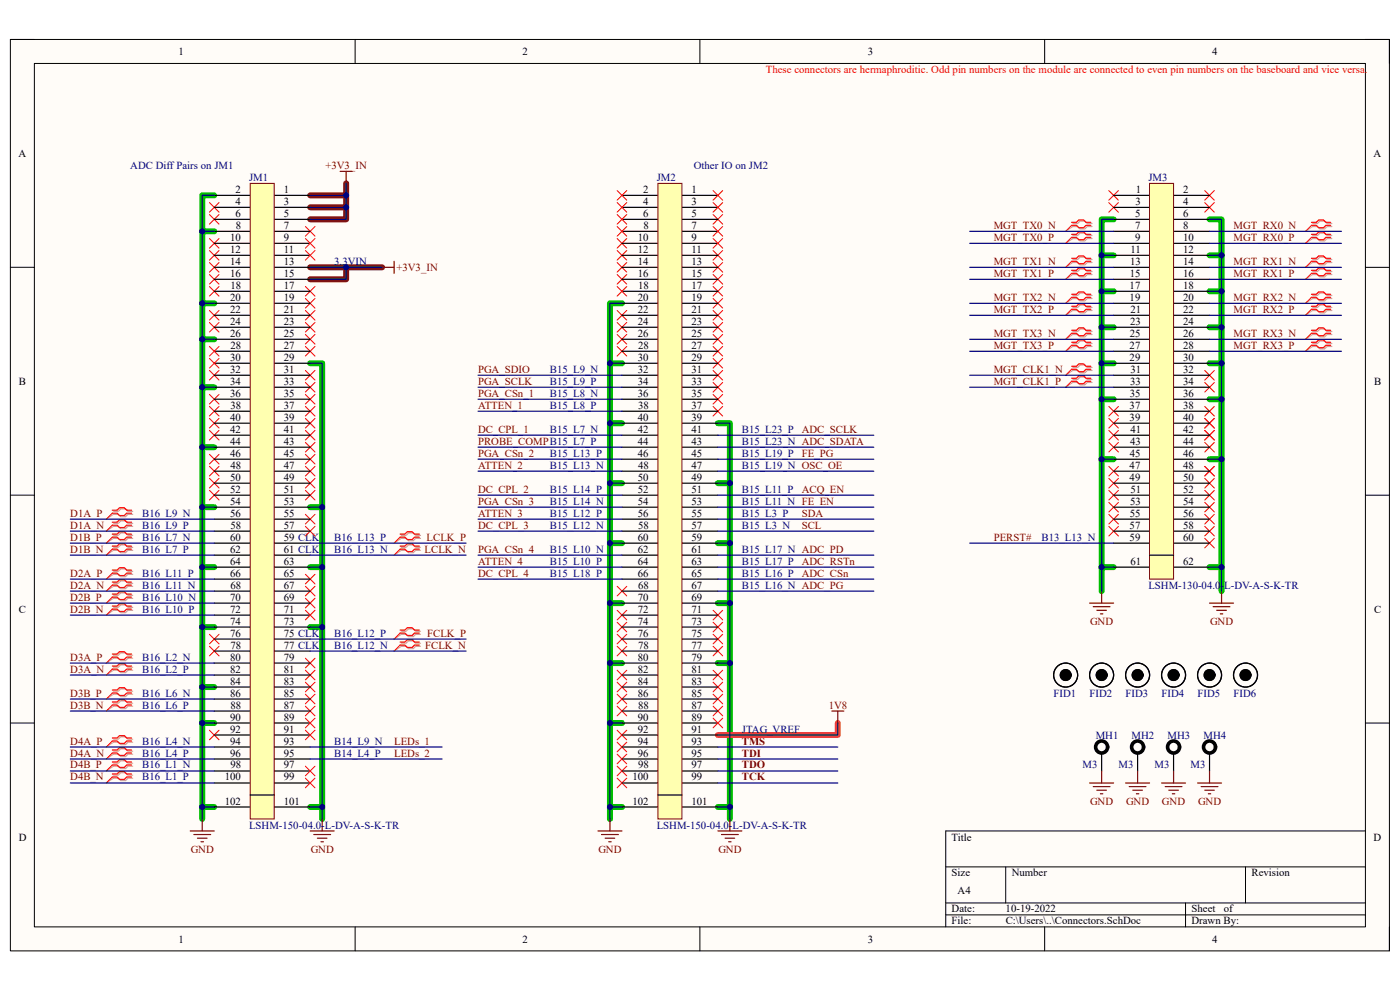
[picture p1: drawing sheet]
<svg xmlns="http://www.w3.org/2000/svg" width="297mm" height="210mm" viewBox="0 0 297 210" stroke-linecap="round" stroke-linejoin="round" font-family="sans-serif">
<defs><g id="words">
<g font-size="2.3">
<text x="37.9" y="11.7">1</text>
<text x="110.9" y="11.7">2</text>
<text x="184.1" y="11.7">3</text>
<text x="257.1" y="11.7">4</text>
<text x="3.9" y="33.3">A</text>
<text x="291.4" y="33.3">A</text>
<text x="50" y="40.9">2</text>
<text x="60.2" y="40.9">1</text>
<text x="136.5" y="40.9">2</text>
<text x="146.7" y="40.9">1</text>
<text x="241" y="40.9">1</text>
<text x="251" y="40.9">2</text>
<text x="50" y="43.5">4</text>
<text x="50" y="46">6</text>
<text x="60.2" y="43.5">3</text>
<text x="60.2" y="46">5</text>
<text x="136.5" y="43.5">4</text>
<text x="136.5" y="46">6</text>
<text x="146.7" y="43.5">3</text>
<text x="146.7" y="46">5</text>
<text x="240.8" y="46">5</text>
<text x="240.9" y="43.5">3</text>
<text x="251" y="43.5">4</text>
<text x="251" y="46">6</text>
<text x="48.8" y="51.1">10</text>
<text x="48.9" y="53.6">12</text>
<text x="50" y="48.6">8</text>
<text x="60.2" y="48.6">7</text>
<text x="60.2" y="51.1">9</text>
<text x="60.2" y="53.6">11</text>
<text x="135.3" y="51.1">10</text>
<text x="135.3" y="53.6">12</text>
<text x="136.5" y="48.6">8</text>
<text x="146.7" y="48.6">7</text>
<text x="146.7" y="51.1">9</text>
<text x="146.7" y="53.6">11</text>
<text x="239.8" y="53.6">11</text>
<text x="240.8" y="48.6">7</text>
<text x="240.8" y="51.1">9</text>
<text x="251" y="48.6">8</text>
<text x="251" y="51.1">10</text>
<text x="251" y="53.6">12</text>
<text x="48.8" y="56.2">14</text>
<text x="48.9" y="58.7">16</text>
<text x="60.2" y="56.2">13</text>
<text x="60.2" y="58.7">15</text>
<text x="135.3" y="56.2">14</text>
<text x="135.3" y="58.7">16</text>
<text x="146.7" y="56.2">13</text>
<text x="146.7" y="58.7">15</text>
<text x="239.7" y="58.7">15</text>
<text x="239.7" y="56.2">13</text>
<text x="251" y="56.2">14</text>
<text x="251" y="58.7">16</text>
<text x="48.8" y="63.8">20</text>
<text x="48.9" y="61.3">18</text>
<text x="60.2" y="61.3">17</text>
<text x="60.2" y="63.8">19</text>
<text x="135.3" y="63.8">20</text>
<text x="135.4" y="61.3">18</text>
<text x="146.7" y="61.3">17</text>
<text x="146.7" y="63.8">19</text>
<text x="239.6" y="61.3">17</text>
<text x="239.6" y="63.8">19</text>
<text x="251" y="61.3">18</text>
<text x="251" y="63.8">20</text>
<text x="48.8" y="68.9">24</text>
<text x="48.9" y="66.4">22</text>
<text x="48.9" y="71.5">26</text>
<text x="60.2" y="66.4">21</text>
<text x="60.2" y="68.9">23</text>
<text x="60.2" y="71.5">25</text>
<text x="135.3" y="66.4">22</text>
<text x="135.3" y="68.9">24</text>
<text x="135.3" y="71.5">26</text>
<text x="146.7" y="66.4">21</text>
<text x="146.7" y="68.9">23</text>
<text x="146.7" y="71.5">25</text>
<text x="239.7" y="71.5">25</text>
<text x="239.7" y="68.9">23</text>
<text x="239.8" y="66.4">21</text>
<text x="251" y="66.4">22</text>
<text x="251" y="68.9">24</text>
<text x="251" y="71.5">26</text>
<text x="48.8" y="76.5">30</text>
<text x="48.9" y="74">28</text>
<text x="60.2" y="74">27</text>
<text x="60.2" y="76.5">29</text>
<text x="135.3" y="76.5">30</text>
<text x="135.4" y="74">28</text>
<text x="146.7" y="74">27</text>
<text x="146.7" y="76.5">29</text>
<text x="239.6" y="74">27</text>
<text x="239.6" y="76.5">29</text>
<text x="251" y="74">28</text>
<text x="251" y="76.5">30</text>
<text x="4" y="81.6">B</text>
<text x="48.8" y="81.6">34</text>
<text x="48.9" y="79.1">32</text>
<text x="60.2" y="79.1">31</text>
<text x="60.2" y="81.6">33</text>
<text x="135.3" y="79.1">32</text>
<text x="135.3" y="81.6">34</text>
<text x="146.7" y="79.1">31</text>
<text x="146.7" y="81.6">33</text>
<text x="239.7" y="81.6">33</text>
<text x="239.8" y="79.1">31</text>
<text x="251" y="79.1">32</text>
<text x="251" y="81.6">34</text>
<text x="291.5" y="81.6">B</text>
<text x="48.8" y="89.3">40</text>
<text x="48.9" y="84.2">36</text>
<text x="48.9" y="86.7">38</text>
<text x="60.2" y="84.2">35</text>
<text x="60.2" y="86.7">37</text>
<text x="60.2" y="89.3">39</text>
<text x="135.3" y="84.2">36</text>
<text x="135.3" y="89.3">40</text>
<text x="135.4" y="86.7">38</text>
<text x="146.7" y="84.2">35</text>
<text x="146.7" y="86.7">37</text>
<text x="146.7" y="89.3">39</text>
<text x="239.6" y="86.7">37</text>
<text x="239.6" y="89.3">39</text>
<text x="239.7" y="84.2">35</text>
<text x="251" y="84.2">36</text>
<text x="251" y="86.7">38</text>
<text x="251" y="89.3">40</text>
<text x="48.8" y="94.4">44</text>
<text x="48.9" y="91.8">42</text>
<text x="60.2" y="91.8">41</text>
<text x="60.2" y="94.4">43</text>
<text x="135.3" y="91.8">42</text>
<text x="135.3" y="94.4">44</text>
<text x="146.7" y="91.8">41</text>
<text x="146.7" y="94.4">43</text>
<text x="239.7" y="94.4">43</text>
<text x="239.8" y="91.8">41</text>
<text x="251" y="91.8">42</text>
<text x="251" y="94.4">44</text>
<text x="48.8" y="102">50</text>
<text x="48.9" y="96.9">46</text>
<text x="48.9" y="99.4">48</text>
<text x="60.2" y="96.9">45</text>
<text x="60.2" y="99.4">47</text>
<text x="60.2" y="102">49</text>
<text x="135.3" y="96.9">46</text>
<text x="135.3" y="102">50</text>
<text x="135.4" y="99.4">48</text>
<text x="146.7" y="96.9">45</text>
<text x="146.7" y="99.4">47</text>
<text x="146.7" y="102">49</text>
<text x="239.6" y="99.4">47</text>
<text x="239.6" y="102">49</text>
<text x="239.7" y="96.9">45</text>
<text x="251" y="96.9">46</text>
<text x="251" y="99.4">48</text>
<text x="251" y="102">50</text>
<text x="48.8" y="107.1">54</text>
<text x="48.9" y="104.5">52</text>
<text x="60.2" y="104.5">51</text>
<text x="60.2" y="107.1">53</text>
<text x="135.3" y="104.5">52</text>
<text x="135.3" y="107.1">54</text>
<text x="146.7" y="104.5">51</text>
<text x="146.7" y="107.1">53</text>
<text x="239.7" y="107.1">53</text>
<text x="239.8" y="104.5">51</text>
<text x="251" y="104.5">52</text>
<text x="251" y="107.1">54</text>
<text x="48.9" y="109.6">56</text>
<text x="48.9" y="112.1">58</text>
<text x="60.2" y="109.6">55</text>
<text x="60.2" y="112.1">57</text>
<text x="135.3" y="109.6">56</text>
<text x="135.4" y="112.1">58</text>
<text x="146.7" y="109.6">55</text>
<text x="146.7" y="112.1">57</text>
<text x="239.6" y="112.1">57</text>
<text x="239.7" y="109.6">55</text>
<text x="251" y="109.6">56</text>
<text x="251" y="112.1">58</text>
<text x="48.8" y="114.7">60</text>
<text x="48.8" y="119.8">64</text>
<text x="48.9" y="117.3">62</text>
<text x="60.2" y="114.7">59 CLK</text>
<text x="60.2" y="117.3">61 CLK</text>
<text x="60.2" y="119.8">63</text>
<text x="135.3" y="114.7">60</text>
<text x="135.3" y="117.3">62</text>
<text x="135.3" y="119.8">64</text>
<text x="146.7" y="114.7">59</text>
<text x="146.7" y="117.3">61</text>
<text x="146.7" y="119.8">63</text>
<text x="239.6" y="114.7">59</text>
<text x="239.8" y="119.8">61</text>
<text x="251" y="114.7">60</text>
<text x="251" y="119.8">62</text>
<text x="48.9" y="122.3">66</text>
<text x="48.9" y="124.9">68</text>
<text x="60.2" y="122.3">65</text>
<text x="60.2" y="124.9">67</text>
<text x="135.3" y="122.3">66</text>
<text x="135.4" y="124.9">68</text>
<text x="146.7" y="122.3">65</text>
<text x="146.7" y="124.9">67</text>
<text x="4" y="130">C</text>
<text x="48.8" y="127.4">70</text>
<text x="48.9" y="130">72</text>
<text x="60.2" y="127.4">69</text>
<text x="60.2" y="130">71</text>
<text x="135.3" y="127.4">70</text>
<text x="135.3" y="130">72</text>
<text x="146.7" y="127.4">69</text>
<text x="146.7" y="130">71</text>
<text x="291.5" y="130">C</text>
<text x="48.8" y="132.5">74</text>
<text x="48.9" y="135">76</text>
<text x="48.9" y="137.6">78</text>
<text x="60.2" y="132.5">73</text>
<text x="60.2" y="135">75 CLK</text>
<text x="60.2" y="137.6">77 CLK</text>
<text x="135.3" y="132.5">74</text>
<text x="135.3" y="135">76</text>
<text x="135.4" y="137.6">78</text>
<text x="146.7" y="132.5">73</text>
<text x="146.7" y="135">75</text>
<text x="146.7" y="137.6">77</text>
<text x="48.8" y="140.1">80</text>
<text x="48.9" y="142.7">82</text>
<text x="60.2" y="140.1">79</text>
<text x="60.2" y="142.7">81</text>
<text x="135.3" y="140.1">80</text>
<text x="135.3" y="142.7">82</text>
<text x="146.7" y="140.1">79</text>
<text x="146.7" y="142.7">81</text>
<text x="48.8" y="145.2">84</text>
<text x="48.9" y="147.8">86</text>
<text x="60.2" y="145.2">83</text>
<text x="60.2" y="147.8">85</text>
<text x="135.3" y="145.2">84</text>
<text x="135.3" y="147.8">86</text>
<text x="146.7" y="145.2">83</text>
<text x="146.7" y="147.8">85</text>
<text x="48.8" y="152.9">90</text>
<text x="48.9" y="155.4">92</text>
<text x="48.9" y="150.3">88</text>
<text x="60.2" y="150.3">87</text>
<text x="60.2" y="152.9">89</text>
<text x="60.2" y="155.4">91</text>
<text x="135.3" y="152.9">90</text>
<text x="135.3" y="155.4">92</text>
<text x="135.4" y="150.3">88</text>
<text x="146.7" y="150.3">87</text>
<text x="146.7" y="152.9">89</text>
<text x="146.7" y="155.4">91</text>
<text x="48.8" y="157.9">94</text>
<text x="48.9" y="160.5">96</text>
<text x="60.2" y="157.9">93</text>
<text x="60.2" y="160.5">95</text>
<text x="135.3" y="157.9">94</text>
<text x="135.3" y="160.5">96</text>
<text x="146.7" y="157.9">93</text>
<text x="146.7" y="160.5">95</text>
<text x="47.7" y="165.6">100</text>
<text x="48.9" y="163">98</text>
<text x="60.2" y="163">97</text>
<text x="60.2" y="165.6">99</text>
<text x="134.2" y="165.6">100</text>
<text x="135.4" y="163">98</text>
<text x="146.7" y="163">97</text>
<text x="146.7" y="165.6">99</text>
<text x="47.7" y="170.7">102</text>
<text x="60.2" y="170.7">101</text>
<text x="134.2" y="170.7">102</text>
<text x="146.7" y="170.7">101</text>
<text x="4" y="178.3">D</text>
<text x="201.9" y="178.3">Title</text>
<text x="291.4" y="178.3">D</text>
<text x="201.9" y="185.9">Size</text>
<text x="214.6" y="185.9">Number</text>
<text x="265.5" y="185.9">Revision</text>
<text x="203.2" y="189.7">A4</text>
<text x="201.9" y="193.5">Date:</text>
<text x="201.9" y="196.1">File:</text>
<text x="213.3" y="193.5">10-19-2022</text>
<text x="213.4" y="196.1">C:\Users\..\Connectors.SchDoc</text>
<text x="252.8" y="193.5">Sheet</text>
<text x="252.8" y="196.1">Drawn By:</text>
<text x="259.6" y="193.5">of</text>
<text x="37.9" y="199.9">1</text>
<text x="110.9" y="199.9">2</text>
<text x="184.1" y="199.9">3</text>
<text x="257.1" y="199.9">4</text>
</g>
<text font-size="2.3" fill="#f00" x="162.5" y="15.5">These connectors are hermaphroditic. Odd pin numbers on the module are connected to even pin numbers on the baseboard and vice versa.</text>
<g font-size="2.3" fill="#000080">
<text x="27.6" y="35.9">ADC Diff Pairs on JM1</text>
<text x="147.2" y="35.9">Other IO on JM2</text>
<text x="52.8" y="38.4">JM1</text>
<text x="139.3" y="38.4">JM2</text>
<text x="243.6" y="38.4">JM3</text>
<text x="70.9" y="56.2">3.3VIN</text>
<text x="116.7" y="79.1">B15_L9_N</text>
<text x="116.7" y="81.6">B15_L9_P</text>
<text x="116.7" y="84.2">B15_L8_N</text>
<text x="116.7" y="86.7">B15_L8_P</text>
<text x="116.7" y="91.8">B15_L7_N</text>
<text x="157.4" y="91.8">B15_L23_P</text>
<text x="157.4" y="94.4">B15_L23_N ADC_SDATA</text>
<text x="116.7" y="96.9">B15_L13_P</text>
<text x="116.7" y="99.4">B15_L13_N</text>
<text x="157.4" y="96.9">B15_L19_P</text>
<text x="157.4" y="99.4">B15_L19_N OSC_OE</text>
<text x="116.7" y="104.5">B15_L14_P</text>
<text x="116.7" y="107.1">B15_L14_N</text>
<text x="157.4" y="104.5">B15_L11_P</text>
<text x="157.4" y="107.1">B15_L11_N FE_EN</text>
<text x="30.2" y="109.6">B16_L9_N</text>
<text x="30.2" y="112.1">B16_L9_P</text>
<text x="116.7" y="109.6">B15_L12_P</text>
<text x="116.7" y="112.1">B15_L12_N</text>
<text x="157.4" y="109.6">B15_L3_P</text>
<text x="157.4" y="112.1">B15_L3_N</text>
<text x="30.2" y="114.7">B16_L7_N</text>
<text x="30.2" y="117.3">B16_L7_P</text>
<text x="70.9" y="114.7">B16_L13_P</text>
<text x="70.9" y="117.3">B16_L13_N</text>
<text x="116.7" y="117.3">B15_L10_N</text>
<text x="116.7" y="119.8">B15_L10_P</text>
<text x="157.4" y="117.3">B15_L17_N ADC_PD</text>
<text x="157.4" y="119.8">B15_L17_P</text>
<text x="221" y="114.7">B13_L13_N</text>
<text x="30.2" y="122.3">B16_L11_P</text>
<text x="30.2" y="124.9">B16_L11_N</text>
<text x="116.7" y="122.3">B15_L18_P</text>
<text x="157.4" y="122.3">B15_L16_P</text>
<text x="157.4" y="124.9">B15_L16_N ADC_PG</text>
<text x="243.6" y="124.9">LSHM-130-04.0-L-DV-A-S-K-TR</text>
<text x="30.2" y="127.4">B16_L10_N</text>
<text x="30.2" y="130">B16_L10_P</text>
<text x="70.9" y="135">B16_L12_P</text>
<text x="70.9" y="137.6">B16_L12_N</text>
<text x="30.2" y="140.1">B16_L2_N</text>
<text x="30.2" y="142.7">B16_L2_P</text>
<text x="30.2" y="147.8">B16_L6_N</text>
<text x="223.5" y="147.8">FID1</text>
<text x="231.1" y="147.8">FID2</text>
<text x="238.8" y="147.8">FID3</text>
<text x="246.4" y="147.8">FID4</text>
<text x="254" y="147.8">FID5</text>
<text x="261.7" y="147.8">FID6</text>
<text x="30.2" y="150.3">B16_L6_P</text>
<text x="157.4" y="155.4">JTAG_VREF</text>
<text x="30.2" y="157.9">B16_L4_N</text>
<text x="30.2" y="160.5">B16_L4_P</text>
<text x="70.9" y="157.9">B14_L9_N</text>
<text x="70.9" y="160.5">B14_L4_P</text>
<text x="232.5" y="156.7">MH1</text>
<text x="240.1" y="156.7">MH2</text>
<text x="247.7" y="156.7">MH3</text>
<text x="255.3" y="156.7">MH4</text>
<text x="30.2" y="163">B16_L1_N</text>
<text x="30.2" y="165.6">B16_L1_P</text>
<text x="229.7" y="163">M3</text>
<text x="237.3" y="163">M3</text>
<text x="244.9" y="163">M3</text>
<text x="252.6" y="163">M3</text>
<text x="52.8" y="175.8">LSHM-150-04.0-L-DV-A-S-K-TR</text>
<text x="139.3" y="175.8">LSHM-150-04.0-L-DV-A-S-K-TR</text>
</g>
<g font-size="2.3" fill="#800000">
<text x="69" y="35.9">+3V3_IN</text>
<text x="210.8" y="48.6">MGT_TX0_N</text>
<text x="210.8" y="51.1">MGT_TX0_P</text>
<text x="261.7" y="48.6">MGT_RX0_N</text>
<text x="261.7" y="51.1">MGT_RX0_P</text>
<text x="84.1" y="57.4">+3V3_IN</text>
<text x="210.8" y="56.2">MGT_TX1_N</text>
<text x="210.8" y="58.7">MGT_TX1_P</text>
<text x="261.7" y="56.2">MGT_RX1_N</text>
<text x="261.7" y="58.7">MGT_RX1_P</text>
<text x="210.8" y="63.8">MGT_TX2_N</text>
<text x="261.7" y="63.8">MGT_RX2_N</text>
<text x="210.8" y="71.5">MGT_TX3_N</text>
<text x="210.8" y="66.4">MGT_TX2_P</text>
<text x="261.7" y="66.4">MGT_RX2_P</text>
<text x="261.7" y="71.5">MGT_RX3_N</text>
<text x="210.8" y="74">MGT_TX3_P</text>
<text x="261.7" y="74">MGT_RX3_P</text>
<text x="101.4" y="79.1">PGA_SDIO</text>
<text x="101.4" y="81.6">PGA_SCLK</text>
<text x="210.8" y="79.1">MGT_CLK1_N</text>
<text x="210.8" y="81.6">MGT_CLK1_P</text>
<text x="101.4" y="84.2">PGA_CSn_1</text>
<text x="101.4" y="86.7">ATTEN_1</text>
<text x="101.4" y="91.8">DC_CPL_1</text>
<text x="101.4" y="94.4">PROBE_COMPB15_L7_P</text>
<text x="170.1" y="91.8">ADC_SCLK</text>
<text x="101.4" y="96.9">PGA_CSn_2</text>
<text x="101.4" y="99.4">ATTEN_2</text>
<text x="170.1" y="96.9">FE_PG</text>
<text x="101.4" y="104.5">DC_CPL_2</text>
<text x="101.4" y="107.1">PGA_CSn_3</text>
<text x="170.1" y="104.5">ACQ_EN</text>
<text x="14.9" y="109.6">D1A_P</text>
<text x="14.9" y="112.1">D1A_N</text>
<text x="101.4" y="109.6">ATTEN_3</text>
<text x="101.4" y="112.1">DC_CPL_3</text>
<text x="170.1" y="109.6">SDA</text>
<text x="170.1" y="112.1">SCL</text>
<text x="14.9" y="114.7">D1B_P</text>
<text x="14.9" y="117.3">D1B_N</text>
<text x="90.1" y="117.3">LCLK_N</text>
<text x="90.5" y="114.7">LCLK_P</text>
<text x="101.4" y="117.3">PGA_CSn_4</text>
<text x="101.4" y="119.8">ATTEN_4</text>
<text x="170.1" y="119.8">ADC_RSTn</text>
<text x="210.8" y="114.7">PERST#</text>
<text x="14.9" y="122.3">D2A_P</text>
<text x="14.9" y="124.9">D2A_N</text>
<text x="101.4" y="122.3">DC_CPL_4</text>
<text x="170.1" y="122.3">ADC_CSn</text>
<text x="14.9" y="127.4">D2B_P</text>
<text x="14.9" y="130">D2B_N</text>
<text x="90.2" y="137.6">FCLK_N</text>
<text x="90.6" y="135">FCLK_P</text>
<text x="231.3" y="132.5">GND</text>
<text x="256.7" y="132.5">GND</text>
<text x="14.9" y="140.1">D3A_P</text>
<text x="14.9" y="142.7">D3A_N</text>
<text x="14.9" y="147.8">D3B_P</text>
<text x="14.9" y="150.3">D3B_N</text>
<text x="175.8" y="150.3">1V8</text>
<text x="14.9" y="157.9">D4A_P</text>
<text x="14.9" y="160.5">D4A_N</text>
<text x="83.6" y="157.9">LEDs_1</text>
<text x="83.6" y="160.5">LEDs_2</text>
<text x="157.4" y="160.5">TDI</text>
<text x="157.4" y="157.9">TMS</text>
<text x="14.9" y="163">D4B_P</text>
<text x="14.9" y="165.6">D4B_N</text>
<text x="157.4" y="165.6">TCK</text>
<text x="157.4" y="163">TDO</text>
<text x="231.3" y="170.7">GND</text>
<text x="238.9" y="170.7">GND</text>
<text x="246.5" y="170.7">GND</text>
<text x="254.2" y="170.7">GND</text>
<text x="40.5" y="180.8">GND</text>
<text x="65.9" y="180.8">GND</text>
<text x="127" y="180.8">GND</text>
<text x="152.4" y="180.8">GND</text>
</g>
</g></defs>
<path d="M2.2 8.4h292.6v193.3h-292.6z" fill-rule="evenodd" fill="#fffcf8"/>
<path d="M2.2 8.4h292.6v193.3h-292.6z" fill="none" stroke="#000" stroke-width=".21"/>
<path d="M7.3 13.5h282.4v183.1h-282.4z" fill-rule="evenodd" fill="#fffcf8"/>
<g fill="none" stroke="#000" stroke-width=".21">
<path d="M2.2 8.4h5.1M7.3 13.5h282.4v183.1h-282.4zM75.3 8.4v5.1M148.5 8.4v5.1M221.6 8.4v5.1M289.7 8.4h5.1v5.1M2.2 56.7h5.1M289.7 56.7h5.1M2.2 105h5.1M289.7 105.1h5.1M2.2 153.4h5.1M289.7 153.4h5.1"/>
<path d="M289.7 176.3h-89.1v20.3M75.3 196.6v5.1M148.5 196.6v5.1M200.6 183.9h89.1M200.6 191.5h89.1M200.6 194.1h89.1M213.4 183.9v7.6M221.6 196.6v5.1M251.5 191.5v5.1M264.2 183.9v7.6M294.8 196.6v5.1"/>
</g>
<g fill="none" stroke="#00be00" stroke-width="1.3">
<path d="M42.9 49.1h2.6M45.5 41.4h-2.6v129.8M233.7 54.2h2.6M236.3 46.5h-2.6v73.8M256.6 46.5h2.6v73.8M256.6 54.2h2.6M42.9 64.3h2.6M42.9 72h2.6M65.8 77.1h2.5v30.5h-2.5M129.4 77.1h2.5M131.9 64.3h-2.5v106.9M233.7 77.1h2.6"/>
<path d="M233.7 61.8h2.6M233.7 69.4h2.6M256.6 77.1h2.6M256.6 61.8h2.6M256.6 69.4h2.6M42.9 82.1h2.6M42.9 94.9h2.6M129.4 89.8h2.5M152.3 89.8h2.5v81.4M233.7 84.7h2.6M233.7 97.4h2.6M256.6 84.7h2.6"/>
<path d="M256.6 97.4h2.6M42.9 107.6h2.6M68.3 107.6v12.7h-2.5M129.4 102.5h2.5M129.4 115.2h2.5M152.3 102.5h2.5M152.3 115.2h2.5M42.9 120.3h2.6M42.9 133h2.6M68.3 120.3v12.7h-2.5M68.3 133v38.2M129.4 127.9h2.5"/>
<path d="M152.3 127.9h2.5M236.3 120.3h-2.6v5.1M256.6 120.3h2.6v5.1M42.9 145.7h2.6M42.9 153.4h2.6M129.4 153.4h2.5M129.4 140.7h2.5M152.3 140.7h2.5M45.5 171.2h-2.6v2.5M65.8 171.2h2.5v2.5M132 171.2h-2.6v2.5M152.3 171.2h2.5v2.5"/>
</g>
<path d="M73.4 38.9v7.6h-7.6M65.8 56.7h15.3M65.8 44h7.6M65.8 41.4h7.6M73.4 56.7v2.6h-7.6" fill="none" stroke="#781915" stroke-width="1.3"/>
<path d="M177.7 153.4v2.5h-25.4" fill="none" stroke="#fd8300" stroke-width="1.3"/>
<g fill="none" stroke="#800000" stroke-width=".25">
<path d="M72.2 36.4h2.5M73.4 36.4v2.5M231.2 127.9h5.1M231.9 128.7h3.6M232.7 129.5h2M233.5 130.2h.5M233.7 125.4v2.5M256.6 127.9h5.1M257.4 128.7h3.5M258.1 129.5h2.1M258.9 130.2h.5M259.2 125.4v2.5"/>
<path d="M40.4 176.3h5.1M41.1 177h3.6M41.9 177.8h2M42.7 178.6h.5M42.9 173.7v2.6M65.8 176.3h5.1M66.6 177h3.5M67.3 177.8h2.1M68.1 178.6h.5M68.3 173.7v2.6M126.9 176.3h5.1M127.6 177h3.6"/>
<path d="M128.4 177.8h2M129.1 178.6h.6M129.4 173.7v2.6M152.3 176.3h5.1M153.1 177h3.5M153.8 177.8h2.1M154.6 178.6h.5M154.8 173.7v2.6"/>
</g>
<g fill="none" stroke="#f00" stroke-width=".21">
<path d="M44.4 43l2.1 2M44.4 45.5l2.1 2M44.4 50.6l2.1 2M44.4 53.1l2.1 2.1M44.4 58.2l2.1 2.1M44.4 55.7l2.1 2M46.5 43l-2.1 2M46.5 45.5l-2.1 2M46.5 50.6l-2.1 2M46.5 53.1l-2.1 2.1M46.5 58.2l-2.1 2.1M46.5 55.7l-2.1 2"/>
<path d="M64.8 48.1l2 2M66.8 48.1l-2 2M130.9 50.6l2.1 2M130.9 55.7l2.1 2M130.9 58.2l2.1 2.1M130.9 53.1l2.1 2.1M133 50.6l-2.1 2M133 55.7l-2.1 2M133 58.2l-2.1 2.1M133 53.1l-2.1 2.1M151.3 45.5l2 2.1M151.3 53.1l2 2.1"/>
<path d="M151.3 55.7l2 2M151.3 58.2l2 2.1M153.3 45.5l-2 2.1M153.3 53.1l-2 2.1M153.3 55.7l-2 2M153.3 58.2l-2 2.1M227.4 47.8l-1.3 1.3M235.2 40.4l2.1 2.1M235.2 43l2.1 2M237.3 40.4l-2.1 2.1M237.3 43l-2.1 2M255.6 40.4l2 2.1"/>
<path d="M255.6 43l2 2M257.6 40.4l-2 2.1M257.6 43l-2 2M44.4 60.8l2.1 2M44.4 65.9l2.1 2M44.4 68.4l2.1 2M44.4 78.6l2.1 2M46.5 60.8l-2.1 2M46.5 65.9l-2.1 2M46.5 68.4l-2.1 2M46.5 78.6l-2.1 2M64.8 60.8l2 2"/>
<path d="M64.8 63.3l2 2.1M64.8 65.9l2 2M64.8 68.4l2 2M64.8 71l2 2M64.8 73.5l2 2M64.8 78.6l2 2M66.8 60.8l-2 2M66.8 63.3l-2 2.1M66.8 65.9l-2 2M66.8 68.4l-2 2M66.8 71l-2 2M66.8 73.5l-2 2"/>
<path d="M66.8 78.6l-2 2M130.9 65.9l2.1 2M130.9 68.4l2.1 2M130.9 71l2.1 2M130.9 73.5l2.1 2M133 65.9l-2.1 2M133 68.4l-2.1 2M133 71l-2.1 2M133 73.5l-2.1 2M151.3 63.3l2 2.1M151.3 76l2 2.1M151.3 60.8l2 2"/>
<path d="M151.3 65.9l2 2M151.3 68.4l2 2M151.3 71l2 2M151.3 73.5l2 2M151.3 78.6l2 2M153.3 63.3l-2 2.1M153.3 76l-2 2.1M153.3 60.8l-2 2M153.3 65.9l-2 2M153.3 68.4l-2 2M153.3 71l-2 2M153.3 73.5l-2 2"/>
<path d="M153.3 78.6l-2 2M255.6 78.6l2 2M257.6 78.6l-2 2M44.4 83.7l2.1 2M44.4 86.2l2.1 2.1M44.4 88.8l2.1 2M44.4 91.3l2.1 2M44.4 96.4l2.1 2M44.4 98.9l2.1 2.1M46.5 83.7l-2.1 2M46.5 86.2l-2.1 2.1M46.5 88.8l-2.1 2"/>
<path d="M46.5 91.3l-2.1 2M46.5 96.4l-2.1 2M46.5 98.9l-2.1 2.1M64.8 88.8l2 2M64.8 98.9l2 2.1M64.8 81.1l2 2.1M64.8 83.7l2 2M64.8 86.2l2 2.1M64.8 91.3l2 2M64.8 93.9l2 2M64.8 96.4l2 2M66.8 81.1l-2 2.1"/>
<path d="M66.8 83.7l-2 2M66.8 88.8l-2 2M66.8 86.2l-2 2.1M66.8 91.3l-2 2M66.8 93.9l-2 2M66.8 96.4l-2 2M66.8 98.9l-2 2.1M151.3 81.1l2 2.1M151.3 83.7l2 2M151.3 86.2l2 2.1M153.3 81.1l-2 2.1M153.3 83.7l-2 2"/>
<path d="M153.3 86.2l-2 2.1M235.2 86.2l2.1 2.1M235.2 88.8l2.1 2M235.2 91.3l2.1 2M235.2 93.9l2.1 2M235.2 98.9l2.1 2.1M237.3 86.2l-2.1 2.1M237.3 88.8l-2.1 2M237.3 91.3l-2.1 2M237.3 93.9l-2.1 2M237.3 98.9l-2.1 2.1M255.6 86.2l2 2.1"/>
<path d="M255.6 88.8l2 2M255.6 91.3l2 2M255.6 93.9l2 2M255.6 98.9l2 2.1M255.6 81.1l2 2.1M257.6 86.2l-2 2.1M257.6 88.8l-2 2M257.6 91.3l-2 2M257.6 93.9l-2 2M257.6 98.9l-2 2.1M257.6 81.1l-2 2.1M44.4 101.5l2.1 2"/>
<path d="M44.4 104l2.1 2.1M46.5 101.5l-2.1 2M46.5 104l-2.1 2.1M64.8 104l2 2.1M64.8 109.1l2 2.1M64.8 101.5l2 2M64.8 111.7l2 2M66.8 101.5l-2 2M66.8 104l-2 2.1M66.8 109.1l-2 2.1M66.8 111.7l-2 2M235.2 109.1l2.1 2.1"/>
<path d="M235.2 101.5l2.1 2M235.2 104l2.1 2.1M235.2 106.6l2.1 2M237.3 109.1l-2.1 2.1M237.3 101.5l-2.1 2M237.3 104l-2.1 2.1M237.3 106.6l-2.1 2M255.6 109.1l2 2.1M255.6 111.7l2 2M255.6 114.2l2 2M255.6 101.5l2 2M255.6 106.6l2 2"/>
<path d="M255.6 104l2 2.1M257.6 109.1l-2 2.1M257.6 111.7l-2 2M257.6 114.2l-2 2M257.6 101.5l-2 2M257.6 106.6l-2 2M257.6 104l-2 2.1M44.4 134.6l2.1 2M44.4 137.1l2.1 2M46.5 134.6l-2.1 2M46.5 137.1l-2.1 2M64.8 139.6l2 2.1"/>
<path d="M64.8 121.8l2 2.1M64.8 124.4l2 2M64.8 126.9l2 2.1M66.8 139.6l-2 2.1M66.8 121.8l-2 2.1M66.8 124.4l-2 2M66.8 126.9l-2 2.1M130.9 124.4l2.1 2M130.9 129.5l2.1 2M130.9 132l2.1 2M130.9 134.6l2.1 2M130.9 137.1l2.1 2"/>
<path d="M133 124.4l-2.1 2M133 129.5l-2.1 2M133 132l-2.1 2M133 134.6l-2.1 2M133 137.1l-2.1 2M151.3 129.5l2 2M151.3 132l2 2M151.3 134.6l2 2M151.3 137.1l2 2M153.3 129.5l-2 2M153.3 134.6l-2 2M153.3 137.1l-2 2"/>
<path d="M153.3 132l-2 2M44.4 154.9l2.1 2M46.5 154.9l-2.1 2M64.8 142.2l2 2M64.8 144.7l2 2.1M64.8 147.3l2 2M64.8 149.8l2 2.1M66.8 142.2l-2 2M66.8 144.7l-2 2.1M66.8 147.3l-2 2M66.8 149.8l-2 2.1M130.9 142.2l2.1 2"/>
<path d="M130.9 144.7l2.1 2.1M130.9 147.3l2.1 2M130.9 149.8l2.1 2.1M130.9 154.9l2.1 2M130.9 157.5l2.1 2M130.9 160l2.1 2M133 142.2l-2.1 2M133 144.7l-2.1 2.1M133 147.3l-2.1 2M133 149.8l-2.1 2.1M133 154.9l-2.1 2M133 157.5l-2.1 2"/>
<path d="M133 160l-2.1 2M151.3 142.2l2 2M151.3 144.7l2 2.1M151.3 147.3l2 2M151.3 149.8l2 2.1M153.3 144.7l-2 2.1M153.3 147.3l-2 2M153.3 142.2l-2 2M153.3 149.8l-2 2.1M130.9 162.5l2.1 2.1M130.9 165.1l2.1 2M133 165.1l-2.1 2"/>
<path d="M133 162.5l-2.1 2.1"/>
</g>
<path d="M227.6 47.4h1l.5-.5h1l.6 .5h1M227.6 48.1h1l.5 .5h1l.6-.5h1" fill="none" stroke="#d0a19e" stroke-width=".25"/>
<path d="M227.6 48.1l-1.5 1" fill="none" stroke="#d0a19e" stroke-width=".21"/>
<path d="M227.4 47.2h1l.5-.5h1l.5 .5h1M227.4 47.8h1l.5 .5h1l.5-.5h1" fill="none" stroke="#f00" stroke-width=".25"/>
<g fill="none" stroke="#000" stroke-width=".25">
<path d="M45.5 41.4h7.6M45.5 44h7.6M45.5 46.5h7.6M45.5 49.1h7.6M45.5 51.6h7.6M45.5 54.2h7.6M45.5 56.7h7.6M45.5 59.3h7.6M58.2 41.4h7.6M58.2 44h7.6M58.2 46.5h7.6M58.2 49.1h7.6"/>
<path d="M58.2 51.6h7.6M58.2 54.2h7.6M58.2 56.7h7.6M58.2 59.3h7.6M45.5 61.8h7.6M45.5 64.3h7.6M45.5 66.9h7.6M45.5 69.4h7.6M45.5 72h7.6M45.5 74.5h7.6M45.5 77.1h7.6M45.5 79.6h7.6"/>
<path d="M58.2 61.8h7.6M58.2 64.3h7.6M58.2 66.9h7.6M58.2 69.4h7.6M58.2 72h7.6M58.2 74.5h7.6M58.2 77.1h7.6M58.2 79.6h7.6M45.5 82.1h7.6M45.5 84.7h7.6M45.5 87.2h7.6M45.5 89.8h7.6"/>
<path d="M45.5 92.3h7.6M45.5 94.9h7.6M45.5 97.4h7.6M45.5 100h7.6M58.2 82.1h7.6M58.2 84.7h7.6M58.2 87.2h7.6M58.2 89.8h7.6M58.2 92.3h7.6M58.2 94.9h7.6M58.2 97.4h7.6M58.2 100h7.6"/>
<path d="M45.5 102.5h7.6M45.5 105h7.6M45.5 107.6h7.6M45.5 110.1h7.6M45.5 112.7h7.6M45.5 115.2h7.6M45.5 117.8h7.6M58.2 102.5h7.6M58.2 105h7.6M58.2 107.6h7.6M58.2 110.1h7.6M58.2 112.7h7.6"/>
<path d="M58.2 115.2h7.6M58.2 117.8h7.6M45.5 120.3h7.6M45.5 122.9h7.6M45.5 125.4h7.6M45.5 127.9h7.6M45.5 130.5h7.6M45.5 133h7.6M45.5 135.6h7.6M45.5 138.1h7.6M58.2 120.3h7.6M58.2 122.9h7.6"/>
<path d="M58.2 125.4h7.6M58.2 127.9h7.6M58.2 130.5h7.6M58.2 133h7.6M58.2 135.6h7.6M58.2 138.1h7.6M45.5 140.7h7.6M45.5 143.2h7.6M45.5 145.7h7.6M45.5 148.3h7.6M45.5 150.8h7.6M45.5 153.4h7.6"/>
<path d="M45.5 155.9h7.6M45.5 158.5h7.6M58.2 140.7h7.6M58.2 143.2h7.6M58.2 145.7h7.6M58.2 148.3h7.6M58.2 150.8h7.6M58.2 153.4h7.6M58.2 155.9h7.6M58.2 158.5h7.6M45.5 161h7.6M45.5 163.6h7.6"/>
<path d="M45.5 166.1h7.6M45.5 171.2h7.6M58.2 161h7.6M58.2 163.6h7.6M58.2 166.1h7.6M58.2 171.2h7.6"/>
</g>
<path d="M53.1 38.9h5.1v134.8h-5.1z" fill-rule="evenodd" fill="#ffffb0"/>
<path d="M53.1 38.9h5.1v134.8h-5.1z" fill="none" stroke="#800000" stroke-width=".21"/>
<g fill="none" stroke="#000" stroke-width=".25">
<path d="M131.9 41.4h7.7M131.9 44h7.7M131.9 46.5h7.7M131.9 49.1h7.7M131.9 51.6h7.7M131.9 54.2h7.7M131.9 56.7h7.7M131.9 59.3h7.7M144.7 41.4h7.6M144.7 44h7.6M144.7 46.5h7.6M144.7 49.1h7.6"/>
<path d="M144.7 51.6h7.6M144.7 54.2h7.6M144.7 56.7h7.6M144.7 59.3h7.6M131.9 61.8h7.7M131.9 64.3h7.7M131.9 66.9h7.7M131.9 69.4h7.7M131.9 72h7.7M131.9 74.5h7.7M131.9 77.1h7.7M131.9 79.6h7.7"/>
<path d="M144.7 61.8h7.6M144.7 64.3h7.6M144.7 66.9h7.6M144.7 69.4h7.6M144.7 72h7.6M144.7 74.5h7.6M144.7 77.1h7.6M144.7 79.6h7.6M131.9 82.1h7.7M131.9 84.7h7.7M131.9 87.2h7.7M131.9 89.8h7.7"/>
<path d="M131.9 92.3h7.7M131.9 94.9h7.7M131.9 97.4h7.7M131.9 100h7.7M144.7 82.1h7.6M144.7 84.7h7.6M144.7 87.2h7.6M144.7 89.8h7.6M144.7 92.3h7.6M144.7 94.9h7.6M144.7 97.4h7.6M144.7 100h7.6"/>
<path d="M131.9 102.5h7.7M131.9 105h7.7M131.9 107.6h7.7M131.9 110.1h7.7M131.9 112.7h7.7M131.9 115.2h7.7M131.9 117.8h7.7M144.7 102.5h7.6M144.7 105h7.6M144.7 107.6h7.6M144.7 110.1h7.6M144.7 112.7h7.6"/>
<path d="M144.7 115.2h7.6M144.7 117.8h7.6M131.9 120.3h7.7M131.9 122.9h7.7M131.9 125.4h7.7M131.9 127.9h7.7M131.9 130.5h7.7M131.9 133h7.7M131.9 135.6h7.7M131.9 138.1h7.7M144.7 120.3h7.6M144.7 122.9h7.6"/>
<path d="M144.7 125.4h7.6M144.7 127.9h7.6M144.7 130.5h7.6M144.7 133h7.6M144.7 135.6h7.6M144.7 138.1h7.6M131.9 140.7h7.7M131.9 143.2h7.7M131.9 145.7h7.7M131.9 148.3h7.7M131.9 150.8h7.7M131.9 153.4h7.7"/>
<path d="M131.9 155.9h7.7M131.9 158.5h7.7M144.7 140.7h7.6M144.7 143.2h7.6M144.7 145.7h7.6M144.7 148.3h7.6M144.7 150.8h7.6M144.7 153.4h7.6M144.7 155.9h7.6M144.7 158.5h7.6M53.1 168.6h5.1M131.9 161h7.7"/>
<path d="M131.9 163.6h7.7M131.9 166.1h7.7M131.9 171.2h7.7M144.7 161h7.6M144.7 163.6h7.6M144.7 166.1h7.6M144.7 171.2h7.6"/>
</g>
<path d="M139.6 38.9h5.1v134.8h-5.1z" fill-rule="evenodd" fill="#ffffb0"/>
<path d="M139.6 38.9h5.1v134.8h-5.1z" fill="none" stroke="#800000" stroke-width=".21"/>
<g fill="none" stroke="#000" stroke-width=".25">
<path d="M236.3 41.4h7.6M236.3 44h7.6M236.3 46.5h7.6M236.3 49.1h7.6M236.3 51.6h7.6M236.3 54.2h7.6M236.3 56.7h7.6M236.3 59.3h7.6M249 41.4h7.6M249 44h7.6M249 46.5h7.6M249 49.1h7.6"/>
<path d="M249 51.6h7.6M249 54.2h7.6M249 56.7h7.6M249 59.3h7.6M236.3 61.8h7.6M236.3 64.3h7.6M236.3 66.9h7.6M236.3 69.4h7.6M236.3 72h7.6M236.3 74.5h7.6M236.3 77.1h7.6M236.3 79.6h7.6"/>
<path d="M249 61.8h7.6M249 64.3h7.6M249 66.9h7.6M249 69.4h7.6M249 72h7.6M249 74.5h7.6M249 77.1h7.6M249 79.6h7.6M236.3 82.1h7.6M236.3 84.7h7.6M236.3 87.2h7.6M236.3 89.8h7.6"/>
<path d="M236.3 92.3h7.6M236.3 94.9h7.6M236.3 97.4h7.6M236.3 100h7.6M249 82.1h7.6M249 84.7h7.6M249 87.2h7.6M249 89.8h7.6M249 92.3h7.6M249 94.9h7.6M249 97.4h7.6M249 100h7.6"/>
<path d="M236.3 102.5h7.6M236.3 105.1h7.6M236.3 107.6h7.6M236.3 110.1h7.6M236.3 112.7h7.6M236.3 115.2h7.6M249 102.5h7.6M249 105.1h7.6M249 107.6h7.6M249 110.1h7.6M249 112.7h7.6M249 115.2h7.6"/>
<path d="M236.3 120.3h7.6M249 120.3h7.6M233.7 159.7v3.9M241.3 159.7v3.9M249 159.7v3.9M256.6 159.7v3.9M139.6 168.6h5.1"/>
</g>
<g fill="none" stroke="#f00" stroke-width=".21">
<path d="M64.8 50.6l2 2M64.8 53.1l2 2.1M66.8 50.6l-2 2M66.8 53.1l-2 2.1M255.6 88.8l2 2M255.6 91.3l2 2M255.6 98.9l2 2.1M257.6 91.3l-2 2M257.6 88.8l-2 2M257.6 98.9l-2 2.1M235.2 111.7l2.1 2M237.3 111.7l-2.1 2"/>
<path d="M64.8 129.5l2 2M66.8 129.5l-2 2M64.8 154.9l2 2M66.8 154.9l-2 2M151.3 152.4l2 2M153.3 152.4l-2 2"/>
</g>
<g fill="none" stroke="#000" stroke-width=".76">
<circle cx="233.7" cy="158.5" r="1.27"/>
<circle cx="241.3" cy="158.5" r="1.27"/>
<circle cx="249" cy="158.5" r="1.27"/>
<circle cx="256.6" cy="158.5" r="1.27"/>
</g>
<g fill="none" stroke="#800000" stroke-width=".25">
<path d="M231.2 166.1h5.1M231.9 166.9h3.6M232.7 167.6h2M233.5 168.4h.5M233.7 163.6v2.5M238.8 166.1h5.1M239.6 166.9h3.5M240.3 167.6h2.1M241.1 168.4h.5M241.3 163.6v2.5M246.4 166.1h5.1M247.2 166.9h3.6"/>
<path d="M248 167.6h2M248.7 168.4h.5M249 163.6v2.5M254.1 166.1h5.1M254.8 166.9h3.6M255.6 167.6h2M256.3 168.4h.6M256.6 163.6v2.5"/>
</g>
<path d="M243.9 38.9h5.1v84h-5.1z" fill-rule="evenodd" fill="#ffffb0"/>
<path d="M243.9 38.9h5.1v84h-5.1z" fill="none" stroke="#800000" stroke-width=".21"/>
<g fill="none" stroke="#000" stroke-width=".25">
<path d="M243.9 117.8h5.1"/>
<circle cx="226.1" cy="143.2" r="2.54"/>
<circle cx="233.7" cy="143.2" r="2.54"/>
<circle cx="241.3" cy="143.2" r="2.54"/>
<circle cx="249" cy="143.2" r="2.54"/>
<circle cx="256.6" cy="143.2" r="2.54"/>
<circle cx="264.2" cy="143.2" r="2.54"/>
</g>
<g fill="none" stroke="#f00" stroke-width=".21">
<path d="M130.9 48.1l2.1 2M130.9 45.5l2.1 2.1M130.9 43l2.1 2M130.9 40.4l2.1 2.1M133 48.1l-2.1 2M133 45.5l-2.1 2.1M133 43l-2.1 2M133 40.4l-2.1 2.1M151.3 48.1l2 2M151.3 50.6l2 2M151.3 40.4l2 2.1M151.3 43l2 2"/>
<path d="M153.3 40.4l-2 2.1M153.3 48.1l-2 2M153.3 50.6l-2 2M153.3 43l-2 2M227.4 50.4l-1.3 1.2M227.4 55.4l-1.3 1.3M227.4 58l-1.3 1.3M278.2 47.8l-1.2 1.3M278.2 50.4l-1.2 1.2M278.2 55.4l-1.2 1.3M278.2 58l-1.2 1.3M44.4 73.5l2.1 2"/>
<path d="M44.4 76l2.1 2.1M46.5 73.5l-2.1 2M46.5 76l-2.1 2.1M130.9 60.8l2.1 2M133 60.8l-2.1 2M227.4 63.1l-1.3 1.2M227.4 65.6l-1.3 1.3M227.4 70.7l-1.3 1.3M227.4 73.2l-1.3 1.3M227.4 78.3l-1.3 1.3M278.2 63.1l-1.2 1.2M278.2 65.6l-1.2 1.3"/>
<path d="M278.2 70.7l-1.2 1.3M278.2 73.2l-1.2 1.3M227.4 80.9l-1.3 1.2M23.8 108.9l-1.2 1.2M23.8 111.4l-1.2 1.3M23.8 114l-1.2 1.2M23.8 116.5l-1.2 1.3M84.9 114l-1.3 1.2M84.9 116.5l-1.3 1.3M23.8 121.6l-1.2 1.3M23.8 124.1l-1.2 1.3M23.8 126.7l-1.2 1.2"/>
<path d="M23.8 129.2l-1.2 1.3M23.8 139.4l-1.2 1.3M84.9 134.3l-1.3 1.3M84.9 136.8l-1.3 1.3M23.8 141.9l-1.2 1.3M23.8 147l-1.2 1.3M23.8 149.6l-1.2 1.2M23.8 157.2l-1.2 1.3M23.8 159.7l-1.2 1.3M64.8 152.4l2 2M66.8 152.4l-2 2M23.8 162.3l-1.2 1.3"/>
<path d="M23.8 164.8l-1.2 1.3M64.8 162.5l2 2.1M64.8 165.1l2 2M66.8 162.5l-2 2.1M66.8 165.1l-2 2"/>
</g>
<path d="M81.1 56.7h2.5M83.6 55.4v2.6M176.5 150.8h2.5M177.7 150.8v2.6" fill="none" stroke="#800000" stroke-width=".25"/>
<g fill="none" stroke="#d0a19e" stroke-width=".25">
<path d="M227.6 50h1l.5-.5h1l.6 .5h1M227.6 50.6h1l.5 .5h1l.6-.5h1M227.6 55.1h1l.5-.6h1l.6 .6h1M227.6 55.7h1l.5 .5h1l.6-.5h1M227.6 57.6h1l.5-.5h1l.6 .5h1M227.6 58.2h1l.5 .5h1l.6-.5h1M278.5 47.4h1l.5-.5h1l.5 .5h1.1M278.5 48.1h1l.5 .5h1l.5-.5h1.1M278.5 50h1l.5-.5h1l.5 .5h1.1M278.5 50.6h1l.5 .5h1l.5-.5h1.1M278.5 55.1h1l.5-.6h1l.5 .6h1.1M278.5 55.7h1l.5 .5h1l.5-.5h1.1"/>
<path d="M278.5 57.6h1l.5-.5h1l.5 .5h1.1M278.5 58.2h1l.5 .5h1l.5-.5h1.1M227.6 62.7h1l.5-.5h1l.6 .5h1M227.6 63.3h1l.5 .5h1l.6-.5h1M227.6 65.2h1l.5-.5h1l.6 .5h1M227.6 65.9h1l.5 .5h1l.6-.5h1M227.6 70.3h1l.5-.5h1l.6 .5h1M227.6 71h1l.5 .5h1l.6-.5h1M227.6 72.9h1l.5-.5h1l.6 .5h1M227.6 73.5h1l.5 .5h1l.6-.5h1M227.6 78h1l.5-.6h1l.6 .6h1M227.6 78.6h1l.5 .5h1l.6-.5h1"/>
<path d="M278.5 62.7h1l.5-.5h1l.5 .5h1.1M278.5 63.3h1l.5 .5h1l.5-.5h1.1M278.5 65.2h1l.5-.5h1l.5 .5h1.1M278.5 65.9h1l.5 .5h1l.5-.5h1.1M278.5 70.3h1l.5-.5h1l.5 .5h1.1M278.5 71h1l.5 .5h1l.5-.5h1.1M278.5 72.9h1l.5-.5h1l.5 .5h1.1M278.5 73.5h1l.5 .5h1l.5-.5h1.1M227.6 80.5h1l.5-.5h1l.6 .5h1M227.6 81.1h1l.5 .5h1l.6-.5h1M24.1 108.5h1l.5-.5h1l.5 .5h1.1M24.1 109.1h1l.5 .5h1l.5-.5h1.1"/>
<path d="M24.1 111h1l.5-.5h1l.5 .5h1.1M24.1 111.7h1l.5 .5h1l.5-.5h1.1M24.1 113.6h1l.5-.5h1l.5 .5h1.1M24.1 114.2h1l.5 .5h1l.5-.5h1.1M24.1 116.1h1l.5-.5h1l.5 .5h1.1M24.1 116.7h1l.5 .6h1l.5-.6h1.1M85.1 113.6h1.1l.5-.5h1l.5 .5h1M85.1 114.2h1.1l.5 .5h1l.5-.5h1M85.1 116.1h1.1l.5-.5h1l.5 .5h1M85.1 116.7h1.1l.5 .6h1l.5-.6h1M24.1 121.2h1l.5-.5h1l.5 .5h1.1M24.1 121.8h1l.5 .5h1l.5-.5h1.1"/>
<path d="M24.1 123.7h1l.5-.5h1l.5 .5h1.1M24.1 124.4h1l.5 .5h1l.5-.5h1.1M24.1 126.3h1l.5-.5h1l.5 .5h1.1M24.1 126.9h1l.5 .5h1l.5-.5h1.1M24.1 128.8h1l.5-.5h1l.5 .5h1.1M24.1 129.5h1l.5 .5h1l.5-.5h1.1M24.1 139h1l.5-.5h1l.5 .5h1.1M24.1 139.6h1l.5 .5h1l.5-.5h1.1M85.1 133.9h1.1l.5-.5h1l.5 .5h1M85.1 134.6h1.1l.5 .5h1l.5-.5h1M85.1 136.5h1.1l.5-.5h1l.5 .5h1M85.1 137.1h1.1l.5 .5h1l.5-.5h1"/>
<path d="M24.1 141.6h1l.5-.6h1l.5 .6h1.1M24.1 142.2h1l.5 .5h1l.5-.5h1.1M24.1 146.6h1l.5-.5h1l.5 .5h1.1M24.1 147.3h1l.5 .5h1l.5-.5h1.1M24.1 149.2h1l.5-.5h1l.5 .5h1.1M24.1 149.8h1l.5 .5h1l.5-.5h1.1M24.1 156.8h1l.5-.5h1l.5 .5h1.1M24.1 157.5h1l.5 .5h1l.5-.5h1.1M24.1 159.4h1l.5-.5h1l.5 .5h1.1M24.1 160h1l.5 .5h1l.5-.5h1.1M24.1 161.9h1l.5-.5h1l.5 .5h1.1M24.1 162.5h1l.5 .5h1l.5-.5h1.1"/>
<path d="M24.1 164.4h1l.5-.5h1l.5 .5h1.1M24.1 165.1h1l.5 .5h1l.5-.5h1.1"/>
</g>
<g fill="none" stroke="#d0a19e" stroke-width=".21">
<path d="M227.6 50.6l-1.5 1M227.6 55.7l-1.5 1M227.6 58.2l-1.5 1.1M278.5 48.1l-1.5 1M278.5 50.6l-1.5 1M278.5 55.7l-1.5 1M278.5 58.2l-1.5 1.1M227.6 63.3l-1.5 1M227.6 65.9l-1.5 1M227.6 71l-1.5 1M227.6 73.5l-1.5 1M227.6 78.6l-1.5 1"/>
<path d="M278.5 63.3l-1.5 1M278.5 65.9l-1.5 1M278.5 71l-1.5 1M278.5 73.5l-1.5 1M227.6 81.1l-1.5 1M24.1 109.1l-1.5 1M24.1 111.7l-1.5 1M24.1 114.2l-1.5 1M24.1 116.7l-1.5 1.1M85.1 114.2l-1.5 1M85.1 116.7l-1.5 1.1M24.1 121.8l-1.5 1.1"/>
<path d="M24.1 124.4l-1.5 1M24.1 126.9l-1.5 1M24.1 129.5l-1.5 1M24.1 139.6l-1.5 1.1M85.1 134.6l-1.5 1M85.1 137.1l-1.5 1M24.1 142.2l-1.5 1M24.1 147.3l-1.5 1M24.1 149.8l-1.5 1M24.1 157.5l-1.5 1M24.1 160l-1.5 1M24.1 162.5l-1.5 1.1"/>
<path d="M24.1 165.1l-1.5 1"/>
</g>
<g fill="none" stroke="#f00" stroke-width=".25">
<path d="M227.4 49.7h1l.5-.5h1l.5 .5h1M227.4 50.4h1l.5 .5h1l.5-.5h1M227.4 54.8h1l.5-.5h1l.5 .5h1M227.4 55.4h1l.5 .5h1l.5-.5h1M227.4 57.4h1l.5-.6h1l.5 .6h1M227.4 58h1l.5 .5h1l.5-.5h1M278.2 47.2h1.1l.5-.5h1l.5 .5h1M278.2 47.8h1.1l.5 .5h1l.5-.5h1M278.2 49.7h1.1l.5-.5h1l.5 .5h1M278.2 50.4h1.1l.5 .5h1l.5-.5h1M278.2 54.8h1.1l.5-.5h1l.5 .5h1M278.2 55.4h1.1l.5 .5h1l.5-.5h1"/>
<path d="M278.2 57.4h1.1l.5-.6h1l.5 .6h1M278.2 58h1.1l.5 .5h1l.5-.5h1M227.4 62.4h1l.5-.5h1l.5 .5h1M227.4 63.1h1l.5 .5h1l.5-.5h1M227.4 65h1l.5-.5h1l.5 .5h1M227.4 65.6h1l.5 .5h1l.5-.5h1M227.4 70.1h1l.5-.5h1l.5 .5h1M227.4 70.7h1l.5 .5h1l.5-.5h1M227.4 72.6h1l.5-.5h1l.5 .5h1M227.4 73.2h1l.5 .6h1l.5-.6h1M227.4 77.7h1l.5-.5h1l.5 .5h1M227.4 78.3h1l.5 .5h1l.5-.5h1"/>
<path d="M278.2 62.4h1.1l.5-.5h1l.5 .5h1M278.2 63.1h1.1l.5 .5h1l.5-.5h1M278.2 65h1.1l.5-.5h1l.5 .5h1M278.2 65.6h1.1l.5 .5h1l.5-.5h1M278.2 70.1h1.1l.5-.5h1l.5 .5h1M278.2 70.7h1.1l.5 .5h1l.5-.5h1M278.2 72.6h1.1l.5-.5h1l.5 .5h1M278.2 73.2h1.1l.5 .6h1l.5-.6h1M227.4 80.2h1l.5-.5h1l.5 .5h1M227.4 80.9h1l.5 .5h1l.5-.5h1M23.8 108.2h1l.6-.5h1l.5 .5h1M23.8 108.9h1l.6 .5h1l.5-.5h1"/>
<path d="M23.8 110.8h1l.6-.5h1l.5 .5h1M23.8 111.4h1l.6 .5h1l.5-.5h1M23.8 113.3h1l.6-.5h1l.5 .5h1M23.8 114h1l.6 .5h1l.5-.5h1M23.8 115.9h1l.6-.6h1l.5 .6h1M23.8 116.5h1l.6 .5h1l.5-.5h1M84.9 113.3h1l.5-.5h1l.5 .5h1.1M84.9 114h1l.5 .5h1l.5-.5h1.1M84.9 115.9h1l.5-.6h1l.5 .6h1.1M84.9 116.5h1l.5 .5h1l.5-.5h1.1M23.8 120.9h1l.6-.5h1l.5 .5h1M23.8 121.6h1l.6 .5h1l.5-.5h1"/>
<path d="M23.8 123.5h1l.6-.5h1l.5 .5h1M23.8 124.1h1l.6 .5h1l.5-.5h1M23.8 126h1l.6-.5h1l.5 .5h1M23.8 126.7h1l.6 .5h1l.5-.5h1M23.8 128.6h1l.6-.5h1l.5 .5h1M23.8 129.2h1l.6 .5h1l.5-.5h1M23.8 138.8h1l.6-.6h1l.5 .6h1M23.8 139.4h1l.6 .5h1l.5-.5h1M84.9 133.7h1l.5-.5h1l.5 .5h1.1M84.9 134.3h1l.5 .5h1l.5-.5h1.1M84.9 136.2h1l.5-.5h1l.5 .5h1.1M84.9 136.8h1l.5 .6h1l.5-.6h1.1"/>
<path d="M23.8 141.3h1l.6-.5h1l.5 .5h1M23.8 141.9h1l.6 .5h1l.5-.5h1M23.8 146.4h1l.6-.5h1l.5 .5h1M23.8 147h1l.6 .5h1l.5-.5h1M23.8 148.9h1l.6-.5h1l.5 .5h1M23.8 149.6h1l.6 .5h1l.5-.5h1M23.8 156.6h1l.6-.5h1l.5 .5h1M23.8 157.2h1l.6 .5h1l.5-.5h1M23.8 159.1h1l.6-.5h1l.5 .5h1M23.8 159.7h1l.6 .5h1l.5-.5h1M23.8 161.6h1l.6-.5h1l.5 .5h1M23.8 162.3h1l.6 .5h1l.5-.5h1"/>
<path d="M23.8 164.2h1l.6-.5h1l.5 .5h1M23.8 164.8h1l.6 .5h1l.5-.5h1"/>
</g>
<g fill="none" stroke="#000" stroke-width="1.3">
<circle cx="226.1" cy="143.2" r=".64"/>
<circle cx="233.7" cy="143.2" r=".64"/>
<circle cx="241.3" cy="143.2" r=".64"/>
<circle cx="249" cy="143.2" r=".64"/>
<circle cx="256.6" cy="143.2" r=".64"/>
<circle cx="264.2" cy="143.2" r=".64"/>
</g>
<path d="M45.5 171.2h-2.6v2.5" fill="none" stroke="#000080" stroke-width=".25"/>
<circle cx="42.9" cy="171.2" r=".51" fill="#000080"/>
<circle cx="42.9" cy="171.2" r=".51" fill="none" stroke="#000080" stroke-width=".21"/>
<path d="M65.8 171.2h2.5v2.5" fill="none" stroke="#000080" stroke-width=".25"/>
<circle cx="68.4" cy="171.2" r=".51" fill="#000080"/>
<circle cx="68.4" cy="171.2" r=".51" fill="none" stroke="#000080" stroke-width=".21"/>
<path d="M132 171.2h-2.6v2.5" fill="none" stroke="#000080" stroke-width=".25"/>
<circle cx="129.4" cy="171.2" r=".51" fill="#000080"/>
<circle cx="129.4" cy="171.2" r=".51" fill="none" stroke="#000080" stroke-width=".21"/>
<path d="M152.3 171.2h2.5v2.5" fill="none" stroke="#000080" stroke-width=".25"/>
<circle cx="154.8" cy="171.2" r=".51" fill="#000080"/>
<circle cx="154.8" cy="171.2" r=".51" fill="none" stroke="#000080" stroke-width=".21"/>
<path d="M256.6 120.3h2.6v5.1" fill="none" stroke="#000080" stroke-width=".25"/>
<circle cx="259.1" cy="120.3" r=".51" fill="#000080"/>
<circle cx="259.1" cy="120.3" r=".51" fill="none" stroke="#000080" stroke-width=".21"/>
<path d="M236.3 120.3h-2.6v5.1" fill="none" stroke="#000080" stroke-width=".25"/>
<circle cx="233.7" cy="120.3" r=".51" fill="#000080"/>
<circle cx="233.7" cy="120.3" r=".51" fill="none" stroke="#000080" stroke-width=".21"/>
<path d="M42.9 49.1h2.6" fill="none" stroke="#000080" stroke-width=".25"/>
<circle cx="42.9" cy="49.1" r=".51" fill="#000080"/>
<circle cx="42.9" cy="49.1" r=".51" fill="none" stroke="#000080" stroke-width=".21"/>
<path d="M42.9 64.3h2.6" fill="none" stroke="#000080" stroke-width=".25"/>
<circle cx="42.9" cy="64.3" r=".51" fill="#000080"/>
<circle cx="42.9" cy="64.3" r=".51" fill="none" stroke="#000080" stroke-width=".21"/>
<path d="M42.9 72h2.6" fill="none" stroke="#000080" stroke-width=".25"/>
<circle cx="42.9" cy="72" r=".51" fill="#000080"/>
<circle cx="42.9" cy="72" r=".51" fill="none" stroke="#000080" stroke-width=".21"/>
<path d="M42.9 82.1h2.6" fill="none" stroke="#000080" stroke-width=".25"/>
<circle cx="42.9" cy="82.1" r=".51" fill="#000080"/>
<circle cx="42.9" cy="82.1" r=".51" fill="none" stroke="#000080" stroke-width=".21"/>
<path d="M42.9 94.9h2.6" fill="none" stroke="#000080" stroke-width=".25"/>
<circle cx="42.9" cy="94.9" r=".51" fill="#000080"/>
<circle cx="42.9" cy="94.9" r=".51" fill="none" stroke="#000080" stroke-width=".21"/>
<path d="M42.9 107.6h2.6" fill="none" stroke="#000080" stroke-width=".25"/>
<circle cx="42.9" cy="107.6" r=".51" fill="#000080"/>
<circle cx="42.9" cy="107.6" r=".51" fill="none" stroke="#000080" stroke-width=".21"/>
<path d="M42.9 120.3h2.6" fill="none" stroke="#000080" stroke-width=".25"/>
<circle cx="42.9" cy="120.3" r=".51" fill="#000080"/>
<circle cx="42.9" cy="120.3" r=".51" fill="none" stroke="#000080" stroke-width=".21"/>
<path d="M42.9 133h2.6" fill="none" stroke="#000080" stroke-width=".25"/>
<circle cx="42.9" cy="133" r=".51" fill="#000080"/>
<circle cx="42.9" cy="133" r=".51" fill="none" stroke="#000080" stroke-width=".21"/>
<path d="M42.9 145.7h2.6" fill="none" stroke="#000080" stroke-width=".25"/>
<circle cx="42.9" cy="145.7" r=".51" fill="#000080"/>
<circle cx="42.9" cy="145.7" r=".51" fill="none" stroke="#000080" stroke-width=".21"/>
<path d="M42.9 153.4h2.6" fill="none" stroke="#000080" stroke-width=".25"/>
<circle cx="42.9" cy="153.4" r=".51" fill="#000080"/>
<circle cx="42.9" cy="153.4" r=".51" fill="none" stroke="#000080" stroke-width=".21"/>
<path d="M65.8 77.1h2.5v30.5h-2.5" fill="none" stroke="#000080" stroke-width=".25"/>
<circle cx="68.4" cy="107.6" r=".51" fill="#000080"/>
<circle cx="68.4" cy="107.6" r=".51" fill="none" stroke="#000080" stroke-width=".21"/>
<path d="M68.3 107.6v12.7h-2.5" fill="none" stroke="#000080" stroke-width=".25"/>
<circle cx="68.4" cy="107.6" r=".51" fill="#000080"/>
<circle cx="68.4" cy="107.6" r=".51" fill="none" stroke="#000080" stroke-width=".21"/>
<circle cx="68.4" cy="120.3" r=".51" fill="#000080"/>
<circle cx="68.4" cy="120.3" r=".51" fill="none" stroke="#000080" stroke-width=".21"/>
<path d="M68.3 120.3v12.7h-2.5" fill="none" stroke="#000080" stroke-width=".25"/>
<circle cx="68.4" cy="120.3" r=".51" fill="#000080"/>
<circle cx="68.4" cy="120.3" r=".51" fill="none" stroke="#000080" stroke-width=".21"/>
<circle cx="68.4" cy="133" r=".51" fill="#000080"/>
<circle cx="68.4" cy="133" r=".51" fill="none" stroke="#000080" stroke-width=".21"/>
<path d="M68.3 133v38.2" fill="none" stroke="#000080" stroke-width=".25"/>
<circle cx="68.4" cy="133" r=".51" fill="#000080"/>
<circle cx="68.4" cy="133" r=".51" fill="none" stroke="#000080" stroke-width=".21"/>
<circle cx="68.4" cy="171.2" r=".51" fill="#000080"/>
<circle cx="68.4" cy="171.2" r=".51" fill="none" stroke="#000080" stroke-width=".21"/>
<path d="M65.8 44h7.6" fill="none" stroke="#000080" stroke-width=".25"/>
<circle cx="73.4" cy="44" r=".51" fill="#000080"/>
<circle cx="73.4" cy="44" r=".51" fill="none" stroke="#000080" stroke-width=".21"/>
<path d="M65.8 41.4h7.6" fill="none" stroke="#000080" stroke-width=".25"/>
<circle cx="73.4" cy="41.4" r=".51" fill="#000080"/>
<circle cx="73.4" cy="41.4" r=".51" fill="none" stroke="#000080" stroke-width=".21"/>
<path d="M73.4 56.7v2.6h-7.6" fill="none" stroke="#000080" stroke-width=".25"/>
<circle cx="73.4" cy="56.7" r=".51" fill="#000080"/>
<circle cx="73.4" cy="56.7" r=".51" fill="none" stroke="#000080" stroke-width=".21"/>
<g fill="none" stroke="#000080" stroke-width=".25">
<path d="M129.4 77.1h2.5M14.9 117.8h30.6M14.9 115.2h30.6M14.9 112.7h30.6M14.9 110.1h30.6M65.8 117.8h33.1M65.8 115.2h33.1M14.9 125.4h30.6M14.9 122.9h30.6M14.9 130.5h30.6M14.9 127.9h30.6M65.8 138.1h33.1"/>
<path d="M65.8 135.6h33.1M14.9 143.2h30.6M14.9 140.7h30.6M14.9 150.8h30.6M14.9 148.3h30.6M14.9 158.5h30.6M65.8 158.5h28M152.3 158.5h25.4M14.9 161h30.6M14.9 166.1h30.6M14.9 163.6h30.6M65.8 161h28"/>
<path d="M152.3 161h25.4M152.3 166.1h25.4M152.3 163.6h25.4"/>
</g>
<circle cx="129.4" cy="77.1" r=".51" fill="#000080"/>
<circle cx="129.4" cy="77.1" r=".51" fill="none" stroke="#000080" stroke-width=".21"/>
<path d="M129.4 89.8h2.5" fill="none" stroke="#000080" stroke-width=".25"/>
<circle cx="129.4" cy="89.8" r=".51" fill="#000080"/>
<circle cx="129.4" cy="89.8" r=".51" fill="none" stroke="#000080" stroke-width=".21"/>
<path d="M129.4 102.5h2.5" fill="none" stroke="#000080" stroke-width=".25"/>
<circle cx="129.4" cy="102.5" r=".51" fill="#000080"/>
<circle cx="129.4" cy="102.5" r=".51" fill="none" stroke="#000080" stroke-width=".21"/>
<path d="M129.4 115.2h2.5" fill="none" stroke="#000080" stroke-width=".25"/>
<circle cx="129.4" cy="115.2" r=".51" fill="#000080"/>
<circle cx="129.4" cy="115.2" r=".51" fill="none" stroke="#000080" stroke-width=".21"/>
<path d="M129.4 127.9h2.5" fill="none" stroke="#000080" stroke-width=".25"/>
<circle cx="129.4" cy="127.9" r=".51" fill="#000080"/>
<circle cx="129.4" cy="127.9" r=".51" fill="none" stroke="#000080" stroke-width=".21"/>
<path d="M129.4 140.7h2.5" fill="none" stroke="#000080" stroke-width=".25"/>
<circle cx="129.4" cy="140.7" r=".51" fill="#000080"/>
<circle cx="129.4" cy="140.7" r=".51" fill="none" stroke="#000080" stroke-width=".21"/>
<path d="M129.4 153.4h2.5" fill="none" stroke="#000080" stroke-width=".25"/>
<circle cx="129.4" cy="153.4" r=".51" fill="#000080"/>
<circle cx="129.4" cy="153.4" r=".51" fill="none" stroke="#000080" stroke-width=".21"/>
<path d="M152.3 102.5h2.5" fill="none" stroke="#000080" stroke-width=".25"/>
<circle cx="154.8" cy="102.5" r=".51" fill="#000080"/>
<circle cx="154.8" cy="102.5" r=".51" fill="none" stroke="#000080" stroke-width=".21"/>
<path d="M152.3 115.2h2.5" fill="none" stroke="#000080" stroke-width=".25"/>
<circle cx="154.8" cy="115.2" r=".51" fill="#000080"/>
<circle cx="154.8" cy="115.2" r=".51" fill="none" stroke="#000080" stroke-width=".21"/>
<path d="M152.3 127.9h2.5" fill="none" stroke="#000080" stroke-width=".25"/>
<circle cx="154.8" cy="127.9" r=".51" fill="#000080"/>
<circle cx="154.8" cy="127.9" r=".51" fill="none" stroke="#000080" stroke-width=".21"/>
<path d="M152.3 140.7h2.5" fill="none" stroke="#000080" stroke-width=".25"/>
<circle cx="154.8" cy="140.7" r=".51" fill="#000080"/>
<circle cx="154.8" cy="140.7" r=".51" fill="none" stroke="#000080" stroke-width=".21"/>
<path d="M233.7 54.2h2.6" fill="none" stroke="#000080" stroke-width=".25"/>
<circle cx="233.7" cy="54.2" r=".51" fill="#000080"/>
<circle cx="233.7" cy="54.2" r=".51" fill="none" stroke="#000080" stroke-width=".21"/>
<path d="M233.7 61.8h2.6" fill="none" stroke="#000080" stroke-width=".25"/>
<circle cx="233.7" cy="61.8" r=".51" fill="#000080"/>
<circle cx="233.7" cy="61.8" r=".51" fill="none" stroke="#000080" stroke-width=".21"/>
<path d="M233.7 69.4h2.6" fill="none" stroke="#000080" stroke-width=".25"/>
<circle cx="233.7" cy="69.4" r=".51" fill="#000080"/>
<circle cx="233.7" cy="69.4" r=".51" fill="none" stroke="#000080" stroke-width=".21"/>
<path d="M233.7 77.1h2.6" fill="none" stroke="#000080" stroke-width=".25"/>
<circle cx="233.7" cy="77.1" r=".51" fill="#000080"/>
<circle cx="233.7" cy="77.1" r=".51" fill="none" stroke="#000080" stroke-width=".21"/>
<path d="M233.7 84.7h2.6" fill="none" stroke="#000080" stroke-width=".25"/>
<circle cx="233.7" cy="84.7" r=".51" fill="#000080"/>
<circle cx="233.7" cy="84.7" r=".51" fill="none" stroke="#000080" stroke-width=".21"/>
<path d="M233.7 97.4h2.6" fill="none" stroke="#000080" stroke-width=".25"/>
<circle cx="233.7" cy="97.4" r=".51" fill="#000080"/>
<circle cx="233.7" cy="97.4" r=".51" fill="none" stroke="#000080" stroke-width=".21"/>
<path d="M256.6 54.2h2.6" fill="none" stroke="#000080" stroke-width=".25"/>
<circle cx="259.1" cy="54.2" r=".51" fill="#000080"/>
<circle cx="259.1" cy="54.2" r=".51" fill="none" stroke="#000080" stroke-width=".21"/>
<path d="M256.6 61.8h2.6" fill="none" stroke="#000080" stroke-width=".25"/>
<circle cx="259.1" cy="61.8" r=".51" fill="#000080"/>
<circle cx="259.1" cy="61.8" r=".51" fill="none" stroke="#000080" stroke-width=".21"/>
<path d="M256.6 69.4h2.6" fill="none" stroke="#000080" stroke-width=".25"/>
<circle cx="259.1" cy="69.4" r=".51" fill="#000080"/>
<circle cx="259.1" cy="69.4" r=".51" fill="none" stroke="#000080" stroke-width=".21"/>
<path d="M256.6 77.1h2.6" fill="none" stroke="#000080" stroke-width=".25"/>
<circle cx="259.1" cy="77.1" r=".51" fill="#000080"/>
<circle cx="259.1" cy="77.1" r=".51" fill="none" stroke="#000080" stroke-width=".21"/>
<path d="M256.6 84.7h2.6" fill="none" stroke="#000080" stroke-width=".25"/>
<circle cx="259.1" cy="84.7" r=".51" fill="#000080"/>
<circle cx="259.1" cy="84.7" r=".51" fill="none" stroke="#000080" stroke-width=".21"/>
<path d="M256.6 97.4h2.6" fill="none" stroke="#000080" stroke-width=".25"/>
<circle cx="259.1" cy="97.4" r=".51" fill="#000080"/>
<circle cx="259.1" cy="97.4" r=".51" fill="none" stroke="#000080" stroke-width=".21"/>
<g fill="none" stroke="#000080" stroke-width=".25">
<path d="M45.5 41.4h-2.6v129.8M101.4 79.6h30.5M101.4 82.1h30.5M152.3 92.3h33.1M152.3 94.9h33.1M152.3 97.4h33.1M152.3 100h33.1M152.3 105.1h33.1M152.3 107.6h33.1M152.3 110.1h33.1M152.3 112.7h33.1M152.3 117.8h33.1"/>
<path d="M152.3 120.3h33.1M152.3 125.4h33.1M152.3 122.9h33.1"/>
</g>
<circle cx="42.9" cy="49.1" r=".51" fill="#000080"/>
<circle cx="42.9" cy="49.1" r=".51" fill="none" stroke="#000080" stroke-width=".21"/>
<circle cx="42.9" cy="64.3" r=".51" fill="#000080"/>
<circle cx="42.9" cy="64.3" r=".51" fill="none" stroke="#000080" stroke-width=".21"/>
<circle cx="42.9" cy="72" r=".51" fill="#000080"/>
<circle cx="42.9" cy="72" r=".51" fill="none" stroke="#000080" stroke-width=".21"/>
<circle cx="42.9" cy="82.1" r=".51" fill="#000080"/>
<circle cx="42.9" cy="82.1" r=".51" fill="none" stroke="#000080" stroke-width=".21"/>
<circle cx="42.9" cy="94.9" r=".51" fill="#000080"/>
<circle cx="42.9" cy="94.9" r=".51" fill="none" stroke="#000080" stroke-width=".21"/>
<circle cx="42.9" cy="107.6" r=".51" fill="#000080"/>
<circle cx="42.9" cy="107.6" r=".51" fill="none" stroke="#000080" stroke-width=".21"/>
<circle cx="42.9" cy="120.3" r=".51" fill="#000080"/>
<circle cx="42.9" cy="120.3" r=".51" fill="none" stroke="#000080" stroke-width=".21"/>
<circle cx="42.9" cy="133" r=".51" fill="#000080"/>
<circle cx="42.9" cy="133" r=".51" fill="none" stroke="#000080" stroke-width=".21"/>
<circle cx="42.9" cy="145.7" r=".51" fill="#000080"/>
<circle cx="42.9" cy="145.7" r=".51" fill="none" stroke="#000080" stroke-width=".21"/>
<circle cx="42.9" cy="153.4" r=".51" fill="#000080"/>
<circle cx="42.9" cy="153.4" r=".51" fill="none" stroke="#000080" stroke-width=".21"/>
<circle cx="42.9" cy="171.2" r=".51" fill="#000080"/>
<circle cx="42.9" cy="171.2" r=".51" fill="none" stroke="#000080" stroke-width=".21"/>
<path d="M65.8 56.7h15.3" fill="none" stroke="#000080" stroke-width=".25"/>
<circle cx="73.4" cy="56.7" r=".51" fill="#000080"/>
<circle cx="73.4" cy="56.7" r=".51" fill="none" stroke="#000080" stroke-width=".21"/>
<path d="M131.9 64.3h-2.5v106.9" fill="none" stroke="#000080" stroke-width=".25"/>
<circle cx="129.4" cy="77.1" r=".51" fill="#000080"/>
<circle cx="129.4" cy="77.1" r=".51" fill="none" stroke="#000080" stroke-width=".21"/>
<circle cx="129.4" cy="89.8" r=".51" fill="#000080"/>
<circle cx="129.4" cy="89.8" r=".51" fill="none" stroke="#000080" stroke-width=".21"/>
<circle cx="129.4" cy="102.5" r=".51" fill="#000080"/>
<circle cx="129.4" cy="102.5" r=".51" fill="none" stroke="#000080" stroke-width=".21"/>
<circle cx="129.4" cy="115.2" r=".51" fill="#000080"/>
<circle cx="129.4" cy="115.2" r=".51" fill="none" stroke="#000080" stroke-width=".21"/>
<circle cx="129.4" cy="127.9" r=".51" fill="#000080"/>
<circle cx="129.4" cy="127.9" r=".51" fill="none" stroke="#000080" stroke-width=".21"/>
<circle cx="129.4" cy="140.7" r=".51" fill="#000080"/>
<circle cx="129.4" cy="140.7" r=".51" fill="none" stroke="#000080" stroke-width=".21"/>
<circle cx="129.4" cy="153.4" r=".51" fill="#000080"/>
<circle cx="129.4" cy="153.4" r=".51" fill="none" stroke="#000080" stroke-width=".21"/>
<circle cx="129.4" cy="171.2" r=".51" fill="#000080"/>
<circle cx="129.4" cy="171.2" r=".51" fill="none" stroke="#000080" stroke-width=".21"/>
<path d="M152.3 89.8h2.5v81.4" fill="none" stroke="#000080" stroke-width=".25"/>
<circle cx="154.8" cy="102.5" r=".51" fill="#000080"/>
<circle cx="154.8" cy="102.5" r=".51" fill="none" stroke="#000080" stroke-width=".21"/>
<circle cx="154.8" cy="115.2" r=".51" fill="#000080"/>
<circle cx="154.8" cy="115.2" r=".51" fill="none" stroke="#000080" stroke-width=".21"/>
<circle cx="154.8" cy="127.9" r=".51" fill="#000080"/>
<circle cx="154.8" cy="127.9" r=".51" fill="none" stroke="#000080" stroke-width=".21"/>
<circle cx="154.8" cy="140.7" r=".51" fill="#000080"/>
<circle cx="154.8" cy="140.7" r=".51" fill="none" stroke="#000080" stroke-width=".21"/>
<circle cx="154.8" cy="171.2" r=".51" fill="#000080"/>
<circle cx="154.8" cy="171.2" r=".51" fill="none" stroke="#000080" stroke-width=".21"/>
<path d="M73.4 38.9v7.6h-7.6" fill="none" stroke="#000080" stroke-width=".25"/>
<circle cx="73.4" cy="44" r=".51" fill="#000080"/>
<circle cx="73.4" cy="44" r=".51" fill="none" stroke="#000080" stroke-width=".21"/>
<circle cx="73.4" cy="41.4" r=".51" fill="#000080"/>
<circle cx="73.4" cy="41.4" r=".51" fill="none" stroke="#000080" stroke-width=".21"/>
<path d="M236.3 46.5h-2.6v73.8" fill="none" stroke="#000080" stroke-width=".25"/>
<circle cx="233.7" cy="54.2" r=".51" fill="#000080"/>
<circle cx="233.7" cy="54.2" r=".51" fill="none" stroke="#000080" stroke-width=".21"/>
<circle cx="233.7" cy="61.8" r=".51" fill="#000080"/>
<circle cx="233.7" cy="61.8" r=".51" fill="none" stroke="#000080" stroke-width=".21"/>
<circle cx="233.7" cy="69.4" r=".51" fill="#000080"/>
<circle cx="233.7" cy="69.4" r=".51" fill="none" stroke="#000080" stroke-width=".21"/>
<circle cx="233.7" cy="77.1" r=".51" fill="#000080"/>
<circle cx="233.7" cy="77.1" r=".51" fill="none" stroke="#000080" stroke-width=".21"/>
<circle cx="233.7" cy="84.7" r=".51" fill="#000080"/>
<circle cx="233.7" cy="84.7" r=".51" fill="none" stroke="#000080" stroke-width=".21"/>
<circle cx="233.7" cy="97.4" r=".51" fill="#000080"/>
<circle cx="233.7" cy="97.4" r=".51" fill="none" stroke="#000080" stroke-width=".21"/>
<circle cx="233.7" cy="120.3" r=".51" fill="#000080"/>
<circle cx="233.7" cy="120.3" r=".51" fill="none" stroke="#000080" stroke-width=".21"/>
<path d="M256.6 46.5h2.6v73.8" fill="none" stroke="#000080" stroke-width=".25"/>
<circle cx="259.1" cy="54.2" r=".51" fill="#000080"/>
<circle cx="259.1" cy="54.2" r=".51" fill="none" stroke="#000080" stroke-width=".21"/>
<circle cx="259.1" cy="61.8" r=".51" fill="#000080"/>
<circle cx="259.1" cy="61.8" r=".51" fill="none" stroke="#000080" stroke-width=".21"/>
<circle cx="259.1" cy="69.4" r=".51" fill="#000080"/>
<circle cx="259.1" cy="69.4" r=".51" fill="none" stroke="#000080" stroke-width=".21"/>
<circle cx="259.1" cy="77.1" r=".51" fill="#000080"/>
<circle cx="259.1" cy="77.1" r=".51" fill="none" stroke="#000080" stroke-width=".21"/>
<circle cx="259.1" cy="84.7" r=".51" fill="#000080"/>
<circle cx="259.1" cy="84.7" r=".51" fill="none" stroke="#000080" stroke-width=".21"/>
<circle cx="259.1" cy="97.4" r=".51" fill="#000080"/>
<circle cx="259.1" cy="97.4" r=".51" fill="none" stroke="#000080" stroke-width=".21"/>
<circle cx="259.1" cy="120.3" r=".51" fill="#000080"/>
<circle cx="259.1" cy="120.3" r=".51" fill="none" stroke="#000080" stroke-width=".21"/>
<g fill="none" stroke="#000080" stroke-width=".25">
<path d="M205.7 49.1h30.6M205.7 51.6h30.6M205.7 56.7h30.6M205.7 59.3h30.6M256.6 49.1h28M256.6 51.6h28M256.6 56.7h28M256.6 59.3h28M205.7 64.3h30.6M205.7 66.9h30.6M205.7 72h30.6M205.7 74.5h30.6"/>
<path d="M205.7 79.6h30.6M256.6 64.3h28M256.6 66.9h28M256.6 72h28M256.6 74.5h28M101.4 84.7h30.5M101.4 87.2h30.5M101.4 92.3h30.5M101.4 94.9h30.5M101.4 97.4h30.5M101.4 100h30.5M205.7 82.1h30.6"/>
<path d="M101.4 105h30.5M101.4 107.6h30.5M101.4 110.1h30.5M101.4 112.7h30.5M101.4 117.8h30.5M205.7 115.2h30.6M101.4 120.3h30.5M101.4 122.9h30.5M177.7 153.4v2.5h-25.4"/>
</g>
<use href="#words"/>
</svg>
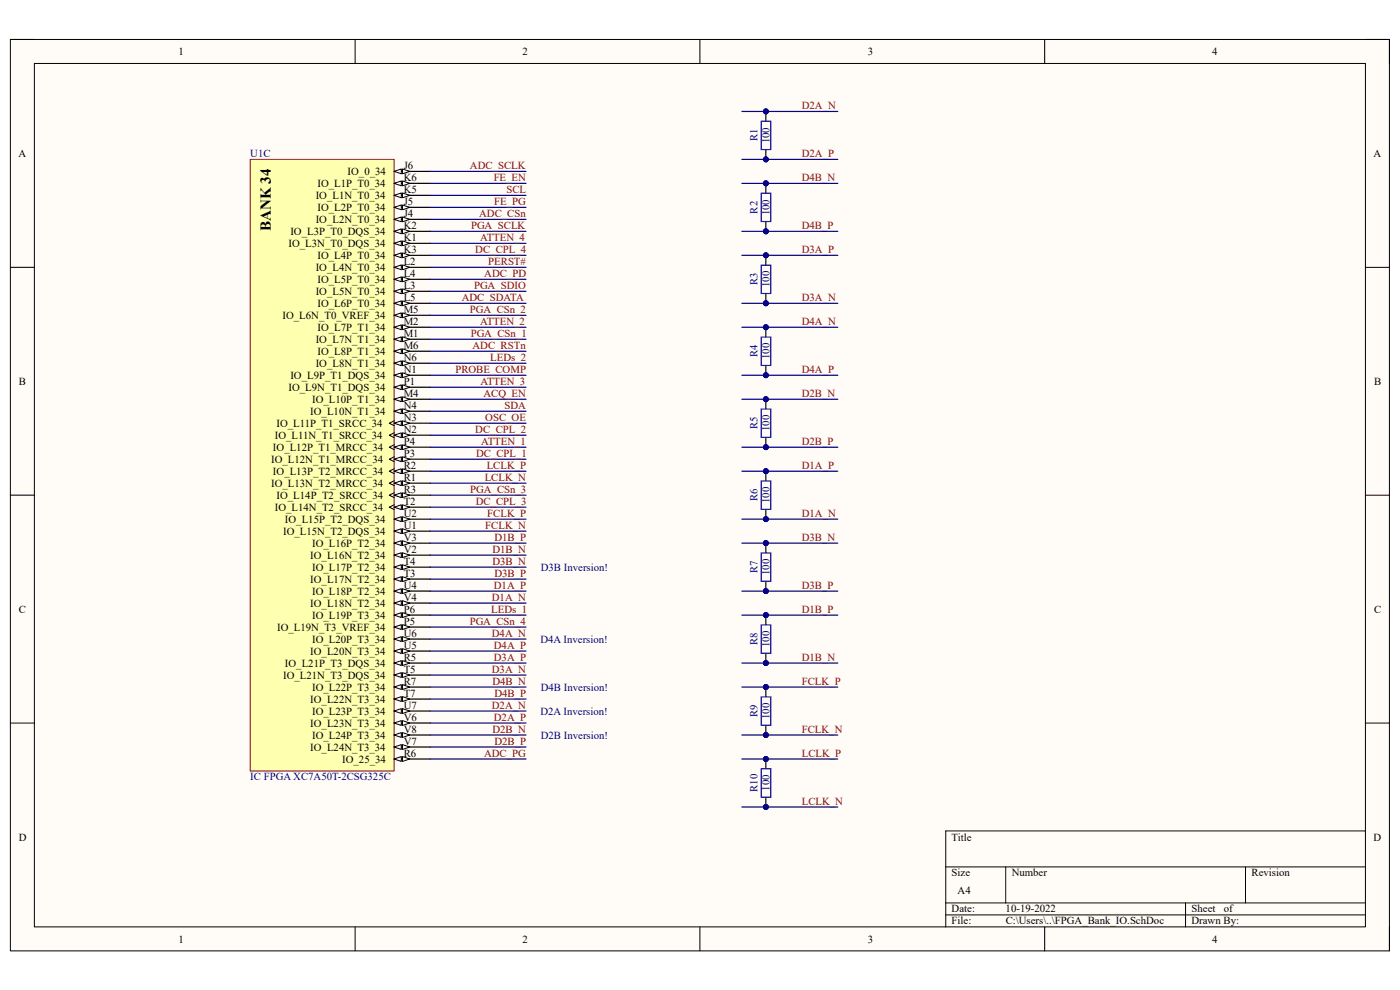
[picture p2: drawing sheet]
<svg xmlns="http://www.w3.org/2000/svg" width="297mm" height="210mm" viewBox="0 0 297 210" stroke-linecap="round" stroke-linejoin="round" font-family="sans-serif">
<defs><g id="words">
<text font-size="3.2" x="57.5" y="49.1" transform="rotate(-90 57.5 49.1)">BANK 34</text>
<g font-size="2.3">
<text x="37.9" y="11.7">1</text>
<text x="110.9" y="11.7">2</text>
<text x="184.1" y="11.7">3</text>
<text x="257.1" y="11.7">4</text>
<text x="3.9" y="33.3">A</text>
<text x="85.6" y="35.9">J6</text>
<text x="291.4" y="33.3">A</text>
<text x="67.4" y="39.7">IO_L1P_T0_34</text>
<text x="73.7" y="37.1">IO_0_34</text>
<text x="85.6" y="38.4">K6</text>
<text x="85.6" y="40.9">K5</text>
<text x="67" y="42.2">IO_L1N_T0_34</text>
<text x="67" y="47.3">IO_L2N_T0_34</text>
<text x="67.4" y="44.7">IO_L2P_T0_34</text>
<text x="85.6" y="43.5">J5</text>
<text x="85.6" y="46">J4</text>
<text x="61.2" y="52.4">IO_L3N_T0_DQS_34</text>
<text x="61.6" y="49.8">IO_L3P_T0_DQS_34</text>
<text x="85.6" y="48.6">K2</text>
<text x="85.6" y="51.1">K1</text>
<text x="85.6" y="53.6">K3</text>
<text x="67" y="57.4">IO_L4N_T0_34</text>
<text x="67.4" y="54.9">IO_L4P_T0_34</text>
<text x="67.4" y="60">IO_L5P_T0_34</text>
<text x="85.6" y="56.2">L2</text>
<text x="85.6" y="58.7">L4</text>
<text x="67" y="62.6">IO_L5N_T0_34</text>
<text x="67.4" y="65.1">IO_L6P_T0_34</text>
<text x="85.6" y="61.3">L3</text>
<text x="85.6" y="63.8">L5</text>
<text x="59.9" y="67.6">IO_L6N_T0_VREF_34</text>
<text x="67.4" y="70.2">IO_L7P_T1_34</text>
<text x="85.6" y="66.4">M5</text>
<text x="85.6" y="68.9">M2</text>
<text x="85.6" y="71.5">M1</text>
<text x="67" y="72.7">IO_L7N_T1_34</text>
<text x="67" y="77.8">IO_L8N_T1_34</text>
<text x="67.4" y="75.3">IO_L8P_T1_34</text>
<text x="85.6" y="74">M6</text>
<text x="85.6" y="76.5">N6</text>
<text x="4" y="81.6">B</text>
<text x="61.2" y="82.9">IO_L9N_T1_DQS_34</text>
<text x="61.6" y="80.3">IO_L9P_T1_DQS_34</text>
<text x="85.6" y="79.1">N1</text>
<text x="85.6" y="81.6">P1</text>
<text x="291.5" y="81.6">B</text>
<text x="65.8" y="88">IO_L10N_T1_34</text>
<text x="66.2" y="85.4">IO_L10P_T1_34</text>
<text x="85.6" y="84.2">M4</text>
<text x="85.6" y="86.7">N4</text>
<text x="85.6" y="89.3">N3</text>
<text x="57.9" y="95.6">IO_L12P_T1_MRCC_34</text>
<text x="58.3" y="93.1">IO_L11N_T1_SRCC_34</text>
<text x="58.7" y="90.6">IO_L11P_T1_SRCC_34</text>
<text x="85.6" y="91.8">N2</text>
<text x="85.6" y="94.4">P4</text>
<text x="57.5" y="98.2">IO_L12N_T1_MRCC_34</text>
<text x="57.9" y="100.7">IO_L13P_T2_MRCC_34</text>
<text x="85.6" y="96.9">P3</text>
<text x="85.6" y="99.4">R2</text>
<text x="85.6" y="102">R1</text>
<text x="57.5" y="103.3">IO_L13N_T2_MRCC_34</text>
<text x="58.7" y="105.8">IO_L14P_T2_SRCC_34</text>
<text x="85.6" y="104.5">R3</text>
<text x="85.6" y="107.1">T2</text>
<text x="58.3" y="108.3">IO_L14N_T2_SRCC_34</text>
<text x="60.1" y="113.4">IO_L15N_T2_DQS_34</text>
<text x="60.5" y="110.9">IO_L15P_T2_DQS_34</text>
<text x="85.6" y="109.6">U2</text>
<text x="85.6" y="112.1">U1</text>
<text x="65.8" y="118.5">IO_L16N_T2_34</text>
<text x="66.2" y="116">IO_L16P_T2_34</text>
<text x="85.6" y="114.7">V3</text>
<text x="85.6" y="117.3">V2</text>
<text x="85.6" y="119.8">T4</text>
<text x="65.8" y="123.6">IO_L17N_T2_34</text>
<text x="66.2" y="121.1">IO_L17P_T2_34</text>
<text x="85.6" y="122.3">T3</text>
<text x="85.6" y="124.9">U4</text>
<text x="4" y="130">C</text>
<text x="65.8" y="128.7">IO_L18N_T2_34</text>
<text x="66.2" y="126.2">IO_L18P_T2_34</text>
<text x="66.2" y="131.2">IO_L19P_T3_34</text>
<text x="85.6" y="127.4">V4</text>
<text x="85.6" y="130">P6</text>
<text x="291.5" y="130">C</text>
<text x="58.8" y="133.8">IO_L19N_T3_VREF_34</text>
<text x="66.2" y="136.3">IO_L20P_T3_34</text>
<text x="85.6" y="132.5">P5</text>
<text x="85.6" y="135">U6</text>
<text x="85.6" y="137.6">U5</text>
<text x="60.1" y="144">IO_L21N_T3_DQS_34</text>
<text x="60.5" y="141.4">IO_L21P_T3_DQS_34</text>
<text x="65.8" y="138.9">IO_L20N_T3_34</text>
<text x="85.6" y="140.1">R5</text>
<text x="85.6" y="142.7">T5</text>
<text x="65.8" y="149.1">IO_L22N_T3_34</text>
<text x="66.2" y="146.5">IO_L22P_T3_34</text>
<text x="85.6" y="145.2">R7</text>
<text x="85.6" y="147.8">T7</text>
<text x="65.8" y="154.1">IO_L23N_T3_34</text>
<text x="66.2" y="151.6">IO_L23P_T3_34</text>
<text x="85.6" y="150.3">U7</text>
<text x="85.6" y="152.9">V6</text>
<text x="85.6" y="155.4">V8</text>
<text x="65.8" y="159.2">IO_L24N_T3_34</text>
<text x="66.2" y="156.7">IO_L24P_T3_34</text>
<text x="72.6" y="161.8">IO_25_34</text>
<text x="85.6" y="157.9">V7</text>
<text x="85.6" y="160.5">R6</text>
<text x="4" y="178.3">D</text>
<text x="201.9" y="178.3">Title</text>
<text x="291.4" y="178.3">D</text>
<text x="201.9" y="185.9">Size</text>
<text x="214.6" y="185.9">Number</text>
<text x="265.5" y="185.9">Revision</text>
<text x="203.2" y="189.7">A4</text>
<text x="201.9" y="193.5">Date:</text>
<text x="201.9" y="196.1">File:</text>
<text x="213.3" y="193.5">10-19-2022</text>
<text x="213.4" y="196.1">C:\Users\..\FPGA_Bank_IO.SchDoc</text>
<text x="252.8" y="193.5">Sheet</text>
<text x="252.8" y="196.1">Drawn By:</text>
<text x="259.6" y="193.5">of</text>
<text x="37.9" y="199.9">1</text>
<text x="110.9" y="199.9">2</text>
<text x="184.1" y="199.9">3</text>
<text x="257.1" y="199.9">4</text>
</g>
<g font-size="2.3" fill="#800000">
<text x="170.1" y="23.1">D2A_N</text>
<text x="99.7" y="35.9">ADC_SCLK</text>
<text x="170.1" y="33.3">D2A_P</text>
<text x="104.7" y="38.4">FE_EN</text>
<text x="107.4" y="40.9">SCL</text>
<text x="170.1" y="38.4">D4B_N</text>
<text x="101.6" y="46">ADC_CSn</text>
<text x="104.9" y="43.5">FE_PG</text>
<text x="99.9" y="48.6">PGA_SCLK</text>
<text x="100.8" y="53.6">DC_CPL_4</text>
<text x="101.9" y="51.1">ATTEN_4</text>
<text x="170.1" y="48.6">D4B_P</text>
<text x="170.1" y="53.6">D3A_P</text>
<text x="102.7" y="58.7">ADC_PD</text>
<text x="103.6" y="56.2">PERST#</text>
<text x="98" y="63.8">ADC_SDATA</text>
<text x="100.6" y="61.3">PGA_SDIO</text>
<text x="170.1" y="63.8">D3A_N</text>
<text x="99.7" y="66.4">PGA_CSn_2</text>
<text x="99.9" y="71.5">PGA_CSn_1</text>
<text x="101.9" y="68.9">ATTEN_2</text>
<text x="170.1" y="68.9">D4A_N</text>
<text x="100.2" y="74">ADC_RSTn</text>
<text x="104" y="76.5">LEDs_2</text>
<text x="96.6" y="79.1">PROBE_COMP</text>
<text x="101.9" y="81.6">ATTEN_3</text>
<text x="170.1" y="79.1">D4A_P</text>
<text x="102.6" y="84.2">ACQ_EN</text>
<text x="103" y="89.3">OSC_OE</text>
<text x="107" y="86.7">SDA</text>
<text x="170.1" y="84.2">D2B_N</text>
<text x="100.8" y="91.8">DC_CPL_2</text>
<text x="102.1" y="94.4">ATTEN_1</text>
<text x="170.1" y="94.4">D2B_P</text>
<text x="101" y="96.9">DC_CPL_1</text>
<text x="102.8" y="102">LCLK_N</text>
<text x="103.3" y="99.4">LCLK_P</text>
<text x="170.1" y="99.4">D1A_P</text>
<text x="99.8" y="104.5">PGA_CSn_3</text>
<text x="100.9" y="107.1">DC_CPL_3</text>
<text x="103" y="112.1">FCLK_N</text>
<text x="103.4" y="109.6">FCLK_P</text>
<text x="170.1" y="109.6">D1A_N</text>
<text x="104.5" y="119.8">D3B_N</text>
<text x="104.5" y="117.3">D1B_N</text>
<text x="104.9" y="114.7">D1B_P</text>
<text x="170.1" y="114.7">D3B_N</text>
<text x="104.8" y="124.9">D1A_P</text>
<text x="104.9" y="122.3">D3B_P</text>
<text x="170.1" y="124.9">D3B_P</text>
<text x="104.2" y="130">LEDs_1</text>
<text x="104.4" y="127.4">D1A_N</text>
<text x="170.1" y="130">D1B_P</text>
<text x="99.7" y="132.5">PGA_CSn_4</text>
<text x="104.4" y="135">D4A_N</text>
<text x="104.8" y="137.6">D4A_P</text>
<text x="104.4" y="142.7">D3A_N</text>
<text x="104.8" y="140.1">D3A_P</text>
<text x="170.1" y="140.1">D1B_N</text>
<text x="104.5" y="145.2">D4B_N</text>
<text x="104.9" y="147.8">D4B_P</text>
<text x="170.1" y="145.2">FCLK_P</text>
<text x="104.4" y="150.3">D2A_N</text>
<text x="104.5" y="155.4">D2B_N</text>
<text x="104.8" y="152.9">D2A_P</text>
<text x="170.1" y="155.4">FCLK_N</text>
<text x="102.7" y="160.5">ADC_PG</text>
<text x="104.9" y="157.9">D2B_P</text>
<text x="170.1" y="160.5">LCLK_P</text>
<text x="170.1" y="170.7">LCLK_N</text>
</g>
<g font-size="2.3" fill="#000080">
<text x="160.7" y="29.9" transform="rotate(-90 160.7 29.9)">R1</text>
<text x="53.1" y="33.3">U1C</text>
<text x="163.2" y="30.4" transform="rotate(-90 163.2 30.4)">100</text>
<text x="160.7" y="45.3" transform="rotate(-90 160.7 45.3)">R2</text>
<text x="163.2" y="45.7" transform="rotate(-90 163.2 45.7)">100</text>
<text x="160.7" y="60.5" transform="rotate(-90 160.7 60.5)">R3</text>
<text x="163.2" y="60.9" transform="rotate(-90 163.2 60.9)">100</text>
<text x="160.7" y="75.8" transform="rotate(-90 160.7 75.8)">R4</text>
<text x="163.2" y="76.2" transform="rotate(-90 163.2 76.2)">100</text>
<text x="160.7" y="91.1" transform="rotate(-90 160.7 91.1)">R5</text>
<text x="163.2" y="91.4" transform="rotate(-90 163.2 91.4)">100</text>
<text x="160.7" y="106.3" transform="rotate(-90 160.7 106.3)">R6</text>
<text x="163.2" y="106.7" transform="rotate(-90 163.2 106.7)">100</text>
<text x="114.7" y="121.1">D3B Inversion!</text>
<text x="160.7" y="121.6" transform="rotate(-90 160.7 121.6)">R7</text>
<text x="163.2" y="122" transform="rotate(-90 163.2 122)">100</text>
<text x="114.6" y="136.3">D4A Inversion!</text>
<text x="160.7" y="136.9" transform="rotate(-90 160.7 136.9)">R8</text>
<text x="163.2" y="137.2" transform="rotate(-90 163.2 137.2)">100</text>
<text x="114.7" y="146.5">D4B Inversion!</text>
<text x="114.6" y="151.6">D2A Inversion!</text>
<text x="160.7" y="152.1" transform="rotate(-90 160.7 152.1)">R9</text>
<text x="163.2" y="152.5" transform="rotate(-90 163.2 152.5)">100</text>
<text x="114.7" y="156.7">D2B Inversion!</text>
<text x="53.1" y="165.6">IC FPGA XC7A50T-2CSG325C</text>
<text x="160.7" y="168" transform="rotate(-90 160.7 168)">R10</text>
<text x="163.2" y="167.8" transform="rotate(-90 163.2 167.8)">100</text>
</g>
</g></defs>
<path d="M2.2 8.4h292.6v193.3h-292.6z" fill-rule="evenodd" fill="#fffcf8"/>
<path d="M2.2 8.4h292.6v193.3h-292.6z" fill="none" stroke="#000" stroke-width=".21"/>
<path d="M7.3 13.5h282.4v183.1h-282.4z" fill-rule="evenodd" fill="#fffcf8"/>
<g fill="none" stroke="#000" stroke-width=".21">
<path d="M2.2 8.4h5.1M7.3 13.5h282.4v183.1h-282.4zM75.3 8.4v5.1M148.5 8.4v5.1M221.6 8.4v5.1M289.7 8.4h5.1v5.1M2.2 56.7h5.1M289.7 56.7h5.1M2.2 105h5.1M289.7 105.1h5.1M2.2 153.4h5.1M289.7 153.4h5.1"/>
<path d="M289.7 176.3h-89.1v20.3M75.3 196.6v5.1M148.5 196.6v5.1M200.6 183.9h89.1M200.6 191.5h89.1M200.6 194.1h89.1M213.4 183.9v7.6M221.6 196.6v5.1M251.5 191.5v5.1M264.2 183.9v7.6M294.8 196.6v5.1"/>
</g>
<path d="M53.1 33.8h30.5v129.8h-30.5z" fill-rule="evenodd" fill="#ffffb0"/>
<path d="M53.1 33.8h30.5v129.8h-30.5z" fill="none" stroke="#800000" stroke-width=".21"/>
<path d="M83.6 36.4h7.6" fill="none" stroke="#000" stroke-width=".25"/>
<path d="M83.6 36.4l1.5-.6v1.1z" fill="#f8fcff"/>
<path d="M83.6 36.4l1.5-.6v1.1z" fill="none" stroke="#000" stroke-width=".21"/>
<path d="M85.4 35.9l1.5 .5-1.5 .5z" fill="#f8fcff"/>
<path d="M85.4 35.9l1.5 .5-1.5 .5z" fill="none" stroke="#000" stroke-width=".21"/>
<path d="M83.6 38.9h7.6" fill="none" stroke="#000" stroke-width=".25"/>
<path d="M83.6 38.9l1.5-.5v1z" fill="#f8fcff"/>
<path d="M83.6 38.9l1.5-.5v1z" fill="none" stroke="#000" stroke-width=".21"/>
<path d="M85.4 38.4l1.5 .5-1.5 .5z" fill="#f8fcff"/>
<path d="M85.4 38.4l1.5 .5-1.5 .5z" fill="none" stroke="#000" stroke-width=".21"/>
<path d="M83.6 41.4h7.6" fill="none" stroke="#000" stroke-width=".25"/>
<path d="M83.6 41.4l1.5-.5v1.1z" fill="#f8fcff"/>
<path d="M83.6 41.4l1.5-.5v1.1z" fill="none" stroke="#000" stroke-width=".21"/>
<path d="M85.4 40.9l1.5 .5-1.5 .6z" fill="#f8fcff"/>
<path d="M85.4 40.9l1.5 .5-1.5 .6z" fill="none" stroke="#000" stroke-width=".21"/>
<path d="M83.6 44h7.6" fill="none" stroke="#000" stroke-width=".25"/>
<path d="M83.6 44l1.5-.5v1z" fill="#f8fcff"/>
<path d="M83.6 44l1.5-.5v1z" fill="none" stroke="#000" stroke-width=".21"/>
<path d="M85.4 43.5l1.5 .5-1.5 .5z" fill="#f8fcff"/>
<path d="M85.4 43.5l1.5 .5-1.5 .5z" fill="none" stroke="#000" stroke-width=".21"/>
<path d="M83.6 46.5h7.6" fill="none" stroke="#000" stroke-width=".25"/>
<path d="M83.6 46.5l1.5-.5v1z" fill="#f8fcff"/>
<path d="M83.6 46.5l1.5-.5v1z" fill="none" stroke="#000" stroke-width=".21"/>
<path d="M85.4 46l1.5 .5-1.5 .5z" fill="#f8fcff"/>
<path d="M85.4 46l1.5 .5-1.5 .5z" fill="none" stroke="#000" stroke-width=".21"/>
<path d="M83.6 49.1h7.6" fill="none" stroke="#000" stroke-width=".25"/>
<path d="M83.6 49.1l1.5-.5v1z" fill="#f8fcff"/>
<path d="M83.6 49.1l1.5-.5v1z" fill="none" stroke="#000" stroke-width=".21"/>
<path d="M85.4 48.6l1.5 .5-1.5 .5z" fill="#f8fcff"/>
<path d="M85.4 48.6l1.5 .5-1.5 .5z" fill="none" stroke="#000" stroke-width=".21"/>
<path d="M83.6 51.6h7.6" fill="none" stroke="#000" stroke-width=".25"/>
<path d="M83.6 51.6l1.5-.5v1z" fill="#f8fcff"/>
<path d="M83.6 51.6l1.5-.5v1z" fill="none" stroke="#000" stroke-width=".21"/>
<path d="M85.4 51.1l1.5 .5-1.5 .5z" fill="#f8fcff"/>
<path d="M85.4 51.1l1.5 .5-1.5 .5z" fill="none" stroke="#000" stroke-width=".21"/>
<path d="M83.6 54.2h7.6" fill="none" stroke="#000" stroke-width=".25"/>
<path d="M83.6 54.2l1.5-.5v1z" fill="#f8fcff"/>
<path d="M83.6 54.2l1.5-.5v1z" fill="none" stroke="#000" stroke-width=".21"/>
<path d="M85.4 53.7l1.5 .5-1.5 .5z" fill="#f8fcff"/>
<path d="M85.4 53.7l1.5 .5-1.5 .5z" fill="none" stroke="#000" stroke-width=".21"/>
<path d="M83.6 56.7h7.6" fill="none" stroke="#000" stroke-width=".25"/>
<path d="M83.6 56.7l1.5-.5v1z" fill="#f8fcff"/>
<path d="M83.6 56.7l1.5-.5v1z" fill="none" stroke="#000" stroke-width=".21"/>
<path d="M85.4 56.2l1.5 .5-1.5 .5z" fill="#f8fcff"/>
<path d="M85.4 56.2l1.5 .5-1.5 .5z" fill="none" stroke="#000" stroke-width=".21"/>
<path d="M83.6 59.3h7.6" fill="none" stroke="#000" stroke-width=".25"/>
<path d="M83.6 59.3l1.5-.6v1.1z" fill="#f8fcff"/>
<path d="M83.6 59.3l1.5-.6v1.1z" fill="none" stroke="#000" stroke-width=".21"/>
<path d="M85.4 58.7l1.5 .6-1.5 .5z" fill="#f8fcff"/>
<path d="M85.4 58.7l1.5 .6-1.5 .5z" fill="none" stroke="#000" stroke-width=".21"/>
<path d="M83.6 61.8h7.6" fill="none" stroke="#000" stroke-width=".25"/>
<path d="M83.6 61.8l1.5-.5v1z" fill="#f8fcff"/>
<path d="M83.6 61.8l1.5-.5v1z" fill="none" stroke="#000" stroke-width=".21"/>
<path d="M85.4 61.3l1.5 .5-1.5 .5z" fill="#f8fcff"/>
<path d="M85.4 61.3l1.5 .5-1.5 .5z" fill="none" stroke="#000" stroke-width=".21"/>
<path d="M83.6 64.3h7.6" fill="none" stroke="#000" stroke-width=".25"/>
<path d="M83.6 64.3l1.5-.5v1z" fill="#f8fcff"/>
<path d="M83.6 64.3l1.5-.5v1z" fill="none" stroke="#000" stroke-width=".21"/>
<path d="M85.4 63.8l1.5 .5-1.5 .5z" fill="#f8fcff"/>
<path d="M85.4 63.8l1.5 .5-1.5 .5z" fill="none" stroke="#000" stroke-width=".21"/>
<path d="M83.6 66.9h7.6" fill="none" stroke="#000" stroke-width=".25"/>
<path d="M83.6 66.9l1.5-.5v1z" fill="#f8fcff"/>
<path d="M83.6 66.9l1.5-.5v1z" fill="none" stroke="#000" stroke-width=".21"/>
<path d="M85.4 66.4l1.5 .5-1.5 .5z" fill="#f8fcff"/>
<path d="M85.4 66.4l1.5 .5-1.5 .5z" fill="none" stroke="#000" stroke-width=".21"/>
<path d="M83.6 69.4h7.6" fill="none" stroke="#000" stroke-width=".25"/>
<path d="M83.6 69.4l1.5-.5v1z" fill="#f8fcff"/>
<path d="M83.6 69.4l1.5-.5v1z" fill="none" stroke="#000" stroke-width=".21"/>
<path d="M85.4 68.9l1.5 .5-1.5 .5z" fill="#f8fcff"/>
<path d="M85.4 68.9l1.5 .5-1.5 .5z" fill="none" stroke="#000" stroke-width=".21"/>
<path d="M83.6 72h7.6" fill="none" stroke="#000" stroke-width=".25"/>
<path d="M83.6 72l1.5-.5v1z" fill="#f8fcff"/>
<path d="M83.6 72l1.5-.5v1z" fill="none" stroke="#000" stroke-width=".21"/>
<path d="M85.4 71.5l1.5 .5-1.5 .5z" fill="#f8fcff"/>
<path d="M85.4 71.5l1.5 .5-1.5 .5z" fill="none" stroke="#000" stroke-width=".21"/>
<path d="M83.6 74.5h7.6" fill="none" stroke="#000" stroke-width=".25"/>
<path d="M83.6 74.5l1.5-.5v1z" fill="#f8fcff"/>
<path d="M83.6 74.5l1.5-.5v1z" fill="none" stroke="#000" stroke-width=".21"/>
<path d="M85.4 74l1.5 .5-1.5 .5z" fill="#f8fcff"/>
<path d="M85.4 74l1.5 .5-1.5 .5z" fill="none" stroke="#000" stroke-width=".21"/>
<path d="M83.6 77.1h7.6" fill="none" stroke="#000" stroke-width=".25"/>
<path d="M83.6 77.1l1.5-.5v1z" fill="#f8fcff"/>
<path d="M83.6 77.1l1.5-.5v1z" fill="none" stroke="#000" stroke-width=".21"/>
<path d="M85.4 76.6l1.5 .5-1.5 .5z" fill="#f8fcff"/>
<path d="M85.4 76.6l1.5 .5-1.5 .5z" fill="none" stroke="#000" stroke-width=".21"/>
<path d="M83.6 79.6h7.6" fill="none" stroke="#000" stroke-width=".25"/>
<path d="M83.6 79.6l1.5-.5v1z" fill="#f8fcff"/>
<path d="M83.6 79.6l1.5-.5v1z" fill="none" stroke="#000" stroke-width=".21"/>
<path d="M85.4 79.1l1.5 .5-1.5 .5z" fill="#f8fcff"/>
<path d="M85.4 79.1l1.5 .5-1.5 .5z" fill="none" stroke="#000" stroke-width=".21"/>
<path d="M83.6 82.1h7.6" fill="none" stroke="#000" stroke-width=".25"/>
<path d="M83.6 82.1l1.5-.5v1.1z" fill="#f8fcff"/>
<path d="M83.6 82.1l1.5-.5v1.1z" fill="none" stroke="#000" stroke-width=".21"/>
<path d="M85.4 81.6l1.5 .5-1.5 .6z" fill="#f8fcff"/>
<path d="M85.4 81.6l1.5 .5-1.5 .6z" fill="none" stroke="#000" stroke-width=".21"/>
<path d="M83.6 84.7h7.6" fill="none" stroke="#000" stroke-width=".25"/>
<path d="M83.6 84.7l1.5-.5v1z" fill="#f8fcff"/>
<path d="M83.6 84.7l1.5-.5v1z" fill="none" stroke="#000" stroke-width=".21"/>
<path d="M85.4 84.2l1.5 .5-1.5 .5z" fill="#f8fcff"/>
<path d="M85.4 84.2l1.5 .5-1.5 .5z" fill="none" stroke="#000" stroke-width=".21"/>
<path d="M83.6 87.2h7.6" fill="none" stroke="#000" stroke-width=".25"/>
<path d="M83.6 87.2l1.5-.5v1z" fill="#f8fcff"/>
<path d="M83.6 87.2l1.5-.5v1z" fill="none" stroke="#000" stroke-width=".21"/>
<path d="M85.4 86.7l1.5 .5-1.5 .5z" fill="#f8fcff"/>
<path d="M85.4 86.7l1.5 .5-1.5 .5z" fill="none" stroke="#000" stroke-width=".21"/>
<path d="M83.6 89.8h7.6" fill="none" stroke="#000" stroke-width=".25"/>
<path d="M83.6 89.8l1.5-.5v1z" fill="#f8fcff"/>
<path d="M83.6 89.8l1.5-.5v1z" fill="none" stroke="#000" stroke-width=".21"/>
<path d="M85.4 89.3l1.5 .5-1.5 .5z" fill="#f8fcff"/>
<path d="M83.6 89.3l-1 .5 1 .5M85.4 89.3l1.5 .5-1.5 .5z" fill="none" stroke="#000" stroke-width=".21"/>
<path d="M83.6 92.3h7.6" fill="none" stroke="#000" stroke-width=".25"/>
<path d="M83.6 92.3l1.5-.5v1z" fill="#f8fcff"/>
<path d="M83.6 92.3l1.5-.5v1z" fill="none" stroke="#000" stroke-width=".21"/>
<path d="M85.4 91.8l1.5 .5-1.5 .5z" fill="#f8fcff"/>
<path d="M83.6 91.8l-1 .5 1 .5M85.4 91.8l1.5 .5-1.5 .5z" fill="none" stroke="#000" stroke-width=".21"/>
<path d="M83.6 94.9h7.6" fill="none" stroke="#000" stroke-width=".25"/>
<path d="M83.6 94.9l1.5-.5v1z" fill="#f8fcff"/>
<path d="M83.6 94.9l1.5-.5v1z" fill="none" stroke="#000" stroke-width=".21"/>
<path d="M85.4 94.4l1.5 .5-1.5 .5z" fill="#f8fcff"/>
<path d="M83.6 94.4l-1 .5 1 .5M85.4 94.4l1.5 .5-1.5 .5z" fill="none" stroke="#000" stroke-width=".21"/>
<path d="M83.6 97.4h7.6" fill="none" stroke="#000" stroke-width=".25"/>
<path d="M83.6 97.4l1.5-.5v1z" fill="#f8fcff"/>
<path d="M83.6 97.4l1.5-.5v1z" fill="none" stroke="#000" stroke-width=".21"/>
<path d="M85.4 96.9l1.5 .5-1.5 .5z" fill="#f8fcff"/>
<path d="M83.6 96.9l-1 .5 1 .5M85.4 96.9l1.5 .5-1.5 .5z" fill="none" stroke="#000" stroke-width=".21"/>
<path d="M83.6 100h7.6" fill="none" stroke="#000" stroke-width=".25"/>
<path d="M83.6 100l1.5-.6v1.1z" fill="#f8fcff"/>
<path d="M83.6 100l1.5-.6v1.1z" fill="none" stroke="#000" stroke-width=".21"/>
<path d="M85.4 99.4l1.5 .6-1.5 .5z" fill="#f8fcff"/>
<path d="M83.6 99.4l-1 .6 1 .5M85.4 99.4l1.5 .6-1.5 .5z" fill="none" stroke="#000" stroke-width=".21"/>
<path d="M83.6 102.5h7.6" fill="none" stroke="#000" stroke-width=".25"/>
<path d="M83.6 102.5l1.5-.5v1z" fill="#f8fcff"/>
<path d="M83.6 102.5l1.5-.5v1z" fill="none" stroke="#000" stroke-width=".21"/>
<path d="M85.4 102l1.5 .5-1.5 .5z" fill="#f8fcff"/>
<path d="M83.6 102l-1 .5 1 .5M85.4 102l1.5 .5-1.5 .5z" fill="none" stroke="#000" stroke-width=".21"/>
<path d="M83.6 105h7.6" fill="none" stroke="#000" stroke-width=".25"/>
<path d="M83.6 105l1.5-.5v1.1z" fill="#f8fcff"/>
<path d="M83.6 105l1.5-.5v1.1z" fill="none" stroke="#000" stroke-width=".21"/>
<path d="M85.4 104.5l1.5 .5-1.5 .6z" fill="#f8fcff"/>
<path d="M83.6 104.5l-1 .5 1 .6M85.4 104.5l1.5 .5-1.5 .6z" fill="none" stroke="#000" stroke-width=".21"/>
<path d="M83.6 107.6h7.6" fill="none" stroke="#000" stroke-width=".25"/>
<path d="M83.6 107.6l1.5-.5v1z" fill="#f8fcff"/>
<path d="M83.6 107.6l1.5-.5v1z" fill="none" stroke="#000" stroke-width=".21"/>
<path d="M85.4 107.1l1.5 .5-1.5 .5z" fill="#f8fcff"/>
<path d="M83.6 107.1l-1 .5 1 .5M85.4 107.1l1.5 .5-1.5 .5z" fill="none" stroke="#000" stroke-width=".21"/>
<path d="M83.6 110.1h7.6" fill="none" stroke="#000" stroke-width=".25"/>
<path d="M83.6 110.1l1.5-.5v1z" fill="#f8fcff"/>
<path d="M83.6 110.1l1.5-.5v1z" fill="none" stroke="#000" stroke-width=".21"/>
<path d="M85.4 109.6l1.5 .5-1.5 .5z" fill="#f8fcff"/>
<path d="M85.4 109.6l1.5 .5-1.5 .5z" fill="none" stroke="#000" stroke-width=".21"/>
<path d="M83.6 112.7h7.6" fill="none" stroke="#000" stroke-width=".25"/>
<path d="M83.6 112.7l1.5-.5v1z" fill="#f8fcff"/>
<path d="M83.6 112.7l1.5-.5v1z" fill="none" stroke="#000" stroke-width=".21"/>
<path d="M85.4 112.2l1.5 .5-1.5 .5z" fill="#f8fcff"/>
<path d="M85.4 112.2l1.5 .5-1.5 .5z" fill="none" stroke="#000" stroke-width=".21"/>
<path d="M83.6 115.2h7.6" fill="none" stroke="#000" stroke-width=".25"/>
<path d="M83.6 115.2l1.5-.5v1z" fill="#f8fcff"/>
<path d="M83.6 115.2l1.5-.5v1z" fill="none" stroke="#000" stroke-width=".21"/>
<path d="M85.4 114.7l1.5 .5-1.5 .5z" fill="#f8fcff"/>
<path d="M85.4 114.7l1.5 .5-1.5 .5z" fill="none" stroke="#000" stroke-width=".21"/>
<path d="M83.6 117.8h7.6" fill="none" stroke="#000" stroke-width=".25"/>
<path d="M83.6 117.8l1.5-.5v1z" fill="#f8fcff"/>
<path d="M83.6 117.8l1.5-.5v1z" fill="none" stroke="#000" stroke-width=".21"/>
<path d="M85.4 117.3l1.5 .5-1.5 .5z" fill="#f8fcff"/>
<path d="M85.4 117.3l1.5 .5-1.5 .5z" fill="none" stroke="#000" stroke-width=".21"/>
<path d="M83.6 120.3h7.6" fill="none" stroke="#000" stroke-width=".25"/>
<path d="M83.6 120.3l1.5-.5v1z" fill="#f8fcff"/>
<path d="M83.6 120.3l1.5-.5v1z" fill="none" stroke="#000" stroke-width=".21"/>
<path d="M85.4 119.8l1.5 .5-1.5 .5z" fill="#f8fcff"/>
<path d="M85.4 119.8l1.5 .5-1.5 .5z" fill="none" stroke="#000" stroke-width=".21"/>
<path d="M83.6 122.9h7.6" fill="none" stroke="#000" stroke-width=".25"/>
<path d="M83.6 122.9l1.5-.6v1.1z" fill="#f8fcff"/>
<path d="M83.6 122.9l1.5-.6v1.1z" fill="none" stroke="#000" stroke-width=".21"/>
<path d="M85.4 122.3l1.5 .6-1.5 .5z" fill="#f8fcff"/>
<path d="M85.4 122.3l1.5 .6-1.5 .5z" fill="none" stroke="#000" stroke-width=".21"/>
<path d="M83.6 125.4h7.6" fill="none" stroke="#000" stroke-width=".25"/>
<path d="M83.6 125.4l1.5-.5v1z" fill="#f8fcff"/>
<path d="M83.6 125.4l1.5-.5v1z" fill="none" stroke="#000" stroke-width=".21"/>
<path d="M85.4 124.9l1.5 .5-1.5 .5z" fill="#f8fcff"/>
<path d="M85.4 124.9l1.5 .5-1.5 .5z" fill="none" stroke="#000" stroke-width=".21"/>
<path d="M83.6 127.9h7.6" fill="none" stroke="#000" stroke-width=".25"/>
<path d="M83.6 127.9l1.5-.5v1z" fill="#f8fcff"/>
<path d="M83.6 127.9l1.5-.5v1z" fill="none" stroke="#000" stroke-width=".21"/>
<path d="M85.4 127.4l1.5 .5-1.5 .5z" fill="#f8fcff"/>
<path d="M85.4 127.4l1.5 .5-1.5 .5z" fill="none" stroke="#000" stroke-width=".21"/>
<path d="M83.6 130.5h7.6" fill="none" stroke="#000" stroke-width=".25"/>
<path d="M83.6 130.5l1.5-.5v1z" fill="#f8fcff"/>
<path d="M83.6 130.5l1.5-.5v1z" fill="none" stroke="#000" stroke-width=".21"/>
<path d="M85.4 130l1.5 .5-1.5 .5z" fill="#f8fcff"/>
<path d="M85.4 130l1.5 .5-1.5 .5z" fill="none" stroke="#000" stroke-width=".21"/>
<path d="M83.6 133h7.6" fill="none" stroke="#000" stroke-width=".25"/>
<path d="M83.6 133l1.5-.5v1z" fill="#f8fcff"/>
<path d="M83.6 133l1.5-.5v1z" fill="none" stroke="#000" stroke-width=".21"/>
<path d="M85.4 132.5l1.5 .5-1.5 .5z" fill="#f8fcff"/>
<path d="M85.4 132.5l1.5 .5-1.5 .5z" fill="none" stroke="#000" stroke-width=".21"/>
<path d="M83.6 135.6h7.6" fill="none" stroke="#000" stroke-width=".25"/>
<path d="M83.6 135.6l1.5-.5v1z" fill="#f8fcff"/>
<path d="M83.6 135.6l1.5-.5v1z" fill="none" stroke="#000" stroke-width=".21"/>
<path d="M85.4 135.1l1.5 .5-1.5 .5z" fill="#f8fcff"/>
<path d="M85.4 135.1l1.5 .5-1.5 .5z" fill="none" stroke="#000" stroke-width=".21"/>
<path d="M83.6 138.1h7.6" fill="none" stroke="#000" stroke-width=".25"/>
<path d="M83.6 138.1l1.5-.5v1z" fill="#f8fcff"/>
<path d="M83.6 138.1l1.5-.5v1z" fill="none" stroke="#000" stroke-width=".21"/>
<path d="M85.4 137.6l1.5 .5-1.5 .5z" fill="#f8fcff"/>
<path d="M85.4 137.6l1.5 .5-1.5 .5z" fill="none" stroke="#000" stroke-width=".21"/>
<path d="M83.6 140.7h7.6" fill="none" stroke="#000" stroke-width=".25"/>
<path d="M83.6 140.7l1.5-.6v1.1z" fill="#f8fcff"/>
<path d="M83.6 140.7l1.5-.6v1.1z" fill="none" stroke="#000" stroke-width=".21"/>
<path d="M85.4 140.1l1.5 .6-1.5 .5z" fill="#f8fcff"/>
<path d="M85.4 140.1l1.5 .6-1.5 .5z" fill="none" stroke="#000" stroke-width=".21"/>
<path d="M83.6 143.2h7.6" fill="none" stroke="#000" stroke-width=".25"/>
<path d="M83.6 143.2l1.5-.5v1z" fill="#f8fcff"/>
<path d="M83.6 143.2l1.5-.5v1z" fill="none" stroke="#000" stroke-width=".21"/>
<path d="M85.4 142.7l1.5 .5-1.5 .5z" fill="#f8fcff"/>
<path d="M85.4 142.7l1.5 .5-1.5 .5z" fill="none" stroke="#000" stroke-width=".21"/>
<path d="M83.6 145.7h7.6" fill="none" stroke="#000" stroke-width=".25"/>
<path d="M83.6 145.7l1.5-.5v1.1z" fill="#f8fcff"/>
<path d="M83.6 145.7l1.5-.5v1.1z" fill="none" stroke="#000" stroke-width=".21"/>
<path d="M85.4 145.2l1.5 .5-1.5 .6z" fill="#f8fcff"/>
<path d="M85.4 145.2l1.5 .5-1.5 .6z" fill="none" stroke="#000" stroke-width=".21"/>
<path d="M83.6 148.3h7.6" fill="none" stroke="#000" stroke-width=".25"/>
<path d="M83.6 148.3l1.5-.5v1z" fill="#f8fcff"/>
<path d="M83.6 148.3l1.5-.5v1z" fill="none" stroke="#000" stroke-width=".21"/>
<path d="M85.4 147.8l1.5 .5-1.5 .5z" fill="#f8fcff"/>
<path d="M85.4 147.8l1.5 .5-1.5 .5z" fill="none" stroke="#000" stroke-width=".21"/>
<path d="M83.6 150.8h7.6" fill="none" stroke="#000" stroke-width=".25"/>
<path d="M83.6 150.8l1.5-.5v1z" fill="#f8fcff"/>
<path d="M83.6 150.8l1.5-.5v1z" fill="none" stroke="#000" stroke-width=".21"/>
<path d="M85.4 150.3l1.5 .5-1.5 .5z" fill="#f8fcff"/>
<path d="M85.4 150.3l1.5 .5-1.5 .5z" fill="none" stroke="#000" stroke-width=".21"/>
<path d="M83.6 153.4h7.6" fill="none" stroke="#000" stroke-width=".25"/>
<path d="M83.6 153.4l1.5-.5v1z" fill="#f8fcff"/>
<path d="M83.6 153.4l1.5-.5v1z" fill="none" stroke="#000" stroke-width=".21"/>
<path d="M85.4 152.9l1.5 .5-1.5 .5z" fill="#f8fcff"/>
<path d="M85.4 152.9l1.5 .5-1.5 .5z" fill="none" stroke="#000" stroke-width=".21"/>
<path d="M83.6 155.9h7.6" fill="none" stroke="#000" stroke-width=".25"/>
<path d="M83.6 155.9l1.5-.5v1z" fill="#f8fcff"/>
<path d="M83.6 155.9l1.5-.5v1z" fill="none" stroke="#000" stroke-width=".21"/>
<path d="M85.4 155.4l1.5 .5-1.5 .5z" fill="#f8fcff"/>
<path d="M85.4 155.4l1.5 .5-1.5 .5z" fill="none" stroke="#000" stroke-width=".21"/>
<path d="M83.6 158.5h7.6" fill="none" stroke="#000" stroke-width=".25"/>
<path d="M83.6 158.5l1.5-.5v1z" fill="#f8fcff"/>
<path d="M83.6 158.5l1.5-.5v1z" fill="none" stroke="#000" stroke-width=".21"/>
<path d="M85.4 158l1.5 .5-1.5 .5z" fill="#f8fcff"/>
<path d="M85.4 158l1.5 .5-1.5 .5z" fill="none" stroke="#000" stroke-width=".21"/>
<path d="M83.6 161h7.6" fill="none" stroke="#000" stroke-width=".25"/>
<path d="M83.6 161l1.5-.5v1z" fill="#f8fcff"/>
<path d="M83.6 161l1.5-.5v1z" fill="none" stroke="#000" stroke-width=".21"/>
<path d="M85.4 160.5l1.5 .5-1.5 .5z" fill="#f8fcff"/>
<path d="M85.4 160.5l1.5 .5-1.5 .5z" fill="none" stroke="#000" stroke-width=".21"/>
<circle cx="162.5" cy="23.6" r=".51" fill="#000080"/>
<circle cx="162.5" cy="23.6" r=".51" fill="none" stroke="#000080" stroke-width=".21"/>
<circle cx="162.5" cy="33.8" r=".51" fill="#000080"/>
<circle cx="162.5" cy="33.8" r=".51" fill="none" stroke="#000080" stroke-width=".21"/>
<path d="M162.5 23.6v2" fill="none" stroke="#000" stroke-width=".25"/>
<circle cx="162.5" cy="23.6" r=".51" fill="#000080"/>
<circle cx="162.5" cy="23.6" r=".51" fill="none" stroke="#000080" stroke-width=".21"/>
<path d="M162.5 31.8v2" fill="none" stroke="#000" stroke-width=".25"/>
<circle cx="162.5" cy="33.8" r=".51" fill="#000080"/>
<circle cx="162.5" cy="33.8" r=".51" fill="none" stroke="#000080" stroke-width=".21"/>
<path d="M161.5 25.7h2v6h-2z" fill="none" stroke="#00f" stroke-width=".25"/>
<circle cx="162.5" cy="38.9" r=".51" fill="#000080"/>
<circle cx="162.5" cy="38.9" r=".51" fill="none" stroke="#000080" stroke-width=".21"/>
<circle cx="162.5" cy="49.1" r=".51" fill="#000080"/>
<circle cx="162.5" cy="49.1" r=".51" fill="none" stroke="#000080" stroke-width=".21"/>
<path d="M162.5 38.9v2" fill="none" stroke="#000" stroke-width=".25"/>
<circle cx="162.5" cy="38.9" r=".51" fill="#000080"/>
<circle cx="162.5" cy="38.9" r=".51" fill="none" stroke="#000080" stroke-width=".21"/>
<path d="M162.5 47.1v2" fill="none" stroke="#000" stroke-width=".25"/>
<circle cx="162.5" cy="49.1" r=".51" fill="#000080"/>
<circle cx="162.5" cy="49.1" r=".51" fill="none" stroke="#000080" stroke-width=".21"/>
<path d="M161.5 41h2v6h-2z" fill="none" stroke="#00f" stroke-width=".25"/>
<circle cx="162.5" cy="54.2" r=".51" fill="#000080"/>
<circle cx="162.5" cy="54.2" r=".51" fill="none" stroke="#000080" stroke-width=".21"/>
<circle cx="162.5" cy="64.3" r=".51" fill="#000080"/>
<circle cx="162.5" cy="64.3" r=".51" fill="none" stroke="#000080" stroke-width=".21"/>
<path d="M162.5 54.2v2" fill="none" stroke="#000" stroke-width=".25"/>
<circle cx="162.5" cy="54.2" r=".51" fill="#000080"/>
<circle cx="162.5" cy="54.2" r=".51" fill="none" stroke="#000080" stroke-width=".21"/>
<path d="M162.5 62.3v2" fill="none" stroke="#000" stroke-width=".25"/>
<circle cx="162.5" cy="64.3" r=".51" fill="#000080"/>
<circle cx="162.5" cy="64.3" r=".51" fill="none" stroke="#000080" stroke-width=".21"/>
<path d="M161.5 56.3h2v6h-2z" fill="none" stroke="#00f" stroke-width=".25"/>
<circle cx="162.5" cy="69.4" r=".51" fill="#000080"/>
<circle cx="162.5" cy="69.4" r=".51" fill="none" stroke="#000080" stroke-width=".21"/>
<circle cx="162.5" cy="79.6" r=".51" fill="#000080"/>
<circle cx="162.5" cy="79.6" r=".51" fill="none" stroke="#000080" stroke-width=".21"/>
<path d="M162.5 69.4v2" fill="none" stroke="#000" stroke-width=".25"/>
<circle cx="162.5" cy="69.4" r=".51" fill="#000080"/>
<circle cx="162.5" cy="69.4" r=".51" fill="none" stroke="#000080" stroke-width=".21"/>
<path d="M162.5 77.6v2" fill="none" stroke="#000" stroke-width=".25"/>
<circle cx="162.5" cy="79.6" r=".51" fill="#000080"/>
<circle cx="162.5" cy="79.6" r=".51" fill="none" stroke="#000080" stroke-width=".21"/>
<path d="M161.5 71.5h2v6h-2z" fill="none" stroke="#00f" stroke-width=".25"/>
<circle cx="162.5" cy="84.7" r=".51" fill="#000080"/>
<circle cx="162.5" cy="84.7" r=".51" fill="none" stroke="#000080" stroke-width=".21"/>
<circle cx="162.5" cy="94.9" r=".51" fill="#000080"/>
<circle cx="162.5" cy="94.9" r=".51" fill="none" stroke="#000080" stroke-width=".21"/>
<path d="M162.5 84.7v2" fill="none" stroke="#000" stroke-width=".25"/>
<circle cx="162.5" cy="84.7" r=".51" fill="#000080"/>
<circle cx="162.5" cy="84.7" r=".51" fill="none" stroke="#000080" stroke-width=".21"/>
<path d="M162.5 92.9v2" fill="none" stroke="#000" stroke-width=".25"/>
<circle cx="162.5" cy="94.9" r=".51" fill="#000080"/>
<circle cx="162.5" cy="94.9" r=".51" fill="none" stroke="#000080" stroke-width=".21"/>
<path d="M161.5 86.8h2v6h-2z" fill="none" stroke="#00f" stroke-width=".25"/>
<circle cx="162.5" cy="100" r=".51" fill="#000080"/>
<circle cx="162.5" cy="100" r=".51" fill="none" stroke="#000080" stroke-width=".21"/>
<circle cx="162.5" cy="110.1" r=".51" fill="#000080"/>
<circle cx="162.5" cy="110.1" r=".51" fill="none" stroke="#000080" stroke-width=".21"/>
<path d="M162.5 100v2" fill="none" stroke="#000" stroke-width=".25"/>
<circle cx="162.5" cy="100" r=".51" fill="#000080"/>
<circle cx="162.5" cy="100" r=".51" fill="none" stroke="#000080" stroke-width=".21"/>
<path d="M162.5 108.1v2" fill="none" stroke="#000" stroke-width=".25"/>
<circle cx="162.5" cy="110.1" r=".51" fill="#000080"/>
<circle cx="162.5" cy="110.1" r=".51" fill="none" stroke="#000080" stroke-width=".21"/>
<path d="M161.5 102h2v6.1h-2z" fill="none" stroke="#00f" stroke-width=".25"/>
<circle cx="162.5" cy="115.2" r=".51" fill="#000080"/>
<circle cx="162.5" cy="115.2" r=".51" fill="none" stroke="#000080" stroke-width=".21"/>
<circle cx="162.5" cy="125.4" r=".51" fill="#000080"/>
<circle cx="162.5" cy="125.4" r=".51" fill="none" stroke="#000080" stroke-width=".21"/>
<path d="M162.5 115.2v2" fill="none" stroke="#000" stroke-width=".25"/>
<circle cx="162.5" cy="115.2" r=".51" fill="#000080"/>
<circle cx="162.5" cy="115.2" r=".51" fill="none" stroke="#000080" stroke-width=".21"/>
<path d="M162.5 123.4v2" fill="none" stroke="#000" stroke-width=".25"/>
<circle cx="162.5" cy="125.4" r=".51" fill="#000080"/>
<circle cx="162.5" cy="125.4" r=".51" fill="none" stroke="#000080" stroke-width=".21"/>
<path d="M161.5 117.3h2v6h-2z" fill="none" stroke="#00f" stroke-width=".25"/>
<circle cx="162.5" cy="130.5" r=".51" fill="#000080"/>
<circle cx="162.5" cy="130.5" r=".51" fill="none" stroke="#000080" stroke-width=".21"/>
<circle cx="162.5" cy="140.7" r=".51" fill="#000080"/>
<circle cx="162.5" cy="140.7" r=".51" fill="none" stroke="#000080" stroke-width=".21"/>
<path d="M162.5 130.5v2" fill="none" stroke="#000" stroke-width=".25"/>
<circle cx="162.5" cy="130.5" r=".51" fill="#000080"/>
<circle cx="162.5" cy="130.5" r=".51" fill="none" stroke="#000080" stroke-width=".21"/>
<path d="M162.5 138.7v2" fill="none" stroke="#000" stroke-width=".25"/>
<circle cx="162.5" cy="140.7" r=".51" fill="#000080"/>
<circle cx="162.5" cy="140.7" r=".51" fill="none" stroke="#000080" stroke-width=".21"/>
<path d="M161.5 132.6h2v6h-2z" fill="none" stroke="#00f" stroke-width=".25"/>
<circle cx="162.5" cy="145.7" r=".51" fill="#000080"/>
<circle cx="162.5" cy="145.7" r=".51" fill="none" stroke="#000080" stroke-width=".21"/>
<circle cx="162.5" cy="155.9" r=".51" fill="#000080"/>
<circle cx="162.5" cy="155.9" r=".51" fill="none" stroke="#000080" stroke-width=".21"/>
<path d="M162.5 145.7v2.1" fill="none" stroke="#000" stroke-width=".25"/>
<circle cx="162.5" cy="145.7" r=".51" fill="#000080"/>
<circle cx="162.5" cy="145.7" r=".51" fill="none" stroke="#000080" stroke-width=".21"/>
<path d="M162.5 153.9v2" fill="none" stroke="#000" stroke-width=".25"/>
<circle cx="162.5" cy="155.9" r=".51" fill="#000080"/>
<circle cx="162.5" cy="155.9" r=".51" fill="none" stroke="#000080" stroke-width=".21"/>
<path d="M161.5 147.8h2v6h-2z" fill="none" stroke="#00f" stroke-width=".25"/>
<circle cx="162.5" cy="161" r=".51" fill="#000080"/>
<circle cx="162.5" cy="161" r=".51" fill="none" stroke="#000080" stroke-width=".21"/>
<circle cx="162.5" cy="171.2" r=".51" fill="#000080"/>
<circle cx="162.5" cy="171.2" r=".51" fill="none" stroke="#000080" stroke-width=".21"/>
<path d="M162.5 161v2" fill="none" stroke="#000" stroke-width=".25"/>
<circle cx="162.5" cy="161" r=".51" fill="#000080"/>
<circle cx="162.5" cy="161" r=".51" fill="none" stroke="#000080" stroke-width=".21"/>
<path d="M162.5 169.2v2" fill="none" stroke="#000" stroke-width=".25"/>
<circle cx="162.5" cy="171.2" r=".51" fill="#000080"/>
<circle cx="162.5" cy="171.2" r=".51" fill="none" stroke="#000080" stroke-width=".21"/>
<path d="M161.5 163.1h2v6h-2z" fill="none" stroke="#00f" stroke-width=".25"/>
<path d="M157.4 23.6h20.3" fill="none" stroke="#000080" stroke-width=".25"/>
<circle cx="162.5" cy="23.6" r=".51" fill="#000080"/>
<circle cx="162.5" cy="23.6" r=".51" fill="none" stroke="#000080" stroke-width=".21"/>
<path d="M157.4 33.8h20.3" fill="none" stroke="#000080" stroke-width=".25"/>
<circle cx="162.5" cy="33.8" r=".51" fill="#000080"/>
<circle cx="162.5" cy="33.8" r=".51" fill="none" stroke="#000080" stroke-width=".21"/>
<path d="M157.4 38.9h20.3" fill="none" stroke="#000080" stroke-width=".25"/>
<circle cx="162.5" cy="38.9" r=".51" fill="#000080"/>
<circle cx="162.5" cy="38.9" r=".51" fill="none" stroke="#000080" stroke-width=".21"/>
<path d="M157.4 49.1h20.3" fill="none" stroke="#000080" stroke-width=".25"/>
<circle cx="162.5" cy="49.1" r=".51" fill="#000080"/>
<circle cx="162.5" cy="49.1" r=".51" fill="none" stroke="#000080" stroke-width=".21"/>
<path d="M157.4 54.2h20.3" fill="none" stroke="#000080" stroke-width=".25"/>
<circle cx="162.5" cy="54.2" r=".51" fill="#000080"/>
<circle cx="162.5" cy="54.2" r=".51" fill="none" stroke="#000080" stroke-width=".21"/>
<path d="M157.4 64.3h20.3" fill="none" stroke="#000080" stroke-width=".25"/>
<circle cx="162.5" cy="64.3" r=".51" fill="#000080"/>
<circle cx="162.5" cy="64.3" r=".51" fill="none" stroke="#000080" stroke-width=".21"/>
<path d="M157.4 69.4h20.3" fill="none" stroke="#000080" stroke-width=".25"/>
<circle cx="162.5" cy="69.4" r=".51" fill="#000080"/>
<circle cx="162.5" cy="69.4" r=".51" fill="none" stroke="#000080" stroke-width=".21"/>
<path d="M157.4 79.6h20.3" fill="none" stroke="#000080" stroke-width=".25"/>
<circle cx="162.5" cy="79.6" r=".51" fill="#000080"/>
<circle cx="162.5" cy="79.6" r=".51" fill="none" stroke="#000080" stroke-width=".21"/>
<path d="M157.4 84.7h20.3" fill="none" stroke="#000080" stroke-width=".25"/>
<circle cx="162.5" cy="84.7" r=".51" fill="#000080"/>
<circle cx="162.5" cy="84.7" r=".51" fill="none" stroke="#000080" stroke-width=".21"/>
<path d="M157.4 94.9h20.3" fill="none" stroke="#000080" stroke-width=".25"/>
<circle cx="162.5" cy="94.9" r=".51" fill="#000080"/>
<circle cx="162.5" cy="94.9" r=".51" fill="none" stroke="#000080" stroke-width=".21"/>
<path d="M157.4 100h20.3" fill="none" stroke="#000080" stroke-width=".25"/>
<circle cx="162.5" cy="100" r=".51" fill="#000080"/>
<circle cx="162.5" cy="100" r=".51" fill="none" stroke="#000080" stroke-width=".21"/>
<path d="M157.4 110.1h20.3" fill="none" stroke="#000080" stroke-width=".25"/>
<circle cx="162.5" cy="110.1" r=".51" fill="#000080"/>
<circle cx="162.5" cy="110.1" r=".51" fill="none" stroke="#000080" stroke-width=".21"/>
<path d="M157.4 115.2h20.3" fill="none" stroke="#000080" stroke-width=".25"/>
<circle cx="162.5" cy="115.2" r=".51" fill="#000080"/>
<circle cx="162.5" cy="115.2" r=".51" fill="none" stroke="#000080" stroke-width=".21"/>
<path d="M157.4 125.4h20.3" fill="none" stroke="#000080" stroke-width=".25"/>
<circle cx="162.5" cy="125.4" r=".51" fill="#000080"/>
<circle cx="162.5" cy="125.4" r=".51" fill="none" stroke="#000080" stroke-width=".21"/>
<path d="M157.4 130.5h20.3" fill="none" stroke="#000080" stroke-width=".25"/>
<circle cx="162.5" cy="130.5" r=".51" fill="#000080"/>
<circle cx="162.5" cy="130.5" r=".51" fill="none" stroke="#000080" stroke-width=".21"/>
<path d="M157.4 140.7h20.3" fill="none" stroke="#000080" stroke-width=".25"/>
<circle cx="162.5" cy="140.7" r=".51" fill="#000080"/>
<circle cx="162.5" cy="140.7" r=".51" fill="none" stroke="#000080" stroke-width=".21"/>
<path d="M157.4 145.8h20.3" fill="none" stroke="#000080" stroke-width=".25"/>
<circle cx="162.5" cy="145.7" r=".51" fill="#000080"/>
<circle cx="162.5" cy="145.7" r=".51" fill="none" stroke="#000080" stroke-width=".21"/>
<path d="M157.4 155.9h20.3" fill="none" stroke="#000080" stroke-width=".25"/>
<circle cx="162.5" cy="155.9" r=".51" fill="#000080"/>
<circle cx="162.5" cy="155.9" r=".51" fill="none" stroke="#000080" stroke-width=".21"/>
<path d="M157.4 161h20.3" fill="none" stroke="#000080" stroke-width=".25"/>
<circle cx="162.5" cy="161" r=".51" fill="#000080"/>
<circle cx="162.5" cy="161" r=".51" fill="none" stroke="#000080" stroke-width=".21"/>
<path d="M157.4 171.2h20.3" fill="none" stroke="#000080" stroke-width=".25"/>
<circle cx="162.5" cy="171.2" r=".51" fill="#000080"/>
<circle cx="162.5" cy="171.2" r=".51" fill="none" stroke="#000080" stroke-width=".21"/>
<g fill="none" stroke="#000080" stroke-width=".25">
<path d="M91.2 36.4h20.4M91.2 38.9h20.4M91.2 41.4h20.4M91.2 44h20.4M91.2 46.5h20.4M91.2 49.1h20.4M91.2 51.6h20.4M91.2 54.2h20.4M91.2 56.7h20.4M91.2 59.3h20.4M91.2 61.8h20.4M91.2 64.3h20.4"/>
<path d="M91.2 66.9h20.4M91.2 69.4h20.4M91.2 72h20.4M91.2 74.5h20.4M91.2 77.1h20.4M91.2 79.6h20.4M91.2 82.1h20.4M91.2 84.7h20.4M91.2 87.2h20.4M91.2 89.8h20.4M91.2 92.3h20.4M91.2 94.9h20.4"/>
<path d="M91.2 97.4h20.4M91.2 100h20.4M91.2 110.1h20.4M91.2 112.7h20.4M91.2 105h20.4M91.2 107.6h20.4M91.2 102.5h20.4M91.2 115.2h20.4M91.2 117.8h20.4M91.2 135.6h20.4M91.2 138.1h20.4M91.2 130.5h20.4"/>
<path d="M91.2 133h20.4M91.2 125.4h20.4M91.2 127.9h20.4M91.2 120.3h20.4M91.2 122.9h20.4M91.2 155.9h20.4M91.2 158.5h20.4M91.2 150.8h20.4M91.2 153.4h20.4M91.2 145.7h20.4M91.2 148.3h20.4M91.2 140.7h20.4"/>
<path d="M91.2 143.2h20.4M91.2 161h20.4"/>
</g>
<use href="#words"/>
</svg>
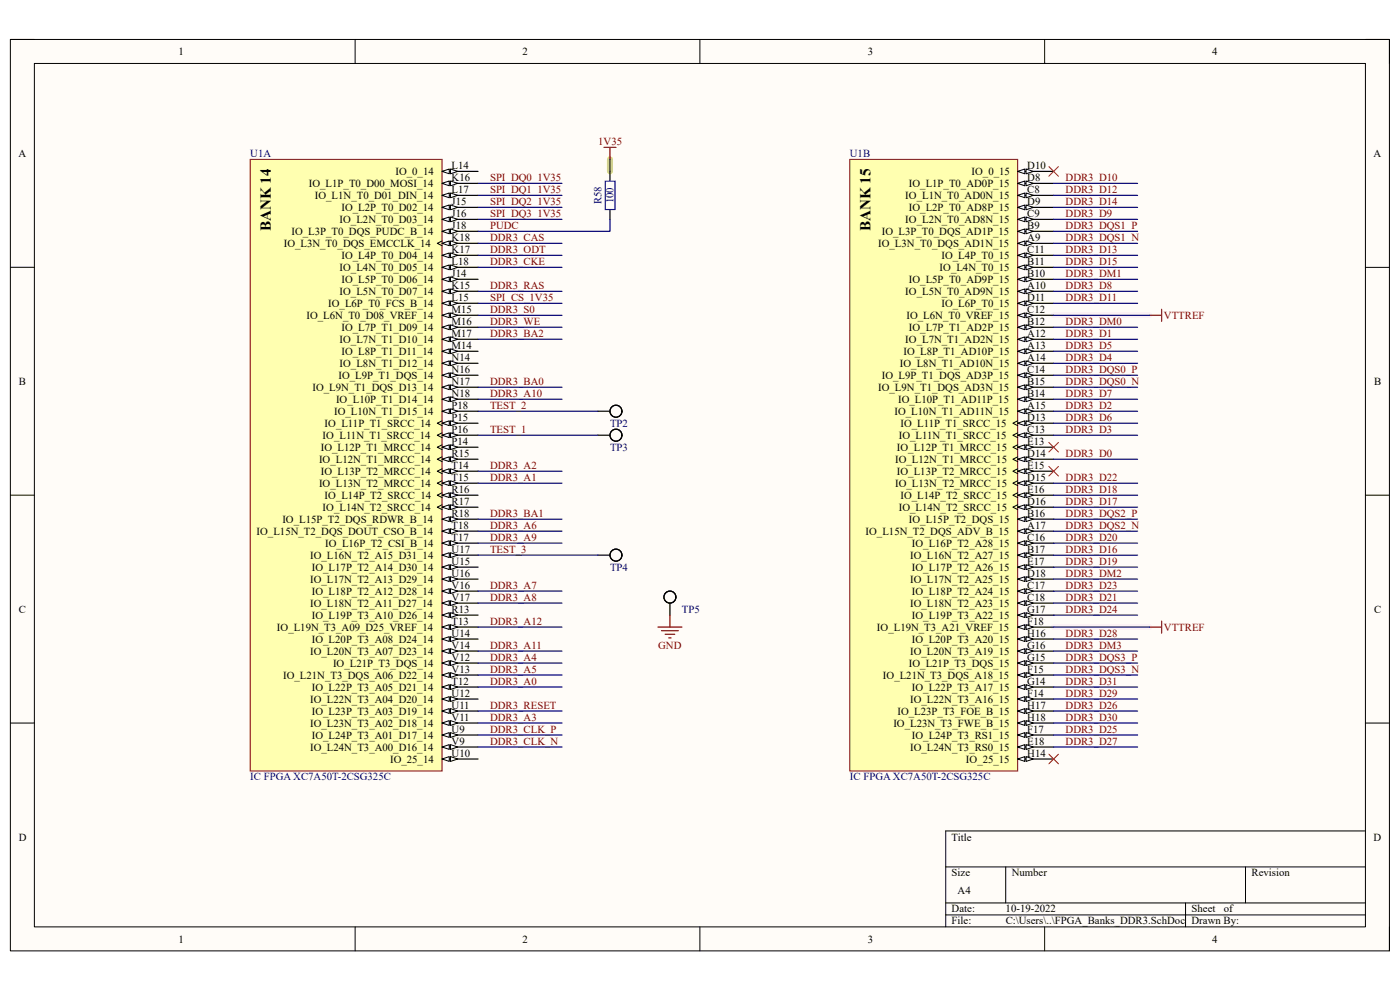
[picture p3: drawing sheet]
<svg xmlns="http://www.w3.org/2000/svg" width="297mm" height="210mm" viewBox="0 0 297 210" stroke-linecap="round" stroke-linejoin="round" font-family="sans-serif">
<defs><g id="words">
<g font-size="3.2">
<text x="57.5" y="49.1" transform="rotate(-90 57.5 49.1)">BANK 14</text>
<text x="184.7" y="49.1" transform="rotate(-90 184.7 49.1)">BANK 15</text>
</g>
<g font-size="2.3">
<text x="37.9" y="11.7">1</text>
<text x="110.9" y="11.7">2</text>
<text x="184.1" y="11.7">3</text>
<text x="257.1" y="11.7">4</text>
<text x="3.9" y="33.3">A</text>
<text x="95.8" y="35.9">L14</text>
<text x="217.9" y="35.9">D10</text>
<text x="291.4" y="33.3">A</text>
<text x="65.5" y="39.7">IO_L1P_T0_D00_MOSI_14</text>
<text x="83.9" y="37.1">IO_0_14</text>
<text x="95.8" y="38.4">K16</text>
<text x="95.8" y="40.9">L17</text>
<text x="192.8" y="39.7">IO_L1P_T0_AD0P_15</text>
<text x="206.1" y="37.1">IO_0_15</text>
<text x="217.9" y="38.4">D8</text>
<text x="217.9" y="40.9">C8</text>
<text x="66.8" y="42.2">IO_L1N_T0_D01_DIN_14</text>
<text x="72.1" y="47.3">IO_L2N_T0_D03_14</text>
<text x="72.4" y="44.7">IO_L2P_T0_D02_14</text>
<text x="95.8" y="43.5">J15</text>
<text x="95.8" y="46">J16</text>
<text x="192.1" y="42.2">IO_L1N_T0_AD0N_15</text>
<text x="192.1" y="47.3">IO_L2N_T0_AD8N_15</text>
<text x="192.8" y="44.7">IO_L2P_T0_AD8P_15</text>
<text x="217.9" y="43.5">D9</text>
<text x="217.9" y="46">C9</text>
<text x="60.2" y="52.4">IO_L3N_T0_DQS_EMCCLK_14</text>
<text x="61.8" y="49.8">IO_L3P_T0_DQS_PUDC_B_14</text>
<text x="95.8" y="48.6">J18</text>
<text x="95.8" y="51.1">K18</text>
<text x="95.8" y="53.6">K17</text>
<text x="186.3" y="52.4">IO_L3N_T0_DQS_AD1N_15</text>
<text x="187.1" y="49.8">IO_L3P_T0_DQS_AD1P_15</text>
<text x="217.9" y="48.6">B9</text>
<text x="217.9" y="51.1">A9</text>
<text x="217.9" y="53.6">C11</text>
<text x="72.1" y="57.4">IO_L4N_T0_D05_14</text>
<text x="72.4" y="54.9">IO_L4P_T0_D04_14</text>
<text x="72.4" y="60">IO_L5P_T0_D06_14</text>
<text x="95.8" y="56.2">L18</text>
<text x="95.8" y="58.7">J14</text>
<text x="192.8" y="60">IO_L5P_T0_AD9P_15</text>
<text x="199.3" y="57.4">IO_L4N_T0_15</text>
<text x="199.7" y="54.9">IO_L4P_T0_15</text>
<text x="217.9" y="56.2">B11</text>
<text x="217.9" y="58.7">B10</text>
<text x="69.6" y="65.1">IO_L6P_T0_FCS_B_14</text>
<text x="72.1" y="62.6">IO_L5N_T0_D07_14</text>
<text x="95.8" y="61.3">K15</text>
<text x="95.8" y="63.8">L15</text>
<text x="192.1" y="62.6">IO_L5N_T0_AD9N_15</text>
<text x="199.7" y="65.1">IO_L6P_T0_15</text>
<text x="217.9" y="61.3">A10</text>
<text x="217.9" y="63.8">D11</text>
<text x="65" y="67.6">IO_L6N_T0_D08_VREF_14</text>
<text x="72.4" y="70.2">IO_L7P_T1_D09_14</text>
<text x="95.8" y="66.4">M15</text>
<text x="95.8" y="68.9">M16</text>
<text x="95.8" y="71.5">M17</text>
<text x="192.3" y="67.6">IO_L6N_T0_VREF_15</text>
<text x="192.8" y="70.2">IO_L7P_T1_AD2P_15</text>
<text x="217.9" y="66.4">C12</text>
<text x="217.9" y="68.9">B12</text>
<text x="217.9" y="71.5">A12</text>
<text x="72.1" y="72.7">IO_L7N_T1_D10_14</text>
<text x="72.1" y="77.8">IO_L8N_T1_D12_14</text>
<text x="72.4" y="75.3">IO_L8P_T1_D11_14</text>
<text x="95.8" y="74">M14</text>
<text x="95.8" y="76.5">N14</text>
<text x="190.9" y="77.8">IO_L8N_T1_AD10N_15</text>
<text x="191.7" y="75.3">IO_L8P_T1_AD10P_15</text>
<text x="192.1" y="72.7">IO_L7N_T1_AD2N_15</text>
<text x="217.9" y="74">A13</text>
<text x="217.9" y="76.5">A14</text>
<text x="4" y="81.6">B</text>
<text x="66.3" y="82.9">IO_L9N_T1_DQS_D13_14</text>
<text x="71.8" y="80.3">IO_L9P_T1_DQS_14</text>
<text x="95.8" y="79.1">N16</text>
<text x="95.8" y="81.6">N17</text>
<text x="186.3" y="82.9">IO_L9N_T1_DQS_AD3N_15</text>
<text x="187.1" y="80.3">IO_L9P_T1_DQS_AD3P_15</text>
<text x="217.9" y="79.1">C14</text>
<text x="217.9" y="81.6">B15</text>
<text x="291.5" y="81.6">B</text>
<text x="70.9" y="88">IO_L10N_T1_D15_14</text>
<text x="71.3" y="85.4">IO_L10P_T1_D14_14</text>
<text x="95.8" y="84.2">N18</text>
<text x="95.8" y="86.7">P18</text>
<text x="95.8" y="89.3">P15</text>
<text x="189.8" y="88">IO_L10N_T1_AD11N_15</text>
<text x="190.5" y="85.4">IO_L10P_T1_AD11P_15</text>
<text x="217.9" y="84.2">B14</text>
<text x="217.9" y="86.7">A15</text>
<text x="217.9" y="89.3">D13</text>
<text x="68.1" y="95.6">IO_L12P_T1_MRCC_14</text>
<text x="68.5" y="93.1">IO_L11N_T1_SRCC_14</text>
<text x="68.9" y="90.6">IO_L11P_T1_SRCC_14</text>
<text x="95.8" y="91.8">P16</text>
<text x="95.8" y="94.4">P14</text>
<text x="190.3" y="95.6">IO_L12P_T1_MRCC_15</text>
<text x="190.7" y="93.1">IO_L11N_T1_SRCC_15</text>
<text x="191.1" y="90.6">IO_L11P_T1_SRCC_15</text>
<text x="217.9" y="91.8">C13</text>
<text x="217.9" y="94.4">E13</text>
<text x="67.7" y="98.2">IO_L12N_T1_MRCC_14</text>
<text x="68.1" y="100.7">IO_L13P_T2_MRCC_14</text>
<text x="95.8" y="96.9">R15</text>
<text x="95.8" y="99.4">T14</text>
<text x="95.8" y="102">T15</text>
<text x="189.9" y="98.2">IO_L12N_T1_MRCC_15</text>
<text x="190.3" y="100.7">IO_L13P_T2_MRCC_15</text>
<text x="217.9" y="96.9">D14</text>
<text x="217.9" y="99.4">E15</text>
<text x="217.9" y="102">D15</text>
<text x="67.7" y="103.3">IO_L13N_T2_MRCC_14</text>
<text x="68.9" y="105.8">IO_L14P_T2_SRCC_14</text>
<text x="95.8" y="104.5">R16</text>
<text x="95.8" y="107.1">R17</text>
<text x="189.9" y="103.3">IO_L13N_T2_MRCC_15</text>
<text x="191.1" y="105.8">IO_L14P_T2_SRCC_15</text>
<text x="217.9" y="104.5">E16</text>
<text x="217.9" y="107.1">D16</text>
<text x="54.4" y="113.4">IO_L15N_T2_DQS_DOUT_CSO_B_14</text>
<text x="59.9" y="110.9">IO_L15P_T2_DQS_RDWR_B_14</text>
<text x="68.5" y="108.3">IO_L14N_T2_SRCC_14</text>
<text x="95.8" y="109.6">R18</text>
<text x="95.8" y="112.1">T18</text>
<text x="183.6" y="113.4">IO_L15N_T2_DQS_ADV_B_15</text>
<text x="190.7" y="108.3">IO_L14N_T2_SRCC_15</text>
<text x="192.8" y="110.9">IO_L15P_T2_DQS_15</text>
<text x="217.9" y="109.6">B16</text>
<text x="217.9" y="112.1">A17</text>
<text x="65.8" y="118.5">IO_L16N_T2_A15_D31_14</text>
<text x="69" y="116">IO_L16P_T2_CSI_B_14</text>
<text x="95.8" y="114.7">T17</text>
<text x="95.8" y="117.3">U17</text>
<text x="95.8" y="119.8">U15</text>
<text x="193.1" y="118.5">IO_L16N_T2_A27_15</text>
<text x="193.5" y="116">IO_L16P_T2_A28_15</text>
<text x="217.9" y="114.7">C16</text>
<text x="217.9" y="117.3">B17</text>
<text x="217.9" y="119.8">E17</text>
<text x="65.8" y="123.6">IO_L17N_T2_A13_D29_14</text>
<text x="66.2" y="121.1">IO_L17P_T2_A14_D30_14</text>
<text x="95.8" y="122.3">U16</text>
<text x="95.8" y="124.9">V16</text>
<text x="193.1" y="123.6">IO_L17N_T2_A25_15</text>
<text x="193.5" y="121.1">IO_L17P_T2_A26_15</text>
<text x="217.9" y="122.3">D18</text>
<text x="217.9" y="124.9">C17</text>
<text x="4" y="130">C</text>
<text x="65.8" y="128.7">IO_L18N_T2_A11_D27_14</text>
<text x="66.2" y="126.2">IO_L18P_T2_A12_D28_14</text>
<text x="66.2" y="131.2">IO_L19P_T3_A10_D26_14</text>
<text x="95.8" y="127.4">V17</text>
<text x="95.8" y="130">R13</text>
<text x="193.1" y="128.7">IO_L18N_T2_A23_15</text>
<text x="193.5" y="126.2">IO_L18P_T2_A24_15</text>
<text x="193.5" y="131.2">IO_L19P_T3_A22_15</text>
<text x="217.9" y="127.4">C18</text>
<text x="217.9" y="130">G17</text>
<text x="291.5" y="130">C</text>
<text x="58.8" y="133.8">IO_L19N_T3_A09_D25_VREF_14</text>
<text x="66.2" y="136.3">IO_L20P_T3_A08_D24_14</text>
<text x="95.8" y="132.5">T13</text>
<text x="95.8" y="135">U14</text>
<text x="95.8" y="137.6">V14</text>
<text x="186.1" y="133.8">IO_L19N_T3_A21_VREF_15</text>
<text x="193.5" y="136.3">IO_L20P_T3_A20_15</text>
<text x="217.9" y="132.5">F18</text>
<text x="217.9" y="135">H16</text>
<text x="217.9" y="137.6">G16</text>
<text x="60.1" y="144">IO_L21N_T3_DQS_A06_D22_14</text>
<text x="65.8" y="138.9">IO_L20N_T3_A07_D23_14</text>
<text x="70.7" y="141.4">IO_L21P_T3_DQS_14</text>
<text x="95.8" y="140.1">V12</text>
<text x="95.8" y="142.7">V13</text>
<text x="187.3" y="144">IO_L21N_T3_DQS_A18_15</text>
<text x="192.8" y="141.4">IO_L21P_T3_DQS_15</text>
<text x="193.1" y="138.9">IO_L20N_T3_A19_15</text>
<text x="217.9" y="140.1">G15</text>
<text x="217.9" y="142.7">F15</text>
<text x="65.8" y="149.1">IO_L22N_T3_A04_D20_14</text>
<text x="66.2" y="146.5">IO_L22P_T3_A05_D21_14</text>
<text x="95.8" y="145.2">T12</text>
<text x="95.8" y="147.8">U12</text>
<text x="193.1" y="149.1">IO_L22N_T3_A16_15</text>
<text x="193.5" y="146.5">IO_L22P_T3_A17_15</text>
<text x="217.9" y="145.2">G14</text>
<text x="217.9" y="147.8">F14</text>
<text x="65.8" y="154.1">IO_L23N_T3_A02_D18_14</text>
<text x="66.2" y="151.6">IO_L23P_T3_A03_D19_14</text>
<text x="95.8" y="150.3">U11</text>
<text x="95.8" y="152.9">V11</text>
<text x="95.8" y="155.4">U9</text>
<text x="189.5" y="154.1">IO_L23N_T3_FWE_B_15</text>
<text x="190.4" y="151.6">IO_L23P_T3_FOE_B_15</text>
<text x="217.9" y="150.3">H17</text>
<text x="217.9" y="152.9">H18</text>
<text x="217.9" y="155.4">F17</text>
<text x="65.8" y="159.2">IO_L24N_T3_A00_D16_14</text>
<text x="66.2" y="156.7">IO_L24P_T3_A01_D17_14</text>
<text x="82.8" y="161.8">IO_25_14</text>
<text x="95.8" y="157.9">V9</text>
<text x="95.8" y="160.5">U10</text>
<text x="193.1" y="159.2">IO_L24N_T3_RS0_15</text>
<text x="193.5" y="156.7">IO_L24P_T3_RS1_15</text>
<text x="204.9" y="161.8">IO_25_15</text>
<text x="217.9" y="157.9">E18</text>
<text x="217.9" y="160.5">H14</text>
<text x="4" y="178.3">D</text>
<text x="201.9" y="178.3">Title</text>
<text x="291.4" y="178.3">D</text>
<text x="201.9" y="185.9">Size</text>
<text x="214.6" y="185.9">Number</text>
<text x="265.5" y="185.9">Revision</text>
<text x="203.2" y="189.7">A4</text>
<text x="201.9" y="193.5">Date:</text>
<text x="201.9" y="196.1">File:</text>
<text x="213.3" y="193.5">10-19-2022</text>
<text x="213.4" y="196.1">C:\Users\..\FPGA_Banks_DDR3.SchDoc Drawn By:</text>
<text x="252.8" y="193.5">Sheet</text>
<text x="259.6" y="193.5">of</text>
<text x="37.9" y="199.9">1</text>
<text x="110.9" y="199.9">2</text>
<text x="184.1" y="199.9">3</text>
<text x="257.1" y="199.9">4</text>
</g>
<g font-size="2.3" fill="#000080">
<text x="53.1" y="33.3">U1A</text>
<text x="180.3" y="33.3">U1B</text>
<text x="127.6" y="43.3" transform="rotate(-90 127.6 43.3)">R58</text>
<text x="130.2" y="43.1" transform="rotate(-90 130.2 43.1)">100</text>
<text x="129.4" y="90.6">TP2</text>
<text x="129.4" y="95.6">TP3</text>
<text x="129.4" y="121.1">TP4</text>
<text x="144.7" y="130">TP5</text>
<text x="53.1" y="165.6">IC FPGA XC7A50T-2CSG325C</text>
<text x="180.3" y="165.6">IC FPGA XC7A50T-2CSG325C</text>
</g>
<g font-size="2.3" fill="#800000">
<text x="126.9" y="30.7">1V35</text>
<text x="104" y="38.4">SPI_DQ0_1V35</text>
<text x="104" y="40.9">SPI_DQ1_1V35</text>
<text x="226.1" y="38.4">DDR3_D10</text>
<text x="226.1" y="40.9">DDR3_D12</text>
<text x="104" y="43.5">SPI_DQ2_1V35</text>
<text x="104" y="46">SPI_DQ3_1V35</text>
<text x="226.1" y="43.5">DDR3_D14</text>
<text x="226.1" y="46">DDR3_D9</text>
<text x="104" y="53.6">DDR3_ODT</text>
<text x="104" y="51.1">DDR3_CAS</text>
<text x="104" y="48.6">PUDC</text>
<text x="226.1" y="48.6">DDR3_DQS1_P</text>
<text x="226.1" y="51.1">DDR3_DQS1_N</text>
<text x="226.1" y="53.6">DDR3_D13</text>
<text x="104" y="56.2">DDR3_CKE</text>
<text x="226.1" y="58.7">DDR3_DM1</text>
<text x="226.1" y="56.2">DDR3_D15</text>
<text x="104" y="63.8">SPI_CS_1V35</text>
<text x="104" y="61.3">DDR3_RAS</text>
<text x="226.1" y="61.3">DDR3_D8</text>
<text x="226.1" y="63.8">DDR3_D11</text>
<text x="104" y="66.4">DDR3_S0</text>
<text x="104" y="68.9">DDR3_WE</text>
<text x="104" y="71.5">DDR3_BA2</text>
<text x="226.1" y="71.5">DDR3_D1</text>
<text x="226.1" y="68.9">DDR3_DM0</text>
<text x="246.9" y="67.6">VTTREF</text>
<text x="226.1" y="76.5">DDR3_D4</text>
<text x="226.1" y="74">DDR3_D5</text>
<text x="104" y="81.6">DDR3_BA0</text>
<text x="226.1" y="79.1">DDR3_DQS0_P</text>
<text x="226.1" y="81.6">DDR3_DQS0_N</text>
<text x="104" y="84.2">DDR3_A10</text>
<text x="104" y="86.7">TEST_2</text>
<text x="226.1" y="89.3">DDR3_D6</text>
<text x="226.1" y="84.2">DDR3_D7</text>
<text x="226.1" y="86.7">DDR3_D2</text>
<text x="104" y="91.8">TEST_1</text>
<text x="226.1" y="91.8">DDR3_D3</text>
<text x="104" y="99.4">DDR3_A2</text>
<text x="104" y="102">DDR3_A1</text>
<text x="226.1" y="96.9">DDR3_D0</text>
<text x="226.1" y="102">DDR3_D22</text>
<text x="226.1" y="107.1">DDR3_D17</text>
<text x="226.1" y="104.5">DDR3_D18</text>
<text x="104" y="109.6">DDR3_BA1</text>
<text x="104" y="112.1">DDR3_A6</text>
<text x="226.1" y="109.6">DDR3_DQS2_P</text>
<text x="226.1" y="112.1">DDR3_DQS2_N</text>
<text x="104" y="114.7">DDR3_A9</text>
<text x="104" y="117.3">TEST_3</text>
<text x="226.1" y="114.7">DDR3_D20</text>
<text x="226.1" y="119.8">DDR3_D19</text>
<text x="226.1" y="117.3">DDR3_D16</text>
<text x="104" y="124.9">DDR3_A7</text>
<text x="226.1" y="124.9">DDR3_D23</text>
<text x="226.1" y="122.3">DDR3_DM2</text>
<text x="104" y="127.4">DDR3_A8</text>
<text x="226.1" y="130">DDR3_D24</text>
<text x="226.1" y="127.4">DDR3_D21</text>
<text x="104" y="132.5">DDR3_A12</text>
<text x="104" y="137.6">DDR3_A11</text>
<text x="139.7" y="137.6">GND</text>
<text x="226.1" y="135">DDR3_D28</text>
<text x="226.1" y="137.6">DDR3_DM3</text>
<text x="246.9" y="133.8">VTTREF</text>
<text x="104" y="140.1">DDR3_A4</text>
<text x="104" y="142.7">DDR3_A5</text>
<text x="226.1" y="140.1">DDR3_DQS3_P</text>
<text x="226.1" y="142.7">DDR3_DQS3_N</text>
<text x="104" y="145.2">DDR3_A0</text>
<text x="226.1" y="145.2">DDR3_D31</text>
<text x="226.1" y="147.8">DDR3_D29</text>
<text x="104" y="150.3">DDR3_RESET</text>
<text x="104" y="155.4">DDR3_CLK_P</text>
<text x="104" y="152.9">DDR3_A3</text>
<text x="226.1" y="152.9">DDR3_D30</text>
<text x="226.1" y="150.3">DDR3_D26</text>
<text x="226.1" y="155.4">DDR3_D25</text>
<text x="104" y="157.9">DDR3_CLK_N</text>
<text x="226.1" y="157.9">DDR3_D27</text>
</g>
</g></defs>
<path d="M2.2 8.4h292.6v193.3h-292.6z" fill-rule="evenodd" fill="#fffcf8"/>
<path d="M2.2 8.4h292.6v193.3h-292.6z" fill="none" stroke="#000" stroke-width=".21"/>
<path d="M7.3 13.5h282.4v183.1h-282.4z" fill-rule="evenodd" fill="#fffcf8"/>
<g fill="none" stroke="#000" stroke-width=".21">
<path d="M2.2 8.4h5.1M7.3 13.5h282.4v183.1h-282.4zM75.3 8.4v5.1M148.5 8.4v5.1M221.6 8.4v5.1M289.7 8.4h5.1v5.1M2.2 56.7h5.1M289.7 56.7h5.1M2.2 105h5.1M289.7 105.1h5.1M2.2 153.4h5.1M289.7 153.4h5.1"/>
<path d="M289.7 176.3h-89.1v20.3M75.3 196.6v5.1M148.5 196.6v5.1M200.6 183.9h89.1M200.6 191.5h89.1M200.6 194.1h89.1M213.4 183.9v7.6M221.6 196.6v5.1M251.5 191.5v5.1M264.2 183.9v7.6M294.8 196.6v5.1"/>
</g>
<path d="M223.5 66.9h20.4M223.5 133h20.4" fill="none" stroke="#fff0ff" stroke-width="1.3"/>
<path d="M129.4 33.8v2.6" fill="none" stroke="#ff0" stroke-width="1.3"/>
<path d="M53.1 33.8h40.7v129.8h-40.7z" fill-rule="evenodd" fill="#ffffb0"/>
<path d="M53.1 33.8h40.7v129.8h-40.7z" fill="none" stroke="#800000" stroke-width=".21"/>
<path d="M93.8 36.4h7.6" fill="none" stroke="#000" stroke-width=".25"/>
<path d="M93.8 36.4l1.5-.5v1z" fill="#f8fcff"/>
<path d="M93.8 36.4l1.5-.5v1z" fill="none" stroke="#000" stroke-width=".21"/>
<path d="M95.6 35.9l1.5 .5-1.5 .5z" fill="#f8fcff"/>
<path d="M95.6 35.9l1.5 .5-1.5 .5z" fill="none" stroke="#000" stroke-width=".21"/>
<path d="M93.8 38.9h7.6" fill="none" stroke="#000" stroke-width=".25"/>
<path d="M93.8 38.9l1.5-.5v1z" fill="#f8fcff"/>
<path d="M93.8 38.9l1.5-.5v1z" fill="none" stroke="#000" stroke-width=".21"/>
<path d="M95.6 38.4l1.5 .5-1.5 .5z" fill="#f8fcff"/>
<path d="M95.6 38.4l1.5 .5-1.5 .5z" fill="none" stroke="#000" stroke-width=".21"/>
<path d="M93.8 41.4h7.6" fill="none" stroke="#000" stroke-width=".25"/>
<path d="M93.8 41.4l1.5-.5v1.1z" fill="#f8fcff"/>
<path d="M93.8 41.4l1.5-.5v1.1z" fill="none" stroke="#000" stroke-width=".21"/>
<path d="M95.6 40.9l1.5 .5-1.5 .6z" fill="#f8fcff"/>
<path d="M95.6 40.9l1.5 .5-1.5 .6z" fill="none" stroke="#000" stroke-width=".21"/>
<path d="M93.8 44h7.6" fill="none" stroke="#000" stroke-width=".25"/>
<path d="M93.8 44l1.5-.5v1z" fill="#f8fcff"/>
<path d="M93.8 44l1.5-.5v1z" fill="none" stroke="#000" stroke-width=".21"/>
<path d="M95.6 43.5l1.5 .5-1.5 .5z" fill="#f8fcff"/>
<path d="M95.6 43.5l1.5 .5-1.5 .5z" fill="none" stroke="#000" stroke-width=".21"/>
<path d="M93.8 46.5h7.6" fill="none" stroke="#000" stroke-width=".25"/>
<path d="M93.8 46.5l1.5-.5v1z" fill="#f8fcff"/>
<path d="M93.8 46.5l1.5-.5v1z" fill="none" stroke="#000" stroke-width=".21"/>
<path d="M95.6 46l1.5 .5-1.5 .5z" fill="#f8fcff"/>
<path d="M95.6 46l1.5 .5-1.5 .5z" fill="none" stroke="#000" stroke-width=".21"/>
<path d="M93.8 49.1h7.6" fill="none" stroke="#000" stroke-width=".25"/>
<path d="M93.8 49.1l1.5-.5v1z" fill="#f8fcff"/>
<path d="M93.8 49.1l1.5-.5v1z" fill="none" stroke="#000" stroke-width=".21"/>
<path d="M95.6 48.6l1.5 .5-1.5 .5z" fill="#f8fcff"/>
<path d="M95.6 48.6l1.5 .5-1.5 .5z" fill="none" stroke="#000" stroke-width=".21"/>
<path d="M93.8 51.6h7.6" fill="none" stroke="#000" stroke-width=".25"/>
<path d="M93.8 51.6l1.5-.5v1z" fill="#f8fcff"/>
<path d="M93.8 51.6l1.5-.5v1z" fill="none" stroke="#000" stroke-width=".21"/>
<path d="M95.6 51.1l1.5 .5-1.5 .5z" fill="#f8fcff"/>
<path d="M93.8 51.1l-1 .5 1 .5M95.6 51.1l1.5 .5-1.5 .5z" fill="none" stroke="#000" stroke-width=".21"/>
<path d="M93.8 54.2h7.6" fill="none" stroke="#000" stroke-width=".25"/>
<path d="M93.8 54.2l1.5-.5v1z" fill="#f8fcff"/>
<path d="M93.8 54.2l1.5-.5v1z" fill="none" stroke="#000" stroke-width=".21"/>
<path d="M95.6 53.7l1.5 .5-1.5 .5z" fill="#f8fcff"/>
<path d="M95.6 53.7l1.5 .5-1.5 .5z" fill="none" stroke="#000" stroke-width=".21"/>
<path d="M93.8 56.7h7.6" fill="none" stroke="#000" stroke-width=".25"/>
<path d="M93.8 56.7l1.5-.5v1z" fill="#f8fcff"/>
<path d="M93.8 56.7l1.5-.5v1z" fill="none" stroke="#000" stroke-width=".21"/>
<path d="M95.6 56.2l1.5 .5-1.5 .5z" fill="#f8fcff"/>
<path d="M95.6 56.2l1.5 .5-1.5 .5z" fill="none" stroke="#000" stroke-width=".21"/>
<path d="M93.8 59.3h7.6" fill="none" stroke="#000" stroke-width=".25"/>
<path d="M93.8 59.3l1.5-.6v1.1z" fill="#f8fcff"/>
<path d="M93.8 59.3l1.5-.6v1.1z" fill="none" stroke="#000" stroke-width=".21"/>
<path d="M95.6 58.7l1.5 .6-1.5 .5z" fill="#f8fcff"/>
<path d="M95.6 58.7l1.5 .6-1.5 .5z" fill="none" stroke="#000" stroke-width=".21"/>
<path d="M93.8 61.8h7.6" fill="none" stroke="#000" stroke-width=".25"/>
<path d="M93.8 61.8l1.5-.5v1z" fill="#f8fcff"/>
<path d="M93.8 61.8l1.5-.5v1z" fill="none" stroke="#000" stroke-width=".21"/>
<path d="M95.6 61.3l1.5 .5-1.5 .5z" fill="#f8fcff"/>
<path d="M95.6 61.3l1.5 .5-1.5 .5z" fill="none" stroke="#000" stroke-width=".21"/>
<path d="M93.8 64.3h7.6" fill="none" stroke="#000" stroke-width=".25"/>
<path d="M93.8 64.3l1.5-.5v1z" fill="#f8fcff"/>
<path d="M93.8 64.3l1.5-.5v1z" fill="none" stroke="#000" stroke-width=".21"/>
<path d="M95.6 63.8l1.5 .5-1.5 .5z" fill="#f8fcff"/>
<path d="M95.6 63.8l1.5 .5-1.5 .5z" fill="none" stroke="#000" stroke-width=".21"/>
<path d="M93.8 66.9h7.6" fill="none" stroke="#000" stroke-width=".25"/>
<path d="M93.8 66.9l1.5-.5v1z" fill="#f8fcff"/>
<path d="M93.8 66.9l1.5-.5v1z" fill="none" stroke="#000" stroke-width=".21"/>
<path d="M95.6 66.4l1.5 .5-1.5 .5z" fill="#f8fcff"/>
<path d="M95.6 66.4l1.5 .5-1.5 .5z" fill="none" stroke="#000" stroke-width=".21"/>
<path d="M93.8 69.4h7.6" fill="none" stroke="#000" stroke-width=".25"/>
<path d="M93.8 69.4l1.5-.5v1z" fill="#f8fcff"/>
<path d="M93.8 69.4l1.5-.5v1z" fill="none" stroke="#000" stroke-width=".21"/>
<path d="M95.6 68.9l1.5 .5-1.5 .5z" fill="#f8fcff"/>
<path d="M95.6 68.9l1.5 .5-1.5 .5z" fill="none" stroke="#000" stroke-width=".21"/>
<path d="M93.8 72h7.6" fill="none" stroke="#000" stroke-width=".25"/>
<path d="M93.8 72l1.5-.5v1z" fill="#f8fcff"/>
<path d="M93.8 72l1.5-.5v1z" fill="none" stroke="#000" stroke-width=".21"/>
<path d="M95.6 71.5l1.5 .5-1.5 .5z" fill="#f8fcff"/>
<path d="M95.6 71.5l1.5 .5-1.5 .5z" fill="none" stroke="#000" stroke-width=".21"/>
<path d="M93.8 74.5h7.6" fill="none" stroke="#000" stroke-width=".25"/>
<path d="M93.8 74.5l1.5-.5v1z" fill="#f8fcff"/>
<path d="M93.8 74.5l1.5-.5v1z" fill="none" stroke="#000" stroke-width=".21"/>
<path d="M95.6 74l1.5 .5-1.5 .5z" fill="#f8fcff"/>
<path d="M95.6 74l1.5 .5-1.5 .5z" fill="none" stroke="#000" stroke-width=".21"/>
<path d="M93.8 77.1h7.6" fill="none" stroke="#000" stroke-width=".25"/>
<path d="M93.8 77.1l1.5-.5v1z" fill="#f8fcff"/>
<path d="M93.8 77.1l1.5-.5v1z" fill="none" stroke="#000" stroke-width=".21"/>
<path d="M95.6 76.6l1.5 .5-1.5 .5z" fill="#f8fcff"/>
<path d="M95.6 76.6l1.5 .5-1.5 .5z" fill="none" stroke="#000" stroke-width=".21"/>
<path d="M93.8 79.6h7.6" fill="none" stroke="#000" stroke-width=".25"/>
<path d="M93.8 79.6l1.5-.5v1z" fill="#f8fcff"/>
<path d="M93.8 79.6l1.5-.5v1z" fill="none" stroke="#000" stroke-width=".21"/>
<path d="M95.6 79.1l1.5 .5-1.5 .5z" fill="#f8fcff"/>
<path d="M95.6 79.1l1.5 .5-1.5 .5z" fill="none" stroke="#000" stroke-width=".21"/>
<path d="M93.8 82.1h7.6" fill="none" stroke="#000" stroke-width=".25"/>
<path d="M93.8 82.1l1.5-.5v1.1z" fill="#f8fcff"/>
<path d="M93.8 82.1l1.5-.5v1.1z" fill="none" stroke="#000" stroke-width=".21"/>
<path d="M95.6 81.6l1.5 .5-1.5 .6z" fill="#f8fcff"/>
<path d="M95.6 81.6l1.5 .5-1.5 .6z" fill="none" stroke="#000" stroke-width=".21"/>
<path d="M93.8 84.7h7.6" fill="none" stroke="#000" stroke-width=".25"/>
<path d="M93.8 84.7l1.5-.5v1z" fill="#f8fcff"/>
<path d="M93.8 84.7l1.5-.5v1z" fill="none" stroke="#000" stroke-width=".21"/>
<path d="M95.6 84.2l1.5 .5-1.5 .5z" fill="#f8fcff"/>
<path d="M95.6 84.2l1.5 .5-1.5 .5z" fill="none" stroke="#000" stroke-width=".21"/>
<path d="M93.8 87.2h7.6" fill="none" stroke="#000" stroke-width=".25"/>
<path d="M93.8 87.2l1.5-.5v1z" fill="#f8fcff"/>
<path d="M93.8 87.2l1.5-.5v1z" fill="none" stroke="#000" stroke-width=".21"/>
<path d="M95.6 86.7l1.5 .5-1.5 .5z" fill="#f8fcff"/>
<path d="M95.6 86.7l1.5 .5-1.5 .5z" fill="none" stroke="#000" stroke-width=".21"/>
<path d="M93.8 89.8h7.6" fill="none" stroke="#000" stroke-width=".25"/>
<path d="M93.8 89.8l1.5-.5v1z" fill="#f8fcff"/>
<path d="M93.8 89.8l1.5-.5v1z" fill="none" stroke="#000" stroke-width=".21"/>
<path d="M95.6 89.3l1.5 .5-1.5 .5z" fill="#f8fcff"/>
<path d="M93.8 89.3l-1 .5 1 .5M95.6 89.3l1.5 .5-1.5 .5z" fill="none" stroke="#000" stroke-width=".21"/>
<path d="M93.8 92.3h7.6" fill="none" stroke="#000" stroke-width=".25"/>
<path d="M93.8 92.3l1.5-.5v1z" fill="#f8fcff"/>
<path d="M93.8 92.3l1.5-.5v1z" fill="none" stroke="#000" stroke-width=".21"/>
<path d="M95.6 91.8l1.5 .5-1.5 .5z" fill="#f8fcff"/>
<path d="M93.8 91.8l-1 .5 1 .5M95.6 91.8l1.5 .5-1.5 .5z" fill="none" stroke="#000" stroke-width=".21"/>
<path d="M93.8 94.9h7.6" fill="none" stroke="#000" stroke-width=".25"/>
<path d="M93.8 94.9l1.5-.5v1z" fill="#f8fcff"/>
<path d="M93.8 94.9l1.5-.5v1z" fill="none" stroke="#000" stroke-width=".21"/>
<path d="M95.6 94.4l1.5 .5-1.5 .5z" fill="#f8fcff"/>
<path d="M93.8 94.4l-1 .5 1 .5M95.6 94.4l1.5 .5-1.5 .5z" fill="none" stroke="#000" stroke-width=".21"/>
<path d="M93.8 97.4h7.6" fill="none" stroke="#000" stroke-width=".25"/>
<path d="M93.8 97.4l1.5-.5v1z" fill="#f8fcff"/>
<path d="M93.8 97.4l1.5-.5v1z" fill="none" stroke="#000" stroke-width=".21"/>
<path d="M95.6 96.9l1.5 .5-1.5 .5z" fill="#f8fcff"/>
<path d="M93.8 96.9l-1 .5 1 .5M95.6 96.9l1.5 .5-1.5 .5z" fill="none" stroke="#000" stroke-width=".21"/>
<path d="M93.8 100h7.6" fill="none" stroke="#000" stroke-width=".25"/>
<path d="M93.8 100l1.5-.6v1.1z" fill="#f8fcff"/>
<path d="M93.8 100l1.5-.6v1.1z" fill="none" stroke="#000" stroke-width=".21"/>
<path d="M95.6 99.4l1.5 .6-1.5 .5z" fill="#f8fcff"/>
<path d="M93.8 99.4l-1 .6 1 .5M95.6 99.4l1.5 .6-1.5 .5z" fill="none" stroke="#000" stroke-width=".21"/>
<path d="M93.8 102.5h7.6" fill="none" stroke="#000" stroke-width=".25"/>
<path d="M93.8 102.5l1.5-.5v1z" fill="#f8fcff"/>
<path d="M93.8 102.5l1.5-.5v1z" fill="none" stroke="#000" stroke-width=".21"/>
<path d="M95.6 102l1.5 .5-1.5 .5z" fill="#f8fcff"/>
<path d="M93.8 102l-1 .5 1 .5M95.6 102l1.5 .5-1.5 .5z" fill="none" stroke="#000" stroke-width=".21"/>
<path d="M93.8 105h7.6" fill="none" stroke="#000" stroke-width=".25"/>
<path d="M93.8 105l1.5-.5v1.1z" fill="#f8fcff"/>
<path d="M93.8 105l1.5-.5v1.1z" fill="none" stroke="#000" stroke-width=".21"/>
<path d="M95.6 104.5l1.5 .5-1.5 .6z" fill="#f8fcff"/>
<path d="M93.8 104.5l-1 .5 1 .6M95.6 104.5l1.5 .5-1.5 .6z" fill="none" stroke="#000" stroke-width=".21"/>
<path d="M93.8 107.6h7.6" fill="none" stroke="#000" stroke-width=".25"/>
<path d="M93.8 107.6l1.5-.5v1z" fill="#f8fcff"/>
<path d="M93.8 107.6l1.5-.5v1z" fill="none" stroke="#000" stroke-width=".21"/>
<path d="M95.6 107.1l1.5 .5-1.5 .5z" fill="#f8fcff"/>
<path d="M93.8 107.1l-1 .5 1 .5M95.6 107.1l1.5 .5-1.5 .5z" fill="none" stroke="#000" stroke-width=".21"/>
<path d="M93.8 110.1h7.6" fill="none" stroke="#000" stroke-width=".25"/>
<path d="M93.8 110.1l1.5-.5v1z" fill="#f8fcff"/>
<path d="M93.8 110.1l1.5-.5v1z" fill="none" stroke="#000" stroke-width=".21"/>
<path d="M95.6 109.6l1.5 .5-1.5 .5z" fill="#f8fcff"/>
<path d="M95.6 109.6l1.5 .5-1.5 .5z" fill="none" stroke="#000" stroke-width=".21"/>
<path d="M93.8 112.7h7.6" fill="none" stroke="#000" stroke-width=".25"/>
<path d="M93.8 112.7l1.5-.5v1z" fill="#f8fcff"/>
<path d="M93.8 112.7l1.5-.5v1z" fill="none" stroke="#000" stroke-width=".21"/>
<path d="M95.6 112.2l1.5 .5-1.5 .5z" fill="#f8fcff"/>
<path d="M95.6 112.2l1.5 .5-1.5 .5z" fill="none" stroke="#000" stroke-width=".21"/>
<path d="M93.8 115.2h7.6" fill="none" stroke="#000" stroke-width=".25"/>
<path d="M93.8 115.2l1.5-.5v1z" fill="#f8fcff"/>
<path d="M93.8 115.2l1.5-.5v1z" fill="none" stroke="#000" stroke-width=".21"/>
<path d="M95.6 114.7l1.5 .5-1.5 .5z" fill="#f8fcff"/>
<path d="M95.6 114.7l1.5 .5-1.5 .5z" fill="none" stroke="#000" stroke-width=".21"/>
<path d="M93.8 117.8h7.6" fill="none" stroke="#000" stroke-width=".25"/>
<path d="M93.8 117.8l1.5-.5v1z" fill="#f8fcff"/>
<path d="M93.8 117.8l1.5-.5v1z" fill="none" stroke="#000" stroke-width=".21"/>
<path d="M95.6 117.3l1.5 .5-1.5 .5z" fill="#f8fcff"/>
<path d="M95.6 117.3l1.5 .5-1.5 .5z" fill="none" stroke="#000" stroke-width=".21"/>
<path d="M93.8 120.3h7.6" fill="none" stroke="#000" stroke-width=".25"/>
<path d="M93.8 120.3l1.5-.5v1z" fill="#f8fcff"/>
<path d="M93.8 120.3l1.5-.5v1z" fill="none" stroke="#000" stroke-width=".21"/>
<path d="M95.6 119.8l1.5 .5-1.5 .5z" fill="#f8fcff"/>
<path d="M95.6 119.8l1.5 .5-1.5 .5z" fill="none" stroke="#000" stroke-width=".21"/>
<path d="M93.8 122.9h7.6" fill="none" stroke="#000" stroke-width=".25"/>
<path d="M93.8 122.9l1.5-.6v1.1z" fill="#f8fcff"/>
<path d="M93.8 122.9l1.5-.6v1.1z" fill="none" stroke="#000" stroke-width=".21"/>
<path d="M95.6 122.3l1.5 .6-1.5 .5z" fill="#f8fcff"/>
<path d="M95.6 122.3l1.5 .6-1.5 .5z" fill="none" stroke="#000" stroke-width=".21"/>
<path d="M93.8 125.4h7.6" fill="none" stroke="#000" stroke-width=".25"/>
<path d="M93.8 125.4l1.5-.5v1z" fill="#f8fcff"/>
<path d="M93.8 125.4l1.5-.5v1z" fill="none" stroke="#000" stroke-width=".21"/>
<path d="M95.6 124.9l1.5 .5-1.5 .5z" fill="#f8fcff"/>
<path d="M95.6 124.9l1.5 .5-1.5 .5z" fill="none" stroke="#000" stroke-width=".21"/>
<path d="M93.8 127.9h7.6" fill="none" stroke="#000" stroke-width=".25"/>
<path d="M93.8 127.9l1.5-.5v1z" fill="#f8fcff"/>
<path d="M93.8 127.9l1.5-.5v1z" fill="none" stroke="#000" stroke-width=".21"/>
<path d="M95.6 127.4l1.5 .5-1.5 .5z" fill="#f8fcff"/>
<path d="M95.6 127.4l1.5 .5-1.5 .5z" fill="none" stroke="#000" stroke-width=".21"/>
<path d="M93.8 130.5h7.6" fill="none" stroke="#000" stroke-width=".25"/>
<path d="M93.8 130.5l1.5-.5v1z" fill="#f8fcff"/>
<path d="M93.8 130.5l1.5-.5v1z" fill="none" stroke="#000" stroke-width=".21"/>
<path d="M95.6 130l1.5 .5-1.5 .5z" fill="#f8fcff"/>
<path d="M95.6 130l1.5 .5-1.5 .5z" fill="none" stroke="#000" stroke-width=".21"/>
<path d="M93.8 133h7.6" fill="none" stroke="#000" stroke-width=".25"/>
<path d="M93.8 133l1.5-.5v1z" fill="#f8fcff"/>
<path d="M93.8 133l1.5-.5v1z" fill="none" stroke="#000" stroke-width=".21"/>
<path d="M95.6 132.5l1.5 .5-1.5 .5z" fill="#f8fcff"/>
<path d="M95.6 132.5l1.5 .5-1.5 .5z" fill="none" stroke="#000" stroke-width=".21"/>
<path d="M93.8 135.6h7.6" fill="none" stroke="#000" stroke-width=".25"/>
<path d="M93.8 135.6l1.5-.5v1z" fill="#f8fcff"/>
<path d="M93.8 135.6l1.5-.5v1z" fill="none" stroke="#000" stroke-width=".21"/>
<path d="M95.6 135.1l1.5 .5-1.5 .5z" fill="#f8fcff"/>
<path d="M95.6 135.1l1.5 .5-1.5 .5z" fill="none" stroke="#000" stroke-width=".21"/>
<path d="M93.8 138.1h7.6" fill="none" stroke="#000" stroke-width=".25"/>
<path d="M93.8 138.1l1.5-.5v1z" fill="#f8fcff"/>
<path d="M93.8 138.1l1.5-.5v1z" fill="none" stroke="#000" stroke-width=".21"/>
<path d="M95.6 137.6l1.5 .5-1.5 .5z" fill="#f8fcff"/>
<path d="M95.6 137.6l1.5 .5-1.5 .5z" fill="none" stroke="#000" stroke-width=".21"/>
<path d="M93.8 140.7h7.6" fill="none" stroke="#000" stroke-width=".25"/>
<path d="M93.8 140.7l1.5-.6v1.1z" fill="#f8fcff"/>
<path d="M93.8 140.7l1.5-.6v1.1z" fill="none" stroke="#000" stroke-width=".21"/>
<path d="M95.6 140.1l1.5 .6-1.5 .5z" fill="#f8fcff"/>
<path d="M95.6 140.1l1.5 .6-1.5 .5z" fill="none" stroke="#000" stroke-width=".21"/>
<path d="M93.8 143.2h7.6" fill="none" stroke="#000" stroke-width=".25"/>
<path d="M93.8 143.2l1.5-.5v1z" fill="#f8fcff"/>
<path d="M93.8 143.2l1.5-.5v1z" fill="none" stroke="#000" stroke-width=".21"/>
<path d="M95.6 142.7l1.5 .5-1.5 .5z" fill="#f8fcff"/>
<path d="M95.6 142.7l1.5 .5-1.5 .5z" fill="none" stroke="#000" stroke-width=".21"/>
<path d="M93.8 145.7h7.6" fill="none" stroke="#000" stroke-width=".25"/>
<path d="M93.8 145.7l1.5-.5v1.1z" fill="#f8fcff"/>
<path d="M93.8 145.7l1.5-.5v1.1z" fill="none" stroke="#000" stroke-width=".21"/>
<path d="M95.6 145.2l1.5 .5-1.5 .6z" fill="#f8fcff"/>
<path d="M95.6 145.2l1.5 .5-1.5 .6z" fill="none" stroke="#000" stroke-width=".21"/>
<path d="M93.8 148.3h7.6" fill="none" stroke="#000" stroke-width=".25"/>
<path d="M93.8 148.3l1.5-.5v1z" fill="#f8fcff"/>
<path d="M93.8 148.3l1.5-.5v1z" fill="none" stroke="#000" stroke-width=".21"/>
<path d="M95.6 147.8l1.5 .5-1.5 .5z" fill="#f8fcff"/>
<path d="M95.6 147.8l1.5 .5-1.5 .5z" fill="none" stroke="#000" stroke-width=".21"/>
<path d="M93.8 150.8h7.6" fill="none" stroke="#000" stroke-width=".25"/>
<path d="M93.8 150.8l1.5-.5v1z" fill="#f8fcff"/>
<path d="M93.8 150.8l1.5-.5v1z" fill="none" stroke="#000" stroke-width=".21"/>
<path d="M95.6 150.3l1.5 .5-1.5 .5z" fill="#f8fcff"/>
<path d="M95.6 150.3l1.5 .5-1.5 .5z" fill="none" stroke="#000" stroke-width=".21"/>
<path d="M93.8 153.4h7.6" fill="none" stroke="#000" stroke-width=".25"/>
<path d="M93.8 153.4l1.5-.5v1z" fill="#f8fcff"/>
<path d="M93.8 153.4l1.5-.5v1z" fill="none" stroke="#000" stroke-width=".21"/>
<path d="M95.6 152.9l1.5 .5-1.5 .5z" fill="#f8fcff"/>
<path d="M95.6 152.9l1.5 .5-1.5 .5z" fill="none" stroke="#000" stroke-width=".21"/>
<path d="M93.8 155.9h7.6" fill="none" stroke="#000" stroke-width=".25"/>
<path d="M93.8 155.9l1.5-.5v1z" fill="#f8fcff"/>
<path d="M93.8 155.9l1.5-.5v1z" fill="none" stroke="#000" stroke-width=".21"/>
<path d="M95.6 155.4l1.5 .5-1.5 .5z" fill="#f8fcff"/>
<path d="M95.6 155.4l1.5 .5-1.5 .5z" fill="none" stroke="#000" stroke-width=".21"/>
<path d="M93.8 158.5h7.6" fill="none" stroke="#000" stroke-width=".25"/>
<path d="M93.8 158.5l1.5-.5v1z" fill="#f8fcff"/>
<path d="M93.8 158.5l1.5-.5v1z" fill="none" stroke="#000" stroke-width=".21"/>
<path d="M95.6 158l1.5 .5-1.5 .5z" fill="#f8fcff"/>
<path d="M95.6 158l1.5 .5-1.5 .5z" fill="none" stroke="#000" stroke-width=".21"/>
<path d="M93.8 161h7.6" fill="none" stroke="#000" stroke-width=".25"/>
<path d="M93.8 161l1.5-.5v1z" fill="#f8fcff"/>
<path d="M93.8 161l1.5-.5v1z" fill="none" stroke="#000" stroke-width=".21"/>
<path d="M95.6 160.5l1.5 .5-1.5 .5z" fill="#f8fcff"/>
<path d="M95.6 160.5l1.5 .5-1.5 .5z" fill="none" stroke="#000" stroke-width=".21"/>
<path d="M180.3 33.8h35.6v129.8h-35.6z" fill-rule="evenodd" fill="#ffffb0"/>
<path d="M180.3 33.8h35.6v129.8h-35.6z" fill="none" stroke="#800000" stroke-width=".21"/>
<path d="M215.9 36.4h7.6" fill="none" stroke="#000" stroke-width=".25"/>
<path d="M215.9 36.4l1.5-.6v1.1z" fill="#f8fcff"/>
<path d="M215.9 36.4l1.5-.6v1.1z" fill="none" stroke="#000" stroke-width=".21"/>
<path d="M217.7 35.8l1.5 .6-1.5 .5z" fill="#f8fcff"/>
<path d="M217.7 35.8l1.5 .6-1.5 .5z" fill="none" stroke="#000" stroke-width=".21"/>
<path d="M215.9 38.9h7.6" fill="none" stroke="#000" stroke-width=".25"/>
<path d="M215.9 38.9l1.5-.5v1z" fill="#f8fcff"/>
<path d="M215.9 38.9l1.5-.5v1z" fill="none" stroke="#000" stroke-width=".21"/>
<path d="M217.7 38.4l1.5 .5-1.5 .5z" fill="#f8fcff"/>
<path d="M217.7 38.4l1.5 .5-1.5 .5z" fill="none" stroke="#000" stroke-width=".21"/>
<path d="M215.9 41.4h7.6" fill="none" stroke="#000" stroke-width=".25"/>
<path d="M215.9 41.4l1.5-.5v1.1z" fill="#f8fcff"/>
<path d="M215.9 41.4l1.5-.5v1.1z" fill="none" stroke="#000" stroke-width=".21"/>
<path d="M217.7 40.9l1.5 .5-1.5 .6z" fill="#f8fcff"/>
<path d="M217.7 40.9l1.5 .5-1.5 .6z" fill="none" stroke="#000" stroke-width=".21"/>
<path d="M215.9 44h7.6" fill="none" stroke="#000" stroke-width=".25"/>
<path d="M215.9 44l1.5-.5v1z" fill="#f8fcff"/>
<path d="M215.9 44l1.5-.5v1z" fill="none" stroke="#000" stroke-width=".21"/>
<path d="M217.7 43.5l1.5 .5-1.5 .5z" fill="#f8fcff"/>
<path d="M217.7 43.5l1.5 .5-1.5 .5z" fill="none" stroke="#000" stroke-width=".21"/>
<path d="M215.9 46.5h7.6" fill="none" stroke="#000" stroke-width=".25"/>
<path d="M215.9 46.5l1.5-.5v1z" fill="#f8fcff"/>
<path d="M215.9 46.5l1.5-.5v1z" fill="none" stroke="#000" stroke-width=".21"/>
<path d="M217.7 46l1.5 .5-1.5 .5z" fill="#f8fcff"/>
<path d="M217.7 46l1.5 .5-1.5 .5z" fill="none" stroke="#000" stroke-width=".21"/>
<path d="M215.9 49.1h7.6" fill="none" stroke="#000" stroke-width=".25"/>
<path d="M215.9 49.1l1.5-.5v1z" fill="#f8fcff"/>
<path d="M215.9 49.1l1.5-.5v1z" fill="none" stroke="#000" stroke-width=".21"/>
<path d="M217.7 48.6l1.5 .5-1.5 .5z" fill="#f8fcff"/>
<path d="M217.7 48.6l1.5 .5-1.5 .5z" fill="none" stroke="#000" stroke-width=".21"/>
<path d="M215.9 51.6h7.6" fill="none" stroke="#000" stroke-width=".25"/>
<path d="M215.9 51.6l1.5-.5v1z" fill="#f8fcff"/>
<path d="M215.9 51.6l1.5-.5v1z" fill="none" stroke="#000" stroke-width=".21"/>
<path d="M217.7 51.1l1.5 .5-1.5 .5z" fill="#f8fcff"/>
<path d="M217.7 51.1l1.5 .5-1.5 .5z" fill="none" stroke="#000" stroke-width=".21"/>
<path d="M215.9 54.2h7.6" fill="none" stroke="#000" stroke-width=".25"/>
<path d="M215.9 54.2l1.5-.5v1z" fill="#f8fcff"/>
<path d="M215.9 54.2l1.5-.5v1z" fill="none" stroke="#000" stroke-width=".21"/>
<path d="M217.7 53.7l1.5 .5-1.5 .5z" fill="#f8fcff"/>
<path d="M217.7 53.7l1.5 .5-1.5 .5z" fill="none" stroke="#000" stroke-width=".21"/>
<path d="M215.9 56.7h7.6" fill="none" stroke="#000" stroke-width=".25"/>
<path d="M215.9 56.7l1.5-.5v1z" fill="#f8fcff"/>
<path d="M215.9 56.7l1.5-.5v1z" fill="none" stroke="#000" stroke-width=".21"/>
<path d="M217.7 56.2l1.5 .5-1.5 .5z" fill="#f8fcff"/>
<path d="M217.7 56.2l1.5 .5-1.5 .5z" fill="none" stroke="#000" stroke-width=".21"/>
<path d="M215.9 59.3h7.6" fill="none" stroke="#000" stroke-width=".25"/>
<path d="M215.9 59.3l1.5-.6v1.1z" fill="#f8fcff"/>
<path d="M215.9 59.3l1.5-.6v1.1z" fill="none" stroke="#000" stroke-width=".21"/>
<path d="M217.7 58.7l1.5 .6-1.5 .5z" fill="#f8fcff"/>
<path d="M217.7 58.7l1.5 .6-1.5 .5z" fill="none" stroke="#000" stroke-width=".21"/>
<path d="M215.9 61.8h7.6" fill="none" stroke="#000" stroke-width=".25"/>
<path d="M215.9 61.8l1.5-.5v1z" fill="#f8fcff"/>
<path d="M215.9 61.8l1.5-.5v1z" fill="none" stroke="#000" stroke-width=".21"/>
<path d="M217.7 61.3l1.5 .5-1.5 .5z" fill="#f8fcff"/>
<path d="M217.7 61.3l1.5 .5-1.5 .5z" fill="none" stroke="#000" stroke-width=".21"/>
<path d="M215.9 64.3h7.6" fill="none" stroke="#000" stroke-width=".25"/>
<path d="M215.9 64.3l1.5-.5v1.1z" fill="#f8fcff"/>
<path d="M215.9 64.3l1.5-.5v1.1z" fill="none" stroke="#000" stroke-width=".21"/>
<path d="M217.7 63.8l1.5 .5-1.5 .6z" fill="#f8fcff"/>
<path d="M217.7 63.8l1.5 .5-1.5 .6z" fill="none" stroke="#000" stroke-width=".21"/>
<path d="M215.9 66.9h7.6" fill="none" stroke="#000" stroke-width=".25"/>
<path d="M215.9 66.9l1.5-.5v1z" fill="#f8fcff"/>
<path d="M215.9 66.9l1.5-.5v1z" fill="none" stroke="#000" stroke-width=".21"/>
<path d="M217.7 66.4l1.5 .5-1.5 .5z" fill="#f8fcff"/>
<path d="M217.7 66.4l1.5 .5-1.5 .5z" fill="none" stroke="#000" stroke-width=".21"/>
<path d="M215.9 69.4h7.6" fill="none" stroke="#000" stroke-width=".25"/>
<path d="M215.9 69.4l1.5-.5v1z" fill="#f8fcff"/>
<path d="M215.9 69.4l1.5-.5v1z" fill="none" stroke="#000" stroke-width=".21"/>
<path d="M217.7 68.9l1.5 .5-1.5 .5z" fill="#f8fcff"/>
<path d="M217.7 68.9l1.5 .5-1.5 .5z" fill="none" stroke="#000" stroke-width=".21"/>
<path d="M215.9 72h7.6" fill="none" stroke="#000" stroke-width=".25"/>
<path d="M215.9 72l1.5-.5v1z" fill="#f8fcff"/>
<path d="M215.9 72l1.5-.5v1z" fill="none" stroke="#000" stroke-width=".21"/>
<path d="M217.7 71.5l1.5 .5-1.5 .5z" fill="#f8fcff"/>
<path d="M217.7 71.5l1.5 .5-1.5 .5z" fill="none" stroke="#000" stroke-width=".21"/>
<path d="M215.9 74.5h7.6" fill="none" stroke="#000" stroke-width=".25"/>
<path d="M215.9 74.5l1.5-.5v1z" fill="#f8fcff"/>
<path d="M215.9 74.5l1.5-.5v1z" fill="none" stroke="#000" stroke-width=".21"/>
<path d="M217.7 74l1.5 .5-1.5 .5z" fill="#f8fcff"/>
<path d="M217.7 74l1.5 .5-1.5 .5z" fill="none" stroke="#000" stroke-width=".21"/>
<path d="M215.9 77.1h7.6" fill="none" stroke="#000" stroke-width=".25"/>
<path d="M215.9 77.1l1.5-.5v1z" fill="#f8fcff"/>
<path d="M215.9 77.1l1.5-.5v1z" fill="none" stroke="#000" stroke-width=".21"/>
<path d="M217.7 76.6l1.5 .5-1.5 .5z" fill="#f8fcff"/>
<path d="M217.7 76.6l1.5 .5-1.5 .5z" fill="none" stroke="#000" stroke-width=".21"/>
<path d="M215.9 79.6h7.6" fill="none" stroke="#000" stroke-width=".25"/>
<path d="M215.9 79.6l1.5-.5v1z" fill="#f8fcff"/>
<path d="M215.9 79.6l1.5-.5v1z" fill="none" stroke="#000" stroke-width=".21"/>
<path d="M217.7 79.1l1.5 .5-1.5 .5z" fill="#f8fcff"/>
<path d="M217.7 79.1l1.5 .5-1.5 .5z" fill="none" stroke="#000" stroke-width=".21"/>
<path d="M215.9 82.1h7.6" fill="none" stroke="#000" stroke-width=".25"/>
<path d="M215.9 82.1l1.5-.5v1.1z" fill="#f8fcff"/>
<path d="M215.9 82.1l1.5-.5v1.1z" fill="none" stroke="#000" stroke-width=".21"/>
<path d="M217.7 81.6l1.5 .5-1.5 .6z" fill="#f8fcff"/>
<path d="M217.7 81.6l1.5 .5-1.5 .6z" fill="none" stroke="#000" stroke-width=".21"/>
<path d="M215.9 84.7h7.6" fill="none" stroke="#000" stroke-width=".25"/>
<path d="M215.9 84.7l1.5-.5v1z" fill="#f8fcff"/>
<path d="M215.9 84.7l1.5-.5v1z" fill="none" stroke="#000" stroke-width=".21"/>
<path d="M217.7 84.2l1.5 .5-1.5 .5z" fill="#f8fcff"/>
<path d="M217.7 84.2l1.5 .5-1.5 .5z" fill="none" stroke="#000" stroke-width=".21"/>
<path d="M215.9 87.2h7.6" fill="none" stroke="#000" stroke-width=".25"/>
<path d="M215.9 87.2l1.5-.5v1z" fill="#f8fcff"/>
<path d="M215.9 87.2l1.5-.5v1z" fill="none" stroke="#000" stroke-width=".21"/>
<path d="M217.7 86.7l1.5 .5-1.5 .5z" fill="#f8fcff"/>
<path d="M217.7 86.7l1.5 .5-1.5 .5z" fill="none" stroke="#000" stroke-width=".21"/>
<path d="M215.9 89.8h7.6" fill="none" stroke="#000" stroke-width=".25"/>
<path d="M215.9 89.8l1.5-.5v1z" fill="#f8fcff"/>
<path d="M215.9 89.8l1.5-.5v1z" fill="none" stroke="#000" stroke-width=".21"/>
<path d="M217.7 89.3l1.5 .5-1.5 .5z" fill="#f8fcff"/>
<path d="M215.9 89.3l-1 .5 1 .5M217.7 89.3l1.5 .5-1.5 .5z" fill="none" stroke="#000" stroke-width=".21"/>
<path d="M215.9 92.3h7.6" fill="none" stroke="#000" stroke-width=".25"/>
<path d="M215.9 92.3l1.5-.5v1z" fill="#f8fcff"/>
<path d="M215.9 92.3l1.5-.5v1z" fill="none" stroke="#000" stroke-width=".21"/>
<path d="M217.7 91.8l1.5 .5-1.5 .5z" fill="#f8fcff"/>
<path d="M215.9 91.8l-1 .5 1 .5M217.7 91.8l1.5 .5-1.5 .5z" fill="none" stroke="#000" stroke-width=".21"/>
<path d="M215.9 94.9h7.6" fill="none" stroke="#000" stroke-width=".25"/>
<path d="M215.9 94.9l1.5-.5v1z" fill="#f8fcff"/>
<path d="M215.9 94.9l1.5-.5v1z" fill="none" stroke="#000" stroke-width=".21"/>
<path d="M217.7 94.4l1.5 .5-1.5 .5z" fill="#f8fcff"/>
<path d="M215.9 94.4l-1 .5 1 .5M217.7 94.4l1.5 .5-1.5 .5z" fill="none" stroke="#000" stroke-width=".21"/>
<path d="M215.9 97.4h7.6" fill="none" stroke="#000" stroke-width=".25"/>
<path d="M215.9 97.4l1.5-.5v1z" fill="#f8fcff"/>
<path d="M215.9 97.4l1.5-.5v1z" fill="none" stroke="#000" stroke-width=".21"/>
<path d="M217.7 96.9l1.5 .5-1.5 .5z" fill="#f8fcff"/>
<path d="M215.9 96.9l-1 .5 1 .5M217.7 96.9l1.5 .5-1.5 .5z" fill="none" stroke="#000" stroke-width=".21"/>
<path d="M215.9 100h7.6" fill="none" stroke="#000" stroke-width=".25"/>
<path d="M215.9 100l1.5-.5v1z" fill="#f8fcff"/>
<path d="M215.9 100l1.5-.5v1z" fill="none" stroke="#000" stroke-width=".21"/>
<path d="M217.7 99.5l1.5 .5-1.5 .5z" fill="#f8fcff"/>
<path d="M215.9 99.5l-1 .5 1 .5M217.7 99.5l1.5 .5-1.5 .5z" fill="none" stroke="#000" stroke-width=".21"/>
<path d="M215.9 102.5h7.6" fill="none" stroke="#000" stroke-width=".25"/>
<path d="M215.9 102.5l1.5-.5v1z" fill="#f8fcff"/>
<path d="M215.9 102.5l1.5-.5v1z" fill="none" stroke="#000" stroke-width=".21"/>
<path d="M217.7 102l1.5 .5-1.5 .5z" fill="#f8fcff"/>
<path d="M215.9 102l-1 .5 1 .5M217.7 102l1.5 .5-1.5 .5z" fill="none" stroke="#000" stroke-width=".21"/>
<path d="M215.9 105.1h7.6" fill="none" stroke="#000" stroke-width=".25"/>
<path d="M215.9 105.1l1.5-.6v1.1z" fill="#f8fcff"/>
<path d="M215.9 105.1l1.5-.6v1.1z" fill="none" stroke="#000" stroke-width=".21"/>
<path d="M217.7 104.5l1.5 .6-1.5 .5z" fill="#f8fcff"/>
<path d="M215.9 104.5l-1 .6 1 .5M217.7 104.5l1.5 .6-1.5 .5z" fill="none" stroke="#000" stroke-width=".21"/>
<path d="M215.9 107.6h7.6" fill="none" stroke="#000" stroke-width=".25"/>
<path d="M215.9 107.6l1.5-.5v1z" fill="#f8fcff"/>
<path d="M215.9 107.6l1.5-.5v1z" fill="none" stroke="#000" stroke-width=".21"/>
<path d="M217.7 107.1l1.5 .5-1.5 .5z" fill="#f8fcff"/>
<path d="M215.9 107.1l-1 .5 1 .5M217.7 107.1l1.5 .5-1.5 .5z" fill="none" stroke="#000" stroke-width=".21"/>
<path d="M215.9 110.1h7.6" fill="none" stroke="#000" stroke-width=".25"/>
<path d="M215.9 110.1l1.5-.5v1z" fill="#f8fcff"/>
<path d="M215.9 110.1l1.5-.5v1z" fill="none" stroke="#000" stroke-width=".21"/>
<path d="M217.7 109.6l1.5 .5-1.5 .5z" fill="#f8fcff"/>
<path d="M217.7 109.6l1.5 .5-1.5 .5z" fill="none" stroke="#000" stroke-width=".21"/>
<path d="M215.9 112.7h7.6" fill="none" stroke="#000" stroke-width=".25"/>
<path d="M215.9 112.7l1.5-.5v1z" fill="#f8fcff"/>
<path d="M215.9 112.7l1.5-.5v1z" fill="none" stroke="#000" stroke-width=".21"/>
<path d="M217.7 112.2l1.5 .5-1.5 .5z" fill="#f8fcff"/>
<path d="M217.7 112.2l1.5 .5-1.5 .5z" fill="none" stroke="#000" stroke-width=".21"/>
<path d="M215.9 115.2h7.6" fill="none" stroke="#000" stroke-width=".25"/>
<path d="M215.9 115.2l1.5-.5v1z" fill="#f8fcff"/>
<path d="M215.9 115.2l1.5-.5v1z" fill="none" stroke="#000" stroke-width=".21"/>
<path d="M217.7 114.7l1.5 .5-1.5 .5z" fill="#f8fcff"/>
<path d="M217.7 114.7l1.5 .5-1.5 .5z" fill="none" stroke="#000" stroke-width=".21"/>
<path d="M215.9 117.8h7.6" fill="none" stroke="#000" stroke-width=".25"/>
<path d="M215.9 117.8l1.5-.5v1z" fill="#f8fcff"/>
<path d="M215.9 117.8l1.5-.5v1z" fill="none" stroke="#000" stroke-width=".21"/>
<path d="M217.7 117.3l1.5 .5-1.5 .5z" fill="#f8fcff"/>
<path d="M217.7 117.3l1.5 .5-1.5 .5z" fill="none" stroke="#000" stroke-width=".21"/>
<path d="M215.9 120.3h7.6" fill="none" stroke="#000" stroke-width=".25"/>
<path d="M215.9 120.3l1.5-.5v1z" fill="#f8fcff"/>
<path d="M215.9 120.3l1.5-.5v1z" fill="none" stroke="#000" stroke-width=".21"/>
<path d="M217.7 119.8l1.5 .5-1.5 .5z" fill="#f8fcff"/>
<path d="M217.7 119.8l1.5 .5-1.5 .5z" fill="none" stroke="#000" stroke-width=".21"/>
<path d="M215.9 122.9h7.6" fill="none" stroke="#000" stroke-width=".25"/>
<path d="M215.9 122.9l1.5-.6v1.1z" fill="#f8fcff"/>
<path d="M215.9 122.9l1.5-.6v1.1z" fill="none" stroke="#000" stroke-width=".21"/>
<path d="M217.7 122.3l1.5 .6-1.5 .5z" fill="#f8fcff"/>
<path d="M217.7 122.3l1.5 .6-1.5 .5z" fill="none" stroke="#000" stroke-width=".21"/>
<path d="M215.9 125.4h7.6" fill="none" stroke="#000" stroke-width=".25"/>
<path d="M215.9 125.4l1.5-.5v1z" fill="#f8fcff"/>
<path d="M215.9 125.4l1.5-.5v1z" fill="none" stroke="#000" stroke-width=".21"/>
<path d="M217.7 124.9l1.5 .5-1.5 .5z" fill="#f8fcff"/>
<path d="M217.7 124.9l1.5 .5-1.5 .5z" fill="none" stroke="#000" stroke-width=".21"/>
<path d="M215.9 127.9h7.6" fill="none" stroke="#000" stroke-width=".25"/>
<path d="M215.9 127.9l1.5-.5v1z" fill="#f8fcff"/>
<path d="M215.9 127.9l1.5-.5v1z" fill="none" stroke="#000" stroke-width=".21"/>
<path d="M217.7 127.4l1.5 .5-1.5 .5z" fill="#f8fcff"/>
<path d="M217.7 127.4l1.5 .5-1.5 .5z" fill="none" stroke="#000" stroke-width=".21"/>
<path d="M215.9 130.5h7.6" fill="none" stroke="#000" stroke-width=".25"/>
<path d="M215.9 130.5l1.5-.5v1z" fill="#f8fcff"/>
<path d="M215.9 130.5l1.5-.5v1z" fill="none" stroke="#000" stroke-width=".21"/>
<path d="M217.7 130l1.5 .5-1.5 .5z" fill="#f8fcff"/>
<path d="M217.7 130l1.5 .5-1.5 .5z" fill="none" stroke="#000" stroke-width=".21"/>
<path d="M215.9 133h7.6" fill="none" stroke="#000" stroke-width=".25"/>
<path d="M215.9 133l1.5-.5v1z" fill="#f8fcff"/>
<path d="M215.9 133l1.5-.5v1z" fill="none" stroke="#000" stroke-width=".21"/>
<path d="M217.7 132.5l1.5 .5-1.5 .5z" fill="#f8fcff"/>
<path d="M217.7 132.5l1.5 .5-1.5 .5z" fill="none" stroke="#000" stroke-width=".21"/>
<path d="M215.9 135.6h7.6" fill="none" stroke="#000" stroke-width=".25"/>
<path d="M215.9 135.6l1.5-.5v1z" fill="#f8fcff"/>
<path d="M215.9 135.6l1.5-.5v1z" fill="none" stroke="#000" stroke-width=".21"/>
<path d="M217.7 135.1l1.5 .5-1.5 .5z" fill="#f8fcff"/>
<path d="M217.7 135.1l1.5 .5-1.5 .5z" fill="none" stroke="#000" stroke-width=".21"/>
<path d="M215.9 138.1h7.6" fill="none" stroke="#000" stroke-width=".25"/>
<path d="M215.9 138.1l1.5-.5v1z" fill="#f8fcff"/>
<path d="M215.9 138.1l1.5-.5v1z" fill="none" stroke="#000" stroke-width=".21"/>
<path d="M217.7 137.6l1.5 .5-1.5 .5z" fill="#f8fcff"/>
<path d="M217.7 137.6l1.5 .5-1.5 .5z" fill="none" stroke="#000" stroke-width=".21"/>
<path d="M215.9 140.7h7.6" fill="none" stroke="#000" stroke-width=".25"/>
<path d="M215.9 140.7l1.5-.5v1z" fill="#f8fcff"/>
<path d="M215.9 140.7l1.5-.5v1z" fill="none" stroke="#000" stroke-width=".21"/>
<path d="M217.7 140.2l1.5 .5-1.5 .5z" fill="#f8fcff"/>
<path d="M217.7 140.2l1.5 .5-1.5 .5z" fill="none" stroke="#000" stroke-width=".21"/>
<path d="M215.9 143.2h7.6" fill="none" stroke="#000" stroke-width=".25"/>
<path d="M215.9 143.2l1.5-.5v1z" fill="#f8fcff"/>
<path d="M215.9 143.2l1.5-.5v1z" fill="none" stroke="#000" stroke-width=".21"/>
<path d="M217.7 142.7l1.5 .5-1.5 .5z" fill="#f8fcff"/>
<path d="M217.7 142.7l1.5 .5-1.5 .5z" fill="none" stroke="#000" stroke-width=".21"/>
<path d="M215.9 145.8h7.6" fill="none" stroke="#000" stroke-width=".25"/>
<path d="M215.9 145.8l1.5-.6v1.1z" fill="#f8fcff"/>
<path d="M215.9 145.8l1.5-.6v1.1z" fill="none" stroke="#000" stroke-width=".21"/>
<path d="M217.7 145.2l1.5 .6-1.5 .5z" fill="#f8fcff"/>
<path d="M217.7 145.2l1.5 .6-1.5 .5z" fill="none" stroke="#000" stroke-width=".21"/>
<path d="M215.9 148.3h7.6" fill="none" stroke="#000" stroke-width=".25"/>
<path d="M215.9 148.3l1.5-.5v1z" fill="#f8fcff"/>
<path d="M215.9 148.3l1.5-.5v1z" fill="none" stroke="#000" stroke-width=".21"/>
<path d="M217.7 147.8l1.5 .5-1.5 .5z" fill="#f8fcff"/>
<path d="M217.7 147.8l1.5 .5-1.5 .5z" fill="none" stroke="#000" stroke-width=".21"/>
<path d="M215.9 150.8h7.6" fill="none" stroke="#000" stroke-width=".25"/>
<path d="M215.9 150.8l1.5-.5v1.1z" fill="#f8fcff"/>
<path d="M215.9 150.8l1.5-.5v1.1z" fill="none" stroke="#000" stroke-width=".21"/>
<path d="M217.7 150.3l1.5 .5-1.5 .6z" fill="#f8fcff"/>
<path d="M217.7 150.3l1.5 .5-1.5 .6z" fill="none" stroke="#000" stroke-width=".21"/>
<path d="M215.9 153.4h7.6" fill="none" stroke="#000" stroke-width=".25"/>
<path d="M215.9 153.4l1.5-.5v1z" fill="#f8fcff"/>
<path d="M215.9 153.4l1.5-.5v1z" fill="none" stroke="#000" stroke-width=".21"/>
<path d="M217.7 152.9l1.5 .5-1.5 .5z" fill="#f8fcff"/>
<path d="M217.7 152.9l1.5 .5-1.5 .5z" fill="none" stroke="#000" stroke-width=".21"/>
<path d="M215.9 155.9h7.6" fill="none" stroke="#000" stroke-width=".25"/>
<path d="M215.9 155.9l1.5-.5v1z" fill="#f8fcff"/>
<path d="M215.9 155.9l1.5-.5v1z" fill="none" stroke="#000" stroke-width=".21"/>
<path d="M217.7 155.4l1.5 .5-1.5 .5z" fill="#f8fcff"/>
<path d="M217.7 155.4l1.5 .5-1.5 .5z" fill="none" stroke="#000" stroke-width=".21"/>
<path d="M215.9 158.5h7.6" fill="none" stroke="#000" stroke-width=".25"/>
<path d="M215.9 158.5l1.5-.5v1z" fill="#f8fcff"/>
<path d="M215.9 158.5l1.5-.5v1z" fill="none" stroke="#000" stroke-width=".21"/>
<path d="M217.7 158l1.5 .5-1.5 .5z" fill="#f8fcff"/>
<path d="M217.7 158l1.5 .5-1.5 .5z" fill="none" stroke="#000" stroke-width=".21"/>
<path d="M215.9 161h7.6" fill="none" stroke="#000" stroke-width=".25"/>
<path d="M215.9 161l1.5-.5v1z" fill="#f8fcff"/>
<path d="M215.9 161l1.5-.5v1z" fill="none" stroke="#000" stroke-width=".21"/>
<path d="M217.7 160.5l1.5 .5-1.5 .5z" fill="#f8fcff"/>
<path d="M217.7 160.5l1.5 .5-1.5 .5z" fill="none" stroke="#000" stroke-width=".21"/>
<path d="M222.5 35.3l2 2.1M224.5 35.3l-2 2.1M222.5 93.9l2 2M222.5 98.9l2 2.1M224.5 93.9l-2 2M224.5 98.9l-2 2.1M222.5 160l2 2M224.5 160l-2 2" fill="none" stroke="#f00" stroke-width=".21"/>
<path d="M128.1 31.3h2.6M129.4 31.3v2.5M243.9 66.9h2.5M246.4 65.6v2.6M139.6 133h5.1M140.3 133.8h3.6M141.1 134.6h2M141.9 135.3h.5M142.1 130.5v2.5M243.9 133h2.5M246.4 131.8v2.5" fill="none" stroke="#800000" stroke-width=".25"/>
<g fill="none" stroke="#000" stroke-width=".25">
<path d="M129.4 36.4v2M129.4 44.5v2M126.9 87.2h2.5M126.9 92.3h2.5M126.9 117.8h2.5M142.1 127.9v2.6"/>
<circle cx="130.7" cy="92.3" r="1.27"/>
<circle cx="130.7" cy="87.2" r="1.27"/>
<circle cx="130.7" cy="117.8" r="1.27"/>
<circle cx="142.1" cy="126.7" r="1.27"/>
</g>
<path d="M128.4 38.4h2.1v6h-2.1z" fill="none" stroke="#00f" stroke-width=".25"/>
<g fill="none" stroke="#000080" stroke-width=".25">
<path d="M101.4 38.9h17.8M129.4 33.8v2.6M223.5 38.9h17.8M101.4 41.4h17.8M101.4 44h17.8M101.4 46.5h17.8M101.4 54.2h17.8M101.4 51.6h17.8M101.4 56.7h17.8M129.4 46.5v2.6h-28M223.5 41.4h17.8M223.5 46.5h17.8"/>
<path d="M223.5 54.2h17.8M223.5 51.6h17.8M223.5 44h17.8M223.5 56.7h17.8M223.5 59.3h17.8M223.5 49.1h17.8M101.4 64.3h17.8M101.4 66.9h17.8M101.4 61.8h17.8M101.4 69.4h17.8M101.4 72h17.8M223.5 64.3h17.8"/>
<path d="M223.5 66.9h20.4M223.5 61.8h17.8M223.5 69.4h17.8M223.5 72h17.8M223.5 74.5h17.8M223.5 77.1h17.8M223.5 79.6h17.8M101.4 100h17.8M101.4 82.1h17.8M101.4 84.7h17.8M101.4 87.2h25.5M101.4 92.3h25.5"/>
<path d="M223.5 82.1h17.8M223.5 84.7h17.8M223.5 87.2h17.8M223.5 89.8h17.8M223.5 92.3h17.8M223.5 97.4h17.8M101.4 102.5h17.8M101.4 115.2h17.8M101.4 110.1h17.8M101.4 112.7h17.8M101.4 117.8h25.5M223.5 102.5h17.8"/>
<path d="M223.5 105.1h17.8M223.5 107.6h17.8M223.5 115.2h17.8M223.5 117.8h17.8M223.5 110.1h17.8M223.5 112.7h17.8M101.4 138.1h17.8M101.4 125.4h17.8M101.4 133h17.8M101.4 127.9h17.8M223.5 120.3h17.8M223.5 122.9h17.8"/>
<path d="M223.5 130.5h17.8M223.5 135.6h17.8M223.5 138.1h17.8M223.5 125.4h17.8M223.5 133h20.4M223.5 127.9h17.8M101.4 145.7h17.8M101.4 150.8h17.8M101.4 153.4h17.8M101.4 155.9h17.8M101.4 140.7h17.8M101.4 143.2h17.8"/>
<path d="M101.4 158.5h17.8M223.5 145.8h17.8M223.5 148.3h17.8M223.5 150.8h17.8M223.5 153.4h17.8M223.5 155.9h17.8M223.5 140.7h17.8M223.5 143.2h17.8M223.5 158.5h17.8"/>
</g>
<use href="#words"/>
</svg>
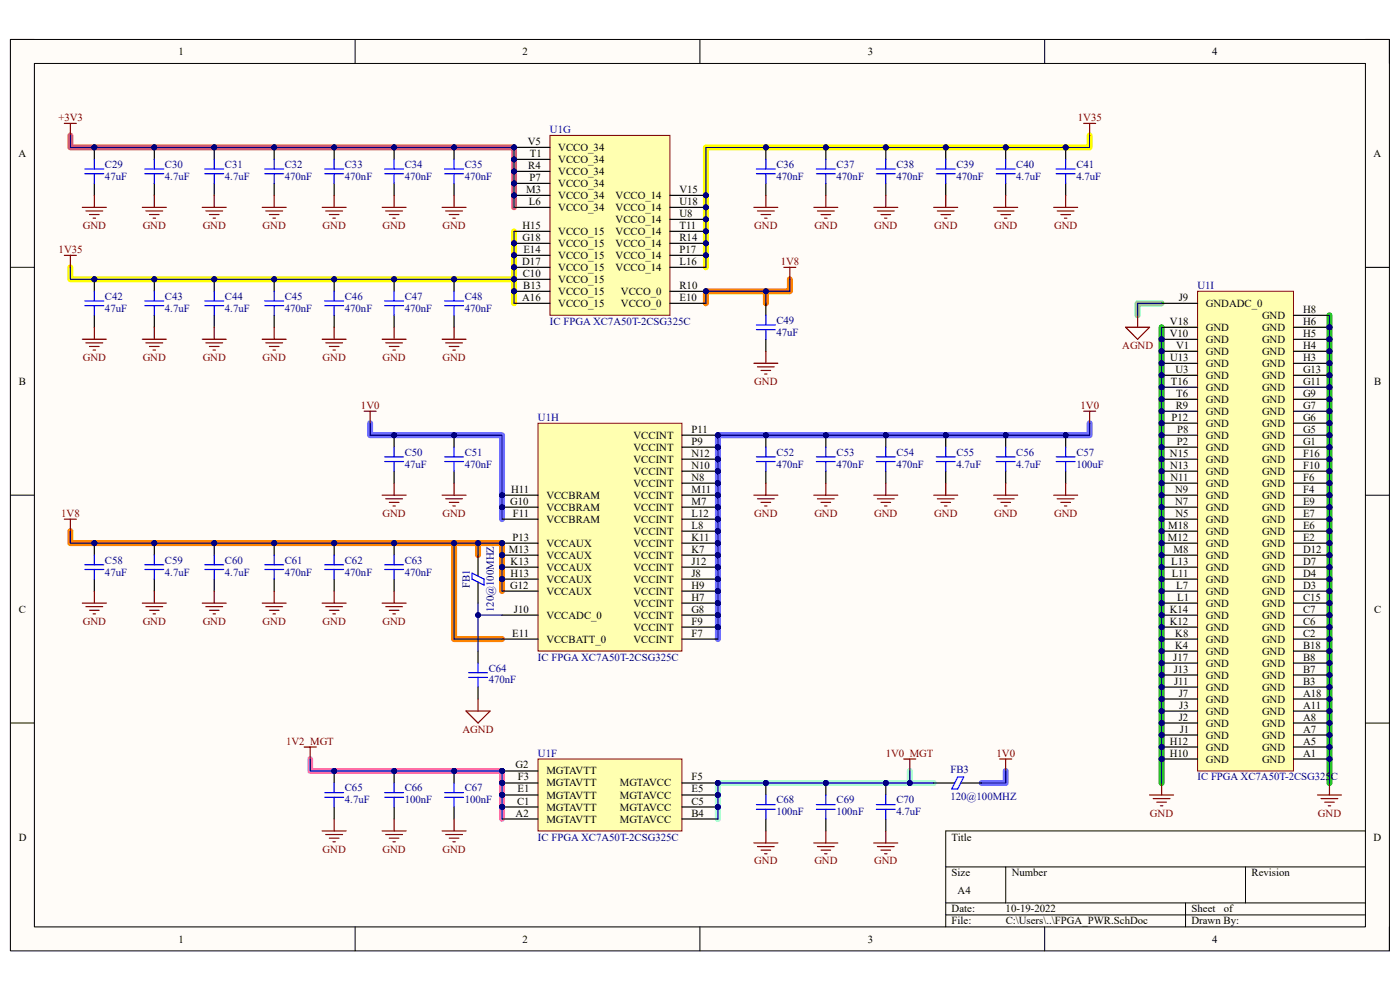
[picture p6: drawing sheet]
<svg xmlns="http://www.w3.org/2000/svg" width="297mm" height="210mm" viewBox="0 0 297 210" stroke-linecap="round" stroke-linejoin="round" font-family="sans-serif">
<defs><g id="words">
<g font-size="2.3">
<text x="37.9" y="11.7">1</text>
<text x="110.9" y="11.7">2</text>
<text x="184.1" y="11.7">3</text>
<text x="257.1" y="11.7">4</text>
<text x="3.9" y="33.3">A</text>
<text x="112" y="30.7">V5</text>
<text x="112.1" y="35.9">R4</text>
<text x="112.4" y="33.3">T1</text>
<text x="118.4" y="34.6">VCCO_34</text>
<text x="118.4" y="32">VCCO_34</text>
<text x="291.4" y="33.3">A</text>
<text x="111.6" y="40.9">M3</text>
<text x="112.3" y="38.4">P7</text>
<text x="118.4" y="39.7">VCCO_34</text>
<text x="118.4" y="37.1">VCCO_34</text>
<text x="144.1" y="40.9">V15</text>
<text x="112.2" y="43.5">L6</text>
<text x="118.4" y="44.7">VCCO_34</text>
<text x="118.4" y="42.2">VCCO_34</text>
<text x="130.6" y="47.3">VCCO_14</text>
<text x="130.6" y="44.7">VCCO_14</text>
<text x="130.6" y="42.2">VCCO_14</text>
<text x="144.1" y="46">U8</text>
<text x="144.1" y="43.5">U18</text>
<text x="110.8" y="51.1">G18</text>
<text x="110.8" y="48.6">H15</text>
<text x="111" y="53.6">E14</text>
<text x="118.4" y="52.4">VCCO_15</text>
<text x="118.4" y="49.8">VCCO_15</text>
<text x="130.6" y="52.4">VCCO_14</text>
<text x="130.6" y="49.8">VCCO_14</text>
<text x="144.1" y="53.6">P17</text>
<text x="144.1" y="51.1">R14</text>
<text x="144.1" y="48.6">T11</text>
<text x="110.8" y="56.2">D17</text>
<text x="110.9" y="58.7">C10</text>
<text x="118.4" y="60">VCCO_15</text>
<text x="118.4" y="57.4">VCCO_15</text>
<text x="118.4" y="54.9">VCCO_15</text>
<text x="130.6" y="57.4">VCCO_14</text>
<text x="130.6" y="54.9">VCCO_14</text>
<text x="144.1" y="56.2">L16</text>
<text x="110.8" y="63.8">A16</text>
<text x="111" y="61.3">B13</text>
<text x="118.4" y="65.1">VCCO_15</text>
<text x="118.4" y="62.6">VCCO_15</text>
<text x="131.7" y="65.1">VCCO_0</text>
<text x="131.7" y="62.6">VCCO_0</text>
<text x="144.1" y="63.8">E10</text>
<text x="144.1" y="61.3">R10</text>
<text x="250.1" y="63.8">J9</text>
<text x="255.8" y="65.1">GNDADC_0</text>
<text x="248.2" y="71.5">V10</text>
<text x="248.2" y="68.9">V18</text>
<text x="255.8" y="70.2">GND</text>
<text x="267.8" y="70.2">GND</text>
<text x="267.8" y="67.6">GND</text>
<text x="276.4" y="71.5">H5</text>
<text x="276.4" y="68.9">H6</text>
<text x="276.4" y="66.4">H8</text>
<text x="248.2" y="76.5">U13</text>
<text x="249.5" y="74">V1</text>
<text x="255.8" y="77.8">GND</text>
<text x="255.8" y="75.3">GND</text>
<text x="255.8" y="72.7">GND</text>
<text x="267.8" y="77.8">GND</text>
<text x="267.8" y="75.3">GND</text>
<text x="267.8" y="72.7">GND</text>
<text x="276.4" y="76.5">H3</text>
<text x="276.4" y="74">H4</text>
<text x="4" y="81.6">B</text>
<text x="248.4" y="81.6">T16</text>
<text x="249.4" y="79.1">U3</text>
<text x="255.8" y="82.9">GND</text>
<text x="255.8" y="80.3">GND</text>
<text x="267.8" y="82.9">GND</text>
<text x="267.8" y="80.3">GND</text>
<text x="276.4" y="81.6">G11</text>
<text x="276.4" y="79.1">G13</text>
<text x="291.5" y="81.6">B</text>
<text x="248.5" y="89.3">P12</text>
<text x="249.4" y="86.7">R9</text>
<text x="249.6" y="84.2">T6</text>
<text x="255.8" y="88">GND</text>
<text x="255.8" y="85.4">GND</text>
<text x="267.8" y="88">GND</text>
<text x="267.8" y="85.4">GND</text>
<text x="276.4" y="89.3">G6</text>
<text x="276.4" y="86.7">G7</text>
<text x="276.4" y="84.2">G9</text>
<text x="134.4" y="95.6">VCCINT</text>
<text x="134.4" y="93.1">VCCINT</text>
<text x="146.7" y="94.4">P9</text>
<text x="146.7" y="91.8">P11</text>
<text x="249.7" y="94.4">P2</text>
<text x="249.7" y="91.8">P8</text>
<text x="255.8" y="95.6">GND</text>
<text x="255.8" y="93.1">GND</text>
<text x="255.8" y="90.6">GND</text>
<text x="267.8" y="95.6">GND</text>
<text x="267.8" y="93.1">GND</text>
<text x="267.8" y="90.6">GND</text>
<text x="276.4" y="94.4">G1</text>
<text x="276.4" y="91.8">G5</text>
<text x="134.4" y="100.7">VCCINT</text>
<text x="134.4" y="98.2">VCCINT</text>
<text x="146.7" y="102">N8</text>
<text x="146.7" y="99.4">N10</text>
<text x="146.7" y="96.9">N12</text>
<text x="248.2" y="96.9">N15</text>
<text x="248.2" y="99.4">N13</text>
<text x="248.3" y="102">N11</text>
<text x="255.8" y="100.7">GND</text>
<text x="255.8" y="98.2">GND</text>
<text x="267.8" y="100.7">GND</text>
<text x="267.8" y="98.2">GND</text>
<text x="276.4" y="102">F6</text>
<text x="276.4" y="99.4">F10</text>
<text x="276.4" y="96.9">F16</text>
<text x="108.2" y="107.1">G10</text>
<text x="108.4" y="104.5">H11</text>
<text x="115.9" y="105.8">VCCBRAM</text>
<text x="134.4" y="105.8">VCCINT</text>
<text x="134.4" y="103.3">VCCINT</text>
<text x="146.7" y="107.1">M7</text>
<text x="146.7" y="104.5">M11</text>
<text x="249.3" y="107.1">N7</text>
<text x="249.3" y="104.5">N9</text>
<text x="255.8" y="105.8">GND</text>
<text x="255.8" y="103.3">GND</text>
<text x="267.8" y="105.8">GND</text>
<text x="267.8" y="103.3">GND</text>
<text x="276.4" y="107.1">E9</text>
<text x="276.4" y="104.5">F4</text>
<text x="108.8" y="109.6">F11</text>
<text x="115.9" y="110.9">VCCBRAM</text>
<text x="115.9" y="108.3">VCCBRAM</text>
<text x="134.4" y="113.4">VCCINT</text>
<text x="134.4" y="110.9">VCCINT</text>
<text x="134.4" y="108.3">VCCINT</text>
<text x="146.7" y="112.1">L8</text>
<text x="146.7" y="109.6">L12</text>
<text x="247.8" y="112.1">M18</text>
<text x="249.4" y="109.6">N5</text>
<text x="255.8" y="113.4">GND</text>
<text x="255.8" y="110.9">GND</text>
<text x="255.8" y="108.3">GND</text>
<text x="267.8" y="113.4">GND</text>
<text x="267.8" y="110.9">GND</text>
<text x="267.8" y="108.3">GND</text>
<text x="276.4" y="112.1">E6</text>
<text x="276.4" y="109.6">E7</text>
<text x="107.9" y="117.3">M13</text>
<text x="108.3" y="119.8">K13</text>
<text x="108.7" y="114.7">P13</text>
<text x="115.9" y="118.5">VCCAUX</text>
<text x="115.9" y="116">VCCAUX</text>
<text x="134.4" y="118.5">VCCINT</text>
<text x="134.4" y="116">VCCINT</text>
<text x="146.7" y="119.8">J12</text>
<text x="146.7" y="117.3">K7</text>
<text x="146.7" y="114.7">K11</text>
<text x="247.8" y="114.7">M12</text>
<text x="248.5" y="119.8">L13</text>
<text x="249" y="117.3">M8</text>
<text x="255.8" y="118.5">GND</text>
<text x="255.8" y="116">GND</text>
<text x="267.8" y="118.5">GND</text>
<text x="267.8" y="116">GND</text>
<text x="276.4" y="119.8">D7</text>
<text x="276.4" y="117.3">D12</text>
<text x="276.4" y="114.7">E2</text>
<text x="108.2" y="124.9">G12</text>
<text x="108.3" y="122.3">H13</text>
<text x="115.9" y="123.6">VCCAUX</text>
<text x="115.9" y="121.1">VCCAUX</text>
<text x="134.4" y="123.6">VCCINT</text>
<text x="134.4" y="121.1">VCCINT</text>
<text x="146.7" y="124.9">H9</text>
<text x="146.7" y="122.3">J8</text>
<text x="248.6" y="122.3">L11</text>
<text x="249.6" y="124.9">L7</text>
<text x="255.8" y="123.6">GND</text>
<text x="255.8" y="121.1">GND</text>
<text x="267.8" y="123.6">GND</text>
<text x="267.8" y="121.1">GND</text>
<text x="276.4" y="124.9">D3</text>
<text x="276.4" y="122.3">D4</text>
<text x="4" y="130">C</text>
<text x="109" y="130">J10</text>
<text x="115.9" y="126.2">VCCAUX</text>
<text x="115.9" y="131.2">VCCADC_0</text>
<text x="134.4" y="131.2">VCCINT</text>
<text x="134.4" y="128.7">VCCINT</text>
<text x="134.4" y="126.2">VCCINT</text>
<text x="146.7" y="130">G8</text>
<text x="146.7" y="127.4">H7</text>
<text x="248.2" y="130">K14</text>
<text x="249.8" y="127.4">L1</text>
<text x="255.8" y="131.2">GND</text>
<text x="255.8" y="128.7">GND</text>
<text x="255.8" y="126.2">GND</text>
<text x="267.8" y="131.2">GND</text>
<text x="267.8" y="128.7">GND</text>
<text x="267.8" y="126.2">GND</text>
<text x="276.4" y="130">C7</text>
<text x="276.4" y="127.4">C15</text>
<text x="291.5" y="130">C</text>
<text x="108.7" y="135">E11</text>
<text x="115.9" y="136.3">VCCBATT_0</text>
<text x="134.4" y="136.3">VCCINT</text>
<text x="134.4" y="133.8">VCCINT</text>
<text x="146.7" y="135">F7</text>
<text x="146.7" y="132.5">F9</text>
<text x="248.2" y="132.5">K12</text>
<text x="249.3" y="137.6">K4</text>
<text x="249.3" y="135">K8</text>
<text x="255.8" y="136.3">GND</text>
<text x="255.8" y="133.8">GND</text>
<text x="267.8" y="136.3">GND</text>
<text x="267.8" y="133.8">GND</text>
<text x="276.4" y="137.6">B18</text>
<text x="276.4" y="135">C2</text>
<text x="276.4" y="132.5">C6</text>
<text x="248.9" y="140.1">J17</text>
<text x="249" y="142.7">J13</text>
<text x="255.8" y="144">GND</text>
<text x="255.8" y="141.4">GND</text>
<text x="255.8" y="138.9">GND</text>
<text x="267.8" y="144">GND</text>
<text x="267.8" y="141.4">GND</text>
<text x="267.8" y="138.9">GND</text>
<text x="276.4" y="142.7">B7</text>
<text x="276.4" y="140.1">B8</text>
<text x="249.1" y="145.2">J11</text>
<text x="250.1" y="147.8">J7</text>
<text x="255.8" y="149.1">GND</text>
<text x="255.8" y="146.5">GND</text>
<text x="267.8" y="149.1">GND</text>
<text x="267.8" y="146.5">GND</text>
<text x="276.4" y="147.8">A18</text>
<text x="276.4" y="145.2">B3</text>
<text x="250.1" y="152.9">J2</text>
<text x="250.2" y="150.3">J3</text>
<text x="250.3" y="155.4">J1</text>
<text x="255.8" y="154.1">GND</text>
<text x="255.8" y="151.6">GND</text>
<text x="267.8" y="154.1">GND</text>
<text x="267.8" y="151.6">GND</text>
<text x="276.4" y="155.4">A7</text>
<text x="276.4" y="152.9">A8</text>
<text x="276.4" y="150.3">A11</text>
<text x="248.2" y="160.5">H10</text>
<text x="248.2" y="157.9">H12</text>
<text x="255.8" y="161.8">GND</text>
<text x="255.8" y="159.2">GND</text>
<text x="255.8" y="156.7">GND</text>
<text x="267.8" y="161.8">GND</text>
<text x="267.8" y="159.2">GND</text>
<text x="267.8" y="156.7">GND</text>
<text x="276.4" y="160.5">A1</text>
<text x="276.4" y="157.9">A5</text>
<text x="109.4" y="163">G2</text>
<text x="109.9" y="165.6">F3</text>
<text x="115.9" y="166.8">MGTAVTT</text>
<text x="115.9" y="164.3">MGTAVTT</text>
<text x="131.5" y="166.8">MGTAVCC</text>
<text x="146.7" y="165.6">F5</text>
<text x="109.4" y="173.2">A2</text>
<text x="109.7" y="170.7">C1</text>
<text x="109.8" y="168.1">E1</text>
<text x="115.9" y="172">MGTAVTT</text>
<text x="115.9" y="169.4">MGTAVTT</text>
<text x="131.5" y="172">MGTAVCC</text>
<text x="131.5" y="169.4">MGTAVCC</text>
<text x="146.7" y="173.2">B4</text>
<text x="146.7" y="170.7">C5</text>
<text x="146.7" y="168.1">E5</text>
<text x="4" y="178.3">D</text>
<text x="115.9" y="174.5">MGTAVTT</text>
<text x="131.5" y="174.5">MGTAVCC</text>
<text x="201.9" y="178.3">Title</text>
<text x="291.4" y="178.3">D</text>
<text x="201.9" y="185.9">Size</text>
<text x="214.6" y="185.9">Number</text>
<text x="265.5" y="185.9">Revision</text>
<text x="203.2" y="189.7">A4</text>
<text x="201.9" y="193.5">Date:</text>
<text x="201.9" y="196.1">File:</text>
<text x="213.3" y="193.5">10-19-2022</text>
<text x="213.4" y="196.1">C:\Users\..\FPGA_PWR.SchDoc</text>
<text x="252.8" y="193.5">Sheet</text>
<text x="252.8" y="196.1">Drawn By:</text>
<text x="259.6" y="193.5">of</text>
<text x="37.9" y="199.9">1</text>
<text x="110.9" y="199.9">2</text>
<text x="184.1" y="199.9">3</text>
<text x="257.1" y="199.9">4</text>
</g>
<g font-size="2.3" fill="#800000">
<text x="12.4" y="25.7">+3V3</text>
<text x="228.7" y="25.7">1V35</text>
<text x="12.4" y="53.6">1V35</text>
<text x="17.6" y="48.6">GND</text>
<text x="30.3" y="48.6">GND</text>
<text x="43" y="48.6">GND</text>
<text x="55.7" y="48.6">GND</text>
<text x="68.5" y="48.6">GND</text>
<text x="81.2" y="48.6">GND</text>
<text x="93.9" y="48.6">GND</text>
<text x="160" y="48.6">GND</text>
<text x="172.8" y="48.6">GND</text>
<text x="185.5" y="48.6">GND</text>
<text x="198.2" y="48.6">GND</text>
<text x="210.9" y="48.6">GND</text>
<text x="223.6" y="48.6">GND</text>
<text x="165.7" y="56.2">1V8</text>
<text x="17.6" y="76.5">GND</text>
<text x="30.3" y="76.5">GND</text>
<text x="43" y="76.5">GND</text>
<text x="55.7" y="76.5">GND</text>
<text x="68.5" y="76.5">GND</text>
<text x="81.2" y="76.5">GND</text>
<text x="93.9" y="76.5">GND</text>
<text x="238.1" y="74">AGND</text>
<text x="160" y="81.6">GND</text>
<text x="76.6" y="86.7">1V0</text>
<text x="229.2" y="86.7">1V0</text>
<text x="13" y="109.6">1V8</text>
<text x="81.2" y="109.6">GND</text>
<text x="93.9" y="109.6">GND</text>
<text x="160" y="109.6">GND</text>
<text x="172.8" y="109.6">GND</text>
<text x="185.5" y="109.6">GND</text>
<text x="198.2" y="109.6">GND</text>
<text x="210.9" y="109.6">GND</text>
<text x="223.6" y="109.6">GND</text>
<text x="17.6" y="132.5">GND</text>
<text x="30.3" y="132.5">GND</text>
<text x="43" y="132.5">GND</text>
<text x="55.7" y="132.5">GND</text>
<text x="68.5" y="132.5">GND</text>
<text x="81.2" y="132.5">GND</text>
<text x="98.1" y="155.4">AGND</text>
<text x="60.7" y="157.9">1V2_MGT</text>
<text x="187.9" y="160.5">1V0_MGT</text>
<text x="211.4" y="160.5">1V0</text>
<text x="244" y="173.2">GND</text>
<text x="279.6" y="173.2">GND</text>
<text x="68.5" y="180.8">GND</text>
<text x="81.2" y="180.8">GND</text>
<text x="93.9" y="180.8">GND</text>
<text x="160" y="183.4">GND</text>
<text x="172.8" y="183.4">GND</text>
<text x="185.5" y="183.4">GND</text>
</g>
<g font-size="2.3" fill="#000080">
<text x="116.7" y="28.2">U1G</text>
<text x="22.3" y="35.6">C29</text>
<text x="35" y="35.6">C30</text>
<text x="47.7" y="35.6">C31</text>
<text x="60.4" y="35.6">C32</text>
<text x="73.2" y="35.6">C33</text>
<text x="85.9" y="35.6">C34</text>
<text x="98.6" y="35.6">C35</text>
<text x="164.7" y="35.6">C36</text>
<text x="177.5" y="35.6">C37</text>
<text x="190.2" y="35.6">C38</text>
<text x="202.9" y="35.6">C39</text>
<text x="215.6" y="35.6">C40</text>
<text x="228.3" y="35.6">C41</text>
<text x="22.3" y="38.1">47uF</text>
<text x="35" y="38.1">4.7uF</text>
<text x="47.7" y="38.1">4.7uF</text>
<text x="60.4" y="38.1">470nF</text>
<text x="73.2" y="38.1">470nF</text>
<text x="85.9" y="38.1">470nF</text>
<text x="98.6" y="38.1">470nF</text>
<text x="164.7" y="38.1">470nF</text>
<text x="177.5" y="38.1">470nF</text>
<text x="190.2" y="38.1">470nF</text>
<text x="202.9" y="38.1">470nF</text>
<text x="215.6" y="38.1">4.7uF</text>
<text x="228.3" y="38.1">4.7uF</text>
<text x="22.3" y="63.6">C42</text>
<text x="35" y="63.6">C43</text>
<text x="47.7" y="63.6">C44</text>
<text x="60.4" y="63.6">C45</text>
<text x="73.2" y="63.6">C46</text>
<text x="85.9" y="63.6">C47</text>
<text x="98.6" y="63.6">C48</text>
<text x="254" y="61.3">U1I</text>
<text x="22.3" y="66.1">47uF</text>
<text x="35" y="66.1">4.7uF</text>
<text x="47.7" y="66.1">4.7uF</text>
<text x="60.4" y="66.1">470nF</text>
<text x="73.2" y="66.1">470nF</text>
<text x="85.9" y="66.1">470nF</text>
<text x="98.6" y="66.1">470nF</text>
<text x="116.7" y="68.9">IC FPGA XC7A50T-2CSG325C</text>
<text x="164.7" y="68.7">C49</text>
<text x="164.7" y="71.2">47uF</text>
<text x="114.1" y="89.3">U1H</text>
<text x="85.9" y="96.6">C50</text>
<text x="85.9" y="99.2">47uF</text>
<text x="98.6" y="96.6">C51</text>
<text x="98.6" y="99.2">470nF</text>
<text x="164.7" y="96.6">C52</text>
<text x="164.7" y="99.2">470nF</text>
<text x="177.5" y="96.6">C53</text>
<text x="177.5" y="99.2">470nF</text>
<text x="190.2" y="96.6">C54</text>
<text x="190.2" y="99.2">470nF</text>
<text x="202.9" y="96.6">C55</text>
<text x="202.9" y="99.2">4.7uF</text>
<text x="215.6" y="96.6">C56</text>
<text x="215.6" y="99.2">4.7uF</text>
<text x="228.3" y="96.6">C57</text>
<text x="228.3" y="99.2">100uF</text>
<text x="22.3" y="119.5">C58</text>
<text x="35" y="119.5">C59</text>
<text x="47.7" y="119.5">C60</text>
<text x="60.4" y="119.5">C61</text>
<text x="73.2" y="119.5">C62</text>
<text x="85.9" y="119.5">C63</text>
<text x="22.3" y="122.1">47uF</text>
<text x="35" y="122.1">4.7uF</text>
<text x="47.7" y="122.1">4.7uF</text>
<text x="60.4" y="122.1">470nF</text>
<text x="73.2" y="122.1">470nF</text>
<text x="85.9" y="122.1">470nF</text>
<text x="99.7" y="124.7" transform="rotate(-90 99.7 124.7)">FB1</text>
<text x="104.7" y="129.9" transform="rotate(-90 104.7 129.9)">120@100MHZ</text>
<text x="103.7" y="142.5">C64</text>
<text x="114.1" y="140.1">IC FPGA XC7A50T-2CSG325C</text>
<text x="103.7" y="145">470nF</text>
<text x="114.1" y="160.5">U1F</text>
<text x="73.2" y="167.9">C65</text>
<text x="85.9" y="167.9">C66</text>
<text x="98.6" y="167.9">C67</text>
<text x="201.6" y="164">FB3</text>
<text x="254" y="165.6">IC FPGA XC7A50T-2CSG325C</text>
<text x="73.2" y="170.4">4.7uF</text>
<text x="85.9" y="170.4">100nF</text>
<text x="98.6" y="170.4">100nF</text>
<text x="164.7" y="170.4">C68</text>
<text x="164.7" y="173">100nF</text>
<text x="177.5" y="170.4">C69</text>
<text x="177.5" y="173">100nF</text>
<text x="190.2" y="170.4">C70</text>
<text x="190.2" y="173">4.7uF</text>
<text x="201.6" y="169.7">120@100MHZ</text>
<text x="114.1" y="178.3">IC FPGA XC7A50T-2CSG325C</text>
</g>
</g></defs>
<path d="M2.2 8.4h292.6v193.3h-292.6z" fill-rule="evenodd" fill="#fffcf8"/>
<path d="M2.2 8.4h292.6v193.3h-292.6z" fill="none" stroke="#000" stroke-width=".21"/>
<path d="M7.3 13.5h282.4v183.1h-282.4z" fill-rule="evenodd" fill="#fffcf8"/>
<g fill="none" stroke="#000" stroke-width=".21">
<path d="M2.2 8.4h5.1M7.3 13.5h282.4v183.1h-282.4zM75.3 8.4v5.1M148.5 8.4v5.1M221.6 8.4v5.1M289.7 8.4h5.1v5.1M2.2 56.7h5.1M289.7 56.7h5.1M2.2 105h5.1M289.7 105.1h5.1M2.2 153.4h5.1M289.7 153.4h5.1"/>
<path d="M289.7 176.3h-89.1v20.3M75.3 196.6v5.1M148.5 196.6v5.1M200.6 183.9h89.1M200.6 191.5h89.1M200.6 194.1h89.1M213.4 183.9v7.6M221.6 196.6v5.1M251.5 191.5v5.1M264.2 183.9v7.6M294.8 196.6v5.1"/>
</g>
<path d="M14.9 28.7v2.6h94.2v12.7" fill="none" stroke="#ff6e6e" stroke-width="1.3"/>
<path d="M231.2 28.7v2.6h-81.4v25.4M14.9 56.7v2.6h94.2v5M109.1 49.1v10.2" fill="none" stroke="#ff0" stroke-width="1.3"/>
<path d="M78.5 89.8v2.5h28v17.8M231.2 89.8v2.5h-78.9v43.3M213.4 163.6v2.5h-5.1" fill="none" stroke="#6e6eff" stroke-width="1.3"/>
<path d="M65.8 161v2.6h40.7v10.1" fill="none" stroke="#ff6eff" stroke-width="1.3"/>
<path d="M193 166.1h5.1M193 163.6v2.5h-40.7v7.6" fill="none" stroke="#6effff" stroke-width="1.3"/>
<path d="M246.4 69.4v96.7M282 66.9v99.2" fill="none" stroke="#00be00" stroke-width="1.3"/>
<path d="M246.4 64.3h-5.1v2.6" fill="none" stroke="#6eff6e" stroke-width="1.3"/>
<path d="M167.6 59.3v2.5h-17.8v2.5M162.5 61.8v2.5M14.9 112.7v2.5h91.6v10.2M96.3 115.2v20.4h10.2M101.4 115.2v2.6" fill="none" stroke="#fd8300" stroke-width="1.3"/>
<circle cx="152.3" cy="171.2" r=".51" fill="#000080"/>
<circle cx="152.3" cy="171.2" r=".51" fill="none" stroke="#000080" stroke-width=".21"/>
<circle cx="152.3" cy="168.6" r=".51" fill="#000080"/>
<circle cx="152.3" cy="168.6" r=".51" fill="none" stroke="#000080" stroke-width=".21"/>
<circle cx="152.3" cy="166.1" r=".51" fill="#000080"/>
<circle cx="152.3" cy="166.1" r=".51" fill="none" stroke="#000080" stroke-width=".21"/>
<circle cx="106.5" cy="171.2" r=".51" fill="#000080"/>
<circle cx="106.5" cy="171.2" r=".51" fill="none" stroke="#000080" stroke-width=".21"/>
<circle cx="106.5" cy="168.6" r=".51" fill="#000080"/>
<circle cx="106.5" cy="168.6" r=".51" fill="none" stroke="#000080" stroke-width=".21"/>
<circle cx="106.5" cy="166.1" r=".51" fill="#000080"/>
<circle cx="106.5" cy="166.1" r=".51" fill="none" stroke="#000080" stroke-width=".21"/>
<circle cx="106.5" cy="163.6" r=".51" fill="#000080"/>
<circle cx="106.5" cy="163.6" r=".51" fill="none" stroke="#000080" stroke-width=".21"/>
<path d="M114.1 161h30.6v15.3h-30.6z" fill-rule="evenodd" fill="#ffffb0"/>
<path d="M114.1 161h30.6v15.3h-30.6z" fill="none" stroke="#800000" stroke-width=".21"/>
<path d="M144.7 171.2h7.6M144.7 173.7h7.6" fill="none" stroke="#000" stroke-width=".25"/>
<circle cx="152.3" cy="171.2" r=".51" fill="#000080"/>
<circle cx="152.3" cy="171.2" r=".51" fill="none" stroke="#000080" stroke-width=".21"/>
<path d="M144.7 168.6h7.6" fill="none" stroke="#000" stroke-width=".25"/>
<circle cx="152.3" cy="168.6" r=".51" fill="#000080"/>
<circle cx="152.3" cy="168.6" r=".51" fill="none" stroke="#000080" stroke-width=".21"/>
<path d="M144.7 166.1h7.6" fill="none" stroke="#000" stroke-width=".25"/>
<circle cx="152.3" cy="166.1" r=".51" fill="#000080"/>
<circle cx="152.3" cy="166.1" r=".51" fill="none" stroke="#000080" stroke-width=".21"/>
<path d="M106.5 171.2h7.6M106.5 173.7h7.6" fill="none" stroke="#000" stroke-width=".25"/>
<circle cx="106.5" cy="171.2" r=".51" fill="#000080"/>
<circle cx="106.5" cy="171.2" r=".51" fill="none" stroke="#000080" stroke-width=".21"/>
<path d="M106.5 168.6h7.6" fill="none" stroke="#000" stroke-width=".25"/>
<circle cx="106.5" cy="168.6" r=".51" fill="#000080"/>
<circle cx="106.5" cy="168.6" r=".51" fill="none" stroke="#000080" stroke-width=".21"/>
<path d="M106.5 166.1h7.6" fill="none" stroke="#000" stroke-width=".25"/>
<circle cx="106.5" cy="166.1" r=".51" fill="#000080"/>
<circle cx="106.5" cy="166.1" r=".51" fill="none" stroke="#000080" stroke-width=".21"/>
<path d="M106.5 163.6h7.6" fill="none" stroke="#000" stroke-width=".25"/>
<circle cx="106.5" cy="163.6" r=".51" fill="#000080"/>
<circle cx="106.5" cy="163.6" r=".51" fill="none" stroke="#000080" stroke-width=".21"/>
<circle cx="149.8" cy="61.8" r=".51" fill="#000080"/>
<circle cx="149.8" cy="61.8" r=".51" fill="none" stroke="#000080" stroke-width=".21"/>
<circle cx="149.8" cy="54.2" r=".51" fill="#000080"/>
<circle cx="149.8" cy="54.2" r=".51" fill="none" stroke="#000080" stroke-width=".21"/>
<circle cx="149.8" cy="51.6" r=".51" fill="#000080"/>
<circle cx="149.8" cy="51.6" r=".51" fill="none" stroke="#000080" stroke-width=".21"/>
<circle cx="149.8" cy="49.1" r=".51" fill="#000080"/>
<circle cx="149.8" cy="49.1" r=".51" fill="none" stroke="#000080" stroke-width=".21"/>
<circle cx="149.8" cy="46.5" r=".51" fill="#000080"/>
<circle cx="149.8" cy="46.5" r=".51" fill="none" stroke="#000080" stroke-width=".21"/>
<circle cx="149.8" cy="44" r=".51" fill="#000080"/>
<circle cx="149.8" cy="44" r=".51" fill="none" stroke="#000080" stroke-width=".21"/>
<circle cx="149.8" cy="41.4" r=".51" fill="#000080"/>
<circle cx="149.8" cy="41.4" r=".51" fill="none" stroke="#000080" stroke-width=".21"/>
<circle cx="109.1" cy="61.8" r=".51" fill="#000080"/>
<circle cx="109.1" cy="61.8" r=".51" fill="none" stroke="#000080" stroke-width=".21"/>
<circle cx="109.1" cy="59.2" r=".51" fill="#000080"/>
<circle cx="109.1" cy="59.2" r=".51" fill="none" stroke="#000080" stroke-width=".21"/>
<circle cx="109.1" cy="56.7" r=".51" fill="#000080"/>
<circle cx="109.1" cy="56.7" r=".51" fill="none" stroke="#000080" stroke-width=".21"/>
<circle cx="109.1" cy="54.2" r=".51" fill="#000080"/>
<circle cx="109.1" cy="54.2" r=".51" fill="none" stroke="#000080" stroke-width=".21"/>
<circle cx="109.1" cy="51.6" r=".51" fill="#000080"/>
<circle cx="109.1" cy="51.6" r=".51" fill="none" stroke="#000080" stroke-width=".21"/>
<circle cx="109.1" cy="41.4" r=".51" fill="#000080"/>
<circle cx="109.1" cy="41.4" r=".51" fill="none" stroke="#000080" stroke-width=".21"/>
<circle cx="109.1" cy="38.9" r=".51" fill="#000080"/>
<circle cx="109.1" cy="38.9" r=".51" fill="none" stroke="#000080" stroke-width=".21"/>
<circle cx="109.1" cy="36.4" r=".51" fill="#000080"/>
<circle cx="109.1" cy="36.4" r=".51" fill="none" stroke="#000080" stroke-width=".21"/>
<circle cx="109.1" cy="33.8" r=".51" fill="#000080"/>
<circle cx="109.1" cy="33.8" r=".51" fill="none" stroke="#000080" stroke-width=".21"/>
<circle cx="109.1" cy="31.3" r=".51" fill="#000080"/>
<circle cx="109.1" cy="31.3" r=".51" fill="none" stroke="#000080" stroke-width=".21"/>
<path d="M116.7 28.7h25.4v38.2h-25.4z" fill-rule="evenodd" fill="#ffffb0"/>
<path d="M116.7 28.7h25.4v38.2h-25.4z" fill="none" stroke="#800000" stroke-width=".21"/>
<path d="M142.1 64.3h7.7M142.1 61.8h7.7" fill="none" stroke="#000" stroke-width=".25"/>
<circle cx="149.8" cy="61.8" r=".51" fill="#000080"/>
<circle cx="149.8" cy="61.8" r=".51" fill="none" stroke="#000080" stroke-width=".21"/>
<path d="M142.1 56.7h7.7M142.1 54.2h7.7" fill="none" stroke="#000" stroke-width=".25"/>
<circle cx="149.8" cy="54.2" r=".51" fill="#000080"/>
<circle cx="149.8" cy="54.2" r=".51" fill="none" stroke="#000080" stroke-width=".21"/>
<path d="M142.1 51.6h7.7" fill="none" stroke="#000" stroke-width=".25"/>
<circle cx="149.8" cy="51.6" r=".51" fill="#000080"/>
<circle cx="149.8" cy="51.6" r=".51" fill="none" stroke="#000080" stroke-width=".21"/>
<path d="M142.1 49.1h7.7" fill="none" stroke="#000" stroke-width=".25"/>
<circle cx="149.8" cy="49.1" r=".51" fill="#000080"/>
<circle cx="149.8" cy="49.1" r=".51" fill="none" stroke="#000080" stroke-width=".21"/>
<path d="M142.1 46.5h7.7" fill="none" stroke="#000" stroke-width=".25"/>
<circle cx="149.8" cy="46.5" r=".51" fill="#000080"/>
<circle cx="149.8" cy="46.5" r=".51" fill="none" stroke="#000080" stroke-width=".21"/>
<path d="M142.1 44h7.7" fill="none" stroke="#000" stroke-width=".25"/>
<circle cx="149.8" cy="44" r=".51" fill="#000080"/>
<circle cx="149.8" cy="44" r=".51" fill="none" stroke="#000080" stroke-width=".21"/>
<path d="M142.1 41.4h7.7" fill="none" stroke="#000" stroke-width=".25"/>
<circle cx="149.8" cy="41.4" r=".51" fill="#000080"/>
<circle cx="149.8" cy="41.4" r=".51" fill="none" stroke="#000080" stroke-width=".21"/>
<path d="M109.1 64.3h7.6M109.1 61.8h7.6" fill="none" stroke="#000" stroke-width=".25"/>
<circle cx="109.1" cy="61.8" r=".51" fill="#000080"/>
<circle cx="109.1" cy="61.8" r=".51" fill="none" stroke="#000080" stroke-width=".21"/>
<path d="M109.1 59.3h7.6" fill="none" stroke="#000" stroke-width=".25"/>
<circle cx="109.1" cy="59.2" r=".51" fill="#000080"/>
<circle cx="109.1" cy="59.2" r=".51" fill="none" stroke="#000080" stroke-width=".21"/>
<path d="M109.1 56.7h7.6" fill="none" stroke="#000" stroke-width=".25"/>
<circle cx="109.1" cy="56.7" r=".51" fill="#000080"/>
<circle cx="109.1" cy="56.7" r=".51" fill="none" stroke="#000080" stroke-width=".21"/>
<path d="M109.1 54.2h7.6" fill="none" stroke="#000" stroke-width=".25"/>
<circle cx="109.1" cy="54.2" r=".51" fill="#000080"/>
<circle cx="109.1" cy="54.2" r=".51" fill="none" stroke="#000080" stroke-width=".21"/>
<path d="M109.1 51.6h7.6" fill="none" stroke="#000" stroke-width=".25"/>
<circle cx="109.1" cy="51.6" r=".51" fill="#000080"/>
<circle cx="109.1" cy="51.6" r=".51" fill="none" stroke="#000080" stroke-width=".21"/>
<path d="M109.1 49.1h7.6M109.1 44h7.6M109.1 41.4h7.6" fill="none" stroke="#000" stroke-width=".25"/>
<circle cx="109.1" cy="41.4" r=".51" fill="#000080"/>
<circle cx="109.1" cy="41.4" r=".51" fill="none" stroke="#000080" stroke-width=".21"/>
<path d="M109.1 38.9h7.6" fill="none" stroke="#000" stroke-width=".25"/>
<circle cx="109.1" cy="38.9" r=".51" fill="#000080"/>
<circle cx="109.1" cy="38.9" r=".51" fill="none" stroke="#000080" stroke-width=".21"/>
<path d="M109.1 36.4h7.6" fill="none" stroke="#000" stroke-width=".25"/>
<circle cx="109.1" cy="36.4" r=".51" fill="#000080"/>
<circle cx="109.1" cy="36.4" r=".51" fill="none" stroke="#000080" stroke-width=".21"/>
<path d="M109.1 33.8h7.6" fill="none" stroke="#000" stroke-width=".25"/>
<circle cx="109.1" cy="33.8" r=".51" fill="#000080"/>
<circle cx="109.1" cy="33.8" r=".51" fill="none" stroke="#000080" stroke-width=".21"/>
<path d="M109.1 31.3h7.6" fill="none" stroke="#000" stroke-width=".25"/>
<circle cx="109.1" cy="31.3" r=".51" fill="#000080"/>
<circle cx="109.1" cy="31.3" r=".51" fill="none" stroke="#000080" stroke-width=".21"/>
<circle cx="106.5" cy="122.8" r=".51" fill="#000080"/>
<circle cx="106.5" cy="122.8" r=".51" fill="none" stroke="#000080" stroke-width=".21"/>
<circle cx="106.5" cy="120.3" r=".51" fill="#000080"/>
<circle cx="106.5" cy="120.3" r=".51" fill="none" stroke="#000080" stroke-width=".21"/>
<circle cx="106.5" cy="117.8" r=".51" fill="#000080"/>
<circle cx="106.5" cy="117.8" r=".51" fill="none" stroke="#000080" stroke-width=".21"/>
<circle cx="106.5" cy="115.2" r=".51" fill="#000080"/>
<circle cx="106.5" cy="115.2" r=".51" fill="none" stroke="#000080" stroke-width=".21"/>
<circle cx="152.3" cy="133" r=".51" fill="#000080"/>
<circle cx="152.3" cy="133" r=".51" fill="none" stroke="#000080" stroke-width=".21"/>
<circle cx="152.3" cy="130.5" r=".51" fill="#000080"/>
<circle cx="152.3" cy="130.5" r=".51" fill="none" stroke="#000080" stroke-width=".21"/>
<circle cx="152.3" cy="127.9" r=".51" fill="#000080"/>
<circle cx="152.3" cy="127.9" r=".51" fill="none" stroke="#000080" stroke-width=".21"/>
<circle cx="152.3" cy="125.4" r=".51" fill="#000080"/>
<circle cx="152.3" cy="125.4" r=".51" fill="none" stroke="#000080" stroke-width=".21"/>
<circle cx="152.3" cy="122.8" r=".51" fill="#000080"/>
<circle cx="152.3" cy="122.8" r=".51" fill="none" stroke="#000080" stroke-width=".21"/>
<circle cx="152.3" cy="120.3" r=".51" fill="#000080"/>
<circle cx="152.3" cy="120.3" r=".51" fill="none" stroke="#000080" stroke-width=".21"/>
<circle cx="152.3" cy="117.8" r=".51" fill="#000080"/>
<circle cx="152.3" cy="117.8" r=".51" fill="none" stroke="#000080" stroke-width=".21"/>
<circle cx="152.3" cy="115.2" r=".51" fill="#000080"/>
<circle cx="152.3" cy="115.2" r=".51" fill="none" stroke="#000080" stroke-width=".21"/>
<circle cx="152.3" cy="112.7" r=".51" fill="#000080"/>
<circle cx="152.3" cy="112.7" r=".51" fill="none" stroke="#000080" stroke-width=".21"/>
<circle cx="152.3" cy="110.1" r=".51" fill="#000080"/>
<circle cx="152.3" cy="110.1" r=".51" fill="none" stroke="#000080" stroke-width=".21"/>
<circle cx="152.3" cy="107.6" r=".51" fill="#000080"/>
<circle cx="152.3" cy="107.6" r=".51" fill="none" stroke="#000080" stroke-width=".21"/>
<circle cx="152.3" cy="105" r=".51" fill="#000080"/>
<circle cx="152.3" cy="105" r=".51" fill="none" stroke="#000080" stroke-width=".21"/>
<circle cx="152.3" cy="102.5" r=".51" fill="#000080"/>
<circle cx="152.3" cy="102.5" r=".51" fill="none" stroke="#000080" stroke-width=".21"/>
<circle cx="152.3" cy="100" r=".51" fill="#000080"/>
<circle cx="152.3" cy="100" r=".51" fill="none" stroke="#000080" stroke-width=".21"/>
<circle cx="152.3" cy="97.4" r=".51" fill="#000080"/>
<circle cx="152.3" cy="97.4" r=".51" fill="none" stroke="#000080" stroke-width=".21"/>
<circle cx="152.3" cy="94.9" r=".51" fill="#000080"/>
<circle cx="152.3" cy="94.9" r=".51" fill="none" stroke="#000080" stroke-width=".21"/>
<circle cx="152.3" cy="92.3" r=".51" fill="#000080"/>
<circle cx="152.3" cy="92.3" r=".51" fill="none" stroke="#000080" stroke-width=".21"/>
<circle cx="106.5" cy="107.6" r=".51" fill="#000080"/>
<circle cx="106.5" cy="107.6" r=".51" fill="none" stroke="#000080" stroke-width=".21"/>
<circle cx="106.5" cy="105" r=".51" fill="#000080"/>
<circle cx="106.5" cy="105" r=".51" fill="none" stroke="#000080" stroke-width=".21"/>
<path d="M114.1 89.8h30.6v48.3h-30.6z" fill-rule="evenodd" fill="#ffffb0"/>
<path d="M114.1 89.8h30.6v48.3h-30.6z" fill="none" stroke="#800000" stroke-width=".21"/>
<path d="M106.5 125.4h7.6M106.5 122.9h7.6" fill="none" stroke="#000" stroke-width=".25"/>
<circle cx="106.5" cy="122.8" r=".51" fill="#000080"/>
<circle cx="106.5" cy="122.8" r=".51" fill="none" stroke="#000080" stroke-width=".21"/>
<path d="M106.5 120.3h7.6" fill="none" stroke="#000" stroke-width=".25"/>
<circle cx="106.5" cy="120.3" r=".51" fill="#000080"/>
<circle cx="106.5" cy="120.3" r=".51" fill="none" stroke="#000080" stroke-width=".21"/>
<path d="M106.5 117.8h7.6" fill="none" stroke="#000" stroke-width=".25"/>
<circle cx="106.5" cy="117.8" r=".51" fill="#000080"/>
<circle cx="106.5" cy="117.8" r=".51" fill="none" stroke="#000080" stroke-width=".21"/>
<path d="M106.5 115.2h7.6" fill="none" stroke="#000" stroke-width=".25"/>
<circle cx="106.5" cy="115.2" r=".51" fill="#000080"/>
<circle cx="106.5" cy="115.2" r=".51" fill="none" stroke="#000080" stroke-width=".21"/>
<path d="M144.7 135.6h7.6M144.7 133h7.6" fill="none" stroke="#000" stroke-width=".25"/>
<circle cx="152.3" cy="133" r=".51" fill="#000080"/>
<circle cx="152.3" cy="133" r=".51" fill="none" stroke="#000080" stroke-width=".21"/>
<path d="M144.7 130.5h7.6" fill="none" stroke="#000" stroke-width=".25"/>
<circle cx="152.3" cy="130.5" r=".51" fill="#000080"/>
<circle cx="152.3" cy="130.5" r=".51" fill="none" stroke="#000080" stroke-width=".21"/>
<path d="M144.7 127.9h7.6" fill="none" stroke="#000" stroke-width=".25"/>
<circle cx="152.3" cy="127.9" r=".51" fill="#000080"/>
<circle cx="152.3" cy="127.9" r=".51" fill="none" stroke="#000080" stroke-width=".21"/>
<path d="M144.7 125.4h7.6" fill="none" stroke="#000" stroke-width=".25"/>
<circle cx="152.3" cy="125.4" r=".51" fill="#000080"/>
<circle cx="152.3" cy="125.4" r=".51" fill="none" stroke="#000080" stroke-width=".21"/>
<path d="M144.7 122.9h7.6" fill="none" stroke="#000" stroke-width=".25"/>
<circle cx="152.3" cy="122.8" r=".51" fill="#000080"/>
<circle cx="152.3" cy="122.8" r=".51" fill="none" stroke="#000080" stroke-width=".21"/>
<path d="M144.7 120.3h7.6" fill="none" stroke="#000" stroke-width=".25"/>
<circle cx="152.3" cy="120.3" r=".51" fill="#000080"/>
<circle cx="152.3" cy="120.3" r=".51" fill="none" stroke="#000080" stroke-width=".21"/>
<path d="M144.7 117.8h7.6" fill="none" stroke="#000" stroke-width=".25"/>
<circle cx="152.3" cy="117.8" r=".51" fill="#000080"/>
<circle cx="152.3" cy="117.8" r=".51" fill="none" stroke="#000080" stroke-width=".21"/>
<path d="M144.7 115.2h7.6" fill="none" stroke="#000" stroke-width=".25"/>
<circle cx="152.3" cy="115.2" r=".51" fill="#000080"/>
<circle cx="152.3" cy="115.2" r=".51" fill="none" stroke="#000080" stroke-width=".21"/>
<path d="M144.7 112.7h7.6" fill="none" stroke="#000" stroke-width=".25"/>
<circle cx="152.3" cy="112.7" r=".51" fill="#000080"/>
<circle cx="152.3" cy="112.7" r=".51" fill="none" stroke="#000080" stroke-width=".21"/>
<path d="M144.7 110.1h7.6" fill="none" stroke="#000" stroke-width=".25"/>
<circle cx="152.3" cy="110.1" r=".51" fill="#000080"/>
<circle cx="152.3" cy="110.1" r=".51" fill="none" stroke="#000080" stroke-width=".21"/>
<path d="M144.7 107.6h7.6" fill="none" stroke="#000" stroke-width=".25"/>
<circle cx="152.3" cy="107.6" r=".51" fill="#000080"/>
<circle cx="152.3" cy="107.6" r=".51" fill="none" stroke="#000080" stroke-width=".21"/>
<path d="M144.7 105h7.6" fill="none" stroke="#000" stroke-width=".25"/>
<circle cx="152.3" cy="105" r=".51" fill="#000080"/>
<circle cx="152.3" cy="105" r=".51" fill="none" stroke="#000080" stroke-width=".21"/>
<path d="M144.7 102.5h7.6" fill="none" stroke="#000" stroke-width=".25"/>
<circle cx="152.3" cy="102.5" r=".51" fill="#000080"/>
<circle cx="152.3" cy="102.5" r=".51" fill="none" stroke="#000080" stroke-width=".21"/>
<path d="M144.7 100h7.6" fill="none" stroke="#000" stroke-width=".25"/>
<circle cx="152.3" cy="100" r=".51" fill="#000080"/>
<circle cx="152.3" cy="100" r=".51" fill="none" stroke="#000080" stroke-width=".21"/>
<path d="M144.7 97.4h7.6" fill="none" stroke="#000" stroke-width=".25"/>
<circle cx="152.3" cy="97.4" r=".51" fill="#000080"/>
<circle cx="152.3" cy="97.4" r=".51" fill="none" stroke="#000080" stroke-width=".21"/>
<path d="M144.7 94.9h7.6" fill="none" stroke="#000" stroke-width=".25"/>
<circle cx="152.3" cy="94.9" r=".51" fill="#000080"/>
<circle cx="152.3" cy="94.9" r=".51" fill="none" stroke="#000080" stroke-width=".21"/>
<path d="M144.7 92.3h7.6" fill="none" stroke="#000" stroke-width=".25"/>
<circle cx="152.3" cy="92.3" r=".51" fill="#000080"/>
<circle cx="152.3" cy="92.3" r=".51" fill="none" stroke="#000080" stroke-width=".21"/>
<path d="M106.5 110.1h7.6M106.5 107.6h7.6" fill="none" stroke="#000" stroke-width=".25"/>
<circle cx="106.5" cy="107.6" r=".51" fill="#000080"/>
<circle cx="106.5" cy="107.6" r=".51" fill="none" stroke="#000080" stroke-width=".21"/>
<path d="M106.5 105h7.6" fill="none" stroke="#000" stroke-width=".25"/>
<circle cx="106.5" cy="105" r=".51" fill="#000080"/>
<circle cx="106.5" cy="105" r=".51" fill="none" stroke="#000080" stroke-width=".21"/>
<path d="M101.4 117.8v4.4M101.4 123.5v4.4M106.5 130.5h7.6M106.5 135.6h7.6" fill="none" stroke="#000" stroke-width=".25"/>
<g fill="none" stroke="#800000" stroke-width=".25">
<path d="M13.6 26.2h2.6M14.9 26.2v2.5M229.9 26.2h2.5M231.2 26.2v2.5M13.6 54.2h2.6M14.9 54.2v2.5M166.3 56.7h2.5M167.6 56.7v2.6M77.3 87.2h2.5M78.5 87.2v2.6M229.9 87.2h2.5M231.2 87.2v2.6"/>
<path d="M13.7 110.1h2.5M14.9 110.1v2.6M64.5 158.5h2.6M65.8 158.5v2.5M191.7 161h2.6M193 161v2.6"/>
</g>
<path d="M100.1 121.6l2.6 1.3v1.2l-2.6-1.2z" fill="none" stroke="#00f" stroke-width=".25"/>
<circle cx="282" cy="161" r=".51" fill="#000080"/>
<circle cx="282" cy="161" r=".51" fill="none" stroke="#000080" stroke-width=".21"/>
<circle cx="282" cy="158.5" r=".51" fill="#000080"/>
<circle cx="282" cy="158.5" r=".51" fill="none" stroke="#000080" stroke-width=".21"/>
<circle cx="282" cy="155.9" r=".51" fill="#000080"/>
<circle cx="282" cy="155.9" r=".51" fill="none" stroke="#000080" stroke-width=".21"/>
<circle cx="282" cy="153.4" r=".51" fill="#000080"/>
<circle cx="282" cy="153.4" r=".51" fill="none" stroke="#000080" stroke-width=".21"/>
<circle cx="282" cy="150.8" r=".51" fill="#000080"/>
<circle cx="282" cy="150.8" r=".51" fill="none" stroke="#000080" stroke-width=".21"/>
<circle cx="282" cy="148.3" r=".51" fill="#000080"/>
<circle cx="282" cy="148.3" r=".51" fill="none" stroke="#000080" stroke-width=".21"/>
<circle cx="282" cy="145.8" r=".51" fill="#000080"/>
<circle cx="282" cy="145.8" r=".51" fill="none" stroke="#000080" stroke-width=".21"/>
<circle cx="282" cy="143.2" r=".51" fill="#000080"/>
<circle cx="282" cy="143.2" r=".51" fill="none" stroke="#000080" stroke-width=".21"/>
<circle cx="282" cy="140.7" r=".51" fill="#000080"/>
<circle cx="282" cy="140.7" r=".51" fill="none" stroke="#000080" stroke-width=".21"/>
<circle cx="282" cy="138.1" r=".51" fill="#000080"/>
<circle cx="282" cy="138.1" r=".51" fill="none" stroke="#000080" stroke-width=".21"/>
<circle cx="282" cy="135.6" r=".51" fill="#000080"/>
<circle cx="282" cy="135.6" r=".51" fill="none" stroke="#000080" stroke-width=".21"/>
<circle cx="282" cy="133" r=".51" fill="#000080"/>
<circle cx="282" cy="133" r=".51" fill="none" stroke="#000080" stroke-width=".21"/>
<circle cx="282" cy="130.5" r=".51" fill="#000080"/>
<circle cx="282" cy="130.5" r=".51" fill="none" stroke="#000080" stroke-width=".21"/>
<circle cx="282" cy="127.9" r=".51" fill="#000080"/>
<circle cx="282" cy="127.9" r=".51" fill="none" stroke="#000080" stroke-width=".21"/>
<circle cx="282" cy="125.4" r=".51" fill="#000080"/>
<circle cx="282" cy="125.4" r=".51" fill="none" stroke="#000080" stroke-width=".21"/>
<circle cx="282" cy="122.8" r=".51" fill="#000080"/>
<circle cx="282" cy="122.8" r=".51" fill="none" stroke="#000080" stroke-width=".21"/>
<circle cx="282" cy="120.3" r=".51" fill="#000080"/>
<circle cx="282" cy="120.3" r=".51" fill="none" stroke="#000080" stroke-width=".21"/>
<circle cx="282" cy="117.8" r=".51" fill="#000080"/>
<circle cx="282" cy="117.8" r=".51" fill="none" stroke="#000080" stroke-width=".21"/>
<circle cx="282" cy="115.2" r=".51" fill="#000080"/>
<circle cx="282" cy="115.2" r=".51" fill="none" stroke="#000080" stroke-width=".21"/>
<circle cx="282" cy="112.7" r=".51" fill="#000080"/>
<circle cx="282" cy="112.7" r=".51" fill="none" stroke="#000080" stroke-width=".21"/>
<circle cx="282" cy="110.1" r=".51" fill="#000080"/>
<circle cx="282" cy="110.1" r=".51" fill="none" stroke="#000080" stroke-width=".21"/>
<circle cx="282" cy="107.6" r=".51" fill="#000080"/>
<circle cx="282" cy="107.6" r=".51" fill="none" stroke="#000080" stroke-width=".21"/>
<circle cx="282" cy="105" r=".51" fill="#000080"/>
<circle cx="282" cy="105" r=".51" fill="none" stroke="#000080" stroke-width=".21"/>
<circle cx="282" cy="102.5" r=".51" fill="#000080"/>
<circle cx="282" cy="102.5" r=".51" fill="none" stroke="#000080" stroke-width=".21"/>
<circle cx="282" cy="100" r=".51" fill="#000080"/>
<circle cx="282" cy="100" r=".51" fill="none" stroke="#000080" stroke-width=".21"/>
<circle cx="282" cy="97.4" r=".51" fill="#000080"/>
<circle cx="282" cy="97.4" r=".51" fill="none" stroke="#000080" stroke-width=".21"/>
<circle cx="282" cy="94.9" r=".51" fill="#000080"/>
<circle cx="282" cy="94.9" r=".51" fill="none" stroke="#000080" stroke-width=".21"/>
<circle cx="282" cy="92.3" r=".51" fill="#000080"/>
<circle cx="282" cy="92.3" r=".51" fill="none" stroke="#000080" stroke-width=".21"/>
<circle cx="282" cy="89.8" r=".51" fill="#000080"/>
<circle cx="282" cy="89.8" r=".51" fill="none" stroke="#000080" stroke-width=".21"/>
<circle cx="282" cy="87.2" r=".51" fill="#000080"/>
<circle cx="282" cy="87.2" r=".51" fill="none" stroke="#000080" stroke-width=".21"/>
<circle cx="282" cy="84.7" r=".51" fill="#000080"/>
<circle cx="282" cy="84.7" r=".51" fill="none" stroke="#000080" stroke-width=".21"/>
<circle cx="282" cy="82.1" r=".51" fill="#000080"/>
<circle cx="282" cy="82.1" r=".51" fill="none" stroke="#000080" stroke-width=".21"/>
<circle cx="282" cy="79.6" r=".51" fill="#000080"/>
<circle cx="282" cy="79.6" r=".51" fill="none" stroke="#000080" stroke-width=".21"/>
<circle cx="282" cy="77.1" r=".51" fill="#000080"/>
<circle cx="282" cy="77.1" r=".51" fill="none" stroke="#000080" stroke-width=".21"/>
<circle cx="282" cy="74.5" r=".51" fill="#000080"/>
<circle cx="282" cy="74.5" r=".51" fill="none" stroke="#000080" stroke-width=".21"/>
<circle cx="282" cy="72" r=".51" fill="#000080"/>
<circle cx="282" cy="72" r=".51" fill="none" stroke="#000080" stroke-width=".21"/>
<circle cx="282" cy="69.4" r=".51" fill="#000080"/>
<circle cx="282" cy="69.4" r=".51" fill="none" stroke="#000080" stroke-width=".21"/>
<circle cx="246.4" cy="161" r=".51" fill="#000080"/>
<circle cx="246.4" cy="161" r=".51" fill="none" stroke="#000080" stroke-width=".21"/>
<circle cx="246.4" cy="158.5" r=".51" fill="#000080"/>
<circle cx="246.4" cy="158.5" r=".51" fill="none" stroke="#000080" stroke-width=".21"/>
<circle cx="246.4" cy="155.9" r=".51" fill="#000080"/>
<circle cx="246.4" cy="155.9" r=".51" fill="none" stroke="#000080" stroke-width=".21"/>
<circle cx="246.4" cy="153.4" r=".51" fill="#000080"/>
<circle cx="246.4" cy="153.4" r=".51" fill="none" stroke="#000080" stroke-width=".21"/>
<circle cx="246.4" cy="150.8" r=".51" fill="#000080"/>
<circle cx="246.4" cy="150.8" r=".51" fill="none" stroke="#000080" stroke-width=".21"/>
<circle cx="246.4" cy="148.3" r=".51" fill="#000080"/>
<circle cx="246.4" cy="148.3" r=".51" fill="none" stroke="#000080" stroke-width=".21"/>
<circle cx="246.4" cy="145.8" r=".51" fill="#000080"/>
<circle cx="246.4" cy="145.8" r=".51" fill="none" stroke="#000080" stroke-width=".21"/>
<circle cx="246.4" cy="143.2" r=".51" fill="#000080"/>
<circle cx="246.4" cy="143.2" r=".51" fill="none" stroke="#000080" stroke-width=".21"/>
<circle cx="246.4" cy="140.7" r=".51" fill="#000080"/>
<circle cx="246.4" cy="140.7" r=".51" fill="none" stroke="#000080" stroke-width=".21"/>
<circle cx="246.4" cy="138.1" r=".51" fill="#000080"/>
<circle cx="246.4" cy="138.1" r=".51" fill="none" stroke="#000080" stroke-width=".21"/>
<circle cx="246.4" cy="135.6" r=".51" fill="#000080"/>
<circle cx="246.4" cy="135.6" r=".51" fill="none" stroke="#000080" stroke-width=".21"/>
<circle cx="246.4" cy="133" r=".51" fill="#000080"/>
<circle cx="246.4" cy="133" r=".51" fill="none" stroke="#000080" stroke-width=".21"/>
<circle cx="246.4" cy="130.5" r=".51" fill="#000080"/>
<circle cx="246.4" cy="130.5" r=".51" fill="none" stroke="#000080" stroke-width=".21"/>
<circle cx="246.4" cy="127.9" r=".51" fill="#000080"/>
<circle cx="246.4" cy="127.9" r=".51" fill="none" stroke="#000080" stroke-width=".21"/>
<circle cx="246.4" cy="125.4" r=".51" fill="#000080"/>
<circle cx="246.4" cy="125.4" r=".51" fill="none" stroke="#000080" stroke-width=".21"/>
<circle cx="246.4" cy="122.8" r=".51" fill="#000080"/>
<circle cx="246.4" cy="122.8" r=".51" fill="none" stroke="#000080" stroke-width=".21"/>
<circle cx="246.4" cy="120.3" r=".51" fill="#000080"/>
<circle cx="246.4" cy="120.3" r=".51" fill="none" stroke="#000080" stroke-width=".21"/>
<circle cx="246.4" cy="117.8" r=".51" fill="#000080"/>
<circle cx="246.4" cy="117.8" r=".51" fill="none" stroke="#000080" stroke-width=".21"/>
<circle cx="246.4" cy="115.2" r=".51" fill="#000080"/>
<circle cx="246.4" cy="115.2" r=".51" fill="none" stroke="#000080" stroke-width=".21"/>
<circle cx="246.4" cy="112.7" r=".51" fill="#000080"/>
<circle cx="246.4" cy="112.7" r=".51" fill="none" stroke="#000080" stroke-width=".21"/>
<circle cx="246.4" cy="110.1" r=".51" fill="#000080"/>
<circle cx="246.4" cy="110.1" r=".51" fill="none" stroke="#000080" stroke-width=".21"/>
<circle cx="246.4" cy="107.6" r=".51" fill="#000080"/>
<circle cx="246.4" cy="107.6" r=".51" fill="none" stroke="#000080" stroke-width=".21"/>
<circle cx="246.4" cy="105" r=".51" fill="#000080"/>
<circle cx="246.4" cy="105" r=".51" fill="none" stroke="#000080" stroke-width=".21"/>
<circle cx="246.4" cy="102.5" r=".51" fill="#000080"/>
<circle cx="246.4" cy="102.5" r=".51" fill="none" stroke="#000080" stroke-width=".21"/>
<circle cx="246.4" cy="100" r=".51" fill="#000080"/>
<circle cx="246.4" cy="100" r=".51" fill="none" stroke="#000080" stroke-width=".21"/>
<circle cx="246.4" cy="97.4" r=".51" fill="#000080"/>
<circle cx="246.4" cy="97.4" r=".51" fill="none" stroke="#000080" stroke-width=".21"/>
<circle cx="246.4" cy="94.9" r=".51" fill="#000080"/>
<circle cx="246.4" cy="94.9" r=".51" fill="none" stroke="#000080" stroke-width=".21"/>
<circle cx="246.4" cy="92.3" r=".51" fill="#000080"/>
<circle cx="246.4" cy="92.3" r=".51" fill="none" stroke="#000080" stroke-width=".21"/>
<circle cx="246.4" cy="89.8" r=".51" fill="#000080"/>
<circle cx="246.4" cy="89.8" r=".51" fill="none" stroke="#000080" stroke-width=".21"/>
<circle cx="246.4" cy="87.2" r=".51" fill="#000080"/>
<circle cx="246.4" cy="87.2" r=".51" fill="none" stroke="#000080" stroke-width=".21"/>
<circle cx="246.4" cy="84.7" r=".51" fill="#000080"/>
<circle cx="246.4" cy="84.7" r=".51" fill="none" stroke="#000080" stroke-width=".21"/>
<circle cx="246.4" cy="82.1" r=".51" fill="#000080"/>
<circle cx="246.4" cy="82.1" r=".51" fill="none" stroke="#000080" stroke-width=".21"/>
<circle cx="246.4" cy="79.6" r=".51" fill="#000080"/>
<circle cx="246.4" cy="79.6" r=".51" fill="none" stroke="#000080" stroke-width=".21"/>
<circle cx="246.4" cy="77.1" r=".51" fill="#000080"/>
<circle cx="246.4" cy="77.1" r=".51" fill="none" stroke="#000080" stroke-width=".21"/>
<circle cx="246.4" cy="74.5" r=".51" fill="#000080"/>
<circle cx="246.4" cy="74.5" r=".51" fill="none" stroke="#000080" stroke-width=".21"/>
<circle cx="246.4" cy="72" r=".51" fill="#000080"/>
<circle cx="246.4" cy="72" r=".51" fill="none" stroke="#000080" stroke-width=".21"/>
<path d="M254.1 61.8h20.3v101.8h-20.3z" fill-rule="evenodd" fill="#ffffb0"/>
<path d="M254.1 61.8h20.3v101.8h-20.3z" fill="none" stroke="#800000" stroke-width=".21"/>
<path d="M274.4 161h7.6" fill="none" stroke="#000" stroke-width=".25"/>
<circle cx="282" cy="161" r=".51" fill="#000080"/>
<circle cx="282" cy="161" r=".51" fill="none" stroke="#000080" stroke-width=".21"/>
<path d="M274.4 158.5h7.6" fill="none" stroke="#000" stroke-width=".25"/>
<circle cx="282" cy="158.5" r=".51" fill="#000080"/>
<circle cx="282" cy="158.5" r=".51" fill="none" stroke="#000080" stroke-width=".21"/>
<path d="M274.4 155.9h7.6" fill="none" stroke="#000" stroke-width=".25"/>
<circle cx="282" cy="155.9" r=".51" fill="#000080"/>
<circle cx="282" cy="155.9" r=".51" fill="none" stroke="#000080" stroke-width=".21"/>
<path d="M274.4 153.4h7.6" fill="none" stroke="#000" stroke-width=".25"/>
<circle cx="282" cy="153.4" r=".51" fill="#000080"/>
<circle cx="282" cy="153.4" r=".51" fill="none" stroke="#000080" stroke-width=".21"/>
<path d="M274.4 150.8h7.6" fill="none" stroke="#000" stroke-width=".25"/>
<circle cx="282" cy="150.8" r=".51" fill="#000080"/>
<circle cx="282" cy="150.8" r=".51" fill="none" stroke="#000080" stroke-width=".21"/>
<path d="M274.4 148.3h7.6" fill="none" stroke="#000" stroke-width=".25"/>
<circle cx="282" cy="148.3" r=".51" fill="#000080"/>
<circle cx="282" cy="148.3" r=".51" fill="none" stroke="#000080" stroke-width=".21"/>
<path d="M274.4 145.8h7.6" fill="none" stroke="#000" stroke-width=".25"/>
<circle cx="282" cy="145.8" r=".51" fill="#000080"/>
<circle cx="282" cy="145.8" r=".51" fill="none" stroke="#000080" stroke-width=".21"/>
<path d="M274.4 143.2h7.6" fill="none" stroke="#000" stroke-width=".25"/>
<circle cx="282" cy="143.2" r=".51" fill="#000080"/>
<circle cx="282" cy="143.2" r=".51" fill="none" stroke="#000080" stroke-width=".21"/>
<path d="M274.4 140.7h7.6" fill="none" stroke="#000" stroke-width=".25"/>
<circle cx="282" cy="140.7" r=".51" fill="#000080"/>
<circle cx="282" cy="140.7" r=".51" fill="none" stroke="#000080" stroke-width=".21"/>
<path d="M274.4 138.1h7.6" fill="none" stroke="#000" stroke-width=".25"/>
<circle cx="282" cy="138.1" r=".51" fill="#000080"/>
<circle cx="282" cy="138.1" r=".51" fill="none" stroke="#000080" stroke-width=".21"/>
<path d="M274.4 135.6h7.6" fill="none" stroke="#000" stroke-width=".25"/>
<circle cx="282" cy="135.6" r=".51" fill="#000080"/>
<circle cx="282" cy="135.6" r=".51" fill="none" stroke="#000080" stroke-width=".21"/>
<path d="M274.4 133h7.6" fill="none" stroke="#000" stroke-width=".25"/>
<circle cx="282" cy="133" r=".51" fill="#000080"/>
<circle cx="282" cy="133" r=".51" fill="none" stroke="#000080" stroke-width=".21"/>
<path d="M274.4 130.5h7.6" fill="none" stroke="#000" stroke-width=".25"/>
<circle cx="282" cy="130.5" r=".51" fill="#000080"/>
<circle cx="282" cy="130.5" r=".51" fill="none" stroke="#000080" stroke-width=".21"/>
<path d="M274.4 127.9h7.6" fill="none" stroke="#000" stroke-width=".25"/>
<circle cx="282" cy="127.9" r=".51" fill="#000080"/>
<circle cx="282" cy="127.9" r=".51" fill="none" stroke="#000080" stroke-width=".21"/>
<path d="M274.4 125.4h7.6" fill="none" stroke="#000" stroke-width=".25"/>
<circle cx="282" cy="125.4" r=".51" fill="#000080"/>
<circle cx="282" cy="125.4" r=".51" fill="none" stroke="#000080" stroke-width=".21"/>
<path d="M274.4 122.9h7.6" fill="none" stroke="#000" stroke-width=".25"/>
<circle cx="282" cy="122.8" r=".51" fill="#000080"/>
<circle cx="282" cy="122.8" r=".51" fill="none" stroke="#000080" stroke-width=".21"/>
<path d="M274.4 120.3h7.6" fill="none" stroke="#000" stroke-width=".25"/>
<circle cx="282" cy="120.3" r=".51" fill="#000080"/>
<circle cx="282" cy="120.3" r=".51" fill="none" stroke="#000080" stroke-width=".21"/>
<path d="M274.4 117.8h7.6" fill="none" stroke="#000" stroke-width=".25"/>
<circle cx="282" cy="117.8" r=".51" fill="#000080"/>
<circle cx="282" cy="117.8" r=".51" fill="none" stroke="#000080" stroke-width=".21"/>
<path d="M274.4 115.2h7.6" fill="none" stroke="#000" stroke-width=".25"/>
<circle cx="282" cy="115.2" r=".51" fill="#000080"/>
<circle cx="282" cy="115.2" r=".51" fill="none" stroke="#000080" stroke-width=".21"/>
<path d="M274.4 112.7h7.6" fill="none" stroke="#000" stroke-width=".25"/>
<circle cx="282" cy="112.7" r=".51" fill="#000080"/>
<circle cx="282" cy="112.7" r=".51" fill="none" stroke="#000080" stroke-width=".21"/>
<path d="M274.4 110.1h7.6" fill="none" stroke="#000" stroke-width=".25"/>
<circle cx="282" cy="110.1" r=".51" fill="#000080"/>
<circle cx="282" cy="110.1" r=".51" fill="none" stroke="#000080" stroke-width=".21"/>
<path d="M274.4 107.6h7.6" fill="none" stroke="#000" stroke-width=".25"/>
<circle cx="282" cy="107.6" r=".51" fill="#000080"/>
<circle cx="282" cy="107.6" r=".51" fill="none" stroke="#000080" stroke-width=".21"/>
<path d="M274.4 105.1h7.6" fill="none" stroke="#000" stroke-width=".25"/>
<circle cx="282" cy="105" r=".51" fill="#000080"/>
<circle cx="282" cy="105" r=".51" fill="none" stroke="#000080" stroke-width=".21"/>
<path d="M274.4 102.5h7.6" fill="none" stroke="#000" stroke-width=".25"/>
<circle cx="282" cy="102.5" r=".51" fill="#000080"/>
<circle cx="282" cy="102.5" r=".51" fill="none" stroke="#000080" stroke-width=".21"/>
<path d="M274.4 100h7.6" fill="none" stroke="#000" stroke-width=".25"/>
<circle cx="282" cy="100" r=".51" fill="#000080"/>
<circle cx="282" cy="100" r=".51" fill="none" stroke="#000080" stroke-width=".21"/>
<path d="M274.4 97.4h7.6" fill="none" stroke="#000" stroke-width=".25"/>
<circle cx="282" cy="97.4" r=".51" fill="#000080"/>
<circle cx="282" cy="97.4" r=".51" fill="none" stroke="#000080" stroke-width=".21"/>
<path d="M274.4 94.9h7.6" fill="none" stroke="#000" stroke-width=".25"/>
<circle cx="282" cy="94.9" r=".51" fill="#000080"/>
<circle cx="282" cy="94.9" r=".51" fill="none" stroke="#000080" stroke-width=".21"/>
<path d="M274.4 92.3h7.6" fill="none" stroke="#000" stroke-width=".25"/>
<circle cx="282" cy="92.3" r=".51" fill="#000080"/>
<circle cx="282" cy="92.3" r=".51" fill="none" stroke="#000080" stroke-width=".21"/>
<path d="M274.4 89.8h7.6" fill="none" stroke="#000" stroke-width=".25"/>
<circle cx="282" cy="89.8" r=".51" fill="#000080"/>
<circle cx="282" cy="89.8" r=".51" fill="none" stroke="#000080" stroke-width=".21"/>
<path d="M274.4 87.2h7.6" fill="none" stroke="#000" stroke-width=".25"/>
<circle cx="282" cy="87.2" r=".51" fill="#000080"/>
<circle cx="282" cy="87.2" r=".51" fill="none" stroke="#000080" stroke-width=".21"/>
<path d="M274.4 84.7h7.6" fill="none" stroke="#000" stroke-width=".25"/>
<circle cx="282" cy="84.7" r=".51" fill="#000080"/>
<circle cx="282" cy="84.7" r=".51" fill="none" stroke="#000080" stroke-width=".21"/>
<path d="M274.4 82.1h7.6" fill="none" stroke="#000" stroke-width=".25"/>
<circle cx="282" cy="82.1" r=".51" fill="#000080"/>
<circle cx="282" cy="82.1" r=".51" fill="none" stroke="#000080" stroke-width=".21"/>
<path d="M274.4 79.6h7.6" fill="none" stroke="#000" stroke-width=".25"/>
<circle cx="282" cy="79.6" r=".51" fill="#000080"/>
<circle cx="282" cy="79.6" r=".51" fill="none" stroke="#000080" stroke-width=".21"/>
<path d="M274.4 77.1h7.6" fill="none" stroke="#000" stroke-width=".25"/>
<circle cx="282" cy="77.1" r=".51" fill="#000080"/>
<circle cx="282" cy="77.1" r=".51" fill="none" stroke="#000080" stroke-width=".21"/>
<path d="M274.4 74.5h7.6" fill="none" stroke="#000" stroke-width=".25"/>
<circle cx="282" cy="74.5" r=".51" fill="#000080"/>
<circle cx="282" cy="74.5" r=".51" fill="none" stroke="#000080" stroke-width=".21"/>
<path d="M274.4 72h7.6" fill="none" stroke="#000" stroke-width=".25"/>
<circle cx="282" cy="72" r=".51" fill="#000080"/>
<circle cx="282" cy="72" r=".51" fill="none" stroke="#000080" stroke-width=".21"/>
<path d="M274.4 69.4h7.6" fill="none" stroke="#000" stroke-width=".25"/>
<circle cx="282" cy="69.4" r=".51" fill="#000080"/>
<circle cx="282" cy="69.4" r=".51" fill="none" stroke="#000080" stroke-width=".21"/>
<path d="M274.4 66.9h7.6M246.4 161h7.7" fill="none" stroke="#000" stroke-width=".25"/>
<circle cx="246.4" cy="161" r=".51" fill="#000080"/>
<circle cx="246.4" cy="161" r=".51" fill="none" stroke="#000080" stroke-width=".21"/>
<path d="M246.4 158.5h7.7" fill="none" stroke="#000" stroke-width=".25"/>
<circle cx="246.4" cy="158.5" r=".51" fill="#000080"/>
<circle cx="246.4" cy="158.5" r=".51" fill="none" stroke="#000080" stroke-width=".21"/>
<path d="M246.4 155.9h7.7" fill="none" stroke="#000" stroke-width=".25"/>
<circle cx="246.4" cy="155.9" r=".51" fill="#000080"/>
<circle cx="246.4" cy="155.9" r=".51" fill="none" stroke="#000080" stroke-width=".21"/>
<path d="M246.4 153.4h7.7" fill="none" stroke="#000" stroke-width=".25"/>
<circle cx="246.4" cy="153.4" r=".51" fill="#000080"/>
<circle cx="246.4" cy="153.4" r=".51" fill="none" stroke="#000080" stroke-width=".21"/>
<path d="M246.4 150.8h7.7" fill="none" stroke="#000" stroke-width=".25"/>
<circle cx="246.4" cy="150.8" r=".51" fill="#000080"/>
<circle cx="246.4" cy="150.8" r=".51" fill="none" stroke="#000080" stroke-width=".21"/>
<path d="M246.4 148.3h7.7" fill="none" stroke="#000" stroke-width=".25"/>
<circle cx="246.4" cy="148.3" r=".51" fill="#000080"/>
<circle cx="246.4" cy="148.3" r=".51" fill="none" stroke="#000080" stroke-width=".21"/>
<path d="M246.4 145.8h7.7" fill="none" stroke="#000" stroke-width=".25"/>
<circle cx="246.4" cy="145.8" r=".51" fill="#000080"/>
<circle cx="246.4" cy="145.8" r=".51" fill="none" stroke="#000080" stroke-width=".21"/>
<path d="M246.4 143.2h7.7" fill="none" stroke="#000" stroke-width=".25"/>
<circle cx="246.4" cy="143.2" r=".51" fill="#000080"/>
<circle cx="246.4" cy="143.2" r=".51" fill="none" stroke="#000080" stroke-width=".21"/>
<path d="M246.4 140.7h7.7" fill="none" stroke="#000" stroke-width=".25"/>
<circle cx="246.4" cy="140.7" r=".51" fill="#000080"/>
<circle cx="246.4" cy="140.7" r=".51" fill="none" stroke="#000080" stroke-width=".21"/>
<path d="M246.4 138.1h7.7" fill="none" stroke="#000" stroke-width=".25"/>
<circle cx="246.4" cy="138.1" r=".51" fill="#000080"/>
<circle cx="246.4" cy="138.1" r=".51" fill="none" stroke="#000080" stroke-width=".21"/>
<path d="M246.4 135.6h7.7" fill="none" stroke="#000" stroke-width=".25"/>
<circle cx="246.4" cy="135.6" r=".51" fill="#000080"/>
<circle cx="246.4" cy="135.6" r=".51" fill="none" stroke="#000080" stroke-width=".21"/>
<path d="M246.4 133h7.7" fill="none" stroke="#000" stroke-width=".25"/>
<circle cx="246.4" cy="133" r=".51" fill="#000080"/>
<circle cx="246.4" cy="133" r=".51" fill="none" stroke="#000080" stroke-width=".21"/>
<path d="M246.4 130.5h7.7" fill="none" stroke="#000" stroke-width=".25"/>
<circle cx="246.4" cy="130.5" r=".51" fill="#000080"/>
<circle cx="246.4" cy="130.5" r=".51" fill="none" stroke="#000080" stroke-width=".21"/>
<path d="M246.4 127.9h7.7" fill="none" stroke="#000" stroke-width=".25"/>
<circle cx="246.4" cy="127.9" r=".51" fill="#000080"/>
<circle cx="246.4" cy="127.9" r=".51" fill="none" stroke="#000080" stroke-width=".21"/>
<path d="M246.4 125.4h7.7" fill="none" stroke="#000" stroke-width=".25"/>
<circle cx="246.4" cy="125.4" r=".51" fill="#000080"/>
<circle cx="246.4" cy="125.4" r=".51" fill="none" stroke="#000080" stroke-width=".21"/>
<path d="M246.4 122.9h7.7" fill="none" stroke="#000" stroke-width=".25"/>
<circle cx="246.4" cy="122.8" r=".51" fill="#000080"/>
<circle cx="246.4" cy="122.8" r=".51" fill="none" stroke="#000080" stroke-width=".21"/>
<path d="M246.4 120.3h7.7" fill="none" stroke="#000" stroke-width=".25"/>
<circle cx="246.4" cy="120.3" r=".51" fill="#000080"/>
<circle cx="246.4" cy="120.3" r=".51" fill="none" stroke="#000080" stroke-width=".21"/>
<path d="M246.4 117.8h7.7" fill="none" stroke="#000" stroke-width=".25"/>
<circle cx="246.4" cy="117.8" r=".51" fill="#000080"/>
<circle cx="246.4" cy="117.8" r=".51" fill="none" stroke="#000080" stroke-width=".21"/>
<path d="M246.4 115.2h7.7" fill="none" stroke="#000" stroke-width=".25"/>
<circle cx="246.4" cy="115.2" r=".51" fill="#000080"/>
<circle cx="246.4" cy="115.2" r=".51" fill="none" stroke="#000080" stroke-width=".21"/>
<path d="M246.4 112.7h7.7" fill="none" stroke="#000" stroke-width=".25"/>
<circle cx="246.4" cy="112.7" r=".51" fill="#000080"/>
<circle cx="246.4" cy="112.7" r=".51" fill="none" stroke="#000080" stroke-width=".21"/>
<path d="M246.4 110.1h7.7" fill="none" stroke="#000" stroke-width=".25"/>
<circle cx="246.4" cy="110.1" r=".51" fill="#000080"/>
<circle cx="246.4" cy="110.1" r=".51" fill="none" stroke="#000080" stroke-width=".21"/>
<path d="M246.4 107.6h7.7" fill="none" stroke="#000" stroke-width=".25"/>
<circle cx="246.4" cy="107.6" r=".51" fill="#000080"/>
<circle cx="246.4" cy="107.6" r=".51" fill="none" stroke="#000080" stroke-width=".21"/>
<path d="M246.4 105.1h7.7" fill="none" stroke="#000" stroke-width=".25"/>
<circle cx="246.4" cy="105" r=".51" fill="#000080"/>
<circle cx="246.4" cy="105" r=".51" fill="none" stroke="#000080" stroke-width=".21"/>
<path d="M246.4 102.5h7.7" fill="none" stroke="#000" stroke-width=".25"/>
<circle cx="246.4" cy="102.5" r=".51" fill="#000080"/>
<circle cx="246.4" cy="102.5" r=".51" fill="none" stroke="#000080" stroke-width=".21"/>
<path d="M246.4 100h7.7" fill="none" stroke="#000" stroke-width=".25"/>
<circle cx="246.4" cy="100" r=".51" fill="#000080"/>
<circle cx="246.4" cy="100" r=".51" fill="none" stroke="#000080" stroke-width=".21"/>
<path d="M246.4 97.4h7.7" fill="none" stroke="#000" stroke-width=".25"/>
<circle cx="246.4" cy="97.4" r=".51" fill="#000080"/>
<circle cx="246.4" cy="97.4" r=".51" fill="none" stroke="#000080" stroke-width=".21"/>
<path d="M246.4 94.9h7.7" fill="none" stroke="#000" stroke-width=".25"/>
<circle cx="246.4" cy="94.9" r=".51" fill="#000080"/>
<circle cx="246.4" cy="94.9" r=".51" fill="none" stroke="#000080" stroke-width=".21"/>
<path d="M246.4 92.3h7.7" fill="none" stroke="#000" stroke-width=".25"/>
<circle cx="246.4" cy="92.3" r=".51" fill="#000080"/>
<circle cx="246.4" cy="92.3" r=".51" fill="none" stroke="#000080" stroke-width=".21"/>
<path d="M246.4 89.8h7.7" fill="none" stroke="#000" stroke-width=".25"/>
<circle cx="246.4" cy="89.8" r=".51" fill="#000080"/>
<circle cx="246.4" cy="89.8" r=".51" fill="none" stroke="#000080" stroke-width=".21"/>
<path d="M246.4 87.2h7.7" fill="none" stroke="#000" stroke-width=".25"/>
<circle cx="246.4" cy="87.2" r=".51" fill="#000080"/>
<circle cx="246.4" cy="87.2" r=".51" fill="none" stroke="#000080" stroke-width=".21"/>
<path d="M246.4 84.7h7.7" fill="none" stroke="#000" stroke-width=".25"/>
<circle cx="246.4" cy="84.7" r=".51" fill="#000080"/>
<circle cx="246.4" cy="84.7" r=".51" fill="none" stroke="#000080" stroke-width=".21"/>
<path d="M246.4 82.1h7.7" fill="none" stroke="#000" stroke-width=".25"/>
<circle cx="246.4" cy="82.1" r=".51" fill="#000080"/>
<circle cx="246.4" cy="82.1" r=".51" fill="none" stroke="#000080" stroke-width=".21"/>
<path d="M246.4 79.6h7.7" fill="none" stroke="#000" stroke-width=".25"/>
<circle cx="246.4" cy="79.6" r=".51" fill="#000080"/>
<circle cx="246.4" cy="79.6" r=".51" fill="none" stroke="#000080" stroke-width=".21"/>
<path d="M246.4 77.1h7.7" fill="none" stroke="#000" stroke-width=".25"/>
<circle cx="246.4" cy="77.1" r=".51" fill="#000080"/>
<circle cx="246.4" cy="77.1" r=".51" fill="none" stroke="#000080" stroke-width=".21"/>
<path d="M246.4 74.5h7.7" fill="none" stroke="#000" stroke-width=".25"/>
<circle cx="246.4" cy="74.5" r=".51" fill="#000080"/>
<circle cx="246.4" cy="74.5" r=".51" fill="none" stroke="#000080" stroke-width=".21"/>
<path d="M246.4 72h7.7" fill="none" stroke="#000" stroke-width=".25"/>
<circle cx="246.4" cy="72" r=".51" fill="#000080"/>
<circle cx="246.4" cy="72" r=".51" fill="none" stroke="#000080" stroke-width=".21"/>
<path d="M246.4 69.4h7.7M246.4 64.3h7.7M101.4 138.1v2.6M101.4 145.7v2.6M198.1 166.1h4.4M203.8 166.1h4.5" fill="none" stroke="#000" stroke-width=".25"/>
<g fill="none" stroke="#800000" stroke-width=".25">
<path d="M238.8 69.4h5.1l-2.6 2.6zM241.3 66.9v2.5M98.9 150.8h5.1l-2.6 2.6zM101.4 148.3v2.5M212.1 161h2.5M213.4 161v2.6M243.9 168.6h5.1M244.6 169.4h3.6M245.4 170.2h2M246.2 170.9h.5M246.4 166.1v2.5M279.5 168.6h5.1"/>
<path d="M280.3 169.4h3.5M281 170.2h2.1M281.8 170.9h.5M282 166.1v2.5"/>
</g>
<path d="M99.4 143.7h4M99.4 142.7h4M101.4 140.7v2M101.4 143.7v2M203.2 164.8h1.2l-1.2 2.6h-1.3z" fill="none" stroke="#00f" stroke-width=".25"/>
<circle cx="162.5" cy="166.1" r=".51" fill="#000080"/>
<circle cx="162.5" cy="166.1" r=".51" fill="none" stroke="#000080" stroke-width=".21"/>
<path d="M162.5 166.1v2.5M162.5 173.7v2.6" fill="none" stroke="#000" stroke-width=".25"/>
<circle cx="162.5" cy="166.1" r=".51" fill="#000080"/>
<circle cx="162.5" cy="166.1" r=".51" fill="none" stroke="#000080" stroke-width=".21"/>
<path d="M160.5 171.7h4M160.5 170.7h4M162.5 168.6v2.1M162.5 171.7v2" fill="none" stroke="#00f" stroke-width=".25"/>
<path d="M159.9 178.8h5.1M160.7 179.6h3.6M162.5 176.3v2.5M161.5 180.4h2M162.2 181.1h.5" fill="none" stroke="#800000" stroke-width=".25"/>
<circle cx="175.2" cy="166.1" r=".51" fill="#000080"/>
<circle cx="175.2" cy="166.1" r=".51" fill="none" stroke="#000080" stroke-width=".21"/>
<path d="M175.2 166.1v2.5M175.2 173.7v2.6" fill="none" stroke="#000" stroke-width=".25"/>
<circle cx="175.2" cy="166.1" r=".51" fill="#000080"/>
<circle cx="175.2" cy="166.1" r=".51" fill="none" stroke="#000080" stroke-width=".21"/>
<path d="M173.2 171.7h4M173.2 170.7h4M175.2 168.6v2.1M175.2 171.7v2" fill="none" stroke="#00f" stroke-width=".25"/>
<path d="M172.7 178.8h5M173.4 179.6h3.6M175.2 176.3v2.5M174.2 180.4h2M174.9 181.1h.6" fill="none" stroke="#800000" stroke-width=".25"/>
<circle cx="96.3" cy="163.6" r=".51" fill="#000080"/>
<circle cx="96.3" cy="163.6" r=".51" fill="none" stroke="#000080" stroke-width=".21"/>
<path d="M96.3 163.6v2.5M96.3 171.2v2.5" fill="none" stroke="#000" stroke-width=".25"/>
<circle cx="96.3" cy="163.6" r=".51" fill="#000080"/>
<circle cx="96.3" cy="163.6" r=".51" fill="none" stroke="#000080" stroke-width=".21"/>
<path d="M94.3 169.1h4M94.3 168.1h4M96.3 166.1v2M96.3 169.1v2.1" fill="none" stroke="#00f" stroke-width=".25"/>
<path d="M93.8 176.3h5.1M94.6 177h3.5M95.3 177.8h2.1M96.1 178.6h.5M96.3 173.7v2.6" fill="none" stroke="#800000" stroke-width=".25"/>
<circle cx="83.6" cy="163.6" r=".51" fill="#000080"/>
<circle cx="83.6" cy="163.6" r=".51" fill="none" stroke="#000080" stroke-width=".21"/>
<path d="M83.6 163.6v2.5M83.6 171.2v2.5" fill="none" stroke="#000" stroke-width=".25"/>
<circle cx="83.6" cy="163.6" r=".51" fill="#000080"/>
<circle cx="83.6" cy="163.6" r=".51" fill="none" stroke="#000080" stroke-width=".21"/>
<path d="M81.6 169.1h4M81.6 168.1h4M83.6 166.1v2M83.6 169.1v2.1" fill="none" stroke="#00f" stroke-width=".25"/>
<path d="M81.1 176.3h5.1M81.8 177h3.6M82.6 177.8h2M83.4 178.6h.5M83.6 173.7v2.6" fill="none" stroke="#800000" stroke-width=".25"/>
<circle cx="187.9" cy="166.1" r=".51" fill="#000080"/>
<circle cx="187.9" cy="166.1" r=".51" fill="none" stroke="#000080" stroke-width=".21"/>
<path d="M187.9 166.1v2.5M187.9 173.7v2.6" fill="none" stroke="#000" stroke-width=".25"/>
<circle cx="187.9" cy="166.1" r=".51" fill="#000080"/>
<circle cx="187.9" cy="166.1" r=".51" fill="none" stroke="#000080" stroke-width=".21"/>
<path d="M185.9 171.7h4M185.9 170.7h4M187.9 168.6v2.1M187.9 171.7v2" fill="none" stroke="#00f" stroke-width=".25"/>
<path d="M185.4 178.8h5.1M186.1 179.6h3.6M187.9 176.3v2.5M186.9 180.4h2M187.7 181.1h.5" fill="none" stroke="#800000" stroke-width=".25"/>
<circle cx="70.9" cy="163.6" r=".51" fill="#000080"/>
<circle cx="70.9" cy="163.6" r=".51" fill="none" stroke="#000080" stroke-width=".21"/>
<path d="M70.9 163.6v2.5M70.9 171.2v2.5" fill="none" stroke="#000" stroke-width=".25"/>
<circle cx="70.9" cy="163.6" r=".51" fill="#000080"/>
<circle cx="70.9" cy="163.6" r=".51" fill="none" stroke="#000080" stroke-width=".21"/>
<path d="M68.9 169.1h4M68.9 168.1h4M70.9 166.1v2M70.9 169.1v2.1" fill="none" stroke="#00f" stroke-width=".25"/>
<path d="M68.3 176.3h5.1M69.1 177h3.6M69.9 177.8h2M70.6 178.6h.6M70.9 173.7v2.6" fill="none" stroke="#800000" stroke-width=".25"/>
<circle cx="83.6" cy="92.3" r=".51" fill="#000080"/>
<circle cx="83.6" cy="92.3" r=".51" fill="none" stroke="#000080" stroke-width=".21"/>
<path d="M83.6 92.3v2.6M83.6 100v2.5" fill="none" stroke="#000" stroke-width=".25"/>
<circle cx="83.6" cy="92.3" r=".51" fill="#000080"/>
<circle cx="83.6" cy="92.3" r=".51" fill="none" stroke="#000080" stroke-width=".21"/>
<path d="M81.6 97.9h4M81.6 96.9h4M83.6 94.9v2M83.6 97.9v2.1" fill="none" stroke="#00f" stroke-width=".25"/>
<circle cx="226.1" cy="92.3" r=".51" fill="#000080"/>
<circle cx="226.1" cy="92.3" r=".51" fill="none" stroke="#000080" stroke-width=".21"/>
<path d="M226.1 92.3v2.6M226.1 100v2.5" fill="none" stroke="#000" stroke-width=".25"/>
<circle cx="226.1" cy="92.3" r=".51" fill="#000080"/>
<circle cx="226.1" cy="92.3" r=".51" fill="none" stroke="#000080" stroke-width=".21"/>
<path d="M224.1 97.9h4M224.1 96.9h4M226.1 94.9v2M226.1 97.9v2.1" fill="none" stroke="#00f" stroke-width=".25"/>
<path d="M81.1 105h5.1M81.8 105.8h3.6M82.6 106.6h2M83.4 107.3h.5M83.6 102.5v2.5M223.5 105.1h5.1M224.3 105.8h3.6M225.1 106.6h2M225.8 107.3h.5M226.1 102.5v2.6" fill="none" stroke="#800000" stroke-width=".25"/>
<circle cx="162.5" cy="92.3" r=".51" fill="#000080"/>
<circle cx="162.5" cy="92.3" r=".51" fill="none" stroke="#000080" stroke-width=".21"/>
<path d="M162.5 92.3v2.6M162.5 100v2.5" fill="none" stroke="#000" stroke-width=".25"/>
<circle cx="162.5" cy="92.3" r=".51" fill="#000080"/>
<circle cx="162.5" cy="92.3" r=".51" fill="none" stroke="#000080" stroke-width=".21"/>
<path d="M160.5 97.9h4M160.5 96.9h4M162.5 94.9v2M162.5 97.9v2.1" fill="none" stroke="#00f" stroke-width=".25"/>
<path d="M159.9 105h5.1M160.7 105.8h3.6M161.5 106.6h2M162.2 107.3h.5M162.5 102.5v2.5" fill="none" stroke="#800000" stroke-width=".25"/>
<circle cx="175.2" cy="92.3" r=".51" fill="#000080"/>
<circle cx="175.2" cy="92.3" r=".51" fill="none" stroke="#000080" stroke-width=".21"/>
<path d="M175.2 92.3v2.6M175.2 100v2.5" fill="none" stroke="#000" stroke-width=".25"/>
<circle cx="175.2" cy="92.3" r=".51" fill="#000080"/>
<circle cx="175.2" cy="92.3" r=".51" fill="none" stroke="#000080" stroke-width=".21"/>
<path d="M173.2 97.9h4M173.2 96.9h4M175.2 94.9v2M175.2 97.9v2.1" fill="none" stroke="#00f" stroke-width=".25"/>
<path d="M172.7 105.1h5M173.4 105.8h3.6M174.2 106.6h2M174.9 107.3h.6M175.2 102.5v2.6" fill="none" stroke="#800000" stroke-width=".25"/>
<circle cx="187.9" cy="92.3" r=".51" fill="#000080"/>
<circle cx="187.9" cy="92.3" r=".51" fill="none" stroke="#000080" stroke-width=".21"/>
<path d="M187.9 92.3v2.6M187.9 100v2.5" fill="none" stroke="#000" stroke-width=".25"/>
<circle cx="187.9" cy="92.3" r=".51" fill="#000080"/>
<circle cx="187.9" cy="92.3" r=".51" fill="none" stroke="#000080" stroke-width=".21"/>
<path d="M185.9 97.9h4M185.9 96.9h4M187.9 94.9v2M187.9 97.9v2.1" fill="none" stroke="#00f" stroke-width=".25"/>
<path d="M185.4 105.1h5.1M186.1 105.8h3.6M186.9 106.6h2M187.7 107.3h.5M187.9 102.5v2.6" fill="none" stroke="#800000" stroke-width=".25"/>
<circle cx="200.6" cy="92.3" r=".51" fill="#000080"/>
<circle cx="200.6" cy="92.3" r=".51" fill="none" stroke="#000080" stroke-width=".21"/>
<path d="M200.6 92.3v2.6M200.6 100v2.5" fill="none" stroke="#000" stroke-width=".25"/>
<circle cx="200.6" cy="92.3" r=".51" fill="#000080"/>
<circle cx="200.6" cy="92.3" r=".51" fill="none" stroke="#000080" stroke-width=".21"/>
<path d="M198.6 97.9h4M198.6 96.9h4M200.6 94.9v2M200.6 97.9v2.1" fill="none" stroke="#00f" stroke-width=".25"/>
<path d="M198.1 105.1h5.1M198.9 105.8h3.5M199.6 106.6h2.1M200.4 107.3h.5M200.6 102.5v2.6" fill="none" stroke="#800000" stroke-width=".25"/>
<circle cx="213.4" cy="92.3" r=".51" fill="#000080"/>
<circle cx="213.4" cy="92.3" r=".51" fill="none" stroke="#000080" stroke-width=".21"/>
<path d="M213.4 92.3v2.6M213.4 100v2.5" fill="none" stroke="#000" stroke-width=".25"/>
<circle cx="213.4" cy="92.3" r=".51" fill="#000080"/>
<circle cx="213.4" cy="92.3" r=".51" fill="none" stroke="#000080" stroke-width=".21"/>
<path d="M211.3 97.9h4.1M211.3 96.9h4.1M213.4 94.9v2M213.4 97.9v2.1" fill="none" stroke="#00f" stroke-width=".25"/>
<path d="M210.8 105.1h5.1M211.6 105.8h3.5M212.3 106.6h2.1M213.1 107.3h.5M213.4 102.5v2.6" fill="none" stroke="#800000" stroke-width=".25"/>
<circle cx="96.3" cy="92.3" r=".51" fill="#000080"/>
<circle cx="96.3" cy="92.3" r=".51" fill="none" stroke="#000080" stroke-width=".21"/>
<path d="M96.3 92.3v2.6M96.3 100v2.5" fill="none" stroke="#000" stroke-width=".25"/>
<circle cx="96.3" cy="92.3" r=".51" fill="#000080"/>
<circle cx="96.3" cy="92.3" r=".51" fill="none" stroke="#000080" stroke-width=".21"/>
<path d="M94.3 97.9h4M94.3 96.9h4M96.3 94.9v2M96.3 97.9v2.1" fill="none" stroke="#00f" stroke-width=".25"/>
<path d="M93.8 105h5.1M94.6 105.8h3.5M95.3 106.6h2.1M96.1 107.3h.5M96.3 102.5v2.5" fill="none" stroke="#800000" stroke-width=".25"/>
<circle cx="20" cy="115.2" r=".51" fill="#000080"/>
<circle cx="20" cy="115.2" r=".51" fill="none" stroke="#000080" stroke-width=".21"/>
<path d="M20 115.2v2.6M20 122.9v2.5" fill="none" stroke="#000" stroke-width=".25"/>
<circle cx="20" cy="115.2" r=".51" fill="#000080"/>
<circle cx="20" cy="115.2" r=".51" fill="none" stroke="#000080" stroke-width=".21"/>
<path d="M18 119.8h4M20 117.8v2M18 120.8h4M20 120.8v2.1" fill="none" stroke="#00f" stroke-width=".25"/>
<path d="M17.5 127.9h5.1M18.2 128.7h3.6M19 129.5h2M19.8 130.2h.5M20 125.4v2.5" fill="none" stroke="#800000" stroke-width=".25"/>
<circle cx="58.2" cy="115.2" r=".51" fill="#000080"/>
<circle cx="58.2" cy="115.2" r=".51" fill="none" stroke="#000080" stroke-width=".21"/>
<path d="M58.2 115.2v2.6M58.2 122.9v2.5" fill="none" stroke="#000" stroke-width=".25"/>
<circle cx="58.2" cy="115.2" r=".51" fill="#000080"/>
<circle cx="58.2" cy="115.2" r=".51" fill="none" stroke="#000080" stroke-width=".21"/>
<path d="M56.2 119.8h4M58.2 117.8v2M56.2 120.8h4M58.2 120.8v2.1" fill="none" stroke="#00f" stroke-width=".25"/>
<path d="M55.6 127.9h5.1M56.4 128.7h3.6M57.2 129.5h2M57.9 130.2h.5M58.2 125.4v2.5" fill="none" stroke="#800000" stroke-width=".25"/>
<circle cx="70.9" cy="115.2" r=".51" fill="#000080"/>
<circle cx="70.9" cy="115.2" r=".51" fill="none" stroke="#000080" stroke-width=".21"/>
<path d="M70.9 115.2v2.6M70.9 122.9v2.5" fill="none" stroke="#000" stroke-width=".25"/>
<circle cx="70.9" cy="115.2" r=".51" fill="#000080"/>
<circle cx="70.9" cy="115.2" r=".51" fill="none" stroke="#000080" stroke-width=".21"/>
<path d="M68.9 119.8h4M70.9 117.8v2M68.9 120.8h4M70.9 120.8v2.1" fill="none" stroke="#00f" stroke-width=".25"/>
<path d="M68.3 127.9h5.1M69.1 128.7h3.6M69.9 129.5h2M70.6 130.2h.5M70.9 125.4v2.5" fill="none" stroke="#800000" stroke-width=".25"/>
<circle cx="83.6" cy="115.2" r=".51" fill="#000080"/>
<circle cx="83.6" cy="115.2" r=".51" fill="none" stroke="#000080" stroke-width=".21"/>
<path d="M83.6 115.2v2.6M83.6 122.9v2.5" fill="none" stroke="#000" stroke-width=".25"/>
<circle cx="83.6" cy="115.2" r=".51" fill="#000080"/>
<circle cx="83.6" cy="115.2" r=".51" fill="none" stroke="#000080" stroke-width=".21"/>
<path d="M81.6 119.8h4M83.6 117.8v2M81.6 120.8h4M83.6 120.8v2.1" fill="none" stroke="#00f" stroke-width=".25"/>
<path d="M81.1 127.9h5.1M81.8 128.7h3.6M82.6 129.5h2M83.4 130.2h.5M83.6 125.4v2.5" fill="none" stroke="#800000" stroke-width=".25"/>
<circle cx="32.7" cy="115.2" r=".51" fill="#000080"/>
<circle cx="32.7" cy="115.2" r=".51" fill="none" stroke="#000080" stroke-width=".21"/>
<path d="M32.7 115.2v2.6M32.7 122.9v2.5" fill="none" stroke="#000" stroke-width=".25"/>
<circle cx="32.7" cy="115.2" r=".51" fill="#000080"/>
<circle cx="32.7" cy="115.2" r=".51" fill="none" stroke="#000080" stroke-width=".21"/>
<path d="M30.7 119.8h4M32.7 117.8v2M30.7 120.8h4M32.7 120.8v2.1" fill="none" stroke="#00f" stroke-width=".25"/>
<path d="M30.2 127.9h5.1M31 128.7h3.5M31.7 129.5h2.1M32.5 130.2h.5M32.7 125.4v2.5" fill="none" stroke="#800000" stroke-width=".25"/>
<circle cx="45.5" cy="115.2" r=".51" fill="#000080"/>
<circle cx="45.5" cy="115.2" r=".51" fill="none" stroke="#000080" stroke-width=".21"/>
<path d="M45.5 115.2v2.6M45.5 122.9v2.5" fill="none" stroke="#000" stroke-width=".25"/>
<circle cx="45.5" cy="115.2" r=".51" fill="#000080"/>
<circle cx="45.5" cy="115.2" r=".51" fill="none" stroke="#000080" stroke-width=".21"/>
<path d="M160.5 69.9h4M160.5 68.9h4M162.5 66.9v2M162.5 69.9v2.1M43.4 119.8h4.1M45.5 117.8v2M43.4 120.8h4.1M45.5 120.8v2.1" fill="none" stroke="#00f" stroke-width=".25"/>
<path d="M159.9 77.1h5.1M160.7 77.8h3.6M161.5 78.6h2M162.2 79.3h.5M162.5 74.5v2.6M42.9 127.9h5.1M43.7 128.7h3.5M44.4 129.5h2.1M45.2 130.2h.5M45.5 125.4v2.5" fill="none" stroke="#800000" stroke-width=".25"/>
<path d="M162.5 64.3v2.6M162.5 72v2.5" fill="none" stroke="#000" stroke-width=".25"/>
<circle cx="20" cy="31.3" r=".51" fill="#000080"/>
<circle cx="20" cy="31.3" r=".51" fill="none" stroke="#000080" stroke-width=".21"/>
<path d="M20 31.3v2.5M20 38.9v2.5" fill="none" stroke="#000" stroke-width=".25"/>
<circle cx="20" cy="31.3" r=".51" fill="#000080"/>
<circle cx="20" cy="31.3" r=".51" fill="none" stroke="#000080" stroke-width=".21"/>
<path d="M18 36.9h4M18 35.9h4M20 33.8v2.1M20 36.9v2" fill="none" stroke="#00f" stroke-width=".25"/>
<path d="M17.5 44h5.1M18.2 44.8h3.6M19 45.5h2M19.8 46.3h.5M20 41.4v2.6" fill="none" stroke="#800000" stroke-width=".25"/>
<circle cx="70.9" cy="31.3" r=".51" fill="#000080"/>
<circle cx="70.9" cy="31.3" r=".51" fill="none" stroke="#000080" stroke-width=".21"/>
<path d="M70.9 31.3v2.5M70.9 38.9v2.5" fill="none" stroke="#000" stroke-width=".25"/>
<circle cx="70.9" cy="31.3" r=".51" fill="#000080"/>
<circle cx="70.9" cy="31.3" r=".51" fill="none" stroke="#000080" stroke-width=".21"/>
<path d="M68.9 36.9h4M68.9 35.9h4M70.9 33.8v2.1M70.9 36.9v2" fill="none" stroke="#00f" stroke-width=".25"/>
<path d="M68.3 44h5.1M69.1 44.8h3.6M69.9 45.5h2M70.6 46.3h.5M70.9 41.4v2.6" fill="none" stroke="#800000" stroke-width=".25"/>
<circle cx="83.6" cy="31.3" r=".51" fill="#000080"/>
<circle cx="83.6" cy="31.3" r=".51" fill="none" stroke="#000080" stroke-width=".21"/>
<path d="M83.6 31.3v2.5M83.6 38.9v2.5" fill="none" stroke="#000" stroke-width=".25"/>
<circle cx="83.6" cy="31.3" r=".51" fill="#000080"/>
<circle cx="83.6" cy="31.3" r=".51" fill="none" stroke="#000080" stroke-width=".21"/>
<path d="M81.6 36.9h4M81.6 35.9h4M83.6 33.8v2.1M83.6 36.9v2" fill="none" stroke="#00f" stroke-width=".25"/>
<path d="M81.1 44h5.1M81.8 44.8h3.6M82.6 45.5h2M83.4 46.3h.5M83.6 41.4v2.6" fill="none" stroke="#800000" stroke-width=".25"/>
<circle cx="96.3" cy="31.3" r=".51" fill="#000080"/>
<circle cx="96.3" cy="31.3" r=".51" fill="none" stroke="#000080" stroke-width=".21"/>
<path d="M96.3 31.3v2.5M96.3 38.9v2.5" fill="none" stroke="#000" stroke-width=".25"/>
<circle cx="96.3" cy="31.3" r=".51" fill="#000080"/>
<circle cx="96.3" cy="31.3" r=".51" fill="none" stroke="#000080" stroke-width=".21"/>
<path d="M94.3 36.9h4M94.3 35.9h4M96.3 33.8v2.1M96.3 36.9v2" fill="none" stroke="#00f" stroke-width=".25"/>
<path d="M93.8 44h5.1M94.6 44.8h3.5M95.3 45.5h2.1M96.1 46.3h.5M96.3 41.4v2.6" fill="none" stroke="#800000" stroke-width=".25"/>
<circle cx="58.2" cy="31.3" r=".51" fill="#000080"/>
<circle cx="58.2" cy="31.3" r=".51" fill="none" stroke="#000080" stroke-width=".21"/>
<path d="M58.2 31.3v2.5M58.2 38.9v2.5" fill="none" stroke="#000" stroke-width=".25"/>
<circle cx="58.2" cy="31.3" r=".51" fill="#000080"/>
<circle cx="58.2" cy="31.3" r=".51" fill="none" stroke="#000080" stroke-width=".21"/>
<path d="M56.2 36.9h4M56.2 35.9h4M58.2 33.8v2.1M58.2 36.9v2" fill="none" stroke="#00f" stroke-width=".25"/>
<path d="M55.6 44h5.1M56.4 44.8h3.6M57.2 45.5h2M57.9 46.3h.5M58.2 41.4v2.6" fill="none" stroke="#800000" stroke-width=".25"/>
<circle cx="45.5" cy="31.3" r=".51" fill="#000080"/>
<circle cx="45.5" cy="31.3" r=".51" fill="none" stroke="#000080" stroke-width=".21"/>
<path d="M45.5 31.3v2.5M45.5 38.9v2.5" fill="none" stroke="#000" stroke-width=".25"/>
<circle cx="45.5" cy="31.3" r=".51" fill="#000080"/>
<circle cx="45.5" cy="31.3" r=".51" fill="none" stroke="#000080" stroke-width=".21"/>
<path d="M43.4 36.9h4.1M43.4 35.9h4.1M45.5 33.8v2.1M45.5 36.9v2" fill="none" stroke="#00f" stroke-width=".25"/>
<path d="M42.9 44h5.1M43.7 44.8h3.5M44.4 45.5h2.1M45.2 46.3h.5M45.5 41.4v2.6" fill="none" stroke="#800000" stroke-width=".25"/>
<circle cx="32.7" cy="31.3" r=".51" fill="#000080"/>
<circle cx="32.7" cy="31.3" r=".51" fill="none" stroke="#000080" stroke-width=".21"/>
<path d="M32.7 31.3v2.5M32.7 38.9v2.5" fill="none" stroke="#000" stroke-width=".25"/>
<circle cx="32.7" cy="31.3" r=".51" fill="#000080"/>
<circle cx="32.7" cy="31.3" r=".51" fill="none" stroke="#000080" stroke-width=".21"/>
<path d="M30.7 36.9h4M30.7 35.9h4M32.7 33.8v2.1M32.7 36.9v2" fill="none" stroke="#00f" stroke-width=".25"/>
<path d="M30.2 44h5.1M31 44.8h3.5M31.7 45.5h2M32.5 46.3h.5M32.7 41.4v2.6" fill="none" stroke="#800000" stroke-width=".25"/>
<circle cx="20" cy="59.2" r=".51" fill="#000080"/>
<circle cx="20" cy="59.2" r=".51" fill="none" stroke="#000080" stroke-width=".21"/>
<path d="M20 59.3v2.5M20 66.9v2.5" fill="none" stroke="#000" stroke-width=".25"/>
<circle cx="20" cy="59.2" r=".51" fill="#000080"/>
<circle cx="20" cy="59.2" r=".51" fill="none" stroke="#000080" stroke-width=".21"/>
<path d="M18 64.8h4M18 63.8h4M20 61.8v2M20 64.8v2.1" fill="none" stroke="#00f" stroke-width=".25"/>
<path d="M17.5 72h5.1M18.2 72.7h3.6M19 73.5h2M19.8 74.3h.5M20 69.4v2.6" fill="none" stroke="#800000" stroke-width=".25"/>
<circle cx="70.9" cy="59.2" r=".51" fill="#000080"/>
<circle cx="70.9" cy="59.2" r=".51" fill="none" stroke="#000080" stroke-width=".21"/>
<path d="M70.9 59.3v2.5M70.9 66.9v2.5" fill="none" stroke="#000" stroke-width=".25"/>
<circle cx="70.9" cy="59.2" r=".51" fill="#000080"/>
<circle cx="70.9" cy="59.2" r=".51" fill="none" stroke="#000080" stroke-width=".21"/>
<path d="M68.9 64.8h4M68.9 63.8h4M70.9 61.8v2M70.9 64.8v2.1" fill="none" stroke="#00f" stroke-width=".25"/>
<path d="M68.3 72h5.1M69.1 72.7h3.6M69.9 73.5h2M70.6 74.3h.5M70.9 69.4v2.6" fill="none" stroke="#800000" stroke-width=".25"/>
<circle cx="83.6" cy="59.2" r=".51" fill="#000080"/>
<circle cx="83.6" cy="59.2" r=".51" fill="none" stroke="#000080" stroke-width=".21"/>
<path d="M83.6 59.3v2.5M83.6 66.9v2.5" fill="none" stroke="#000" stroke-width=".25"/>
<circle cx="83.6" cy="59.2" r=".51" fill="#000080"/>
<circle cx="83.6" cy="59.2" r=".51" fill="none" stroke="#000080" stroke-width=".21"/>
<path d="M81.6 64.8h4M81.6 63.8h4M83.6 61.8v2M83.6 64.8v2.1" fill="none" stroke="#00f" stroke-width=".25"/>
<path d="M81.1 72h5.1M81.8 72.7h3.6M82.6 73.5h2M83.4 74.3h.5M83.6 69.4v2.6" fill="none" stroke="#800000" stroke-width=".25"/>
<circle cx="96.3" cy="59.2" r=".51" fill="#000080"/>
<circle cx="96.3" cy="59.2" r=".51" fill="none" stroke="#000080" stroke-width=".21"/>
<path d="M96.3 59.3v2.5M96.3 66.9v2.5" fill="none" stroke="#000" stroke-width=".25"/>
<circle cx="96.3" cy="59.2" r=".51" fill="#000080"/>
<circle cx="96.3" cy="59.2" r=".51" fill="none" stroke="#000080" stroke-width=".21"/>
<path d="M94.3 64.8h4M94.3 63.8h4M96.3 61.8v2M96.3 64.8v2.1" fill="none" stroke="#00f" stroke-width=".25"/>
<path d="M93.8 72h5.1M94.6 72.7h3.5M95.3 73.5h2.1M96.1 74.3h.5M96.3 69.4v2.6" fill="none" stroke="#800000" stroke-width=".25"/>
<circle cx="58.2" cy="59.2" r=".51" fill="#000080"/>
<circle cx="58.2" cy="59.2" r=".51" fill="none" stroke="#000080" stroke-width=".21"/>
<path d="M58.2 59.3v2.5M58.2 66.9v2.5" fill="none" stroke="#000" stroke-width=".25"/>
<circle cx="58.2" cy="59.2" r=".51" fill="#000080"/>
<circle cx="58.2" cy="59.2" r=".51" fill="none" stroke="#000080" stroke-width=".21"/>
<path d="M56.2 64.8h4M56.2 63.8h4M58.2 61.8v2M58.2 64.8v2.1" fill="none" stroke="#00f" stroke-width=".25"/>
<path d="M55.6 72h5.1M56.4 72.7h3.6M57.2 73.5h2M57.9 74.3h.5M58.2 69.4v2.6" fill="none" stroke="#800000" stroke-width=".25"/>
<circle cx="45.5" cy="59.2" r=".51" fill="#000080"/>
<circle cx="45.5" cy="59.2" r=".51" fill="none" stroke="#000080" stroke-width=".21"/>
<path d="M45.5 59.3v2.5M45.5 66.9v2.5" fill="none" stroke="#000" stroke-width=".25"/>
<circle cx="45.5" cy="59.2" r=".51" fill="#000080"/>
<circle cx="45.5" cy="59.2" r=".51" fill="none" stroke="#000080" stroke-width=".21"/>
<path d="M43.4 64.8h4.1M43.4 63.8h4.1M45.5 61.8v2M45.5 64.8v2.1" fill="none" stroke="#00f" stroke-width=".25"/>
<path d="M42.9 72h5.1M43.7 72.7h3.5M44.4 73.5h2.1M45.2 74.3h.5M45.5 69.4v2.6" fill="none" stroke="#800000" stroke-width=".25"/>
<circle cx="32.7" cy="59.2" r=".51" fill="#000080"/>
<circle cx="32.7" cy="59.2" r=".51" fill="none" stroke="#000080" stroke-width=".21"/>
<path d="M32.7 59.3v2.5M32.7 66.9v2.5" fill="none" stroke="#000" stroke-width=".25"/>
<circle cx="32.7" cy="59.2" r=".51" fill="#000080"/>
<circle cx="32.7" cy="59.2" r=".51" fill="none" stroke="#000080" stroke-width=".21"/>
<path d="M30.7 64.8h4M30.7 63.8h4M32.7 61.8v2M32.7 64.8v2.1" fill="none" stroke="#00f" stroke-width=".25"/>
<path d="M30.2 72h5.1M31 72.7h3.5M31.7 73.5h2M32.5 74.3h.5M32.7 69.4v2.6" fill="none" stroke="#800000" stroke-width=".25"/>
<circle cx="187.9" cy="31.3" r=".51" fill="#000080"/>
<circle cx="187.9" cy="31.3" r=".51" fill="none" stroke="#000080" stroke-width=".21"/>
<path d="M187.9 31.3v2.5M187.9 38.9v2.5" fill="none" stroke="#000" stroke-width=".25"/>
<circle cx="187.9" cy="31.3" r=".51" fill="#000080"/>
<circle cx="187.9" cy="31.3" r=".51" fill="none" stroke="#000080" stroke-width=".21"/>
<path d="M185.9 36.9h4M185.9 35.9h4M187.9 33.8v2.1M187.9 36.9v2" fill="none" stroke="#00f" stroke-width=".25"/>
<path d="M185.4 44h5.1M186.1 44.8h3.6M186.9 45.5h2M187.7 46.3h.5M187.9 41.4v2.6" fill="none" stroke="#800000" stroke-width=".25"/>
<circle cx="175.2" cy="31.3" r=".51" fill="#000080"/>
<circle cx="175.2" cy="31.3" r=".51" fill="none" stroke="#000080" stroke-width=".21"/>
<path d="M175.2 31.3v2.5M175.2 38.9v2.5" fill="none" stroke="#000" stroke-width=".25"/>
<circle cx="175.2" cy="31.3" r=".51" fill="#000080"/>
<circle cx="175.2" cy="31.3" r=".51" fill="none" stroke="#000080" stroke-width=".21"/>
<path d="M173.2 36.9h4M173.2 35.9h4M175.2 33.8v2.1M175.2 36.9v2" fill="none" stroke="#00f" stroke-width=".25"/>
<path d="M172.7 44h5M173.4 44.8h3.6M174.2 45.5h2M174.9 46.3h.6M175.2 41.4v2.6" fill="none" stroke="#800000" stroke-width=".25"/>
<circle cx="162.5" cy="31.3" r=".51" fill="#000080"/>
<circle cx="162.5" cy="31.3" r=".51" fill="none" stroke="#000080" stroke-width=".21"/>
<path d="M162.5 31.3v2.5M162.5 38.9v2.5" fill="none" stroke="#000" stroke-width=".25"/>
<circle cx="162.5" cy="31.3" r=".51" fill="#000080"/>
<circle cx="162.5" cy="31.3" r=".51" fill="none" stroke="#000080" stroke-width=".21"/>
<path d="M160.5 36.9h4M160.5 35.9h4M162.5 33.8v2.1M162.5 36.9v2" fill="none" stroke="#00f" stroke-width=".25"/>
<path d="M159.9 44h5.1M160.7 44.8h3.6M161.5 45.5h2M162.2 46.3h.5M162.5 41.4v2.6" fill="none" stroke="#800000" stroke-width=".25"/>
<circle cx="200.6" cy="31.3" r=".51" fill="#000080"/>
<circle cx="200.6" cy="31.3" r=".51" fill="none" stroke="#000080" stroke-width=".21"/>
<path d="M200.6 31.3v2.5M200.6 38.9v2.5" fill="none" stroke="#000" stroke-width=".25"/>
<circle cx="200.6" cy="31.3" r=".51" fill="#000080"/>
<circle cx="200.6" cy="31.3" r=".51" fill="none" stroke="#000080" stroke-width=".21"/>
<path d="M198.6 36.9h4M198.6 35.9h4M200.6 33.8v2.1M200.6 36.9v2" fill="none" stroke="#00f" stroke-width=".25"/>
<path d="M198.1 44h5.1M198.9 44.8h3.5M199.6 45.5h2.1M200.4 46.3h.5M200.6 41.4v2.6" fill="none" stroke="#800000" stroke-width=".25"/>
<circle cx="213.4" cy="31.3" r=".51" fill="#000080"/>
<circle cx="213.4" cy="31.3" r=".51" fill="none" stroke="#000080" stroke-width=".21"/>
<path d="M213.4 31.3v2.5M213.4 38.9v2.5" fill="none" stroke="#000" stroke-width=".25"/>
<circle cx="213.4" cy="31.3" r=".51" fill="#000080"/>
<circle cx="213.4" cy="31.3" r=".51" fill="none" stroke="#000080" stroke-width=".21"/>
<path d="M211.3 36.9h4.1M211.3 35.9h4.1M213.4 33.8v2.1M213.4 36.9v2" fill="none" stroke="#00f" stroke-width=".25"/>
<path d="M210.8 44h5.1M211.6 44.8h3.5M212.3 45.5h2.1M213.1 46.3h.5M213.4 41.4v2.6" fill="none" stroke="#800000" stroke-width=".25"/>
<circle cx="226.1" cy="31.3" r=".51" fill="#000080"/>
<circle cx="226.1" cy="31.3" r=".51" fill="none" stroke="#000080" stroke-width=".21"/>
<path d="M226.1 31.3v2.5M226.1 38.9v2.5" fill="none" stroke="#000" stroke-width=".25"/>
<circle cx="226.1" cy="31.3" r=".51" fill="#000080"/>
<circle cx="226.1" cy="31.3" r=".51" fill="none" stroke="#000080" stroke-width=".21"/>
<path d="M224.1 36.9h4M224.1 35.9h4M226.1 33.8v2.1M226.1 36.9v2" fill="none" stroke="#00f" stroke-width=".25"/>
<path d="M223.5 44h5.1M224.3 44.8h3.6M225.1 45.5h2M225.8 46.3h.5M226.1 41.4v2.6" fill="none" stroke="#800000" stroke-width=".25"/>
<path d="M14.9 28.7v2.6h94.2v12.7" fill="none" stroke="#000080" stroke-width=".25"/>
<circle cx="109.1" cy="41.4" r=".51" fill="#000080"/>
<circle cx="109.1" cy="41.4" r=".51" fill="none" stroke="#000080" stroke-width=".21"/>
<circle cx="109.1" cy="38.9" r=".51" fill="#000080"/>
<circle cx="109.1" cy="38.9" r=".51" fill="none" stroke="#000080" stroke-width=".21"/>
<circle cx="109.1" cy="36.4" r=".51" fill="#000080"/>
<circle cx="109.1" cy="36.4" r=".51" fill="none" stroke="#000080" stroke-width=".21"/>
<circle cx="109.1" cy="33.8" r=".51" fill="#000080"/>
<circle cx="109.1" cy="33.8" r=".51" fill="none" stroke="#000080" stroke-width=".21"/>
<circle cx="109.1" cy="31.3" r=".51" fill="#000080"/>
<circle cx="109.1" cy="31.3" r=".51" fill="none" stroke="#000080" stroke-width=".21"/>
<circle cx="96.3" cy="31.3" r=".51" fill="#000080"/>
<circle cx="96.3" cy="31.3" r=".51" fill="none" stroke="#000080" stroke-width=".21"/>
<circle cx="83.6" cy="31.3" r=".51" fill="#000080"/>
<circle cx="83.6" cy="31.3" r=".51" fill="none" stroke="#000080" stroke-width=".21"/>
<circle cx="70.9" cy="31.3" r=".51" fill="#000080"/>
<circle cx="70.9" cy="31.3" r=".51" fill="none" stroke="#000080" stroke-width=".21"/>
<circle cx="58.2" cy="31.3" r=".51" fill="#000080"/>
<circle cx="58.2" cy="31.3" r=".51" fill="none" stroke="#000080" stroke-width=".21"/>
<circle cx="45.5" cy="31.3" r=".51" fill="#000080"/>
<circle cx="45.5" cy="31.3" r=".51" fill="none" stroke="#000080" stroke-width=".21"/>
<circle cx="32.7" cy="31.3" r=".51" fill="#000080"/>
<circle cx="32.7" cy="31.3" r=".51" fill="none" stroke="#000080" stroke-width=".21"/>
<circle cx="20" cy="31.3" r=".51" fill="#000080"/>
<circle cx="20" cy="31.3" r=".51" fill="none" stroke="#000080" stroke-width=".21"/>
<path d="M14.9 56.7v2.6h94.2v5" fill="none" stroke="#000080" stroke-width=".25"/>
<circle cx="109.1" cy="61.8" r=".51" fill="#000080"/>
<circle cx="109.1" cy="61.8" r=".51" fill="none" stroke="#000080" stroke-width=".21"/>
<circle cx="109.1" cy="59.2" r=".51" fill="#000080"/>
<circle cx="109.1" cy="59.2" r=".51" fill="none" stroke="#000080" stroke-width=".21"/>
<circle cx="96.3" cy="59.2" r=".51" fill="#000080"/>
<circle cx="96.3" cy="59.2" r=".51" fill="none" stroke="#000080" stroke-width=".21"/>
<circle cx="83.6" cy="59.2" r=".51" fill="#000080"/>
<circle cx="83.6" cy="59.2" r=".51" fill="none" stroke="#000080" stroke-width=".21"/>
<circle cx="70.9" cy="59.2" r=".51" fill="#000080"/>
<circle cx="70.9" cy="59.2" r=".51" fill="none" stroke="#000080" stroke-width=".21"/>
<circle cx="58.2" cy="59.2" r=".51" fill="#000080"/>
<circle cx="58.2" cy="59.2" r=".51" fill="none" stroke="#000080" stroke-width=".21"/>
<circle cx="45.5" cy="59.2" r=".51" fill="#000080"/>
<circle cx="45.5" cy="59.2" r=".51" fill="none" stroke="#000080" stroke-width=".21"/>
<circle cx="32.7" cy="59.2" r=".51" fill="#000080"/>
<circle cx="32.7" cy="59.2" r=".51" fill="none" stroke="#000080" stroke-width=".21"/>
<circle cx="20" cy="59.2" r=".51" fill="#000080"/>
<circle cx="20" cy="59.2" r=".51" fill="none" stroke="#000080" stroke-width=".21"/>
<path d="M231.2 89.8v2.5h-78.9v43.3" fill="none" stroke="#000080" stroke-width=".25"/>
<circle cx="152.3" cy="133" r=".51" fill="#000080"/>
<circle cx="152.3" cy="133" r=".51" fill="none" stroke="#000080" stroke-width=".21"/>
<circle cx="152.3" cy="130.5" r=".51" fill="#000080"/>
<circle cx="152.3" cy="130.5" r=".51" fill="none" stroke="#000080" stroke-width=".21"/>
<circle cx="152.3" cy="127.9" r=".51" fill="#000080"/>
<circle cx="152.3" cy="127.9" r=".51" fill="none" stroke="#000080" stroke-width=".21"/>
<circle cx="152.3" cy="125.4" r=".51" fill="#000080"/>
<circle cx="152.3" cy="125.4" r=".51" fill="none" stroke="#000080" stroke-width=".21"/>
<circle cx="152.3" cy="122.8" r=".51" fill="#000080"/>
<circle cx="152.3" cy="122.8" r=".51" fill="none" stroke="#000080" stroke-width=".21"/>
<circle cx="152.3" cy="120.3" r=".51" fill="#000080"/>
<circle cx="152.3" cy="120.3" r=".51" fill="none" stroke="#000080" stroke-width=".21"/>
<circle cx="152.3" cy="117.8" r=".51" fill="#000080"/>
<circle cx="152.3" cy="117.8" r=".51" fill="none" stroke="#000080" stroke-width=".21"/>
<circle cx="152.3" cy="115.2" r=".51" fill="#000080"/>
<circle cx="152.3" cy="115.2" r=".51" fill="none" stroke="#000080" stroke-width=".21"/>
<circle cx="152.3" cy="112.7" r=".51" fill="#000080"/>
<circle cx="152.3" cy="112.7" r=".51" fill="none" stroke="#000080" stroke-width=".21"/>
<circle cx="152.3" cy="110.1" r=".51" fill="#000080"/>
<circle cx="152.3" cy="110.1" r=".51" fill="none" stroke="#000080" stroke-width=".21"/>
<circle cx="152.3" cy="107.6" r=".51" fill="#000080"/>
<circle cx="152.3" cy="107.6" r=".51" fill="none" stroke="#000080" stroke-width=".21"/>
<circle cx="152.3" cy="105" r=".51" fill="#000080"/>
<circle cx="152.3" cy="105" r=".51" fill="none" stroke="#000080" stroke-width=".21"/>
<circle cx="152.3" cy="102.5" r=".51" fill="#000080"/>
<circle cx="152.3" cy="102.5" r=".51" fill="none" stroke="#000080" stroke-width=".21"/>
<circle cx="152.3" cy="100" r=".51" fill="#000080"/>
<circle cx="152.3" cy="100" r=".51" fill="none" stroke="#000080" stroke-width=".21"/>
<circle cx="152.3" cy="97.4" r=".51" fill="#000080"/>
<circle cx="152.3" cy="97.4" r=".51" fill="none" stroke="#000080" stroke-width=".21"/>
<circle cx="152.3" cy="94.9" r=".51" fill="#000080"/>
<circle cx="152.3" cy="94.9" r=".51" fill="none" stroke="#000080" stroke-width=".21"/>
<circle cx="152.3" cy="92.3" r=".51" fill="#000080"/>
<circle cx="152.3" cy="92.3" r=".51" fill="none" stroke="#000080" stroke-width=".21"/>
<circle cx="162.5" cy="92.3" r=".51" fill="#000080"/>
<circle cx="162.5" cy="92.3" r=".51" fill="none" stroke="#000080" stroke-width=".21"/>
<circle cx="175.2" cy="92.3" r=".51" fill="#000080"/>
<circle cx="175.2" cy="92.3" r=".51" fill="none" stroke="#000080" stroke-width=".21"/>
<circle cx="187.9" cy="92.3" r=".51" fill="#000080"/>
<circle cx="187.9" cy="92.3" r=".51" fill="none" stroke="#000080" stroke-width=".21"/>
<circle cx="200.6" cy="92.3" r=".51" fill="#000080"/>
<circle cx="200.6" cy="92.3" r=".51" fill="none" stroke="#000080" stroke-width=".21"/>
<circle cx="213.4" cy="92.3" r=".51" fill="#000080"/>
<circle cx="213.4" cy="92.3" r=".51" fill="none" stroke="#000080" stroke-width=".21"/>
<circle cx="226.1" cy="92.3" r=".51" fill="#000080"/>
<circle cx="226.1" cy="92.3" r=".51" fill="none" stroke="#000080" stroke-width=".21"/>
<path d="M65.8 161v2.6h40.7v10.1" fill="none" stroke="#000080" stroke-width=".25"/>
<circle cx="70.9" cy="163.6" r=".51" fill="#000080"/>
<circle cx="70.9" cy="163.6" r=".51" fill="none" stroke="#000080" stroke-width=".21"/>
<circle cx="83.6" cy="163.6" r=".51" fill="#000080"/>
<circle cx="83.6" cy="163.6" r=".51" fill="none" stroke="#000080" stroke-width=".21"/>
<circle cx="96.3" cy="163.6" r=".51" fill="#000080"/>
<circle cx="96.3" cy="163.6" r=".51" fill="none" stroke="#000080" stroke-width=".21"/>
<circle cx="106.5" cy="163.6" r=".51" fill="#000080"/>
<circle cx="106.5" cy="163.6" r=".51" fill="none" stroke="#000080" stroke-width=".21"/>
<circle cx="106.5" cy="166.1" r=".51" fill="#000080"/>
<circle cx="106.5" cy="166.1" r=".51" fill="none" stroke="#000080" stroke-width=".21"/>
<circle cx="106.5" cy="168.6" r=".51" fill="#000080"/>
<circle cx="106.5" cy="168.6" r=".51" fill="none" stroke="#000080" stroke-width=".21"/>
<circle cx="106.5" cy="171.2" r=".51" fill="#000080"/>
<circle cx="106.5" cy="171.2" r=".51" fill="none" stroke="#000080" stroke-width=".21"/>
<path d="M193 163.6v2.5h-40.7v7.6" fill="none" stroke="#000080" stroke-width=".25"/>
<circle cx="152.3" cy="171.2" r=".51" fill="#000080"/>
<circle cx="152.3" cy="171.2" r=".51" fill="none" stroke="#000080" stroke-width=".21"/>
<circle cx="152.3" cy="168.6" r=".51" fill="#000080"/>
<circle cx="152.3" cy="168.6" r=".51" fill="none" stroke="#000080" stroke-width=".21"/>
<circle cx="152.3" cy="166.1" r=".51" fill="#000080"/>
<circle cx="152.3" cy="166.1" r=".51" fill="none" stroke="#000080" stroke-width=".21"/>
<circle cx="162.5" cy="166.1" r=".51" fill="#000080"/>
<circle cx="162.5" cy="166.1" r=".51" fill="none" stroke="#000080" stroke-width=".21"/>
<circle cx="175.2" cy="166.1" r=".51" fill="#000080"/>
<circle cx="175.2" cy="166.1" r=".51" fill="none" stroke="#000080" stroke-width=".21"/>
<circle cx="187.9" cy="166.1" r=".51" fill="#000080"/>
<circle cx="187.9" cy="166.1" r=".51" fill="none" stroke="#000080" stroke-width=".21"/>
<circle cx="193" cy="166.1" r=".51" fill="#000080"/>
<circle cx="193" cy="166.1" r=".51" fill="none" stroke="#000080" stroke-width=".21"/>
<path d="M246.4 69.4v96.7" fill="none" stroke="#000080" stroke-width=".25"/>
<circle cx="246.4" cy="72" r=".51" fill="#000080"/>
<circle cx="246.4" cy="72" r=".51" fill="none" stroke="#000080" stroke-width=".21"/>
<circle cx="246.4" cy="74.5" r=".51" fill="#000080"/>
<circle cx="246.4" cy="74.5" r=".51" fill="none" stroke="#000080" stroke-width=".21"/>
<circle cx="246.4" cy="77.1" r=".51" fill="#000080"/>
<circle cx="246.4" cy="77.1" r=".51" fill="none" stroke="#000080" stroke-width=".21"/>
<circle cx="246.4" cy="79.6" r=".51" fill="#000080"/>
<circle cx="246.4" cy="79.6" r=".51" fill="none" stroke="#000080" stroke-width=".21"/>
<circle cx="246.4" cy="82.1" r=".51" fill="#000080"/>
<circle cx="246.4" cy="82.1" r=".51" fill="none" stroke="#000080" stroke-width=".21"/>
<circle cx="246.4" cy="84.7" r=".51" fill="#000080"/>
<circle cx="246.4" cy="84.7" r=".51" fill="none" stroke="#000080" stroke-width=".21"/>
<circle cx="246.4" cy="87.2" r=".51" fill="#000080"/>
<circle cx="246.4" cy="87.2" r=".51" fill="none" stroke="#000080" stroke-width=".21"/>
<circle cx="246.4" cy="89.8" r=".51" fill="#000080"/>
<circle cx="246.4" cy="89.8" r=".51" fill="none" stroke="#000080" stroke-width=".21"/>
<circle cx="246.4" cy="92.3" r=".51" fill="#000080"/>
<circle cx="246.4" cy="92.3" r=".51" fill="none" stroke="#000080" stroke-width=".21"/>
<circle cx="246.4" cy="94.9" r=".51" fill="#000080"/>
<circle cx="246.4" cy="94.9" r=".51" fill="none" stroke="#000080" stroke-width=".21"/>
<circle cx="246.4" cy="97.4" r=".51" fill="#000080"/>
<circle cx="246.4" cy="97.4" r=".51" fill="none" stroke="#000080" stroke-width=".21"/>
<circle cx="246.4" cy="100" r=".51" fill="#000080"/>
<circle cx="246.4" cy="100" r=".51" fill="none" stroke="#000080" stroke-width=".21"/>
<circle cx="246.4" cy="102.5" r=".51" fill="#000080"/>
<circle cx="246.4" cy="102.5" r=".51" fill="none" stroke="#000080" stroke-width=".21"/>
<circle cx="246.4" cy="105" r=".51" fill="#000080"/>
<circle cx="246.4" cy="105" r=".51" fill="none" stroke="#000080" stroke-width=".21"/>
<circle cx="246.4" cy="107.6" r=".51" fill="#000080"/>
<circle cx="246.4" cy="107.6" r=".51" fill="none" stroke="#000080" stroke-width=".21"/>
<circle cx="246.4" cy="110.1" r=".51" fill="#000080"/>
<circle cx="246.4" cy="110.1" r=".51" fill="none" stroke="#000080" stroke-width=".21"/>
<circle cx="246.4" cy="112.7" r=".51" fill="#000080"/>
<circle cx="246.4" cy="112.7" r=".51" fill="none" stroke="#000080" stroke-width=".21"/>
<circle cx="246.4" cy="115.2" r=".51" fill="#000080"/>
<circle cx="246.4" cy="115.2" r=".51" fill="none" stroke="#000080" stroke-width=".21"/>
<circle cx="246.4" cy="117.8" r=".51" fill="#000080"/>
<circle cx="246.4" cy="117.8" r=".51" fill="none" stroke="#000080" stroke-width=".21"/>
<circle cx="246.4" cy="120.3" r=".51" fill="#000080"/>
<circle cx="246.4" cy="120.3" r=".51" fill="none" stroke="#000080" stroke-width=".21"/>
<circle cx="246.4" cy="122.8" r=".51" fill="#000080"/>
<circle cx="246.4" cy="122.8" r=".51" fill="none" stroke="#000080" stroke-width=".21"/>
<circle cx="246.4" cy="125.4" r=".51" fill="#000080"/>
<circle cx="246.4" cy="125.4" r=".51" fill="none" stroke="#000080" stroke-width=".21"/>
<circle cx="246.4" cy="127.9" r=".51" fill="#000080"/>
<circle cx="246.4" cy="127.9" r=".51" fill="none" stroke="#000080" stroke-width=".21"/>
<circle cx="246.4" cy="130.5" r=".51" fill="#000080"/>
<circle cx="246.4" cy="130.5" r=".51" fill="none" stroke="#000080" stroke-width=".21"/>
<circle cx="246.4" cy="133" r=".51" fill="#000080"/>
<circle cx="246.4" cy="133" r=".51" fill="none" stroke="#000080" stroke-width=".21"/>
<circle cx="246.4" cy="135.6" r=".51" fill="#000080"/>
<circle cx="246.4" cy="135.6" r=".51" fill="none" stroke="#000080" stroke-width=".21"/>
<circle cx="246.4" cy="138.1" r=".51" fill="#000080"/>
<circle cx="246.4" cy="138.1" r=".51" fill="none" stroke="#000080" stroke-width=".21"/>
<circle cx="246.4" cy="140.7" r=".51" fill="#000080"/>
<circle cx="246.4" cy="140.7" r=".51" fill="none" stroke="#000080" stroke-width=".21"/>
<circle cx="246.4" cy="143.2" r=".51" fill="#000080"/>
<circle cx="246.4" cy="143.2" r=".51" fill="none" stroke="#000080" stroke-width=".21"/>
<circle cx="246.4" cy="145.8" r=".51" fill="#000080"/>
<circle cx="246.4" cy="145.8" r=".51" fill="none" stroke="#000080" stroke-width=".21"/>
<circle cx="246.4" cy="148.3" r=".51" fill="#000080"/>
<circle cx="246.4" cy="148.3" r=".51" fill="none" stroke="#000080" stroke-width=".21"/>
<circle cx="246.4" cy="150.8" r=".51" fill="#000080"/>
<circle cx="246.4" cy="150.8" r=".51" fill="none" stroke="#000080" stroke-width=".21"/>
<circle cx="246.4" cy="153.4" r=".51" fill="#000080"/>
<circle cx="246.4" cy="153.4" r=".51" fill="none" stroke="#000080" stroke-width=".21"/>
<circle cx="246.4" cy="155.9" r=".51" fill="#000080"/>
<circle cx="246.4" cy="155.9" r=".51" fill="none" stroke="#000080" stroke-width=".21"/>
<circle cx="246.4" cy="158.5" r=".51" fill="#000080"/>
<circle cx="246.4" cy="158.5" r=".51" fill="none" stroke="#000080" stroke-width=".21"/>
<circle cx="246.4" cy="161" r=".51" fill="#000080"/>
<circle cx="246.4" cy="161" r=".51" fill="none" stroke="#000080" stroke-width=".21"/>
<path d="M282 66.9v99.2" fill="none" stroke="#000080" stroke-width=".25"/>
<circle cx="282" cy="69.4" r=".51" fill="#000080"/>
<circle cx="282" cy="69.4" r=".51" fill="none" stroke="#000080" stroke-width=".21"/>
<circle cx="282" cy="72" r=".51" fill="#000080"/>
<circle cx="282" cy="72" r=".51" fill="none" stroke="#000080" stroke-width=".21"/>
<circle cx="282" cy="74.5" r=".51" fill="#000080"/>
<circle cx="282" cy="74.5" r=".51" fill="none" stroke="#000080" stroke-width=".21"/>
<circle cx="282" cy="77.1" r=".51" fill="#000080"/>
<circle cx="282" cy="77.1" r=".51" fill="none" stroke="#000080" stroke-width=".21"/>
<circle cx="282" cy="79.6" r=".51" fill="#000080"/>
<circle cx="282" cy="79.6" r=".51" fill="none" stroke="#000080" stroke-width=".21"/>
<circle cx="282" cy="82.1" r=".51" fill="#000080"/>
<circle cx="282" cy="82.1" r=".51" fill="none" stroke="#000080" stroke-width=".21"/>
<circle cx="282" cy="84.7" r=".51" fill="#000080"/>
<circle cx="282" cy="84.7" r=".51" fill="none" stroke="#000080" stroke-width=".21"/>
<circle cx="282" cy="87.2" r=".51" fill="#000080"/>
<circle cx="282" cy="87.2" r=".51" fill="none" stroke="#000080" stroke-width=".21"/>
<circle cx="282" cy="89.8" r=".51" fill="#000080"/>
<circle cx="282" cy="89.8" r=".51" fill="none" stroke="#000080" stroke-width=".21"/>
<circle cx="282" cy="92.3" r=".51" fill="#000080"/>
<circle cx="282" cy="92.3" r=".51" fill="none" stroke="#000080" stroke-width=".21"/>
<circle cx="282" cy="94.9" r=".51" fill="#000080"/>
<circle cx="282" cy="94.9" r=".51" fill="none" stroke="#000080" stroke-width=".21"/>
<circle cx="282" cy="97.4" r=".51" fill="#000080"/>
<circle cx="282" cy="97.4" r=".51" fill="none" stroke="#000080" stroke-width=".21"/>
<circle cx="282" cy="100" r=".51" fill="#000080"/>
<circle cx="282" cy="100" r=".51" fill="none" stroke="#000080" stroke-width=".21"/>
<circle cx="282" cy="102.5" r=".51" fill="#000080"/>
<circle cx="282" cy="102.5" r=".51" fill="none" stroke="#000080" stroke-width=".21"/>
<circle cx="282" cy="105" r=".51" fill="#000080"/>
<circle cx="282" cy="105" r=".51" fill="none" stroke="#000080" stroke-width=".21"/>
<circle cx="282" cy="107.6" r=".51" fill="#000080"/>
<circle cx="282" cy="107.6" r=".51" fill="none" stroke="#000080" stroke-width=".21"/>
<circle cx="282" cy="110.1" r=".51" fill="#000080"/>
<circle cx="282" cy="110.1" r=".51" fill="none" stroke="#000080" stroke-width=".21"/>
<circle cx="282" cy="112.7" r=".51" fill="#000080"/>
<circle cx="282" cy="112.7" r=".51" fill="none" stroke="#000080" stroke-width=".21"/>
<circle cx="282" cy="115.2" r=".51" fill="#000080"/>
<circle cx="282" cy="115.2" r=".51" fill="none" stroke="#000080" stroke-width=".21"/>
<circle cx="282" cy="117.8" r=".51" fill="#000080"/>
<circle cx="282" cy="117.8" r=".51" fill="none" stroke="#000080" stroke-width=".21"/>
<circle cx="282" cy="120.3" r=".51" fill="#000080"/>
<circle cx="282" cy="120.3" r=".51" fill="none" stroke="#000080" stroke-width=".21"/>
<circle cx="282" cy="122.8" r=".51" fill="#000080"/>
<circle cx="282" cy="122.8" r=".51" fill="none" stroke="#000080" stroke-width=".21"/>
<circle cx="282" cy="125.4" r=".51" fill="#000080"/>
<circle cx="282" cy="125.4" r=".51" fill="none" stroke="#000080" stroke-width=".21"/>
<circle cx="282" cy="127.9" r=".51" fill="#000080"/>
<circle cx="282" cy="127.9" r=".51" fill="none" stroke="#000080" stroke-width=".21"/>
<circle cx="282" cy="130.5" r=".51" fill="#000080"/>
<circle cx="282" cy="130.5" r=".51" fill="none" stroke="#000080" stroke-width=".21"/>
<circle cx="282" cy="133" r=".51" fill="#000080"/>
<circle cx="282" cy="133" r=".51" fill="none" stroke="#000080" stroke-width=".21"/>
<circle cx="282" cy="135.6" r=".51" fill="#000080"/>
<circle cx="282" cy="135.6" r=".51" fill="none" stroke="#000080" stroke-width=".21"/>
<circle cx="282" cy="138.1" r=".51" fill="#000080"/>
<circle cx="282" cy="138.1" r=".51" fill="none" stroke="#000080" stroke-width=".21"/>
<circle cx="282" cy="140.7" r=".51" fill="#000080"/>
<circle cx="282" cy="140.7" r=".51" fill="none" stroke="#000080" stroke-width=".21"/>
<circle cx="282" cy="143.2" r=".51" fill="#000080"/>
<circle cx="282" cy="143.2" r=".51" fill="none" stroke="#000080" stroke-width=".21"/>
<circle cx="282" cy="145.8" r=".51" fill="#000080"/>
<circle cx="282" cy="145.8" r=".51" fill="none" stroke="#000080" stroke-width=".21"/>
<circle cx="282" cy="148.3" r=".51" fill="#000080"/>
<circle cx="282" cy="148.3" r=".51" fill="none" stroke="#000080" stroke-width=".21"/>
<circle cx="282" cy="150.8" r=".51" fill="#000080"/>
<circle cx="282" cy="150.8" r=".51" fill="none" stroke="#000080" stroke-width=".21"/>
<circle cx="282" cy="153.4" r=".51" fill="#000080"/>
<circle cx="282" cy="153.4" r=".51" fill="none" stroke="#000080" stroke-width=".21"/>
<circle cx="282" cy="155.9" r=".51" fill="#000080"/>
<circle cx="282" cy="155.9" r=".51" fill="none" stroke="#000080" stroke-width=".21"/>
<circle cx="282" cy="158.5" r=".51" fill="#000080"/>
<circle cx="282" cy="158.5" r=".51" fill="none" stroke="#000080" stroke-width=".21"/>
<circle cx="282" cy="161" r=".51" fill="#000080"/>
<circle cx="282" cy="161" r=".51" fill="none" stroke="#000080" stroke-width=".21"/>
<path d="M246.4 64.3h-5.1v2.6M78.5 89.8v2.5h28v17.8" fill="none" stroke="#000080" stroke-width=".25"/>
<circle cx="106.5" cy="107.6" r=".51" fill="#000080"/>
<circle cx="106.5" cy="107.6" r=".51" fill="none" stroke="#000080" stroke-width=".21"/>
<circle cx="106.5" cy="105" r=".51" fill="#000080"/>
<circle cx="106.5" cy="105" r=".51" fill="none" stroke="#000080" stroke-width=".21"/>
<circle cx="96.3" cy="92.3" r=".51" fill="#000080"/>
<circle cx="96.3" cy="92.3" r=".51" fill="none" stroke="#000080" stroke-width=".21"/>
<circle cx="83.6" cy="92.3" r=".51" fill="#000080"/>
<circle cx="83.6" cy="92.3" r=".51" fill="none" stroke="#000080" stroke-width=".21"/>
<path d="M193 166.1h5.1M213.4 163.6v2.5h-5.1" fill="none" stroke="#000080" stroke-width=".25"/>
<circle cx="193" cy="166.1" r=".51" fill="#000080"/>
<circle cx="193" cy="166.1" r=".51" fill="none" stroke="#000080" stroke-width=".21"/>
<path d="M101.4 130.5v7.6" fill="none" stroke="#000080" stroke-width=".25"/>
<circle cx="101.4" cy="130.5" r=".51" fill="#000080"/>
<circle cx="101.4" cy="130.5" r=".51" fill="none" stroke="#000080" stroke-width=".21"/>
<path d="M101.4 115.2v2.6" fill="none" stroke="#000080" stroke-width=".25"/>
<circle cx="101.4" cy="115.2" r=".51" fill="#000080"/>
<circle cx="101.4" cy="115.2" r=".51" fill="none" stroke="#000080" stroke-width=".21"/>
<path d="M96.3 115.2v20.4h10.2" fill="none" stroke="#000080" stroke-width=".25"/>
<circle cx="96.3" cy="115.2" r=".51" fill="#000080"/>
<circle cx="96.3" cy="115.2" r=".51" fill="none" stroke="#000080" stroke-width=".21"/>
<path d="M101.4 127.9v2.6h5.1" fill="none" stroke="#000080" stroke-width=".25"/>
<circle cx="101.4" cy="130.5" r=".51" fill="#000080"/>
<circle cx="101.4" cy="130.5" r=".51" fill="none" stroke="#000080" stroke-width=".21"/>
<path d="M162.5 61.8v2.5" fill="none" stroke="#000080" stroke-width=".25"/>
<circle cx="162.5" cy="61.8" r=".51" fill="#000080"/>
<circle cx="162.5" cy="61.8" r=".51" fill="none" stroke="#000080" stroke-width=".21"/>
<path d="M109.1 49.1v10.2" fill="none" stroke="#000080" stroke-width=".25"/>
<circle cx="109.1" cy="59.2" r=".51" fill="#000080"/>
<circle cx="109.1" cy="59.2" r=".51" fill="none" stroke="#000080" stroke-width=".21"/>
<circle cx="109.1" cy="56.7" r=".51" fill="#000080"/>
<circle cx="109.1" cy="56.7" r=".51" fill="none" stroke="#000080" stroke-width=".21"/>
<circle cx="109.1" cy="54.2" r=".51" fill="#000080"/>
<circle cx="109.1" cy="54.2" r=".51" fill="none" stroke="#000080" stroke-width=".21"/>
<circle cx="109.1" cy="51.6" r=".51" fill="#000080"/>
<circle cx="109.1" cy="51.6" r=".51" fill="none" stroke="#000080" stroke-width=".21"/>
<path d="M231.2 28.7v2.6h-81.4v25.4" fill="none" stroke="#000080" stroke-width=".25"/>
<circle cx="149.8" cy="54.2" r=".51" fill="#000080"/>
<circle cx="149.8" cy="54.2" r=".51" fill="none" stroke="#000080" stroke-width=".21"/>
<circle cx="149.8" cy="51.6" r=".51" fill="#000080"/>
<circle cx="149.8" cy="51.6" r=".51" fill="none" stroke="#000080" stroke-width=".21"/>
<circle cx="149.8" cy="49.1" r=".51" fill="#000080"/>
<circle cx="149.8" cy="49.1" r=".51" fill="none" stroke="#000080" stroke-width=".21"/>
<circle cx="149.8" cy="46.5" r=".51" fill="#000080"/>
<circle cx="149.8" cy="46.5" r=".51" fill="none" stroke="#000080" stroke-width=".21"/>
<circle cx="149.8" cy="44" r=".51" fill="#000080"/>
<circle cx="149.8" cy="44" r=".51" fill="none" stroke="#000080" stroke-width=".21"/>
<circle cx="149.8" cy="41.4" r=".51" fill="#000080"/>
<circle cx="149.8" cy="41.4" r=".51" fill="none" stroke="#000080" stroke-width=".21"/>
<circle cx="162.5" cy="31.3" r=".51" fill="#000080"/>
<circle cx="162.5" cy="31.3" r=".51" fill="none" stroke="#000080" stroke-width=".21"/>
<circle cx="175.2" cy="31.3" r=".51" fill="#000080"/>
<circle cx="175.2" cy="31.3" r=".51" fill="none" stroke="#000080" stroke-width=".21"/>
<circle cx="187.9" cy="31.3" r=".51" fill="#000080"/>
<circle cx="187.9" cy="31.3" r=".51" fill="none" stroke="#000080" stroke-width=".21"/>
<circle cx="200.6" cy="31.3" r=".51" fill="#000080"/>
<circle cx="200.6" cy="31.3" r=".51" fill="none" stroke="#000080" stroke-width=".21"/>
<circle cx="213.4" cy="31.3" r=".51" fill="#000080"/>
<circle cx="213.4" cy="31.3" r=".51" fill="none" stroke="#000080" stroke-width=".21"/>
<circle cx="226.1" cy="31.3" r=".51" fill="#000080"/>
<circle cx="226.1" cy="31.3" r=".51" fill="none" stroke="#000080" stroke-width=".21"/>
<path d="M14.9 112.7v2.5h91.6v10.2" fill="none" stroke="#000080" stroke-width=".25"/>
<circle cx="106.5" cy="122.8" r=".51" fill="#000080"/>
<circle cx="106.5" cy="122.8" r=".51" fill="none" stroke="#000080" stroke-width=".21"/>
<circle cx="106.5" cy="120.3" r=".51" fill="#000080"/>
<circle cx="106.5" cy="120.3" r=".51" fill="none" stroke="#000080" stroke-width=".21"/>
<circle cx="106.5" cy="117.8" r=".51" fill="#000080"/>
<circle cx="106.5" cy="117.8" r=".51" fill="none" stroke="#000080" stroke-width=".21"/>
<circle cx="106.5" cy="115.2" r=".51" fill="#000080"/>
<circle cx="106.5" cy="115.2" r=".51" fill="none" stroke="#000080" stroke-width=".21"/>
<circle cx="101.4" cy="115.2" r=".51" fill="#000080"/>
<circle cx="101.4" cy="115.2" r=".51" fill="none" stroke="#000080" stroke-width=".21"/>
<circle cx="96.3" cy="115.2" r=".51" fill="#000080"/>
<circle cx="96.3" cy="115.2" r=".51" fill="none" stroke="#000080" stroke-width=".21"/>
<circle cx="83.6" cy="115.2" r=".51" fill="#000080"/>
<circle cx="83.6" cy="115.2" r=".51" fill="none" stroke="#000080" stroke-width=".21"/>
<circle cx="70.9" cy="115.2" r=".51" fill="#000080"/>
<circle cx="70.9" cy="115.2" r=".51" fill="none" stroke="#000080" stroke-width=".21"/>
<circle cx="58.2" cy="115.2" r=".51" fill="#000080"/>
<circle cx="58.2" cy="115.2" r=".51" fill="none" stroke="#000080" stroke-width=".21"/>
<circle cx="45.5" cy="115.2" r=".51" fill="#000080"/>
<circle cx="45.5" cy="115.2" r=".51" fill="none" stroke="#000080" stroke-width=".21"/>
<circle cx="32.7" cy="115.2" r=".51" fill="#000080"/>
<circle cx="32.7" cy="115.2" r=".51" fill="none" stroke="#000080" stroke-width=".21"/>
<circle cx="20" cy="115.2" r=".51" fill="#000080"/>
<circle cx="20" cy="115.2" r=".51" fill="none" stroke="#000080" stroke-width=".21"/>
<path d="M167.6 59.3v2.5h-17.8v2.5" fill="none" stroke="#000080" stroke-width=".25"/>
<circle cx="149.8" cy="61.8" r=".51" fill="#000080"/>
<circle cx="149.8" cy="61.8" r=".51" fill="none" stroke="#000080" stroke-width=".21"/>
<circle cx="162.5" cy="61.8" r=".51" fill="#000080"/>
<circle cx="162.5" cy="61.8" r=".51" fill="none" stroke="#000080" stroke-width=".21"/>
<use href="#words"/>
</svg>
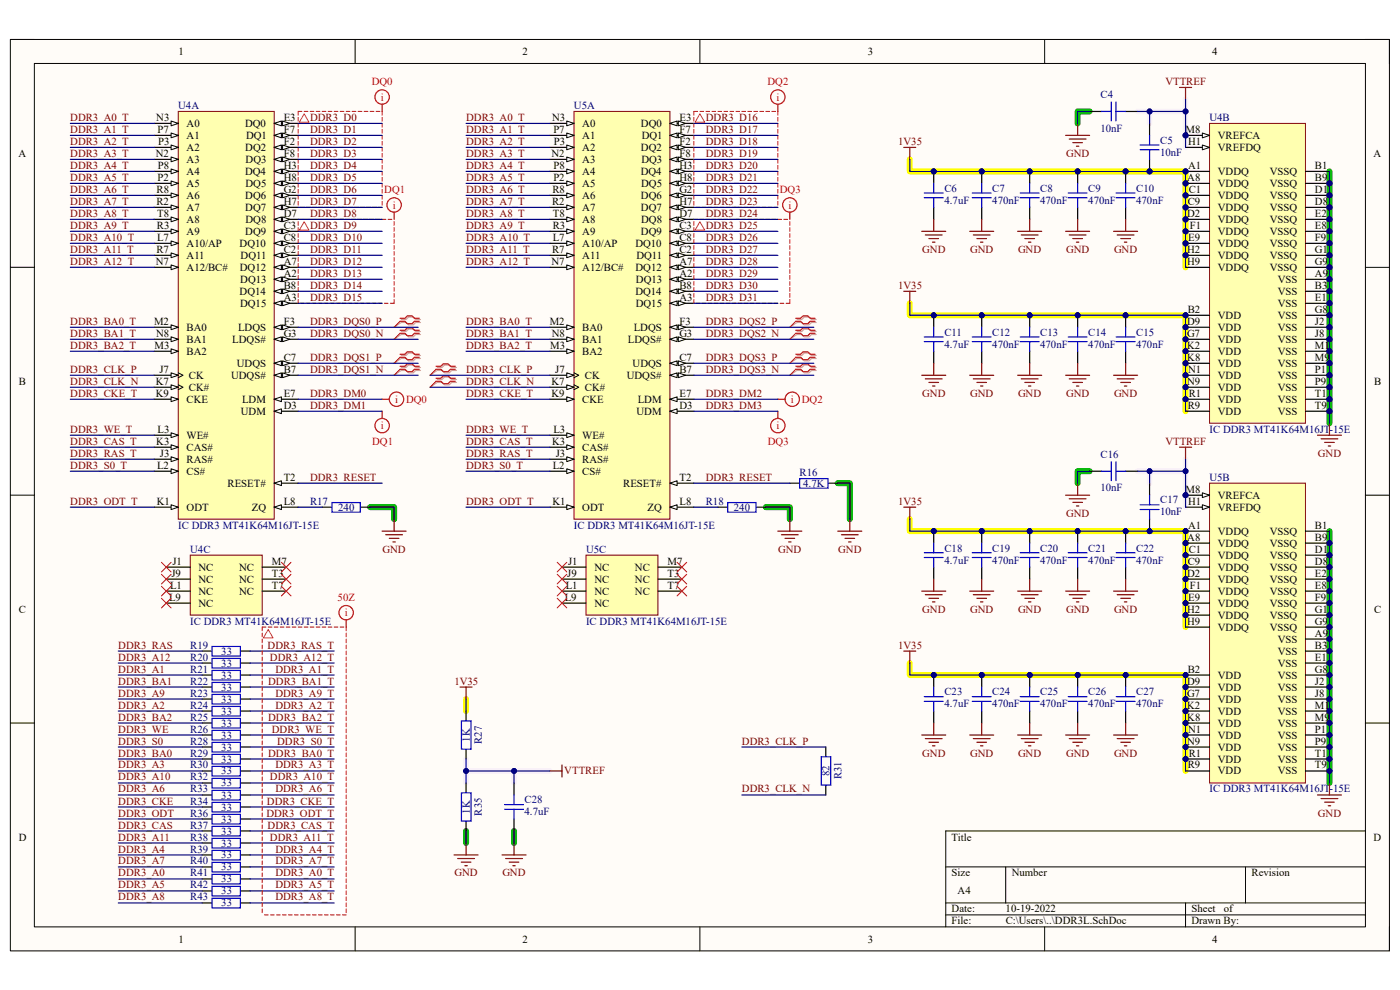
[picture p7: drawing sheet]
<svg xmlns="http://www.w3.org/2000/svg" width="297mm" height="210mm" viewBox="0 0 297 210" stroke-linecap="round" stroke-linejoin="round" font-family="sans-serif">
<defs><g id="words">
<g font-size="2.3">
<text x="37.9" y="11.7">1</text>
<text x="110.9" y="11.7">2</text>
<text x="184.1" y="11.7">3</text>
<text x="257.1" y="11.7">4</text>
<text x="33.1" y="25.7">N3</text>
<text x="33.4" y="28.2">P7</text>
<text x="39.6" y="26.9">A0</text>
<text x="39.6" y="29.5">A1</text>
<text x="52" y="26.9">DQ0</text>
<text x="52.2" y="29.5">DQ1</text>
<text x="60.2" y="25.7">E3</text>
<text x="60.2" y="28.2">F7</text>
<text x="117.1" y="25.7">N3</text>
<text x="117.4" y="28.2">P7</text>
<text x="123.5" y="26.9">A0</text>
<text x="123.5" y="29.5">A1</text>
<text x="136" y="26.9">DQ0</text>
<text x="136.1" y="29.5">DQ1</text>
<text x="144.1" y="25.7">E3</text>
<text x="144.1" y="28.2">F7</text>
<text x="251.5" y="28.2">M8</text>
<text x="258.4" y="29.5">VREFCA</text>
<text x="3.9" y="33.3">A</text>
<text x="33.1" y="33.3">N2</text>
<text x="33.5" y="35.9">P8</text>
<text x="33.5" y="30.7">P3</text>
<text x="39.6" y="34.6">A3</text>
<text x="39.6" y="32">A2</text>
<text x="52" y="32">DQ2</text>
<text x="52.1" y="34.6">DQ3</text>
<text x="60.2" y="30.7">F2</text>
<text x="60.2" y="33.3">F8</text>
<text x="60.2" y="35.9">H3</text>
<text x="117" y="33.3">N2</text>
<text x="117.4" y="35.9">P8</text>
<text x="117.5" y="30.7">P3</text>
<text x="123.5" y="34.6">A3</text>
<text x="123.5" y="32">A2</text>
<text x="136" y="32">DQ2</text>
<text x="136.1" y="34.6">DQ3</text>
<text x="144.1" y="30.7">F2</text>
<text x="144.1" y="33.3">F8</text>
<text x="144.1" y="35.9">H3</text>
<text x="252.1" y="35.9">A1</text>
<text x="252.1" y="30.7">H1</text>
<text x="258.4" y="32">VREFDQ</text>
<text x="279" y="35.9">B1</text>
<text x="291.4" y="33.3">A</text>
<text x="33.2" y="40.9">R8</text>
<text x="33.4" y="38.4">P2</text>
<text x="39.6" y="39.7">A5</text>
<text x="39.6" y="37.1">A4</text>
<text x="52" y="37.1">DQ4</text>
<text x="52.1" y="39.7">DQ5</text>
<text x="60.2" y="40.9">G2</text>
<text x="60.2" y="38.4">H8</text>
<text x="117.2" y="40.9">R8</text>
<text x="117.4" y="38.4">P2</text>
<text x="123.5" y="39.7">A5</text>
<text x="123.5" y="37.1">A4</text>
<text x="135.9" y="37.1">DQ4</text>
<text x="136" y="39.7">DQ5</text>
<text x="144.1" y="40.9">G2</text>
<text x="144.1" y="38.4">H8</text>
<text x="251.9" y="38.4">A8</text>
<text x="252.2" y="40.9">C1</text>
<text x="258.4" y="37.1">VDDQ</text>
<text x="258.4" y="39.7">VDDQ</text>
<text x="269.4" y="37.1">VSSQ</text>
<text x="269.4" y="39.7">VSSQ</text>
<text x="279" y="38.4">B9</text>
<text x="279" y="40.9">D1</text>
<text x="33.2" y="43.5">R2</text>
<text x="33.4" y="46">T8</text>
<text x="39.6" y="44.7">A7</text>
<text x="39.6" y="42.2">A6</text>
<text x="39.6" y="47.3">A8</text>
<text x="52" y="42.2">DQ6</text>
<text x="52" y="44.7">DQ7</text>
<text x="52.1" y="47.3">DQ8</text>
<text x="60.2" y="46">D7</text>
<text x="60.2" y="43.5">H7</text>
<text x="117.1" y="43.5">R2</text>
<text x="117.3" y="46">T8</text>
<text x="123.5" y="44.7">A7</text>
<text x="123.5" y="42.2">A6</text>
<text x="123.5" y="47.3">A8</text>
<text x="136" y="42.2">DQ6</text>
<text x="136" y="44.7">DQ7</text>
<text x="136" y="47.3">DQ8</text>
<text x="144.1" y="46">D7</text>
<text x="144.1" y="43.5">H7</text>
<text x="251.8" y="46">D2</text>
<text x="252" y="43.5">C9</text>
<text x="258.4" y="42.2">VDDQ</text>
<text x="258.4" y="44.7">VDDQ</text>
<text x="258.4" y="47.3">VDDQ</text>
<text x="269.4" y="42.2">VSSQ</text>
<text x="269.4" y="44.7">VSSQ</text>
<text x="269.4" y="47.3">VSSQ</text>
<text x="279" y="43.5">D8</text>
<text x="279" y="46">E2</text>
<text x="33.2" y="53.6">R7</text>
<text x="33.3" y="48.6">R3</text>
<text x="33.3" y="51.1">L7</text>
<text x="39.6" y="52.4">A10/AP</text>
<text x="39.6" y="49.8">A9</text>
<text x="50.8" y="52.4">DQ10</text>
<text x="52" y="49.8">DQ9</text>
<text x="60.2" y="53.6">C2</text>
<text x="60.2" y="48.6">C3</text>
<text x="60.2" y="51.1">C8</text>
<text x="117.1" y="53.6">R7</text>
<text x="117.3" y="51.1">L7</text>
<text x="117.3" y="48.6">R3</text>
<text x="123.5" y="52.4">A10/AP</text>
<text x="123.5" y="49.8">A9</text>
<text x="134.8" y="52.4">DQ10</text>
<text x="136" y="49.8">DQ9</text>
<text x="144.1" y="53.6">C2</text>
<text x="144.1" y="48.6">C3</text>
<text x="144.1" y="51.1">C8</text>
<text x="251.8" y="53.6">H2</text>
<text x="252.1" y="51.1">E9</text>
<text x="252.4" y="48.6">F1</text>
<text x="258.4" y="52.4">VDDQ</text>
<text x="258.4" y="49.8">VDDQ</text>
<text x="269.4" y="49.8">VSSQ</text>
<text x="269.4" y="52.4">VSSQ</text>
<text x="279" y="48.6">E8</text>
<text x="279" y="51.1">F9</text>
<text x="279" y="53.6">G1</text>
<text x="33.1" y="56.2">N7</text>
<text x="39.6" y="57.4">A12/BC#</text>
<text x="39.6" y="54.9">A11</text>
<text x="50.9" y="57.4">DQ12</text>
<text x="51" y="60">DQ13</text>
<text x="51.1" y="54.9">DQ11</text>
<text x="60.2" y="58.7">A2</text>
<text x="60.2" y="56.2">A7</text>
<text x="117" y="56.2">N7</text>
<text x="123.5" y="57.4">A12/BC#</text>
<text x="123.5" y="54.9">A11</text>
<text x="134.8" y="57.4">DQ12</text>
<text x="134.9" y="60">DQ13</text>
<text x="135" y="54.9">DQ11</text>
<text x="144.1" y="58.7">A2</text>
<text x="144.1" y="56.2">A7</text>
<text x="251.8" y="56.2">H9</text>
<text x="258.4" y="54.9">VDDQ</text>
<text x="258.4" y="57.4">VDDQ</text>
<text x="269.4" y="54.9">VSSQ</text>
<text x="269.4" y="57.4">VSSQ</text>
<text x="271.1" y="60">VSS</text>
<text x="279" y="58.7">A9</text>
<text x="279" y="56.2">G9</text>
<text x="50.8" y="62.6">DQ14</text>
<text x="50.9" y="65.1">DQ15</text>
<text x="60.2" y="63.8">A3</text>
<text x="60.2" y="61.3">B8</text>
<text x="134.8" y="62.6">DQ14</text>
<text x="134.9" y="65.1">DQ15</text>
<text x="144.1" y="63.8">A3</text>
<text x="144.1" y="61.3">B8</text>
<text x="271.1" y="62.6">VSS</text>
<text x="271.1" y="65.1">VSS</text>
<text x="279" y="61.3">B3</text>
<text x="279" y="63.8">E1</text>
<text x="32.7" y="68.9">M2</text>
<text x="33.1" y="71.5">N8</text>
<text x="39.6" y="70.2">BA0</text>
<text x="50.5" y="70.2">LDQS</text>
<text x="60.2" y="68.9">F3</text>
<text x="60.2" y="71.5">G3</text>
<text x="116.6" y="68.9">M2</text>
<text x="117.1" y="71.5">N8</text>
<text x="123.5" y="70.2">BA0</text>
<text x="134.5" y="70.2">LDQS</text>
<text x="144.1" y="68.9">F3</text>
<text x="144.1" y="71.5">G3</text>
<text x="251.8" y="68.9">D9</text>
<text x="251.8" y="71.5">G7</text>
<text x="252" y="66.4">B2</text>
<text x="258.4" y="67.6">VDD</text>
<text x="258.4" y="70.2">VDD</text>
<text x="271.1" y="67.6">VSS</text>
<text x="271.1" y="70.2">VSS</text>
<text x="279" y="66.4">G8</text>
<text x="279" y="68.9">J2</text>
<text x="279" y="71.5">J8</text>
<text x="32.8" y="74">M3</text>
<text x="39.6" y="75.3">BA2</text>
<text x="39.6" y="72.7">BA1</text>
<text x="49.3" y="72.7">LDQS#</text>
<text x="50.2" y="77.8">UDQS</text>
<text x="60.2" y="76.5">C7</text>
<text x="116.7" y="74">M3</text>
<text x="123.5" y="75.3">BA2</text>
<text x="123.5" y="72.7">BA1</text>
<text x="133.2" y="72.7">LDQS#</text>
<text x="134.2" y="77.8">UDQS</text>
<text x="144.1" y="76.5">C7</text>
<text x="251.8" y="74">K2</text>
<text x="251.9" y="76.5">K8</text>
<text x="258.4" y="72.7">VDD</text>
<text x="258.4" y="75.3">VDD</text>
<text x="258.4" y="77.8">VDD</text>
<text x="271.1" y="72.7">VSS</text>
<text x="271.1" y="75.3">VSS</text>
<text x="271.1" y="77.8">VSS</text>
<text x="279" y="74">M1</text>
<text x="279" y="76.5">M9</text>
<text x="4" y="81.6">B</text>
<text x="33.1" y="81.6">K7</text>
<text x="33.8" y="79.1">J7</text>
<text x="40.1" y="80.3">CK</text>
<text x="40.1" y="82.9">CK#</text>
<text x="49" y="80.3">UDQS#</text>
<text x="60.2" y="79.1">B7</text>
<text x="117" y="81.6">K7</text>
<text x="117.8" y="79.1">J7</text>
<text x="124.1" y="80.3">CK</text>
<text x="124.1" y="82.9">CK#</text>
<text x="133" y="80.3">UDQS#</text>
<text x="144.1" y="79.1">B7</text>
<text x="251.8" y="81.6">N9</text>
<text x="252.1" y="79.1">N1</text>
<text x="258.4" y="80.3">VDD</text>
<text x="258.4" y="82.9">VDD</text>
<text x="271.1" y="80.3">VSS</text>
<text x="271.1" y="82.9">VSS</text>
<text x="279" y="79.1">P1</text>
<text x="279" y="81.6">P9</text>
<text x="291.5" y="81.6">B</text>
<text x="33.1" y="84.2">K9</text>
<text x="39.6" y="85.4">CKE</text>
<text x="51.1" y="88">UDM</text>
<text x="51.4" y="85.4">LDM</text>
<text x="60.2" y="86.7">D3</text>
<text x="60.2" y="84.2">E7</text>
<text x="117" y="84.2">K9</text>
<text x="123.5" y="85.4">CKE</text>
<text x="135" y="88">UDM</text>
<text x="135.3" y="85.4">LDM</text>
<text x="144.1" y="86.7">D3</text>
<text x="144.1" y="84.2">E7</text>
<text x="252" y="86.7">R9</text>
<text x="252.2" y="84.2">R1</text>
<text x="258.4" y="85.4">VDD</text>
<text x="258.4" y="88">VDD</text>
<text x="271.1" y="85.4">VSS</text>
<text x="271.1" y="88">VSS</text>
<text x="279" y="84.2">T1</text>
<text x="279" y="86.7">T9</text>
<text x="33.1" y="94.4">K3</text>
<text x="33.4" y="91.8">L3</text>
<text x="39.6" y="95.6">CAS#</text>
<text x="39.6" y="93.1">WE#</text>
<text x="117.1" y="94.4">K3</text>
<text x="117.4" y="91.8">L3</text>
<text x="123.5" y="95.6">CAS#</text>
<text x="123.5" y="93.1">WE#</text>
<text x="33.3" y="99.4">L2</text>
<text x="33.9" y="96.9">J3</text>
<text x="39.6" y="98.2">RAS#</text>
<text x="39.6" y="100.7">CS#</text>
<text x="60.2" y="102">T2</text>
<text x="117.3" y="99.4">L2</text>
<text x="117.9" y="96.9">J3</text>
<text x="123.5" y="98.2">RAS#</text>
<text x="123.5" y="100.7">CS#</text>
<text x="144.1" y="102">T2</text>
<text x="33.3" y="107.1">K1</text>
<text x="48.3" y="103.3">RESET#</text>
<text x="60.2" y="107.1">L8</text>
<text x="117.2" y="107.1">K1</text>
<text x="132.2" y="103.3">RESET#</text>
<text x="144.1" y="107.1">L8</text>
<text x="251.5" y="104.5">M8</text>
<text x="252.1" y="107.1">H1</text>
<text x="258.4" y="105.8">VREFCA</text>
<text x="39.6" y="108.3">ODT</text>
<text x="53.4" y="108.3">ZQ</text>
<text x="123.5" y="108.3">ODT</text>
<text x="137.4" y="108.3">ZQ</text>
<text x="252.1" y="112.1">A1</text>
<text x="258.4" y="113.4">VDDQ</text>
<text x="258.4" y="108.3">VREFDQ</text>
<text x="269.4" y="113.4">VSSQ</text>
<text x="279" y="112.1">B1</text>
<text x="36.6" y="119.8">J1</text>
<text x="57.7" y="119.8">M7</text>
<text x="120.5" y="119.8">J1</text>
<text x="141.6" y="119.8">M7</text>
<text x="251.9" y="114.7">A8</text>
<text x="252" y="119.8">C9</text>
<text x="252.2" y="117.3">C1</text>
<text x="258.4" y="116">VDDQ</text>
<text x="258.4" y="118.5">VDDQ</text>
<text x="269.4" y="116">VSSQ</text>
<text x="269.4" y="118.5">VSSQ</text>
<text x="279" y="114.7">B9</text>
<text x="279" y="117.3">D1</text>
<text x="279" y="119.8">D8</text>
<text x="36.1" y="124.9">L1</text>
<text x="36.4" y="122.3">J9</text>
<text x="42.1" y="121.1">NC</text>
<text x="42.1" y="123.6">NC</text>
<text x="50.7" y="121.1">NC</text>
<text x="50.7" y="123.6">NC</text>
<text x="57.7" y="122.3">T3</text>
<text x="57.7" y="124.9">T7</text>
<text x="120" y="124.9">L1</text>
<text x="120.4" y="122.3">J9</text>
<text x="126.1" y="121.1">NC</text>
<text x="126.1" y="123.6">NC</text>
<text x="134.7" y="121.1">NC</text>
<text x="134.7" y="123.6">NC</text>
<text x="141.6" y="122.3">T3</text>
<text x="141.6" y="124.9">T7</text>
<text x="251.8" y="122.3">D2</text>
<text x="252.4" y="124.9">F1</text>
<text x="258.4" y="121.1">VDDQ</text>
<text x="258.4" y="123.6">VDDQ</text>
<text x="269.4" y="121.1">VSSQ</text>
<text x="269.4" y="123.6">VSSQ</text>
<text x="279" y="122.3">E2</text>
<text x="279" y="124.9">E8</text>
<text x="4" y="130">C</text>
<text x="35.9" y="127.4">L9</text>
<text x="42.1" y="126.2">NC</text>
<text x="42.1" y="128.7">NC</text>
<text x="50.7" y="126.2">NC</text>
<text x="119.8" y="127.4">L9</text>
<text x="126.1" y="126.2">NC</text>
<text x="126.1" y="128.7">NC</text>
<text x="134.7" y="126.2">NC</text>
<text x="251.8" y="130">H2</text>
<text x="252.1" y="127.4">E9</text>
<text x="258.4" y="128.7">VDDQ</text>
<text x="258.4" y="126.2">VDDQ</text>
<text x="258.4" y="131.2">VDDQ</text>
<text x="269.4" y="126.2">VSSQ</text>
<text x="269.4" y="128.7">VSSQ</text>
<text x="269.4" y="131.2">VSSQ</text>
<text x="279" y="127.4">F9</text>
<text x="279" y="130">G1</text>
<text x="291.5" y="130">C</text>
<text x="251.8" y="132.5">H9</text>
<text x="258.4" y="133.8">VDDQ</text>
<text x="269.4" y="133.8">VSSQ</text>
<text x="271.1" y="136.3">VSS</text>
<text x="279" y="135">A9</text>
<text x="279" y="137.6">B3</text>
<text x="279" y="132.5">G9</text>
<text x="252" y="142.7">B2</text>
<text x="258.4" y="144">VDD</text>
<text x="271.1" y="138.9">VSS</text>
<text x="271.1" y="141.4">VSS</text>
<text x="271.1" y="144">VSS</text>
<text x="279" y="140.1">E1</text>
<text x="279" y="142.7">G8</text>
<text x="251.8" y="145.2">D9</text>
<text x="251.8" y="147.8">G7</text>
<text x="258.4" y="146.5">VDD</text>
<text x="258.4" y="149.1">VDD</text>
<text x="271.1" y="146.5">VSS</text>
<text x="271.1" y="149.1">VSS</text>
<text x="279" y="145.2">J2</text>
<text x="279" y="147.8">J8</text>
<text x="251.8" y="150.3">K2</text>
<text x="251.9" y="152.9">K8</text>
<text x="252.1" y="155.4">N1</text>
<text x="258.4" y="151.6">VDD</text>
<text x="258.4" y="154.1">VDD</text>
<text x="271.1" y="151.6">VSS</text>
<text x="271.1" y="154.1">VSS</text>
<text x="279" y="150.3">M1</text>
<text x="279" y="152.9">M9</text>
<text x="279" y="155.4">P1</text>
<text x="251.8" y="157.9">N9</text>
<text x="252.2" y="160.5">R1</text>
<text x="258.4" y="156.7">VDD</text>
<text x="258.4" y="159.2">VDD</text>
<text x="258.4" y="161.8">VDD</text>
<text x="271.1" y="156.7">VSS</text>
<text x="271.1" y="159.2">VSS</text>
<text x="271.1" y="161.8">VSS</text>
<text x="279" y="157.9">P9</text>
<text x="279" y="160.5">T1</text>
<text x="252" y="163">R9</text>
<text x="258.4" y="164.3">VDD</text>
<text x="271.1" y="164.3">VSS</text>
<text x="279" y="163">T9</text>
<text x="4" y="178.3">D</text>
<text x="201.9" y="178.3">Title</text>
<text x="291.4" y="178.3">D</text>
<text x="201.9" y="185.9">Size</text>
<text x="214.6" y="185.9">Number</text>
<text x="265.5" y="185.9">Revision</text>
<text x="203.2" y="189.7">A4</text>
<text x="201.9" y="193.5">Date:</text>
<text x="201.9" y="196.1">File:</text>
<text x="213.3" y="193.5">10-19-2022</text>
<text x="213.4" y="196.1">C:\Users\..\DDR3L.SchDoc</text>
<text x="252.8" y="193.5">Sheet</text>
<text x="252.8" y="196.1">Drawn By:</text>
<text x="259.6" y="193.5">of</text>
<text x="37.9" y="199.9">1</text>
<text x="110.9" y="199.9">2</text>
<text x="184.1" y="199.9">3</text>
<text x="257.1" y="199.9">4</text>
</g>
<g font-size="2.3" fill="#000080">
<text x="37.8" y="23.1">U4A</text>
<text x="121.8" y="23.1">U5A</text>
<text x="233.5" y="20.9">C4</text>
<text x="233.5" y="27.9">10nF</text>
<text x="256.6" y="25.7">U4B</text>
<text x="246.1" y="30.5">C5</text>
<text x="246.1" y="33">10nF</text>
<text x="200.4" y="40.7">C6</text>
<text x="210.5" y="40.7">C7</text>
<text x="220.7" y="40.7">C8</text>
<text x="230.9" y="40.7">C9</text>
<text x="241" y="40.7">C10</text>
<text x="200.4" y="43.2">4.7uF</text>
<text x="210.5" y="43.2">470nF</text>
<text x="220.7" y="43.2">470nF</text>
<text x="230.9" y="43.2">470nF</text>
<text x="241" y="43.2">470nF</text>
<text x="200.4" y="71.2">C11</text>
<text x="210.5" y="71.2">C12</text>
<text x="220.7" y="71.2">C13</text>
<text x="230.9" y="71.2">C14</text>
<text x="241" y="71.2">C15</text>
<text x="200.4" y="73.7">4.7uF</text>
<text x="210.5" y="73.7">470nF</text>
<text x="220.7" y="73.7">470nF</text>
<text x="230.9" y="73.7">470nF</text>
<text x="241" y="73.7">470nF</text>
<text x="256.6" y="91.8">IC DDR3 MT41K64M16JT-15E</text>
<text x="169.6" y="101">R16</text>
<text x="233.5" y="97.2">C16</text>
<text x="256.6" y="102">U5B</text>
<text x="65.8" y="107.1">R17</text>
<text x="149.7" y="107.1">R18</text>
<text x="170.4" y="103.3">4.7K</text>
<text x="233.5" y="104.2">10nF</text>
<text x="246.1" y="106.8">C17</text>
<text x="37.8" y="112.1">IC DDR3 MT41K64M16JT-15E</text>
<text x="71.8" y="108.3">240</text>
<text x="121.8" y="112.1">IC DDR3 MT41K64M16JT-15E</text>
<text x="155.7" y="108.3">240</text>
<text x="246.1" y="109.3">10nF</text>
<text x="40.3" y="117.3">U4C</text>
<text x="124.3" y="117.3">U5C</text>
<text x="200.4" y="117">C18</text>
<text x="200.4" y="119.5">4.7uF</text>
<text x="210.5" y="117">C19</text>
<text x="210.5" y="119.5">470nF</text>
<text x="220.7" y="117">C20</text>
<text x="220.7" y="119.5">470nF</text>
<text x="230.9" y="117">C21</text>
<text x="230.9" y="119.5">470nF</text>
<text x="241" y="117">C22</text>
<text x="241" y="119.5">470nF</text>
<text x="40.3" y="132.5">IC DDR3 MT41K64M16JT-15E</text>
<text x="40.3" y="137.6">R19</text>
<text x="124.3" y="132.5">IC DDR3 MT41K64M16JT-15E</text>
<text x="40.3" y="140.1">R20</text>
<text x="40.3" y="142.7">R21</text>
<text x="46.9" y="138.9">33</text>
<text x="46.9" y="141.4">33</text>
<text x="46.9" y="144">33</text>
<text x="40.3" y="145.2">R22</text>
<text x="40.3" y="147.8">R23</text>
<text x="46.9" y="146.5">33</text>
<text x="46.9" y="149.1">33</text>
<text x="200.4" y="147.5">C23</text>
<text x="210.5" y="147.5">C24</text>
<text x="220.7" y="147.5">C25</text>
<text x="230.9" y="147.5">C26</text>
<text x="241" y="147.5">C27</text>
<text x="40.3" y="150.3">R24</text>
<text x="40.3" y="152.9">R25</text>
<text x="40.3" y="155.4">R26</text>
<text x="46.9" y="151.6">33</text>
<text x="46.9" y="154.1">33</text>
<text x="200.4" y="150.1">4.7uF</text>
<text x="210.5" y="150.1">470nF</text>
<text x="220.7" y="150.1">470nF</text>
<text x="230.9" y="150.1">470nF</text>
<text x="241" y="150.1">470nF</text>
<text x="40.3" y="157.9">R28</text>
<text x="40.3" y="160.5">R29</text>
<text x="46.9" y="156.7">33</text>
<text x="46.9" y="159.2">33</text>
<text x="46.9" y="161.8">33</text>
<text x="99.7" y="157.4" transform="rotate(-90 99.7 157.4)">1K</text>
<text x="102.2" y="157.8" transform="rotate(-90 102.2 157.8)">R27</text>
<text x="40.3" y="163">R30</text>
<text x="40.3" y="165.6">R32</text>
<text x="46.9" y="164.3">33</text>
<text x="46.9" y="166.8">33</text>
<text x="176" y="164.6" transform="rotate(-90 176 164.6)">82</text>
<text x="178.5" y="165.3" transform="rotate(-90 178.5 165.3)">R31</text>
<text x="40.3" y="168.1">R33</text>
<text x="40.3" y="170.7">R34</text>
<text x="40.3" y="173.2">R36</text>
<text x="46.9" y="169.4">33</text>
<text x="46.9" y="172">33</text>
<text x="99.7" y="172.6" transform="rotate(-90 99.7 172.6)">1K</text>
<text x="102.2" y="173" transform="rotate(-90 102.2 173)">R35</text>
<text x="111.3" y="170.4">C28</text>
<text x="111.3" y="173">4.7uF</text>
<text x="256.6" y="168.1">IC DDR3 MT41K64M16JT-15E</text>
<text x="40.3" y="175.8">R37</text>
<text x="40.3" y="178.3">R38</text>
<text x="46.9" y="174.5">33</text>
<text x="46.9" y="177">33</text>
<text x="46.9" y="179.6">33</text>
<text x="40.3" y="180.8">R39</text>
<text x="40.3" y="183.4">R40</text>
<text x="40.3" y="185.9">R41</text>
<text x="46.9" y="182.1">33</text>
<text x="46.9" y="184.7">33</text>
<text x="40.3" y="188.5">R42</text>
<text x="40.3" y="191">R43</text>
<text x="46.9" y="187.2">33</text>
<text x="46.9" y="189.7">33</text>
<text x="46.9" y="192.3">33</text>
</g>
<g font-size="2.3" fill="#f00">
<text x="78.9" y="18">DQ0</text>
<text x="80.8" y="21.3">i</text>
<text x="162.8" y="18">DQ2</text>
<text x="164.7" y="21.3">i</text>
<text x="81.5" y="40.9">DQ1</text>
<text x="165.4" y="40.9">DQ3</text>
<text x="83.3" y="44.2">i</text>
<text x="167.3" y="44.2">i</text>
<text x="83.8" y="85.4">i</text>
<text x="86.2" y="85.4">DQ0</text>
<text x="167.8" y="85.4">i</text>
<text x="170.1" y="85.4">DQ2</text>
<text x="79" y="94.4">DQ1</text>
<text x="80.8" y="91.1">i</text>
<text x="162.9" y="94.4">DQ3</text>
<text x="164.7" y="91.1">i</text>
<text x="71.6" y="127.4">50Z</text>
<text x="73.2" y="130.7">i</text>
</g>
<g font-size="2.3" fill="#800000">
<text x="247.2" y="18">VTTREF</text>
<text x="14.9" y="25.7">DDR3_A0_T</text>
<text x="14.9" y="28.2">DDR3_A1_T</text>
<text x="65.8" y="25.7">DDR3_D0</text>
<text x="65.8" y="28.2">DDR3_D1</text>
<text x="98.9" y="25.7">DDR3_A0_T</text>
<text x="98.9" y="28.2">DDR3_A1_T</text>
<text x="149.7" y="25.7">DDR3_D16</text>
<text x="149.7" y="28.2">DDR3_D17</text>
<text x="14.9" y="30.7">DDR3_A2_T</text>
<text x="14.9" y="33.3">DDR3_A3_T</text>
<text x="14.9" y="35.9">DDR3_A4_T</text>
<text x="65.8" y="30.7">DDR3_D2</text>
<text x="65.8" y="33.3">DDR3_D3</text>
<text x="65.8" y="35.9">DDR3_D4</text>
<text x="98.9" y="30.7">DDR3_A2_T</text>
<text x="98.9" y="33.3">DDR3_A3_T</text>
<text x="98.9" y="35.9">DDR3_A4_T</text>
<text x="149.7" y="30.7">DDR3_D18</text>
<text x="149.7" y="33.3">DDR3_D19</text>
<text x="149.7" y="35.9">DDR3_D20</text>
<text x="190.5" y="30.7">1V35</text>
<text x="226.2" y="33.3">GND</text>
<text x="14.9" y="38.4">DDR3_A5_T</text>
<text x="14.9" y="40.9">DDR3_A6_T</text>
<text x="65.8" y="38.4">DDR3_D5</text>
<text x="65.8" y="40.9">DDR3_D6</text>
<text x="98.9" y="38.4">DDR3_A5_T</text>
<text x="98.9" y="40.9">DDR3_A6_T</text>
<text x="149.7" y="38.4">DDR3_D21</text>
<text x="149.7" y="40.9">DDR3_D22</text>
<text x="14.9" y="43.5">DDR3_A7_T</text>
<text x="14.9" y="46">DDR3_A8_T</text>
<text x="65.8" y="43.5">DDR3_D7</text>
<text x="65.8" y="46">DDR3_D8</text>
<text x="98.9" y="43.5">DDR3_A7_T</text>
<text x="98.9" y="46">DDR3_A8_T</text>
<text x="149.7" y="43.5">DDR3_D23</text>
<text x="149.7" y="46">DDR3_D24</text>
<text x="14.9" y="48.6">DDR3_A9_T</text>
<text x="14.9" y="51.1">DDR3_A10_T</text>
<text x="14.9" y="53.6">DDR3_A11_T</text>
<text x="65.8" y="48.6">DDR3_D9</text>
<text x="65.8" y="51.1">DDR3_D10</text>
<text x="65.8" y="53.6">DDR3_D11</text>
<text x="98.9" y="48.6">DDR3_A9_T</text>
<text x="98.9" y="51.1">DDR3_A10_T</text>
<text x="98.9" y="53.6">DDR3_A11_T</text>
<text x="149.7" y="48.6">DDR3_D25</text>
<text x="149.7" y="51.1">DDR3_D26</text>
<text x="149.7" y="53.6">DDR3_D27</text>
<text x="195.7" y="53.6">GND</text>
<text x="205.8" y="53.6">GND</text>
<text x="216" y="53.6">GND</text>
<text x="226.2" y="53.6">GND</text>
<text x="236.3" y="53.6">GND</text>
<text x="14.9" y="56.2">DDR3_A12_T</text>
<text x="65.8" y="56.2">DDR3_D12</text>
<text x="65.8" y="58.7">DDR3_D13</text>
<text x="98.9" y="56.2">DDR3_A12_T</text>
<text x="149.7" y="56.2">DDR3_D28</text>
<text x="149.7" y="58.7">DDR3_D29</text>
<text x="65.8" y="61.3">DDR3_D14</text>
<text x="65.8" y="63.8">DDR3_D15</text>
<text x="149.7" y="61.3">DDR3_D30</text>
<text x="149.7" y="63.8">DDR3_D31</text>
<text x="190.5" y="61.3">1V35</text>
<text x="14.9" y="68.9">DDR3_BA0_T</text>
<text x="14.9" y="71.5">DDR3_BA1_T</text>
<text x="65.8" y="68.9">DDR3_DQS0_P</text>
<text x="65.8" y="71.5">DDR3_DQS0_N</text>
<text x="98.9" y="68.9">DDR3_BA0_T</text>
<text x="98.9" y="71.5">DDR3_BA1_T</text>
<text x="149.7" y="68.9">DDR3_DQS2_P</text>
<text x="149.7" y="71.5">DDR3_DQS2_N</text>
<text x="14.9" y="74">DDR3_BA2_T</text>
<text x="65.8" y="76.5">DDR3_DQS1_P</text>
<text x="98.9" y="74">DDR3_BA2_T</text>
<text x="149.7" y="76.5">DDR3_DQS3_P</text>
<text x="14.9" y="79.1">DDR3_CLK_P</text>
<text x="14.9" y="81.6">DDR3_CLK_N</text>
<text x="65.8" y="79.1">DDR3_DQS1_N</text>
<text x="98.9" y="79.1">DDR3_CLK_P</text>
<text x="98.9" y="81.6">DDR3_CLK_N</text>
<text x="149.7" y="79.1">DDR3_DQS3_N</text>
<text x="14.9" y="84.2">DDR3_CKE_T</text>
<text x="65.8" y="84.2">DDR3_DM0</text>
<text x="65.8" y="86.7">DDR3_DM1</text>
<text x="98.9" y="84.2">DDR3_CKE_T</text>
<text x="149.7" y="84.2">DDR3_DM2</text>
<text x="149.7" y="86.7">DDR3_DM3</text>
<text x="195.7" y="84.2">GND</text>
<text x="205.8" y="84.2">GND</text>
<text x="216" y="84.2">GND</text>
<text x="226.2" y="84.2">GND</text>
<text x="236.3" y="84.2">GND</text>
<text x="14.9" y="91.8">DDR3_WE_T</text>
<text x="14.9" y="94.4">DDR3_CAS_T</text>
<text x="98.9" y="91.8">DDR3_WE_T</text>
<text x="98.9" y="94.4">DDR3_CAS_T</text>
<text x="247.2" y="94.4">VTTREF</text>
<text x="14.9" y="96.9">DDR3_RAS_T</text>
<text x="14.9" y="99.4">DDR3_S0_T</text>
<text x="65.8" y="102">DDR3_RESET</text>
<text x="98.9" y="96.9">DDR3_RAS_T</text>
<text x="98.9" y="99.4">DDR3_S0_T</text>
<text x="149.7" y="102">DDR3_RESET</text>
<text x="279.6" y="96.9">GND</text>
<text x="14.9" y="107.1">DDR3_ODT_T</text>
<text x="98.9" y="107.1">DDR3_ODT_T</text>
<text x="190.5" y="107.1">1V35</text>
<text x="226.2" y="109.6">GND</text>
<text x="81.2" y="117.3">GND</text>
<text x="165.1" y="117.3">GND</text>
<text x="177.8" y="117.3">GND</text>
<text x="195.7" y="130">GND</text>
<text x="205.8" y="130">GND</text>
<text x="216" y="130">GND</text>
<text x="226.2" y="130">GND</text>
<text x="236.3" y="130">GND</text>
<text x="25.1" y="137.6">DDR3_RAS</text>
<text x="56.8" y="137.6">DDR3_RAS_T</text>
<text x="190.5" y="137.6">1V35</text>
<text x="25.1" y="140.1">DDR3_A12</text>
<text x="25.1" y="142.7">DDR3_A1</text>
<text x="57.3" y="140.1">DDR3_A12_T</text>
<text x="58.4" y="142.7">DDR3_A1_T</text>
<text x="25.1" y="147.8">DDR3_A9</text>
<text x="25.1" y="145.2">DDR3_BA1</text>
<text x="56.9" y="145.2">DDR3_BA1_T</text>
<text x="58.4" y="147.8">DDR3_A9_T</text>
<text x="96.4" y="145.2">1V35</text>
<text x="25.1" y="155.4">DDR3_WE</text>
<text x="25.1" y="150.3">DDR3_A2</text>
<text x="25.1" y="152.9">DDR3_BA2</text>
<text x="56.9" y="152.9">DDR3_BA2_T</text>
<text x="57.7" y="155.4">DDR3_WE_T</text>
<text x="58.4" y="150.3">DDR3_A2_T</text>
<text x="25.1" y="157.9">DDR3_S0</text>
<text x="25.1" y="160.5">DDR3_BA0</text>
<text x="56.9" y="160.5">DDR3_BA0_T</text>
<text x="58.8" y="157.9">DDR3_S0_T</text>
<text x="157.4" y="157.9">DDR3_CLK_P</text>
<text x="195.7" y="160.5">GND</text>
<text x="205.8" y="160.5">GND</text>
<text x="216" y="160.5">GND</text>
<text x="226.2" y="160.5">GND</text>
<text x="236.3" y="160.5">GND</text>
<text x="25.1" y="163">DDR3_A3</text>
<text x="25.1" y="165.6">DDR3_A10</text>
<text x="57.3" y="165.6">DDR3_A10_T</text>
<text x="58.4" y="163">DDR3_A3_T</text>
<text x="119.7" y="164.3">VTTREF</text>
<text x="25.1" y="173.2">DDR3_ODT</text>
<text x="25.1" y="170.7">DDR3_CKE</text>
<text x="25.1" y="168.1">DDR3_A6</text>
<text x="56.5" y="173.2">DDR3_ODT_T</text>
<text x="56.6" y="170.7">DDR3_CKE_T</text>
<text x="58.4" y="168.1">DDR3_A6_T</text>
<text x="157.4" y="168.1">DDR3_CLK_N</text>
<text x="279.6" y="173.2">GND</text>
<text x="25.1" y="175.8">DDR3_CAS</text>
<text x="25.1" y="178.3">DDR3_A11</text>
<text x="56.8" y="175.8">DDR3_CAS_T</text>
<text x="57.3" y="178.3">DDR3_A11_T</text>
<text x="25.1" y="185.9">DDR3_A0</text>
<text x="25.1" y="180.8">DDR3_A4</text>
<text x="25.1" y="183.4">DDR3_A7</text>
<text x="58.4" y="185.9">DDR3_A0_T</text>
<text x="58.4" y="180.8">DDR3_A4_T</text>
<text x="58.4" y="183.4">DDR3_A7_T</text>
<text x="96.4" y="185.9">GND</text>
<text x="106.6" y="185.9">GND</text>
<text x="25.1" y="188.5">DDR3_A5</text>
<text x="25.1" y="191">DDR3_A8</text>
<text x="58.4" y="188.5">DDR3_A5_T</text>
<text x="58.4" y="191">DDR3_A8_T</text>
</g>
</g></defs>
<path d="M2.2 8.4h292.6v193.3h-292.6z" fill-rule="evenodd" fill="#fffcf8"/>
<path d="M2.2 8.4h292.6v193.3h-292.6z" fill="none" stroke="#000" stroke-width=".21"/>
<path d="M7.3 13.5h282.4v183.1h-282.4z" fill-rule="evenodd" fill="#fffcf8"/>
<g fill="none" stroke="#000" stroke-width=".21">
<path d="M2.2 8.4h5.1M7.3 13.5h282.4v183.1h-282.4zM75.3 8.4v5.1M148.5 8.4v5.1M221.6 8.4v5.1M289.7 8.4h5.1v5.1M2.2 56.7h5.1M289.7 56.7h5.1M2.2 105h5.1M289.7 105.1h5.1M2.2 153.4h5.1M289.7 153.4h5.1"/>
<path d="M289.7 176.3h-89.1v20.3M75.3 196.6v5.1M148.5 196.6v5.1M200.6 183.9h89.1M200.6 191.5h89.1M200.6 194.1h89.1M213.4 183.9v7.6M221.6 196.6v5.1M251.5 191.5v5.1M264.2 183.9v7.6M294.8 196.6v5.1"/>
</g>
<g fill="#fff">
<path d="M63.3 23.6h17.8v20.4h-17.8z" fill-rule="evenodd"/>
<path d="M63.3 46.5h20.3v17.8h-20.3z" fill-rule="evenodd"/>
<path d="M147.2 23.6h17.8v20.4h-17.8z" fill-rule="evenodd"/>
<path d="M147.2 46.5h20.4v17.8h-20.4z" fill-rule="evenodd"/>
</g>
<path d="M231.2 23.6h-2.6v2.6M282 36.4v53.4M231.2 100h-2.6v2.5M78.5 107.6h5.1v2.5M162.5 107.6h5.1v2.5M177.7 102.5h2.6v7.6M282 112.7v53.4M98.9 176.3v2.5M109.1 176.3v2.5" fill="none" stroke="#00be00" stroke-width="1.3"/>
<path d="M193 33.8v2.6h58.5v20.3M193 64.3v2.6h58.5v20.3M193 110.1v2.6h58.5v20.3M98.9 148.3v2.5M193 140.7v2.5h58.5v20.4" fill="none" stroke="#ff0" stroke-width="1.3"/>
<path d="M241.3 23.6h10.2M243.9 23.6v2.6M251.5 21.1v10.2M241.3 100h10.2M243.9 100v2.5M251.5 97.4v10.2M98.9 161v5.1M98.9 163.6h17.8M109.1 163.6v2.5" fill="none" stroke="#fff0ff" stroke-width="1.3"/>
<path d="M55.6 133h17.8v61.1h-17.8z" fill-rule="evenodd" fill="#fff"/>
<path d="M37.8 23.6h20.4v86.5h-20.4z" fill-rule="evenodd" fill="#ffffb0"/>
<path d="M37.8 23.6h20.4v86.5h-20.4z" fill="none" stroke="#800000" stroke-width=".21"/>
<path d="M58.2 59.3h5.1" fill="none" stroke="#000" stroke-width=".25"/>
<path d="M58.2 59.3l1.5-.6v1.1z" fill="#f8fcff"/>
<path d="M58.2 59.3l1.5-.6v1.1z" fill="none" stroke="#000" stroke-width=".21"/>
<path d="M60 58.7l1.5 .6-1.5 .5z" fill="#f8fcff"/>
<path d="M60 58.7l1.5 .6-1.5 .5z" fill="none" stroke="#000" stroke-width=".21"/>
<path d="M58.2 64.3h5.1" fill="none" stroke="#000" stroke-width=".25"/>
<path d="M58.2 64.3l1.5-.5v1z" fill="#f8fcff"/>
<path d="M58.2 64.3l1.5-.5v1z" fill="none" stroke="#000" stroke-width=".21"/>
<path d="M60 63.8l1.5 .5-1.5 .5z" fill="#f8fcff"/>
<path d="M60 63.8l1.5 .5-1.5 .5z" fill="none" stroke="#000" stroke-width=".21"/>
<path d="M58.2 56.7h5.1" fill="none" stroke="#000" stroke-width=".25"/>
<path d="M58.2 56.7l1.5-.5v1z" fill="#f8fcff"/>
<path d="M58.2 56.7l1.5-.5v1z" fill="none" stroke="#000" stroke-width=".21"/>
<path d="M60 56.2l1.5 .5-1.5 .5z" fill="#f8fcff"/>
<path d="M60 56.2l1.5 .5-1.5 .5z" fill="none" stroke="#000" stroke-width=".21"/>
<path d="M58.2 79.6h5.1" fill="none" stroke="#000" stroke-width=".25"/>
<path d="M58.2 79.6l1.5-.5v1z" fill="#f8fcff"/>
<path d="M58.2 79.6l1.5-.5v1z" fill="none" stroke="#000" stroke-width=".21"/>
<path d="M60 79.1l1.5 .5-1.5 .5z" fill="#f8fcff"/>
<path d="M60 79.1l1.5 .5-1.5 .5z" fill="none" stroke="#000" stroke-width=".21"/>
<path d="M58.2 61.8h5.1" fill="none" stroke="#000" stroke-width=".25"/>
<path d="M58.2 61.8l1.5-.5v1z" fill="#f8fcff"/>
<path d="M58.2 61.8l1.5-.5v1z" fill="none" stroke="#000" stroke-width=".21"/>
<path d="M60 61.3l1.5 .5-1.5 .5z" fill="#f8fcff"/>
<path d="M60 61.3l1.5 .5-1.5 .5z" fill="none" stroke="#000" stroke-width=".21"/>
<path d="M58.2 54.2h5.1" fill="none" stroke="#000" stroke-width=".25"/>
<path d="M58.2 54.2l1.5-.5v1z" fill="#f8fcff"/>
<path d="M58.2 54.2l1.5-.5v1z" fill="none" stroke="#000" stroke-width=".21"/>
<path d="M60 53.7l1.5 .5-1.5 .5z" fill="#f8fcff"/>
<path d="M60 53.7l1.5 .5-1.5 .5z" fill="none" stroke="#000" stroke-width=".21"/>
<path d="M58.2 49.1h5.1" fill="none" stroke="#000" stroke-width=".25"/>
<path d="M58.2 49.1l1.5-.5v1z" fill="#f8fcff"/>
<path d="M58.2 49.1l1.5-.5v1z" fill="none" stroke="#000" stroke-width=".21"/>
<path d="M60 48.6l1.5 .5-1.5 .5z" fill="#f8fcff"/>
<path d="M60 48.6l1.5 .5-1.5 .5z" fill="none" stroke="#000" stroke-width=".21"/>
<path d="M58.2 77.1h5.1" fill="none" stroke="#000" stroke-width=".25"/>
<path d="M58.2 77.1l1.5-.5v1z" fill="#f8fcff"/>
<path d="M58.2 77.1l1.5-.5v1z" fill="none" stroke="#000" stroke-width=".21"/>
<path d="M60 76.6l1.5 .5-1.5 .5z" fill="#f8fcff"/>
<path d="M60 76.6l1.5 .5-1.5 .5z" fill="none" stroke="#000" stroke-width=".21"/>
<path d="M58.2 51.6h5.1" fill="none" stroke="#000" stroke-width=".25"/>
<path d="M58.2 51.6l1.5-.5v1z" fill="#f8fcff"/>
<path d="M58.2 51.6l1.5-.5v1z" fill="none" stroke="#000" stroke-width=".21"/>
<path d="M60 51.1l1.5 .5-1.5 .5z" fill="#f8fcff"/>
<path d="M60 51.1l1.5 .5-1.5 .5z" fill="none" stroke="#000" stroke-width=".21"/>
<path d="M58.2 87.2h5.1" fill="none" stroke="#000" stroke-width=".25"/>
<path d="M58.2 87.2l1.5-.5v1z" fill="#f8fcff"/>
<path d="M58.2 87.2l1.5-.5v1z" fill="none" stroke="#000" stroke-width=".21"/>
<path d="M58.2 46.5h5.1" fill="none" stroke="#000" stroke-width=".25"/>
<path d="M58.2 46.5l1.5-.5v1z" fill="#f8fcff"/>
<path d="M58.2 46.5l1.5-.5v1z" fill="none" stroke="#000" stroke-width=".21"/>
<path d="M60 46l1.5 .5-1.5 .5z" fill="#f8fcff"/>
<path d="M60 46l1.5 .5-1.5 .5z" fill="none" stroke="#000" stroke-width=".21"/>
<path d="M58.2 26.2h5.1" fill="none" stroke="#000" stroke-width=".25"/>
<path d="M58.2 26.2l1.5-.5v1z" fill="#f8fcff"/>
<path d="M58.2 26.2l1.5-.5v1z" fill="none" stroke="#000" stroke-width=".21"/>
<path d="M60 25.7l1.5 .5-1.5 .5z" fill="#f8fcff"/>
<path d="M60 25.7l1.5 .5-1.5 .5z" fill="none" stroke="#000" stroke-width=".21"/>
<path d="M58.2 84.7h5.1" fill="none" stroke="#000" stroke-width=".25"/>
<path d="M58.2 84.7l1.5-.5v1z" fill="#f8fcff"/>
<path d="M58.2 84.7l1.5-.5v1z" fill="none" stroke="#000" stroke-width=".21"/>
<path d="M58.2 31.3h5.1" fill="none" stroke="#000" stroke-width=".25"/>
<path d="M58.2 31.3l1.5-.5v1z" fill="#f8fcff"/>
<path d="M58.2 31.3l1.5-.5v1z" fill="none" stroke="#000" stroke-width=".21"/>
<path d="M60 30.8l1.5 .5-1.5 .5z" fill="#f8fcff"/>
<path d="M60 30.8l1.5 .5-1.5 .5z" fill="none" stroke="#000" stroke-width=".21"/>
<path d="M58.2 69.4h5.1" fill="none" stroke="#000" stroke-width=".25"/>
<path d="M58.2 69.4l1.5-.5v1z" fill="#f8fcff"/>
<path d="M58.2 69.4l1.5-.5v1z" fill="none" stroke="#000" stroke-width=".21"/>
<path d="M60 68.9l1.5 .5-1.5 .5z" fill="#f8fcff"/>
<path d="M60 68.9l1.5 .5-1.5 .5z" fill="none" stroke="#000" stroke-width=".21"/>
<path d="M58.2 28.7h5.1" fill="none" stroke="#000" stroke-width=".25"/>
<path d="M58.2 28.7l1.5-.5v1z" fill="#f8fcff"/>
<path d="M58.2 28.7l1.5-.5v1z" fill="none" stroke="#000" stroke-width=".21"/>
<path d="M60 28.2l1.5 .5-1.5 .5z" fill="#f8fcff"/>
<path d="M60 28.2l1.5 .5-1.5 .5z" fill="none" stroke="#000" stroke-width=".21"/>
<path d="M58.2 33.8h5.1" fill="none" stroke="#000" stroke-width=".25"/>
<path d="M58.2 33.8l1.5-.5v1z" fill="#f8fcff"/>
<path d="M58.2 33.8l1.5-.5v1z" fill="none" stroke="#000" stroke-width=".21"/>
<path d="M60 33.3l1.5 .5-1.5 .5z" fill="#f8fcff"/>
<path d="M60 33.3l1.5 .5-1.5 .5z" fill="none" stroke="#000" stroke-width=".21"/>
<path d="M58.2 41.4h5.1" fill="none" stroke="#000" stroke-width=".25"/>
<path d="M58.2 41.4l1.5-.5v1.1z" fill="#f8fcff"/>
<path d="M58.2 41.4l1.5-.5v1.1z" fill="none" stroke="#000" stroke-width=".21"/>
<path d="M60 40.9l1.5 .5-1.5 .6z" fill="#f8fcff"/>
<path d="M60 40.9l1.5 .5-1.5 .6z" fill="none" stroke="#000" stroke-width=".21"/>
<path d="M58.2 72h5.1" fill="none" stroke="#000" stroke-width=".25"/>
<path d="M58.2 72l1.5-.5v1z" fill="#f8fcff"/>
<path d="M58.2 72l1.5-.5v1z" fill="none" stroke="#000" stroke-width=".21"/>
<path d="M60 71.5l1.5 .5-1.5 .5z" fill="#f8fcff"/>
<path d="M60 71.5l1.5 .5-1.5 .5z" fill="none" stroke="#000" stroke-width=".21"/>
<path d="M58.2 36.4h5.1" fill="none" stroke="#000" stroke-width=".25"/>
<path d="M58.2 36.4l1.5-.6v1.1z" fill="#f8fcff"/>
<path d="M58.2 36.4l1.5-.6v1.1z" fill="none" stroke="#000" stroke-width=".21"/>
<path d="M60 35.8l1.5 .6-1.5 .5z" fill="#f8fcff"/>
<path d="M60 35.8l1.5 .6-1.5 .5z" fill="none" stroke="#000" stroke-width=".21"/>
<path d="M58.2 44h5.1" fill="none" stroke="#000" stroke-width=".25"/>
<path d="M58.2 44l1.5-.5v1z" fill="#f8fcff"/>
<path d="M58.2 44l1.5-.5v1z" fill="none" stroke="#000" stroke-width=".21"/>
<path d="M60 43.5l1.5 .5-1.5 .5z" fill="#f8fcff"/>
<path d="M60 43.5l1.5 .5-1.5 .5z" fill="none" stroke="#000" stroke-width=".21"/>
<path d="M58.2 38.9h5.1" fill="none" stroke="#000" stroke-width=".25"/>
<path d="M58.2 38.9l1.5-.5v1z" fill="#f8fcff"/>
<path d="M58.2 38.9l1.5-.5v1z" fill="none" stroke="#000" stroke-width=".21"/>
<path d="M60 38.4l1.5 .5-1.5 .5z" fill="#f8fcff"/>
<path d="M60 38.4l1.5 .5-1.5 .5z" fill="none" stroke="#000" stroke-width=".21"/>
<path d="M32.7 97.4h5.1" fill="none" stroke="#000" stroke-width=".25"/>
<path d="M36.3 96.9l1.5 .5-1.5 .5z" fill="#f8fcff"/>
<path d="M36.3 96.9l1.5 .5-1.5 .5z" fill="none" stroke="#000" stroke-width=".21"/>
<path d="M32.7 79.6h5.1" fill="none" stroke="#000" stroke-width=".25"/>
<path d="M36.3 79.1l1.5 .5-1.5 .5z" fill="#f8fcff"/>
<path d="M36.3 79.1l1.5 .5-1.5 .5zM37.8 79.1l1 .5-1 .5" fill="none" stroke="#000" stroke-width=".21"/>
<path d="M32.7 107.6h5.1" fill="none" stroke="#000" stroke-width=".25"/>
<path d="M36.3 107.1l1.5 .5-1.5 .5z" fill="#f8fcff"/>
<path d="M36.3 107.1l1.5 .5-1.5 .5z" fill="none" stroke="#000" stroke-width=".21"/>
<path d="M32.7 94.9h5.1" fill="none" stroke="#000" stroke-width=".25"/>
<path d="M36.3 94.4l1.5 .5-1.5 .5z" fill="#f8fcff"/>
<path d="M36.3 94.4l1.5 .5-1.5 .5z" fill="none" stroke="#000" stroke-width=".21"/>
<path d="M32.7 82.1h5.1" fill="none" stroke="#000" stroke-width=".25"/>
<path d="M36.3 81.6l1.5 .5-1.5 .6z" fill="#f8fcff"/>
<path d="M36.3 81.6l1.5 .5-1.5 .6zM37.8 81.6l1 .5-1 .6" fill="none" stroke="#000" stroke-width=".21"/>
<path d="M32.7 84.7h5.1" fill="none" stroke="#000" stroke-width=".25"/>
<path d="M36.3 84.2l1.5 .5-1.5 .5z" fill="#f8fcff"/>
<path d="M36.3 84.2l1.5 .5-1.5 .5z" fill="none" stroke="#000" stroke-width=".21"/>
<path d="M32.7 100h5.1" fill="none" stroke="#000" stroke-width=".25"/>
<path d="M36.3 99.4l1.5 .6-1.5 .5z" fill="#f8fcff"/>
<path d="M36.3 99.4l1.5 .6-1.5 .5z" fill="none" stroke="#000" stroke-width=".21"/>
<path d="M32.7 92.3h5.1" fill="none" stroke="#000" stroke-width=".25"/>
<path d="M36.3 91.8l1.5 .5-1.5 .5z" fill="#f8fcff"/>
<path d="M36.3 91.8l1.5 .5-1.5 .5z" fill="none" stroke="#000" stroke-width=".21"/>
<path d="M32.7 51.6h5.1" fill="none" stroke="#000" stroke-width=".25"/>
<path d="M36.3 51.1l1.5 .5-1.5 .5z" fill="#f8fcff"/>
<path d="M36.3 51.1l1.5 .5-1.5 .5z" fill="none" stroke="#000" stroke-width=".21"/>
<path d="M58.2 107.6h5.1" fill="none" stroke="#000" stroke-width=".25"/>
<path d="M58.2 107.6l1.5-.5v1z" fill="#f8fcff"/>
<path d="M58.2 107.6l1.5-.5v1z" fill="none" stroke="#000" stroke-width=".21"/>
<path d="M32.7 69.4h5.1" fill="none" stroke="#000" stroke-width=".25"/>
<path d="M36.3 68.9l1.5 .5-1.5 .5z" fill="#f8fcff"/>
<path d="M36.3 68.9l1.5 .5-1.5 .5z" fill="none" stroke="#000" stroke-width=".21"/>
<path d="M32.7 74.5h5.1" fill="none" stroke="#000" stroke-width=".25"/>
<path d="M36.3 74l1.5 .5-1.5 .5z" fill="#f8fcff"/>
<path d="M36.3 74l1.5 .5-1.5 .5z" fill="none" stroke="#000" stroke-width=".21"/>
<path d="M32.7 33.8h5.1" fill="none" stroke="#000" stroke-width=".25"/>
<path d="M36.3 33.3l1.5 .5-1.5 .5z" fill="#f8fcff"/>
<path d="M36.3 33.3l1.5 .5-1.5 .5z" fill="none" stroke="#000" stroke-width=".21"/>
<path d="M32.7 26.2h5.1" fill="none" stroke="#000" stroke-width=".25"/>
<path d="M36.3 25.7l1.5 .5-1.5 .5z" fill="#f8fcff"/>
<path d="M36.3 25.7l1.5 .5-1.5 .5z" fill="none" stroke="#000" stroke-width=".21"/>
<path d="M32.7 56.7h5.1" fill="none" stroke="#000" stroke-width=".25"/>
<path d="M36.3 56.2l1.5 .5-1.5 .5z" fill="#f8fcff"/>
<path d="M36.3 56.2l1.5 .5-1.5 .5z" fill="none" stroke="#000" stroke-width=".21"/>
<path d="M32.7 72h5.1" fill="none" stroke="#000" stroke-width=".25"/>
<path d="M36.3 71.5l1.5 .5-1.5 .5z" fill="#f8fcff"/>
<path d="M36.3 71.5l1.5 .5-1.5 .5z" fill="none" stroke="#000" stroke-width=".21"/>
<path d="M32.7 38.9h5.1" fill="none" stroke="#000" stroke-width=".25"/>
<path d="M36.3 38.4l1.5 .5-1.5 .5z" fill="#f8fcff"/>
<path d="M36.3 38.4l1.5 .5-1.5 .5z" fill="none" stroke="#000" stroke-width=".21"/>
<path d="M32.7 31.3h5.1" fill="none" stroke="#000" stroke-width=".25"/>
<path d="M36.3 30.8l1.5 .5-1.5 .5z" fill="#f8fcff"/>
<path d="M36.3 30.8l1.5 .5-1.5 .5z" fill="none" stroke="#000" stroke-width=".21"/>
<path d="M32.7 28.7h5.1" fill="none" stroke="#000" stroke-width=".25"/>
<path d="M36.3 28.2l1.5 .5-1.5 .5z" fill="#f8fcff"/>
<path d="M36.3 28.2l1.5 .5-1.5 .5z" fill="none" stroke="#000" stroke-width=".21"/>
<path d="M32.7 36.4h5.1" fill="none" stroke="#000" stroke-width=".25"/>
<path d="M36.3 35.8l1.5 .6-1.5 .5z" fill="#f8fcff"/>
<path d="M36.3 35.8l1.5 .6-1.5 .5z" fill="none" stroke="#000" stroke-width=".21"/>
<path d="M32.7 44h5.1" fill="none" stroke="#000" stroke-width=".25"/>
<path d="M36.3 43.5l1.5 .5-1.5 .5z" fill="#f8fcff"/>
<path d="M36.3 43.5l1.5 .5-1.5 .5z" fill="none" stroke="#000" stroke-width=".21"/>
<path d="M32.7 49.1h5.1" fill="none" stroke="#000" stroke-width=".25"/>
<path d="M36.3 48.6l1.5 .5-1.5 .5z" fill="#f8fcff"/>
<path d="M36.3 48.6l1.5 .5-1.5 .5z" fill="none" stroke="#000" stroke-width=".21"/>
<path d="M32.7 54.2h5.1" fill="none" stroke="#000" stroke-width=".25"/>
<path d="M36.3 53.7l1.5 .5-1.5 .5z" fill="#f8fcff"/>
<path d="M36.3 53.7l1.5 .5-1.5 .5z" fill="none" stroke="#000" stroke-width=".21"/>
<path d="M32.7 41.4h5.1" fill="none" stroke="#000" stroke-width=".25"/>
<path d="M36.3 40.9l1.5 .5-1.5 .6z" fill="#f8fcff"/>
<path d="M36.3 40.9l1.5 .5-1.5 .6z" fill="none" stroke="#000" stroke-width=".21"/>
<path d="M58.2 102.5h5.1" fill="none" stroke="#000" stroke-width=".25"/>
<path d="M58.2 102.5l1.5-.5v1z" fill="#f8fcff"/>
<path d="M58.2 102.5l1.5-.5v1z" fill="none" stroke="#000" stroke-width=".21"/>
<path d="M32.7 46.5h5.1" fill="none" stroke="#000" stroke-width=".25"/>
<path d="M36.3 46l1.5 .5-1.5 .5z" fill="#f8fcff"/>
<path d="M36.3 46l1.5 .5-1.5 .5z" fill="none" stroke="#000" stroke-width=".21"/>
<circle cx="251.5" cy="36.4" r=".51" fill="#000080"/>
<circle cx="251.5" cy="36.4" r=".51" fill="none" stroke="#000080" stroke-width=".21"/>
<circle cx="251.5" cy="38.9" r=".51" fill="#000080"/>
<circle cx="251.5" cy="38.9" r=".51" fill="none" stroke="#000080" stroke-width=".21"/>
<circle cx="282" cy="59.3" r=".51" fill="#000080"/>
<circle cx="282" cy="59.3" r=".51" fill="none" stroke="#000080" stroke-width=".21"/>
<circle cx="251.5" cy="66.9" r=".51" fill="#000080"/>
<circle cx="251.5" cy="66.9" r=".51" fill="none" stroke="#000080" stroke-width=".21"/>
<circle cx="282" cy="61.8" r=".51" fill="#000080"/>
<circle cx="282" cy="61.8" r=".51" fill="none" stroke="#000080" stroke-width=".21"/>
<circle cx="282" cy="38.9" r=".51" fill="#000080"/>
<circle cx="282" cy="38.9" r=".51" fill="none" stroke="#000080" stroke-width=".21"/>
<circle cx="251.5" cy="41.4" r=".51" fill="#000080"/>
<circle cx="251.5" cy="41.4" r=".51" fill="none" stroke="#000080" stroke-width=".21"/>
<circle cx="251.5" cy="44" r=".51" fill="#000080"/>
<circle cx="251.5" cy="44" r=".51" fill="none" stroke="#000080" stroke-width=".21"/>
<circle cx="282" cy="41.4" r=".51" fill="#000080"/>
<circle cx="282" cy="41.4" r=".51" fill="none" stroke="#000080" stroke-width=".21"/>
<circle cx="251.5" cy="46.5" r=".51" fill="#000080"/>
<circle cx="251.5" cy="46.5" r=".51" fill="none" stroke="#000080" stroke-width=".21"/>
<circle cx="282" cy="44" r=".51" fill="#000080"/>
<circle cx="282" cy="44" r=".51" fill="none" stroke="#000080" stroke-width=".21"/>
<circle cx="251.5" cy="69.4" r=".51" fill="#000080"/>
<circle cx="251.5" cy="69.4" r=".51" fill="none" stroke="#000080" stroke-width=".21"/>
<circle cx="282" cy="64.3" r=".51" fill="#000080"/>
<circle cx="282" cy="64.3" r=".51" fill="none" stroke="#000080" stroke-width=".21"/>
<circle cx="282" cy="46.5" r=".51" fill="#000080"/>
<circle cx="282" cy="46.5" r=".51" fill="none" stroke="#000080" stroke-width=".21"/>
<circle cx="282" cy="49.1" r=".51" fill="#000080"/>
<circle cx="282" cy="49.1" r=".51" fill="none" stroke="#000080" stroke-width=".21"/>
<circle cx="251.5" cy="51.6" r=".51" fill="#000080"/>
<circle cx="251.5" cy="51.6" r=".51" fill="none" stroke="#000080" stroke-width=".21"/>
<circle cx="251.5" cy="49.1" r=".51" fill="#000080"/>
<circle cx="251.5" cy="49.1" r=".51" fill="none" stroke="#000080" stroke-width=".21"/>
<circle cx="282" cy="51.6" r=".51" fill="#000080"/>
<circle cx="282" cy="51.6" r=".51" fill="none" stroke="#000080" stroke-width=".21"/>
<circle cx="282" cy="54.2" r=".51" fill="#000080"/>
<circle cx="282" cy="54.2" r=".51" fill="none" stroke="#000080" stroke-width=".21"/>
<circle cx="251.5" cy="72" r=".51" fill="#000080"/>
<circle cx="251.5" cy="72" r=".51" fill="none" stroke="#000080" stroke-width=".21"/>
<circle cx="282" cy="66.9" r=".51" fill="#000080"/>
<circle cx="282" cy="66.9" r=".51" fill="none" stroke="#000080" stroke-width=".21"/>
<circle cx="282" cy="56.7" r=".51" fill="#000080"/>
<circle cx="282" cy="56.7" r=".51" fill="none" stroke="#000080" stroke-width=".21"/>
<circle cx="251.5" cy="54.2" r=".51" fill="#000080"/>
<circle cx="251.5" cy="54.2" r=".51" fill="none" stroke="#000080" stroke-width=".21"/>
<circle cx="282" cy="69.4" r=".51" fill="#000080"/>
<circle cx="282" cy="69.4" r=".51" fill="none" stroke="#000080" stroke-width=".21"/>
<circle cx="282" cy="72" r=".51" fill="#000080"/>
<circle cx="282" cy="72" r=".51" fill="none" stroke="#000080" stroke-width=".21"/>
<circle cx="251.5" cy="74.5" r=".51" fill="#000080"/>
<circle cx="251.5" cy="74.5" r=".51" fill="none" stroke="#000080" stroke-width=".21"/>
<circle cx="251.5" cy="77.1" r=".51" fill="#000080"/>
<circle cx="251.5" cy="77.1" r=".51" fill="none" stroke="#000080" stroke-width=".21"/>
<circle cx="282" cy="74.5" r=".51" fill="#000080"/>
<circle cx="282" cy="74.5" r=".51" fill="none" stroke="#000080" stroke-width=".21"/>
<circle cx="282" cy="77.1" r=".51" fill="#000080"/>
<circle cx="282" cy="77.1" r=".51" fill="none" stroke="#000080" stroke-width=".21"/>
<circle cx="251.5" cy="79.6" r=".51" fill="#000080"/>
<circle cx="251.5" cy="79.6" r=".51" fill="none" stroke="#000080" stroke-width=".21"/>
<circle cx="251.5" cy="82.1" r=".51" fill="#000080"/>
<circle cx="251.5" cy="82.1" r=".51" fill="none" stroke="#000080" stroke-width=".21"/>
<circle cx="282" cy="79.6" r=".51" fill="#000080"/>
<circle cx="282" cy="79.6" r=".51" fill="none" stroke="#000080" stroke-width=".21"/>
<circle cx="282" cy="82.1" r=".51" fill="#000080"/>
<circle cx="282" cy="82.1" r=".51" fill="none" stroke="#000080" stroke-width=".21"/>
<circle cx="251.5" cy="84.7" r=".51" fill="#000080"/>
<circle cx="251.5" cy="84.7" r=".51" fill="none" stroke="#000080" stroke-width=".21"/>
<circle cx="282" cy="84.7" r=".51" fill="#000080"/>
<circle cx="282" cy="84.7" r=".51" fill="none" stroke="#000080" stroke-width=".21"/>
<circle cx="282" cy="87.2" r=".51" fill="#000080"/>
<circle cx="282" cy="87.2" r=".51" fill="none" stroke="#000080" stroke-width=".21"/>
<circle cx="251.5" cy="28.7" r=".51" fill="#000080"/>
<circle cx="251.5" cy="28.7" r=".51" fill="none" stroke="#000080" stroke-width=".21"/>
<path d="M256.6 26.2h20.4v63.6h-20.4z" fill-rule="evenodd" fill="#ffffb0"/>
<path d="M256.6 26.2h20.4v63.6h-20.4z" fill="none" stroke="#800000" stroke-width=".21"/>
<path d="M251.5 36.4h5.1" fill="none" stroke="#000" stroke-width=".25"/>
<circle cx="251.5" cy="36.4" r=".51" fill="#000080"/>
<circle cx="251.5" cy="36.4" r=".51" fill="none" stroke="#000080" stroke-width=".21"/>
<path d="M251.5 38.9h5.1" fill="none" stroke="#000" stroke-width=".25"/>
<circle cx="251.5" cy="38.9" r=".51" fill="#000080"/>
<circle cx="251.5" cy="38.9" r=".51" fill="none" stroke="#000080" stroke-width=".21"/>
<path d="M277 59.3h5" fill="none" stroke="#000" stroke-width=".25"/>
<circle cx="282" cy="59.3" r=".51" fill="#000080"/>
<circle cx="282" cy="59.3" r=".51" fill="none" stroke="#000080" stroke-width=".21"/>
<path d="M277 36.4h5M251.5 66.9h5.1" fill="none" stroke="#000" stroke-width=".25"/>
<circle cx="251.5" cy="66.9" r=".51" fill="#000080"/>
<circle cx="251.5" cy="66.9" r=".51" fill="none" stroke="#000080" stroke-width=".21"/>
<path d="M277 61.8h5" fill="none" stroke="#000" stroke-width=".25"/>
<circle cx="282" cy="61.8" r=".51" fill="#000080"/>
<circle cx="282" cy="61.8" r=".51" fill="none" stroke="#000080" stroke-width=".21"/>
<path d="M277 38.9h5" fill="none" stroke="#000" stroke-width=".25"/>
<circle cx="282" cy="38.9" r=".51" fill="#000080"/>
<circle cx="282" cy="38.9" r=".51" fill="none" stroke="#000080" stroke-width=".21"/>
<path d="M251.5 41.4h5.1" fill="none" stroke="#000" stroke-width=".25"/>
<circle cx="251.5" cy="41.4" r=".51" fill="#000080"/>
<circle cx="251.5" cy="41.4" r=".51" fill="none" stroke="#000080" stroke-width=".21"/>
<path d="M251.5 44h5.1" fill="none" stroke="#000" stroke-width=".25"/>
<circle cx="251.5" cy="44" r=".51" fill="#000080"/>
<circle cx="251.5" cy="44" r=".51" fill="none" stroke="#000080" stroke-width=".21"/>
<path d="M277 41.4h5" fill="none" stroke="#000" stroke-width=".25"/>
<circle cx="282" cy="41.4" r=".51" fill="#000080"/>
<circle cx="282" cy="41.4" r=".51" fill="none" stroke="#000080" stroke-width=".21"/>
<path d="M251.5 46.5h5.1" fill="none" stroke="#000" stroke-width=".25"/>
<circle cx="251.5" cy="46.5" r=".51" fill="#000080"/>
<circle cx="251.5" cy="46.5" r=".51" fill="none" stroke="#000080" stroke-width=".21"/>
<path d="M277 44h5" fill="none" stroke="#000" stroke-width=".25"/>
<circle cx="282" cy="44" r=".51" fill="#000080"/>
<circle cx="282" cy="44" r=".51" fill="none" stroke="#000080" stroke-width=".21"/>
<path d="M251.5 69.4h5.1" fill="none" stroke="#000" stroke-width=".25"/>
<circle cx="251.5" cy="69.4" r=".51" fill="#000080"/>
<circle cx="251.5" cy="69.4" r=".51" fill="none" stroke="#000080" stroke-width=".21"/>
<path d="M277 64.3h5" fill="none" stroke="#000" stroke-width=".25"/>
<circle cx="282" cy="64.3" r=".51" fill="#000080"/>
<circle cx="282" cy="64.3" r=".51" fill="none" stroke="#000080" stroke-width=".21"/>
<path d="M277 46.5h5" fill="none" stroke="#000" stroke-width=".25"/>
<circle cx="282" cy="46.5" r=".51" fill="#000080"/>
<circle cx="282" cy="46.5" r=".51" fill="none" stroke="#000080" stroke-width=".21"/>
<path d="M277 49.1h5" fill="none" stroke="#000" stroke-width=".25"/>
<circle cx="282" cy="49.1" r=".51" fill="#000080"/>
<circle cx="282" cy="49.1" r=".51" fill="none" stroke="#000080" stroke-width=".21"/>
<path d="M251.5 51.6h5.1" fill="none" stroke="#000" stroke-width=".25"/>
<circle cx="251.5" cy="51.6" r=".51" fill="#000080"/>
<circle cx="251.5" cy="51.6" r=".51" fill="none" stroke="#000080" stroke-width=".21"/>
<path d="M251.5 49.1h5.1" fill="none" stroke="#000" stroke-width=".25"/>
<circle cx="251.5" cy="49.1" r=".51" fill="#000080"/>
<circle cx="251.5" cy="49.1" r=".51" fill="none" stroke="#000080" stroke-width=".21"/>
<path d="M277 51.6h5" fill="none" stroke="#000" stroke-width=".25"/>
<circle cx="282" cy="51.6" r=".51" fill="#000080"/>
<circle cx="282" cy="51.6" r=".51" fill="none" stroke="#000080" stroke-width=".21"/>
<path d="M277 54.2h5" fill="none" stroke="#000" stroke-width=".25"/>
<circle cx="282" cy="54.2" r=".51" fill="#000080"/>
<circle cx="282" cy="54.2" r=".51" fill="none" stroke="#000080" stroke-width=".21"/>
<path d="M251.5 72h5.1" fill="none" stroke="#000" stroke-width=".25"/>
<circle cx="251.5" cy="72" r=".51" fill="#000080"/>
<circle cx="251.5" cy="72" r=".51" fill="none" stroke="#000080" stroke-width=".21"/>
<path d="M277 66.9h5" fill="none" stroke="#000" stroke-width=".25"/>
<circle cx="282" cy="66.9" r=".51" fill="#000080"/>
<circle cx="282" cy="66.9" r=".51" fill="none" stroke="#000080" stroke-width=".21"/>
<path d="M277 56.7h5" fill="none" stroke="#000" stroke-width=".25"/>
<circle cx="282" cy="56.7" r=".51" fill="#000080"/>
<circle cx="282" cy="56.7" r=".51" fill="none" stroke="#000080" stroke-width=".21"/>
<path d="M251.5 54.2h5.1" fill="none" stroke="#000" stroke-width=".25"/>
<circle cx="251.5" cy="54.2" r=".51" fill="#000080"/>
<circle cx="251.5" cy="54.2" r=".51" fill="none" stroke="#000080" stroke-width=".21"/>
<path d="M251.5 56.7h5.1M277 69.4h5" fill="none" stroke="#000" stroke-width=".25"/>
<circle cx="282" cy="69.4" r=".51" fill="#000080"/>
<circle cx="282" cy="69.4" r=".51" fill="none" stroke="#000080" stroke-width=".21"/>
<path d="M277 72h5" fill="none" stroke="#000" stroke-width=".25"/>
<circle cx="282" cy="72" r=".51" fill="#000080"/>
<circle cx="282" cy="72" r=".51" fill="none" stroke="#000080" stroke-width=".21"/>
<path d="M251.5 74.5h5.1" fill="none" stroke="#000" stroke-width=".25"/>
<circle cx="251.5" cy="74.5" r=".51" fill="#000080"/>
<circle cx="251.5" cy="74.5" r=".51" fill="none" stroke="#000080" stroke-width=".21"/>
<path d="M251.5 77.1h5.1" fill="none" stroke="#000" stroke-width=".25"/>
<circle cx="251.5" cy="77.1" r=".51" fill="#000080"/>
<circle cx="251.5" cy="77.1" r=".51" fill="none" stroke="#000080" stroke-width=".21"/>
<path d="M277 74.5h5" fill="none" stroke="#000" stroke-width=".25"/>
<circle cx="282" cy="74.5" r=".51" fill="#000080"/>
<circle cx="282" cy="74.5" r=".51" fill="none" stroke="#000080" stroke-width=".21"/>
<path d="M277 77.1h5" fill="none" stroke="#000" stroke-width=".25"/>
<circle cx="282" cy="77.1" r=".51" fill="#000080"/>
<circle cx="282" cy="77.1" r=".51" fill="none" stroke="#000080" stroke-width=".21"/>
<path d="M251.5 79.6h5.1" fill="none" stroke="#000" stroke-width=".25"/>
<circle cx="251.5" cy="79.6" r=".51" fill="#000080"/>
<circle cx="251.5" cy="79.6" r=".51" fill="none" stroke="#000080" stroke-width=".21"/>
<path d="M251.5 82.1h5.1" fill="none" stroke="#000" stroke-width=".25"/>
<circle cx="251.5" cy="82.1" r=".51" fill="#000080"/>
<circle cx="251.5" cy="82.1" r=".51" fill="none" stroke="#000080" stroke-width=".21"/>
<path d="M277 79.6h5" fill="none" stroke="#000" stroke-width=".25"/>
<circle cx="282" cy="79.6" r=".51" fill="#000080"/>
<circle cx="282" cy="79.6" r=".51" fill="none" stroke="#000080" stroke-width=".21"/>
<path d="M277 82.1h5" fill="none" stroke="#000" stroke-width=".25"/>
<circle cx="282" cy="82.1" r=".51" fill="#000080"/>
<circle cx="282" cy="82.1" r=".51" fill="none" stroke="#000080" stroke-width=".21"/>
<path d="M251.5 84.7h5.1" fill="none" stroke="#000" stroke-width=".25"/>
<circle cx="251.5" cy="84.7" r=".51" fill="#000080"/>
<circle cx="251.5" cy="84.7" r=".51" fill="none" stroke="#000080" stroke-width=".21"/>
<path d="M251.5 87.2h5.1M277 84.7h5" fill="none" stroke="#000" stroke-width=".25"/>
<circle cx="282" cy="84.7" r=".51" fill="#000080"/>
<circle cx="282" cy="84.7" r=".51" fill="none" stroke="#000080" stroke-width=".21"/>
<path d="M277 87.2h5" fill="none" stroke="#000" stroke-width=".25"/>
<circle cx="282" cy="87.2" r=".51" fill="#000080"/>
<circle cx="282" cy="87.2" r=".51" fill="none" stroke="#000080" stroke-width=".21"/>
<path d="M251.5 31.3h5.1" fill="none" stroke="#000" stroke-width=".25"/>
<path d="M255.1 30.8l1.5 .5-1.5 .5z" fill="#f8fcff"/>
<path d="M255.1 30.8l1.5 .5-1.5 .5z" fill="none" stroke="#000" stroke-width=".21"/>
<path d="M251.5 28.7h5.1" fill="none" stroke="#000" stroke-width=".25"/>
<path d="M255.1 28.2l1.5 .5-1.5 .5z" fill="#f8fcff"/>
<path d="M255.1 28.2l1.5 .5-1.5 .5z" fill="none" stroke="#000" stroke-width=".21"/>
<circle cx="251.5" cy="28.7" r=".51" fill="#000080"/>
<circle cx="251.5" cy="28.7" r=".51" fill="none" stroke="#000080" stroke-width=".21"/>
<path d="M40.4 117.8h15.2v12.7h-15.2z" fill-rule="evenodd" fill="#ffffb0"/>
<path d="M40.4 117.8h15.2v12.7h-15.2z" fill="none" stroke="#800000" stroke-width=".21"/>
<path d="M35.3 120.3h5.1M35.3 122.9h5.1M35.3 125.4h5.1M35.3 127.9h5.1M55.6 120.3h5.1M55.6 122.9h5.1M55.6 125.4h5.1" fill="none" stroke="#000" stroke-width=".25"/>
<path d="M121.8 23.6h20.3v86.5h-20.3z" fill-rule="evenodd" fill="#ffffb0"/>
<path d="M121.8 23.6h20.3v86.5h-20.3z" fill="none" stroke="#800000" stroke-width=".21"/>
<path d="M142.1 59.3h5.1" fill="none" stroke="#000" stroke-width=".25"/>
<path d="M142.1 59.3l1.5-.6v1.1z" fill="#f8fcff"/>
<path d="M142.1 59.3l1.5-.6v1.1z" fill="none" stroke="#000" stroke-width=".21"/>
<path d="M143.9 58.7l1.5 .6-1.5 .5z" fill="#f8fcff"/>
<path d="M143.9 58.7l1.5 .6-1.5 .5z" fill="none" stroke="#000" stroke-width=".21"/>
<path d="M142.1 64.3h5.1" fill="none" stroke="#000" stroke-width=".25"/>
<path d="M142.1 64.3l1.5-.5v1z" fill="#f8fcff"/>
<path d="M142.1 64.3l1.5-.5v1z" fill="none" stroke="#000" stroke-width=".21"/>
<path d="M143.9 63.8l1.5 .5-1.5 .5z" fill="#f8fcff"/>
<path d="M143.9 63.8l1.5 .5-1.5 .5z" fill="none" stroke="#000" stroke-width=".21"/>
<path d="M142.1 56.7h5.1" fill="none" stroke="#000" stroke-width=".25"/>
<path d="M142.1 56.7l1.5-.5v1z" fill="#f8fcff"/>
<path d="M142.1 56.7l1.5-.5v1z" fill="none" stroke="#000" stroke-width=".21"/>
<path d="M143.9 56.2l1.5 .5-1.5 .5z" fill="#f8fcff"/>
<path d="M143.9 56.2l1.5 .5-1.5 .5z" fill="none" stroke="#000" stroke-width=".21"/>
<path d="M142.1 79.6h5.1" fill="none" stroke="#000" stroke-width=".25"/>
<path d="M142.1 79.6l1.5-.5v1z" fill="#f8fcff"/>
<path d="M142.1 79.6l1.5-.5v1z" fill="none" stroke="#000" stroke-width=".21"/>
<path d="M143.9 79.1l1.5 .5-1.5 .5z" fill="#f8fcff"/>
<path d="M143.9 79.1l1.5 .5-1.5 .5z" fill="none" stroke="#000" stroke-width=".21"/>
<path d="M142.1 61.8h5.1" fill="none" stroke="#000" stroke-width=".25"/>
<path d="M142.1 61.8l1.5-.5v1z" fill="#f8fcff"/>
<path d="M142.1 61.8l1.5-.5v1z" fill="none" stroke="#000" stroke-width=".21"/>
<path d="M143.9 61.3l1.5 .5-1.5 .5z" fill="#f8fcff"/>
<path d="M143.9 61.3l1.5 .5-1.5 .5z" fill="none" stroke="#000" stroke-width=".21"/>
<path d="M142.1 54.2h5.1" fill="none" stroke="#000" stroke-width=".25"/>
<path d="M142.1 54.2l1.5-.5v1z" fill="#f8fcff"/>
<path d="M142.1 54.2l1.5-.5v1z" fill="none" stroke="#000" stroke-width=".21"/>
<path d="M143.9 53.7l1.5 .5-1.5 .5z" fill="#f8fcff"/>
<path d="M143.9 53.7l1.5 .5-1.5 .5z" fill="none" stroke="#000" stroke-width=".21"/>
<path d="M142.1 49.1h5.1" fill="none" stroke="#000" stroke-width=".25"/>
<path d="M142.1 49.1l1.5-.5v1z" fill="#f8fcff"/>
<path d="M142.1 49.1l1.5-.5v1z" fill="none" stroke="#000" stroke-width=".21"/>
<path d="M143.9 48.6l1.5 .5-1.5 .5z" fill="#f8fcff"/>
<path d="M143.9 48.6l1.5 .5-1.5 .5z" fill="none" stroke="#000" stroke-width=".21"/>
<path d="M142.1 77.1h5.1" fill="none" stroke="#000" stroke-width=".25"/>
<path d="M142.1 77.1l1.5-.5v1z" fill="#f8fcff"/>
<path d="M142.1 77.1l1.5-.5v1z" fill="none" stroke="#000" stroke-width=".21"/>
<path d="M143.9 76.6l1.5 .5-1.5 .5z" fill="#f8fcff"/>
<path d="M143.9 76.6l1.5 .5-1.5 .5z" fill="none" stroke="#000" stroke-width=".21"/>
<path d="M142.1 51.6h5.1" fill="none" stroke="#000" stroke-width=".25"/>
<path d="M142.1 51.6l1.5-.5v1z" fill="#f8fcff"/>
<path d="M142.1 51.6l1.5-.5v1z" fill="none" stroke="#000" stroke-width=".21"/>
<path d="M143.9 51.1l1.5 .5-1.5 .5z" fill="#f8fcff"/>
<path d="M143.9 51.1l1.5 .5-1.5 .5z" fill="none" stroke="#000" stroke-width=".21"/>
<path d="M142.1 87.2h5.1" fill="none" stroke="#000" stroke-width=".25"/>
<path d="M142.1 87.2l1.5-.5v1z" fill="#f8fcff"/>
<path d="M142.1 87.2l1.5-.5v1z" fill="none" stroke="#000" stroke-width=".21"/>
<path d="M142.1 46.5h5.1" fill="none" stroke="#000" stroke-width=".25"/>
<path d="M142.1 46.5l1.5-.5v1z" fill="#f8fcff"/>
<path d="M142.1 46.5l1.5-.5v1z" fill="none" stroke="#000" stroke-width=".21"/>
<path d="M143.9 46l1.5 .5-1.5 .5z" fill="#f8fcff"/>
<path d="M143.9 46l1.5 .5-1.5 .5z" fill="none" stroke="#000" stroke-width=".21"/>
<path d="M142.1 26.2h5.1" fill="none" stroke="#000" stroke-width=".25"/>
<path d="M142.1 26.2l1.5-.5v1z" fill="#f8fcff"/>
<path d="M142.1 26.2l1.5-.5v1z" fill="none" stroke="#000" stroke-width=".21"/>
<path d="M143.9 25.7l1.5 .5-1.5 .5z" fill="#f8fcff"/>
<path d="M143.9 25.7l1.5 .5-1.5 .5z" fill="none" stroke="#000" stroke-width=".21"/>
<path d="M142.1 84.7h5.1" fill="none" stroke="#000" stroke-width=".25"/>
<path d="M142.1 84.7l1.5-.5v1z" fill="#f8fcff"/>
<path d="M142.1 84.7l1.5-.5v1z" fill="none" stroke="#000" stroke-width=".21"/>
<path d="M142.1 31.3h5.1" fill="none" stroke="#000" stroke-width=".25"/>
<path d="M142.1 31.3l1.5-.5v1z" fill="#f8fcff"/>
<path d="M142.1 31.3l1.5-.5v1z" fill="none" stroke="#000" stroke-width=".21"/>
<path d="M143.9 30.8l1.5 .5-1.5 .5z" fill="#f8fcff"/>
<path d="M143.9 30.8l1.5 .5-1.5 .5z" fill="none" stroke="#000" stroke-width=".21"/>
<path d="M142.1 69.4h5.1" fill="none" stroke="#000" stroke-width=".25"/>
<path d="M142.1 69.4l1.5-.5v1z" fill="#f8fcff"/>
<path d="M142.1 69.4l1.5-.5v1z" fill="none" stroke="#000" stroke-width=".21"/>
<path d="M143.9 68.9l1.5 .5-1.5 .5z" fill="#f8fcff"/>
<path d="M143.9 68.9l1.5 .5-1.5 .5z" fill="none" stroke="#000" stroke-width=".21"/>
<path d="M142.1 28.7h5.1" fill="none" stroke="#000" stroke-width=".25"/>
<path d="M142.1 28.7l1.5-.5v1z" fill="#f8fcff"/>
<path d="M142.1 28.7l1.5-.5v1z" fill="none" stroke="#000" stroke-width=".21"/>
<path d="M143.9 28.2l1.5 .5-1.5 .5z" fill="#f8fcff"/>
<path d="M143.9 28.2l1.5 .5-1.5 .5z" fill="none" stroke="#000" stroke-width=".21"/>
<path d="M142.1 33.8h5.1" fill="none" stroke="#000" stroke-width=".25"/>
<path d="M142.1 33.8l1.5-.5v1z" fill="#f8fcff"/>
<path d="M142.1 33.8l1.5-.5v1z" fill="none" stroke="#000" stroke-width=".21"/>
<path d="M143.9 33.3l1.5 .5-1.5 .5z" fill="#f8fcff"/>
<path d="M143.9 33.3l1.5 .5-1.5 .5z" fill="none" stroke="#000" stroke-width=".21"/>
<path d="M142.1 41.4h5.1" fill="none" stroke="#000" stroke-width=".25"/>
<path d="M142.1 41.4l1.5-.5v1.1z" fill="#f8fcff"/>
<path d="M142.1 41.4l1.5-.5v1.1z" fill="none" stroke="#000" stroke-width=".21"/>
<path d="M143.9 40.9l1.5 .5-1.5 .6z" fill="#f8fcff"/>
<path d="M143.9 40.9l1.5 .5-1.5 .6z" fill="none" stroke="#000" stroke-width=".21"/>
<path d="M142.1 72h5.1" fill="none" stroke="#000" stroke-width=".25"/>
<path d="M142.1 72l1.5-.5v1z" fill="#f8fcff"/>
<path d="M142.1 72l1.5-.5v1z" fill="none" stroke="#000" stroke-width=".21"/>
<path d="M143.9 71.5l1.5 .5-1.5 .5z" fill="#f8fcff"/>
<path d="M143.9 71.5l1.5 .5-1.5 .5z" fill="none" stroke="#000" stroke-width=".21"/>
<path d="M142.1 36.4h5.1" fill="none" stroke="#000" stroke-width=".25"/>
<path d="M142.1 36.4l1.5-.5v1z" fill="#f8fcff"/>
<path d="M142.1 36.4l1.5-.5v1z" fill="none" stroke="#000" stroke-width=".21"/>
<path d="M143.9 35.9l1.5 .5-1.5 .5z" fill="#f8fcff"/>
<path d="M143.9 35.9l1.5 .5-1.5 .5z" fill="none" stroke="#000" stroke-width=".21"/>
<path d="M142.1 44h5.1" fill="none" stroke="#000" stroke-width=".25"/>
<path d="M142.1 44l1.5-.5v1z" fill="#f8fcff"/>
<path d="M142.1 44l1.5-.5v1z" fill="none" stroke="#000" stroke-width=".21"/>
<path d="M143.9 43.5l1.5 .5-1.5 .5z" fill="#f8fcff"/>
<path d="M143.9 43.5l1.5 .5-1.5 .5z" fill="none" stroke="#000" stroke-width=".21"/>
<path d="M142.1 38.9h5.1" fill="none" stroke="#000" stroke-width=".25"/>
<path d="M142.1 38.9l1.5-.5v1z" fill="#f8fcff"/>
<path d="M142.1 38.9l1.5-.5v1z" fill="none" stroke="#000" stroke-width=".21"/>
<path d="M143.9 38.4l1.5 .5-1.5 .5z" fill="#f8fcff"/>
<path d="M143.9 38.4l1.5 .5-1.5 .5z" fill="none" stroke="#000" stroke-width=".21"/>
<path d="M116.7 97.4h5.1" fill="none" stroke="#000" stroke-width=".25"/>
<path d="M120.2 96.9l1.6 .5-1.6 .5z" fill="#f8fcff"/>
<path d="M120.2 96.9l1.6 .5-1.6 .5z" fill="none" stroke="#000" stroke-width=".21"/>
<path d="M116.7 79.6h5.1" fill="none" stroke="#000" stroke-width=".25"/>
<path d="M120.2 79.1l1.6 .5-1.6 .5z" fill="#f8fcff"/>
<path d="M120.2 79.1l1.6 .5-1.6 .5zM121.8 79.1l1 .5-1 .5" fill="none" stroke="#000" stroke-width=".21"/>
<path d="M116.7 107.6h5.1" fill="none" stroke="#000" stroke-width=".25"/>
<path d="M120.2 107.1l1.6 .5-1.6 .5z" fill="#f8fcff"/>
<path d="M120.2 107.1l1.6 .5-1.6 .5z" fill="none" stroke="#000" stroke-width=".21"/>
<path d="M116.7 94.9h5.1" fill="none" stroke="#000" stroke-width=".25"/>
<path d="M120.2 94.4l1.6 .5-1.6 .5z" fill="#f8fcff"/>
<path d="M120.2 94.4l1.6 .5-1.6 .5z" fill="none" stroke="#000" stroke-width=".21"/>
<path d="M116.7 82.1h5.1" fill="none" stroke="#000" stroke-width=".25"/>
<path d="M120.2 81.6l1.6 .5-1.6 .6z" fill="#f8fcff"/>
<path d="M120.2 81.6l1.6 .5-1.6 .6zM121.8 81.6l1 .5-1 .6" fill="none" stroke="#000" stroke-width=".21"/>
<path d="M116.7 84.7h5.1" fill="none" stroke="#000" stroke-width=".25"/>
<path d="M120.2 84.2l1.6 .5-1.6 .5z" fill="#f8fcff"/>
<path d="M120.2 84.2l1.6 .5-1.6 .5z" fill="none" stroke="#000" stroke-width=".21"/>
<path d="M116.7 100h5.1" fill="none" stroke="#000" stroke-width=".25"/>
<path d="M120.2 99.4l1.6 .6-1.6 .5z" fill="#f8fcff"/>
<path d="M120.2 99.4l1.6 .6-1.6 .5z" fill="none" stroke="#000" stroke-width=".21"/>
<path d="M116.7 92.3h5.1" fill="none" stroke="#000" stroke-width=".25"/>
<path d="M120.2 91.8l1.6 .5-1.6 .5z" fill="#f8fcff"/>
<path d="M120.2 91.8l1.6 .5-1.6 .5z" fill="none" stroke="#000" stroke-width=".21"/>
<path d="M116.7 51.6h5.1" fill="none" stroke="#000" stroke-width=".25"/>
<path d="M120.2 51.1l1.6 .5-1.6 .5z" fill="#f8fcff"/>
<path d="M120.2 51.1l1.6 .5-1.6 .5z" fill="none" stroke="#000" stroke-width=".21"/>
<path d="M142.1 107.6h5.1" fill="none" stroke="#000" stroke-width=".25"/>
<path d="M142.1 107.6l1.5-.5v1z" fill="#f8fcff"/>
<path d="M142.1 107.6l1.5-.5v1z" fill="none" stroke="#000" stroke-width=".21"/>
<path d="M116.7 69.4h5.1" fill="none" stroke="#000" stroke-width=".25"/>
<path d="M120.2 68.9l1.6 .5-1.6 .5z" fill="#f8fcff"/>
<path d="M120.2 68.9l1.6 .5-1.6 .5z" fill="none" stroke="#000" stroke-width=".21"/>
<path d="M116.7 74.5h5.1" fill="none" stroke="#000" stroke-width=".25"/>
<path d="M120.2 74l1.6 .5-1.6 .5z" fill="#f8fcff"/>
<path d="M120.2 74l1.6 .5-1.6 .5z" fill="none" stroke="#000" stroke-width=".21"/>
<path d="M116.7 33.8h5.1" fill="none" stroke="#000" stroke-width=".25"/>
<path d="M120.2 33.3l1.6 .5-1.6 .5z" fill="#f8fcff"/>
<path d="M120.2 33.3l1.6 .5-1.6 .5z" fill="none" stroke="#000" stroke-width=".21"/>
<path d="M116.7 26.2h5.1" fill="none" stroke="#000" stroke-width=".25"/>
<path d="M120.2 25.7l1.6 .5-1.6 .5z" fill="#f8fcff"/>
<path d="M120.2 25.7l1.6 .5-1.6 .5z" fill="none" stroke="#000" stroke-width=".21"/>
<path d="M116.7 56.7h5.1" fill="none" stroke="#000" stroke-width=".25"/>
<path d="M120.2 56.2l1.6 .5-1.6 .5z" fill="#f8fcff"/>
<path d="M120.2 56.2l1.6 .5-1.6 .5z" fill="none" stroke="#000" stroke-width=".21"/>
<path d="M116.7 72h5.1" fill="none" stroke="#000" stroke-width=".25"/>
<path d="M120.2 71.5l1.6 .5-1.6 .5z" fill="#f8fcff"/>
<path d="M120.2 71.5l1.6 .5-1.6 .5z" fill="none" stroke="#000" stroke-width=".21"/>
<path d="M116.7 38.9h5.1" fill="none" stroke="#000" stroke-width=".25"/>
<path d="M120.2 38.4l1.6 .5-1.6 .5z" fill="#f8fcff"/>
<path d="M120.2 38.4l1.6 .5-1.6 .5z" fill="none" stroke="#000" stroke-width=".21"/>
<path d="M116.7 31.3h5.1" fill="none" stroke="#000" stroke-width=".25"/>
<path d="M120.2 30.8l1.6 .5-1.6 .5z" fill="#f8fcff"/>
<path d="M120.2 30.8l1.6 .5-1.6 .5z" fill="none" stroke="#000" stroke-width=".21"/>
<path d="M116.7 28.7h5.1" fill="none" stroke="#000" stroke-width=".25"/>
<path d="M120.2 28.2l1.6 .5-1.6 .5z" fill="#f8fcff"/>
<path d="M120.2 28.2l1.6 .5-1.6 .5z" fill="none" stroke="#000" stroke-width=".21"/>
<path d="M116.7 36.4h5.1" fill="none" stroke="#000" stroke-width=".25"/>
<path d="M120.2 35.9l1.6 .5-1.6 .5z" fill="#f8fcff"/>
<path d="M120.2 35.9l1.6 .5-1.6 .5z" fill="none" stroke="#000" stroke-width=".21"/>
<path d="M116.7 44h5.1" fill="none" stroke="#000" stroke-width=".25"/>
<path d="M120.2 43.5l1.6 .5-1.6 .5z" fill="#f8fcff"/>
<path d="M120.2 43.5l1.6 .5-1.6 .5z" fill="none" stroke="#000" stroke-width=".21"/>
<path d="M116.7 49.1h5.1" fill="none" stroke="#000" stroke-width=".25"/>
<path d="M120.2 48.6l1.6 .5-1.6 .5z" fill="#f8fcff"/>
<path d="M120.2 48.6l1.6 .5-1.6 .5z" fill="none" stroke="#000" stroke-width=".21"/>
<path d="M116.7 54.2h5.1" fill="none" stroke="#000" stroke-width=".25"/>
<path d="M120.2 53.7l1.6 .5-1.6 .5z" fill="#f8fcff"/>
<path d="M120.2 53.7l1.6 .5-1.6 .5z" fill="none" stroke="#000" stroke-width=".21"/>
<path d="M116.7 41.4h5.1" fill="none" stroke="#000" stroke-width=".25"/>
<path d="M120.2 40.9l1.6 .5-1.6 .6z" fill="#f8fcff"/>
<path d="M120.2 40.9l1.6 .5-1.6 .6z" fill="none" stroke="#000" stroke-width=".21"/>
<path d="M142.1 102.5h5.1" fill="none" stroke="#000" stroke-width=".25"/>
<path d="M142.1 102.5l1.5-.5v1z" fill="#f8fcff"/>
<path d="M142.1 102.5l1.5-.5v1z" fill="none" stroke="#000" stroke-width=".21"/>
<path d="M116.7 46.5h5.1" fill="none" stroke="#000" stroke-width=".25"/>
<path d="M120.2 46l1.6 .5-1.6 .5z" fill="#f8fcff"/>
<path d="M120.2 46l1.6 .5-1.6 .5z" fill="none" stroke="#000" stroke-width=".21"/>
<circle cx="251.5" cy="112.7" r=".51" fill="#000080"/>
<circle cx="251.5" cy="112.7" r=".51" fill="none" stroke="#000080" stroke-width=".21"/>
<circle cx="251.5" cy="115.2" r=".51" fill="#000080"/>
<circle cx="251.5" cy="115.2" r=".51" fill="none" stroke="#000080" stroke-width=".21"/>
<circle cx="282" cy="135.6" r=".51" fill="#000080"/>
<circle cx="282" cy="135.6" r=".51" fill="none" stroke="#000080" stroke-width=".21"/>
<circle cx="251.5" cy="143.2" r=".51" fill="#000080"/>
<circle cx="251.5" cy="143.2" r=".51" fill="none" stroke="#000080" stroke-width=".21"/>
<circle cx="282" cy="138.1" r=".51" fill="#000080"/>
<circle cx="282" cy="138.1" r=".51" fill="none" stroke="#000080" stroke-width=".21"/>
<circle cx="282" cy="115.2" r=".51" fill="#000080"/>
<circle cx="282" cy="115.2" r=".51" fill="none" stroke="#000080" stroke-width=".21"/>
<circle cx="251.5" cy="117.8" r=".51" fill="#000080"/>
<circle cx="251.5" cy="117.8" r=".51" fill="none" stroke="#000080" stroke-width=".21"/>
<circle cx="251.5" cy="120.3" r=".51" fill="#000080"/>
<circle cx="251.5" cy="120.3" r=".51" fill="none" stroke="#000080" stroke-width=".21"/>
<circle cx="282" cy="117.8" r=".51" fill="#000080"/>
<circle cx="282" cy="117.8" r=".51" fill="none" stroke="#000080" stroke-width=".21"/>
<circle cx="251.5" cy="122.8" r=".51" fill="#000080"/>
<circle cx="251.5" cy="122.8" r=".51" fill="none" stroke="#000080" stroke-width=".21"/>
<circle cx="282" cy="120.3" r=".51" fill="#000080"/>
<circle cx="282" cy="120.3" r=".51" fill="none" stroke="#000080" stroke-width=".21"/>
<circle cx="251.5" cy="145.8" r=".51" fill="#000080"/>
<circle cx="251.5" cy="145.8" r=".51" fill="none" stroke="#000080" stroke-width=".21"/>
<circle cx="282" cy="140.7" r=".51" fill="#000080"/>
<circle cx="282" cy="140.7" r=".51" fill="none" stroke="#000080" stroke-width=".21"/>
<circle cx="282" cy="122.8" r=".51" fill="#000080"/>
<circle cx="282" cy="122.8" r=".51" fill="none" stroke="#000080" stroke-width=".21"/>
<circle cx="282" cy="125.4" r=".51" fill="#000080"/>
<circle cx="282" cy="125.4" r=".51" fill="none" stroke="#000080" stroke-width=".21"/>
<circle cx="251.5" cy="127.9" r=".51" fill="#000080"/>
<circle cx="251.5" cy="127.9" r=".51" fill="none" stroke="#000080" stroke-width=".21"/>
<circle cx="251.5" cy="125.4" r=".51" fill="#000080"/>
<circle cx="251.5" cy="125.4" r=".51" fill="none" stroke="#000080" stroke-width=".21"/>
<circle cx="282" cy="127.9" r=".51" fill="#000080"/>
<circle cx="282" cy="127.9" r=".51" fill="none" stroke="#000080" stroke-width=".21"/>
<circle cx="282" cy="130.5" r=".51" fill="#000080"/>
<circle cx="282" cy="130.5" r=".51" fill="none" stroke="#000080" stroke-width=".21"/>
<circle cx="251.5" cy="148.3" r=".51" fill="#000080"/>
<circle cx="251.5" cy="148.3" r=".51" fill="none" stroke="#000080" stroke-width=".21"/>
<circle cx="282" cy="143.2" r=".51" fill="#000080"/>
<circle cx="282" cy="143.2" r=".51" fill="none" stroke="#000080" stroke-width=".21"/>
<circle cx="282" cy="133" r=".51" fill="#000080"/>
<circle cx="282" cy="133" r=".51" fill="none" stroke="#000080" stroke-width=".21"/>
<circle cx="251.5" cy="130.5" r=".51" fill="#000080"/>
<circle cx="251.5" cy="130.5" r=".51" fill="none" stroke="#000080" stroke-width=".21"/>
<circle cx="282" cy="145.8" r=".51" fill="#000080"/>
<circle cx="282" cy="145.8" r=".51" fill="none" stroke="#000080" stroke-width=".21"/>
<circle cx="282" cy="148.3" r=".51" fill="#000080"/>
<circle cx="282" cy="148.3" r=".51" fill="none" stroke="#000080" stroke-width=".21"/>
<circle cx="251.5" cy="150.8" r=".51" fill="#000080"/>
<circle cx="251.5" cy="150.8" r=".51" fill="none" stroke="#000080" stroke-width=".21"/>
<circle cx="251.5" cy="153.4" r=".51" fill="#000080"/>
<circle cx="251.5" cy="153.4" r=".51" fill="none" stroke="#000080" stroke-width=".21"/>
<circle cx="282" cy="150.8" r=".51" fill="#000080"/>
<circle cx="282" cy="150.8" r=".51" fill="none" stroke="#000080" stroke-width=".21"/>
<circle cx="282" cy="153.4" r=".51" fill="#000080"/>
<circle cx="282" cy="153.4" r=".51" fill="none" stroke="#000080" stroke-width=".21"/>
<circle cx="251.5" cy="155.9" r=".51" fill="#000080"/>
<circle cx="251.5" cy="155.9" r=".51" fill="none" stroke="#000080" stroke-width=".21"/>
<circle cx="251.5" cy="158.5" r=".51" fill="#000080"/>
<circle cx="251.5" cy="158.5" r=".51" fill="none" stroke="#000080" stroke-width=".21"/>
<circle cx="282" cy="155.9" r=".51" fill="#000080"/>
<circle cx="282" cy="155.9" r=".51" fill="none" stroke="#000080" stroke-width=".21"/>
<circle cx="282" cy="158.5" r=".51" fill="#000080"/>
<circle cx="282" cy="158.5" r=".51" fill="none" stroke="#000080" stroke-width=".21"/>
<circle cx="251.5" cy="161" r=".51" fill="#000080"/>
<circle cx="251.5" cy="161" r=".51" fill="none" stroke="#000080" stroke-width=".21"/>
<circle cx="282" cy="161" r=".51" fill="#000080"/>
<circle cx="282" cy="161" r=".51" fill="none" stroke="#000080" stroke-width=".21"/>
<circle cx="282" cy="163.6" r=".51" fill="#000080"/>
<circle cx="282" cy="163.6" r=".51" fill="none" stroke="#000080" stroke-width=".21"/>
<circle cx="251.5" cy="105" r=".51" fill="#000080"/>
<circle cx="251.5" cy="105" r=".51" fill="none" stroke="#000080" stroke-width=".21"/>
<path d="M256.6 102.5h20.4v63.6h-20.4z" fill-rule="evenodd" fill="#ffffb0"/>
<path d="M256.6 102.5h20.4v63.6h-20.4z" fill="none" stroke="#800000" stroke-width=".21"/>
<path d="M251.5 112.7h5.1" fill="none" stroke="#000" stroke-width=".25"/>
<circle cx="251.5" cy="112.7" r=".51" fill="#000080"/>
<circle cx="251.5" cy="112.7" r=".51" fill="none" stroke="#000080" stroke-width=".21"/>
<path d="M251.5 115.2h5.1" fill="none" stroke="#000" stroke-width=".25"/>
<circle cx="251.5" cy="115.2" r=".51" fill="#000080"/>
<circle cx="251.5" cy="115.2" r=".51" fill="none" stroke="#000080" stroke-width=".21"/>
<path d="M277 135.6h5" fill="none" stroke="#000" stroke-width=".25"/>
<circle cx="282" cy="135.6" r=".51" fill="#000080"/>
<circle cx="282" cy="135.6" r=".51" fill="none" stroke="#000080" stroke-width=".21"/>
<path d="M277 112.7h5M251.5 143.2h5.1" fill="none" stroke="#000" stroke-width=".25"/>
<circle cx="251.5" cy="143.2" r=".51" fill="#000080"/>
<circle cx="251.5" cy="143.2" r=".51" fill="none" stroke="#000080" stroke-width=".21"/>
<path d="M277 138.1h5" fill="none" stroke="#000" stroke-width=".25"/>
<circle cx="282" cy="138.1" r=".51" fill="#000080"/>
<circle cx="282" cy="138.1" r=".51" fill="none" stroke="#000080" stroke-width=".21"/>
<path d="M277 115.2h5" fill="none" stroke="#000" stroke-width=".25"/>
<circle cx="282" cy="115.2" r=".51" fill="#000080"/>
<circle cx="282" cy="115.2" r=".51" fill="none" stroke="#000080" stroke-width=".21"/>
<path d="M251.5 117.8h5.1" fill="none" stroke="#000" stroke-width=".25"/>
<circle cx="251.5" cy="117.8" r=".51" fill="#000080"/>
<circle cx="251.5" cy="117.8" r=".51" fill="none" stroke="#000080" stroke-width=".21"/>
<path d="M251.5 120.3h5.1" fill="none" stroke="#000" stroke-width=".25"/>
<circle cx="251.5" cy="120.3" r=".51" fill="#000080"/>
<circle cx="251.5" cy="120.3" r=".51" fill="none" stroke="#000080" stroke-width=".21"/>
<path d="M277 117.8h5" fill="none" stroke="#000" stroke-width=".25"/>
<circle cx="282" cy="117.8" r=".51" fill="#000080"/>
<circle cx="282" cy="117.8" r=".51" fill="none" stroke="#000080" stroke-width=".21"/>
<path d="M251.5 122.9h5.1" fill="none" stroke="#000" stroke-width=".25"/>
<circle cx="251.5" cy="122.8" r=".51" fill="#000080"/>
<circle cx="251.5" cy="122.8" r=".51" fill="none" stroke="#000080" stroke-width=".21"/>
<path d="M277 120.3h5" fill="none" stroke="#000" stroke-width=".25"/>
<circle cx="282" cy="120.3" r=".51" fill="#000080"/>
<circle cx="282" cy="120.3" r=".51" fill="none" stroke="#000080" stroke-width=".21"/>
<path d="M251.5 145.8h5.1" fill="none" stroke="#000" stroke-width=".25"/>
<circle cx="251.5" cy="145.8" r=".51" fill="#000080"/>
<circle cx="251.5" cy="145.8" r=".51" fill="none" stroke="#000080" stroke-width=".21"/>
<path d="M277 140.7h5" fill="none" stroke="#000" stroke-width=".25"/>
<circle cx="282" cy="140.7" r=".51" fill="#000080"/>
<circle cx="282" cy="140.7" r=".51" fill="none" stroke="#000080" stroke-width=".21"/>
<path d="M277 122.9h5" fill="none" stroke="#000" stroke-width=".25"/>
<circle cx="282" cy="122.8" r=".51" fill="#000080"/>
<circle cx="282" cy="122.8" r=".51" fill="none" stroke="#000080" stroke-width=".21"/>
<path d="M277 125.4h5" fill="none" stroke="#000" stroke-width=".25"/>
<circle cx="282" cy="125.4" r=".51" fill="#000080"/>
<circle cx="282" cy="125.4" r=".51" fill="none" stroke="#000080" stroke-width=".21"/>
<path d="M251.5 127.9h5.1" fill="none" stroke="#000" stroke-width=".25"/>
<circle cx="251.5" cy="127.9" r=".51" fill="#000080"/>
<circle cx="251.5" cy="127.9" r=".51" fill="none" stroke="#000080" stroke-width=".21"/>
<path d="M251.5 125.4h5.1" fill="none" stroke="#000" stroke-width=".25"/>
<circle cx="251.5" cy="125.4" r=".51" fill="#000080"/>
<circle cx="251.5" cy="125.4" r=".51" fill="none" stroke="#000080" stroke-width=".21"/>
<path d="M277 127.9h5" fill="none" stroke="#000" stroke-width=".25"/>
<circle cx="282" cy="127.9" r=".51" fill="#000080"/>
<circle cx="282" cy="127.9" r=".51" fill="none" stroke="#000080" stroke-width=".21"/>
<path d="M277 130.5h5" fill="none" stroke="#000" stroke-width=".25"/>
<circle cx="282" cy="130.5" r=".51" fill="#000080"/>
<circle cx="282" cy="130.5" r=".51" fill="none" stroke="#000080" stroke-width=".21"/>
<path d="M251.5 148.3h5.1" fill="none" stroke="#000" stroke-width=".25"/>
<circle cx="251.5" cy="148.3" r=".51" fill="#000080"/>
<circle cx="251.5" cy="148.3" r=".51" fill="none" stroke="#000080" stroke-width=".21"/>
<path d="M277 143.2h5" fill="none" stroke="#000" stroke-width=".25"/>
<circle cx="282" cy="143.2" r=".51" fill="#000080"/>
<circle cx="282" cy="143.2" r=".51" fill="none" stroke="#000080" stroke-width=".21"/>
<path d="M277 133h5" fill="none" stroke="#000" stroke-width=".25"/>
<circle cx="282" cy="133" r=".51" fill="#000080"/>
<circle cx="282" cy="133" r=".51" fill="none" stroke="#000080" stroke-width=".21"/>
<path d="M251.5 130.5h5.1" fill="none" stroke="#000" stroke-width=".25"/>
<circle cx="251.5" cy="130.5" r=".51" fill="#000080"/>
<circle cx="251.5" cy="130.5" r=".51" fill="none" stroke="#000080" stroke-width=".21"/>
<path d="M251.5 133h5.1M277 145.8h5" fill="none" stroke="#000" stroke-width=".25"/>
<circle cx="282" cy="145.8" r=".51" fill="#000080"/>
<circle cx="282" cy="145.8" r=".51" fill="none" stroke="#000080" stroke-width=".21"/>
<path d="M277 148.3h5" fill="none" stroke="#000" stroke-width=".25"/>
<circle cx="282" cy="148.3" r=".51" fill="#000080"/>
<circle cx="282" cy="148.3" r=".51" fill="none" stroke="#000080" stroke-width=".21"/>
<path d="M251.5 150.8h5.1" fill="none" stroke="#000" stroke-width=".25"/>
<circle cx="251.5" cy="150.8" r=".51" fill="#000080"/>
<circle cx="251.5" cy="150.8" r=".51" fill="none" stroke="#000080" stroke-width=".21"/>
<path d="M251.5 153.4h5.1" fill="none" stroke="#000" stroke-width=".25"/>
<circle cx="251.5" cy="153.4" r=".51" fill="#000080"/>
<circle cx="251.5" cy="153.4" r=".51" fill="none" stroke="#000080" stroke-width=".21"/>
<path d="M277 150.8h5" fill="none" stroke="#000" stroke-width=".25"/>
<circle cx="282" cy="150.8" r=".51" fill="#000080"/>
<circle cx="282" cy="150.8" r=".51" fill="none" stroke="#000080" stroke-width=".21"/>
<path d="M277 153.4h5" fill="none" stroke="#000" stroke-width=".25"/>
<circle cx="282" cy="153.4" r=".51" fill="#000080"/>
<circle cx="282" cy="153.4" r=".51" fill="none" stroke="#000080" stroke-width=".21"/>
<path d="M251.5 155.9h5.1" fill="none" stroke="#000" stroke-width=".25"/>
<circle cx="251.5" cy="155.9" r=".51" fill="#000080"/>
<circle cx="251.5" cy="155.9" r=".51" fill="none" stroke="#000080" stroke-width=".21"/>
<path d="M251.5 158.5h5.1" fill="none" stroke="#000" stroke-width=".25"/>
<circle cx="251.5" cy="158.5" r=".51" fill="#000080"/>
<circle cx="251.5" cy="158.5" r=".51" fill="none" stroke="#000080" stroke-width=".21"/>
<path d="M277 155.9h5" fill="none" stroke="#000" stroke-width=".25"/>
<circle cx="282" cy="155.9" r=".51" fill="#000080"/>
<circle cx="282" cy="155.9" r=".51" fill="none" stroke="#000080" stroke-width=".21"/>
<path d="M277 158.5h5" fill="none" stroke="#000" stroke-width=".25"/>
<circle cx="282" cy="158.5" r=".51" fill="#000080"/>
<circle cx="282" cy="158.5" r=".51" fill="none" stroke="#000080" stroke-width=".21"/>
<path d="M251.5 161h5.1" fill="none" stroke="#000" stroke-width=".25"/>
<circle cx="251.5" cy="161" r=".51" fill="#000080"/>
<circle cx="251.5" cy="161" r=".51" fill="none" stroke="#000080" stroke-width=".21"/>
<path d="M251.5 163.6h5.1M277 161h5" fill="none" stroke="#000" stroke-width=".25"/>
<circle cx="282" cy="161" r=".51" fill="#000080"/>
<circle cx="282" cy="161" r=".51" fill="none" stroke="#000080" stroke-width=".21"/>
<path d="M277 163.6h5" fill="none" stroke="#000" stroke-width=".25"/>
<circle cx="282" cy="163.6" r=".51" fill="#000080"/>
<circle cx="282" cy="163.6" r=".51" fill="none" stroke="#000080" stroke-width=".21"/>
<path d="M251.5 107.6h5.1" fill="none" stroke="#000" stroke-width=".25"/>
<path d="M255.1 107.1l1.5 .5-1.5 .5z" fill="#f8fcff"/>
<path d="M255.1 107.1l1.5 .5-1.5 .5z" fill="none" stroke="#000" stroke-width=".21"/>
<path d="M251.5 105.1h5.1" fill="none" stroke="#000" stroke-width=".25"/>
<path d="M255.1 104.5l1.5 .6-1.5 .5z" fill="#f8fcff"/>
<path d="M255.1 104.5l1.5 .6-1.5 .5z" fill="none" stroke="#000" stroke-width=".21"/>
<circle cx="251.5" cy="105" r=".51" fill="#000080"/>
<circle cx="251.5" cy="105" r=".51" fill="none" stroke="#000080" stroke-width=".21"/>
<path d="M124.3 117.8h15.3v12.7h-15.3z" fill-rule="evenodd" fill="#ffffb0"/>
<path d="M124.3 117.8h15.3v12.7h-15.3z" fill="none" stroke="#800000" stroke-width=".21"/>
<g fill="none" stroke="#000" stroke-width=".25">
<path d="M231.2 100h2.5M238.8 100h2.5M68.3 107.6h2.1M76.5 107.6h2M152.3 107.6h2M160.5 107.6h2M167.6 102.5h2M175.7 102.5h2M42.9 138.1h2M51.1 138.1h2M119.2 120.3h5.1M119.2 122.9h5.1"/>
<path d="M119.2 125.4h5.1M119.2 127.9h5.1M139.6 120.3h5.1M139.6 122.9h5.1M139.6 125.4h5.1M42.9 140.7h2M42.9 143.2h2M42.9 145.7h2M42.9 148.3h2M42.9 150.8h2M42.9 153.4h2M42.9 155.9h2"/>
<path d="M42.9 158.5h2M51.1 140.7h2M51.1 143.2h2M51.1 145.7h2M51.1 148.3h2M51.1 150.8h2M51.1 153.4h2M51.1 155.9h2M51.1 158.5h2M175.2 158.5v2M42.9 173.7h2M42.9 176.3h2"/>
<path d="M42.9 178.8h2M42.9 161h2M42.9 163.6h2M42.9 166.1h2M42.9 168.6h2M42.9 171.2h2M51.1 161h2M51.1 163.6h2M51.1 166.1h2M51.1 168.6h2M51.1 171.2h2M51.1 173.7h2"/>
<path d="M51.1 176.3h2M51.1 178.8h2M175.2 166.6v2M42.9 181.4h2M42.9 183.9h2M42.9 186.5h2M42.9 189h2M42.9 191.5h2M51.1 181.4h2M51.1 183.9h2M51.1 186.5h2M51.1 189h2"/>
<path d="M51.1 191.5h2"/>
</g>
<g fill="none" stroke="#800000" stroke-width=".25">
<path d="M191.7 31.3h2.6M193 31.3v2.5M191.7 61.8h2.6M193 61.8v2.5M279.5 92.3h5.1M280.3 93.1h3.5M281 93.9h2.1M281.8 94.6h.5M282 89.8v2.5M81.1 112.7h5.1M81.8 113.4h3.6M82.6 114.2h2"/>
<path d="M83.4 115h.5M83.6 110.1v2.6M165 112.7h5.1M165.8 113.4h3.5M166.5 114.2h2.1M167.3 115h.5M167.6 110.1v2.6M177.7 112.7h5.1M178.5 113.4h3.6M179.3 114.2h2M180 115h.5M180.3 110.1v2.6"/>
<path d="M191.7 107.6h2.6M193 107.6v2.5M191.7 138.1h2.6M193 138.1v2.6M279.5 168.6h5.1M280.3 169.4h3.5M281 170.2h2.1M281.8 170.9h.5M282 166.1v2.5"/>
</g>
<g fill="none" stroke="#f00" stroke-width=".21">
<path d="M63.3 24.9v.8M63.3 26.2v.8M63.3 27.5v.7M63.3 28.7v.8M63.3 30v.8M63.3 31.3v.8M63.3 32.5v.8M63.3 33.8v.8M63.3 35.1v.8M63.3 36.4v.8M63.3 37.6v.8M63.3 38.9v.8"/>
<path d="M64.1 23.6h-.8v.8M64.5 23.6h.8M65.8 23.6h.8M67.1 23.6h.8M68.3 23.6h.8M69.6 23.6h.8M70.9 23.6h.8M72.2 23.6h.8M73.4 23.6h.8M74.7 23.6h.8M76 23.6h.8M77.3 23.6h.7"/>
<path d="M78.5 23.6h.8M79.8 23.6h.8M81.1 23.6v.8M81.1 24.9v.8M81.1 26.2v.8M81.1 27.5v.7M81.1 28.7v.8M81.1 30v.8M81.1 31.3v.8M81.1 32.5v.8M81.1 33.8v.8M81.1 35.1v.8"/>
<path d="M81.1 36.4v.8M81.1 37.6v.8M81.1 38.9v.8M147.2 24.9v.8M147.2 26.2v.8M147.2 27.5v.7M147.2 28.7v.8M147.2 30v.8M147.2 31.3v.8M147.2 32.5v.8M147.2 33.8v.8M147.2 35.1v.8"/>
<path d="M147.2 36.4v.8M147.2 37.6v.8M147.2 38.9v.8M148 23.6h-.8v.8M148.5 23.6h.8M149.8 23.6h.7M151 23.6h.8M152.3 23.6h.8M153.6 23.6h.8M154.8 23.6h.8M156.1 23.6h.8M157.4 23.6h.8"/>
<path d="M158.7 23.6h.8M159.9 23.6h.8M161.2 23.6h.8M162.5 23.6h.8M163.7 23.6h.8M165 23.6v.8M165 24.9v.8M165 26.2v.8M165 27.5v.7M165 28.7v.8M165 30v.8M165 31.3v.8"/>
<path d="M165 32.5v.8M165 33.8v.8M165 35.1v.8M165 36.4v.8M165 37.6v.8M165 38.9v.8M63.3 40.2v.8M63.3 41.4v.8M63.3 42.7v.8M63.3 47v.8M63.3 48.3v.8M63.3 49.6v.7"/>
<path d="M63.3 50.8v.8M63.3 52.1v.8M63.3 53.4v.8M63.3 54.6v.8M63.3 55.9v.8M63.3 57.2v.8M63.3 58.5v.8M63.3 59.7v.8M63.3 46.5h.8M63.7 44h.8M64.5 46.5h.8M65 44h.8"/>
<path d="M65.8 46.5h.8M66.3 44h.8M67.1 46.5h.8M67.6 44h.7M68.3 46.5h.8M68.8 44h.8M69.6 46.5h.8M70.1 44h.8M70.9 46.5h.8M71.4 44h.8M72.2 46.5h.8M72.6 44h.8"/>
<path d="M73.4 46.5h.8M73.9 44h.8M74.7 46.5h.8M75.2 44h.8M76 46.5h.8M76.5 44h.8M77.3 46.5h.7M77.7 44h.8M78.5 46.5h.8M79 44h.8M79.8 46.5h.8M80.3 44h.8"/>
<path d="M81.1 40.2v.8M81.1 41.4v.8M81.1 42.7v.8M81.1 46.5h.8M82.3 46.5h.8M83.6 47v.8M83.6 48.3v.8M83.6 49.6v.7M83.6 50.8v.8M83.6 52.1v.8M83.6 53.4v.8M83.6 54.6v.8"/>
<path d="M83.6 55.9v.8M83.6 57.2v.8M83.6 58.5v.8M83.6 59.7v.8M147.2 46.5h.8M147.2 40.2v.8M147.2 41.4v.8M147.2 42.7v.8M147.2 47v.8M147.2 48.3v.8M147.2 49.6v.8M147.2 50.8v.8"/>
<path d="M147.2 52.1v.8M147.2 53.4v.8M147.2 54.6v.8M147.2 55.9v.8M147.2 57.2v.8M147.2 58.5v.8M147.2 59.7v.8M147.7 44h.8M148.5 46.5h.8M149 44h.8M149.8 46.5h.7M150.2 44h.8"/>
<path d="M151 46.5h.8M151.5 44h.8M152.3 46.5h.8M152.8 44h.8M153.6 46.5h.8M154 44h.8M154.8 46.5h.8M155.3 44h.8M156.1 46.5h.8M156.6 44h.8M157.4 46.5h.8M157.9 44h.8"/>
<path d="M158.7 46.5h.8M159.1 44h.8M159.9 46.5h.8M160.4 44h.8M161.2 46.5h.8M161.7 44h.8M162.5 46.5h.8M163 44h.7M163.7 46.5h.8M164.2 44h.8M165 46.5h.8M165 40.2v.8"/>
<path d="M165 41.4v.8M165 42.7v.8M166.3 46.5h.8M167.6 47v.8M167.6 48.3v.8M167.6 49.6v.8M167.6 50.8v.8M167.6 52.1v.8M167.6 53.4v.8M167.6 54.6v.8M167.6 55.9v.8M167.6 57.2v.8"/>
<path d="M167.6 58.5v.8M167.6 59.7v.8M63.3 61v.8M63.3 62.3v.8M63.3 63.5v.8M63.7 64.3h.8M65 64.3h.8M66.3 64.3h.8M67.6 64.3h.7M68.8 64.3h.8M70.1 64.3h.8M71.4 64.3h.8"/>
<path d="M72.6 64.3h.8M73.9 64.3h.8M75.2 64.3h.8M76.5 64.3h.8M77.7 64.3h.8M79 64.3h.8M80.3 64.3h.8M81.5 64.3h.8M83.6 63.5v.8h-.8M83.6 61v.8M83.6 62.3v.8M147.2 61v.8"/>
<path d="M147.2 62.3v.8M147.2 63.5v.8M147.7 64.3h.8M149 64.3h.8M150.2 64.3h.8M151.5 64.3h.8M152.8 64.3h.8M154 64.3h.8M155.3 64.3h.8M156.6 64.3h.8M157.9 64.3h.8M159.1 64.3h.8"/>
<path d="M160.4 64.3h.8M161.7 64.3h.8M163 64.3h.7M164.2 64.3h.8M165.5 64.3h.8M167.6 63.5v.8h-.8M167.6 61v.8M167.6 62.3v.8M34.3 119.3l2 2M36.3 119.3l-2 2M59.7 119.3l2 2M61.7 119.3l-2 2"/>
<path d="M118.2 119.3l2 2M120.2 119.3l-2 2M143.6 119.3l2.1 2M145.7 119.3l-2.1 2M34.3 121.8l2 2.1M34.3 124.4l2 2M34.3 126.9l2 2.1M36.3 121.8l-2 2.1M36.3 124.4l-2 2M36.3 126.9l-2 2.1M59.7 121.8l2 2.1M59.7 124.4l2 2"/>
<path d="M61.7 121.8l-2 2.1M61.7 124.4l-2 2M118.2 121.8l2 2.1M118.2 124.4l2 2M118.2 126.9l2 2.1M120.2 121.8l-2 2.1M120.2 124.4l-2 2M120.2 126.9l-2 2.1M143.6 121.8l2.1 2.1M143.6 124.4l2.1 2M145.7 121.8l-2.1 2.1M145.7 124.4l-2.1 2"/>
</g>
<path d="M64.5 24.1l1 1.8h-2zM148.5 24.1l1 1.8h-2zM64.5 47l1 1.8h-2zM148.5 47l1 1.8h-2z" fill="none" stroke="#f33" stroke-width=".21"/>
<g fill="none" stroke="#f00" stroke-width=".25">
<path d="M81.1 22.1v1.5M165 22.1v1.5M83.6 45v1.5M167.6 45v1.5"/>
<circle cx="81.1" cy="20.6" r="1.53"/>
<circle cx="165" cy="20.6" r="1.53"/>
<circle cx="83.6" cy="43.5" r="1.53"/>
<circle cx="167.6" cy="43.5" r="1.53"/>
</g>
<g fill="none" stroke="#00f" stroke-width=".25">
<path d="M233.7 100h2.1M235.8 98v4M236.7 100h2.1M236.7 98v4M70.4 106.6h6v2h-6zM154.4 106.6h6v2h-6zM169.7 101.5h6v2.1h-6zM45 137.1h6v2.1h-6zM45 139.7h6v2h-6zM45 142.2h6v2.1h-6zM45 144.8h6v2h-6zM45 147.3h6v2.1h-6z"/>
<path d="M45 149.9h6v2h-6zM45 152.4h6v2h-6zM45 154.9h6v2.1h-6zM45 157.5h6v2h-6zM45 160h6v2.1h-6zM45 162.6h6v2h-6zM45 165.1h6v2.1h-6zM45 167.7h6v2h-6zM45 170.2h6v2h-6zM45 172.8h6v2h-6zM45 175.3h6v2h-6zM45 177.8h6v2.1h-6z"/>
<path d="M174.2 160.5h2.1v6.1h-2.1zM45 180.4h6v2h-6zM45 182.9h6v2.1h-6zM45 185.5h6v2h-6zM45 188h6v2.1h-6zM45 190.6h6v2h-6z"/>
</g>
<circle cx="243.9" cy="112.7" r=".51" fill="#000080"/>
<circle cx="243.9" cy="112.7" r=".51" fill="none" stroke="#000080" stroke-width=".21"/>
<path d="M243.9 102.5v2.6M243.9 110.1v2.6" fill="none" stroke="#000" stroke-width=".25"/>
<circle cx="243.9" cy="112.7" r=".51" fill="#000080"/>
<circle cx="243.9" cy="112.7" r=".51" fill="none" stroke="#000080" stroke-width=".21"/>
<path d="M233.7 23.6h2.1M235.8 21.6v4M236.7 23.6h2.1M236.7 21.6v4M241.9 107.1h4M241.9 108.1h4M243.9 105.1v2M243.9 108.1v2" fill="none" stroke="#00f" stroke-width=".25"/>
<path d="M250.2 94.9h2.6M251.5 94.9v2.5M226.1 105.1h5.1M226.8 105.8h3.6M227.6 106.6h2M228.4 107.3h.5M228.6 102.5v2.6" fill="none" stroke="#800000" stroke-width=".25"/>
<path d="M231.2 23.6h2.5M238.8 23.6h2.5" fill="none" stroke="#000" stroke-width=".25"/>
<circle cx="243.9" cy="36.4" r=".51" fill="#000080"/>
<circle cx="243.9" cy="36.4" r=".51" fill="none" stroke="#000080" stroke-width=".21"/>
<path d="M243.9 26.2v2.5M243.9 33.8v2.6" fill="none" stroke="#000" stroke-width=".25"/>
<circle cx="243.9" cy="36.4" r=".51" fill="#000080"/>
<circle cx="243.9" cy="36.4" r=".51" fill="none" stroke="#000080" stroke-width=".21"/>
<path d="M241.9 30.8h4M241.9 31.8h4M243.9 28.7v2.1M243.9 31.8v2M97.9 152.9h2v6h-2zM97.9 168.2h2v6h-2z" fill="none" stroke="#00f" stroke-width=".25"/>
<g fill="none" stroke="#800000" stroke-width=".25">
<path d="M250.2 18.6h2.6M251.5 18.6v2.5M226.1 28.7h5.1M226.8 29.5h3.6M227.6 30.3h2M228.4 31h.5M228.6 26.2v2.5M97.6 145.7h2.5M98.9 145.7v2.6M98.9 178.8v2.6M116.7 163.6h2.5M119.2 162.3v2.5"/>
<path d="M96.3 181.4h5.1M97.1 182.1h3.6M97.9 182.9h2M98.6 183.7h.5"/>
</g>
<path d="M98.9 150.8v2M98.9 159v2M98.9 166.1v2M98.9 174.3v2" fill="none" stroke="#000" stroke-width=".25"/>
<circle cx="208.3" cy="112.7" r=".51" fill="#000080"/>
<circle cx="208.3" cy="112.7" r=".51" fill="none" stroke="#000080" stroke-width=".21"/>
<path d="M208.3 112.7v2.5M208.3 120.3v2.6" fill="none" stroke="#000" stroke-width=".25"/>
<circle cx="208.3" cy="112.7" r=".51" fill="#000080"/>
<circle cx="208.3" cy="112.7" r=".51" fill="none" stroke="#000080" stroke-width=".21"/>
<path d="M206.3 118.3h4M206.3 117.3h4M208.3 115.2v2.1M208.3 118.3v2" fill="none" stroke="#00f" stroke-width=".25"/>
<circle cx="198.1" cy="112.7" r=".51" fill="#000080"/>
<circle cx="198.1" cy="112.7" r=".51" fill="none" stroke="#000080" stroke-width=".21"/>
<path d="M198.1 112.7v2.5M198.1 120.3v2.6" fill="none" stroke="#000" stroke-width=".25"/>
<circle cx="198.1" cy="112.7" r=".51" fill="#000080"/>
<circle cx="198.1" cy="112.7" r=".51" fill="none" stroke="#000080" stroke-width=".21"/>
<path d="M196.1 118.3h4M196.1 117.3h4M198.1 115.2v2.1M198.1 118.3v2" fill="none" stroke="#00f" stroke-width=".25"/>
<circle cx="218.4" cy="112.7" r=".51" fill="#000080"/>
<circle cx="218.4" cy="112.7" r=".51" fill="none" stroke="#000080" stroke-width=".21"/>
<path d="M218.5 112.7v2.5M218.5 120.3v2.6" fill="none" stroke="#000" stroke-width=".25"/>
<circle cx="218.4" cy="112.7" r=".51" fill="#000080"/>
<circle cx="218.4" cy="112.7" r=".51" fill="none" stroke="#000080" stroke-width=".21"/>
<path d="M216.4 118.3h4.1M216.4 117.3h4.1M218.5 115.2v2.1M218.5 118.3v2" fill="none" stroke="#00f" stroke-width=".25"/>
<circle cx="228.6" cy="112.7" r=".51" fill="#000080"/>
<circle cx="228.6" cy="112.7" r=".51" fill="none" stroke="#000080" stroke-width=".21"/>
<path d="M228.6 112.7v2.5M228.6 120.3v2.6" fill="none" stroke="#000" stroke-width=".25"/>
<circle cx="228.6" cy="112.7" r=".51" fill="#000080"/>
<circle cx="228.6" cy="112.7" r=".51" fill="none" stroke="#000080" stroke-width=".21"/>
<path d="M226.6 118.3h4M226.6 117.3h4M228.6 115.2v2.1M228.6 118.3v2" fill="none" stroke="#00f" stroke-width=".25"/>
<g fill="none" stroke="#800000" stroke-width=".25">
<path d="M195.5 125.4h5.1M196.3 126.2h3.6M197.1 126.9h2M197.8 127.7h.6M198.1 122.9v2.5M205.7 125.4h5.1M206.5 126.2h3.5M207.3 126.9h2M208 127.7h.5M208.3 122.9v2.5M215.9 125.4h5.1M216.7 126.2h3.5"/>
<path d="M217.4 126.9h2.1M218.2 127.7h.5M218.5 122.9v2.5M226.1 125.4h5.1M226.8 126.2h3.6M227.6 126.9h2M228.4 127.7h.5M228.6 122.9v2.5"/>
</g>
<circle cx="208.3" cy="143.2" r=".51" fill="#000080"/>
<circle cx="208.3" cy="143.2" r=".51" fill="none" stroke="#000080" stroke-width=".21"/>
<path d="M208.3 143.2v2.6M208.3 150.8v2.6" fill="none" stroke="#000" stroke-width=".25"/>
<circle cx="208.3" cy="143.2" r=".51" fill="#000080"/>
<circle cx="208.3" cy="143.2" r=".51" fill="none" stroke="#000080" stroke-width=".21"/>
<path d="M206.3 148.8h4M206.3 147.8h4M208.3 145.8v2M208.3 148.8v2" fill="none" stroke="#00f" stroke-width=".25"/>
<circle cx="198.1" cy="143.2" r=".51" fill="#000080"/>
<circle cx="198.1" cy="143.2" r=".51" fill="none" stroke="#000080" stroke-width=".21"/>
<path d="M198.1 143.2v2.6M198.1 150.8v2.6" fill="none" stroke="#000" stroke-width=".25"/>
<circle cx="198.1" cy="143.2" r=".51" fill="#000080"/>
<circle cx="198.1" cy="143.2" r=".51" fill="none" stroke="#000080" stroke-width=".21"/>
<path d="M196.1 148.8h4M196.1 147.8h4M198.1 145.8v2M198.1 148.8v2" fill="none" stroke="#00f" stroke-width=".25"/>
<circle cx="218.4" cy="143.2" r=".51" fill="#000080"/>
<circle cx="218.4" cy="143.2" r=".51" fill="none" stroke="#000080" stroke-width=".21"/>
<path d="M218.5 143.2v2.6M218.5 150.8v2.6" fill="none" stroke="#000" stroke-width=".25"/>
<circle cx="218.4" cy="143.2" r=".51" fill="#000080"/>
<circle cx="218.4" cy="143.2" r=".51" fill="none" stroke="#000080" stroke-width=".21"/>
<path d="M216.4 148.8h4.1M216.4 147.8h4.1M218.5 145.8v2M218.5 148.8v2" fill="none" stroke="#00f" stroke-width=".25"/>
<circle cx="228.6" cy="143.2" r=".51" fill="#000080"/>
<circle cx="228.6" cy="143.2" r=".51" fill="none" stroke="#000080" stroke-width=".21"/>
<path d="M228.6 143.2v2.6M228.6 150.8v2.6" fill="none" stroke="#000" stroke-width=".25"/>
<circle cx="228.6" cy="143.2" r=".51" fill="#000080"/>
<circle cx="228.6" cy="143.2" r=".51" fill="none" stroke="#000080" stroke-width=".21"/>
<path d="M226.6 148.8h4M226.6 147.8h4M228.6 145.8v2M228.6 148.8v2" fill="none" stroke="#00f" stroke-width=".25"/>
<g fill="none" stroke="#800000" stroke-width=".25">
<path d="M195.5 155.9h5.1M196.3 156.7h3.6M197.1 157.5h2M197.8 158.2h.6M198.1 153.4v2.5M205.7 155.9h5.1M206.5 156.7h3.5M207.3 157.5h2M208 158.2h.5M208.3 153.4v2.5M215.9 155.9h5.1M216.7 156.7h3.5"/>
<path d="M217.4 157.5h2.1M218.2 158.2h.5M218.5 153.4v2.5M226.1 155.9h5.1M226.8 156.7h3.6M227.6 157.5h2M228.4 158.2h.5M228.6 153.4v2.5"/>
</g>
<circle cx="208.3" cy="66.9" r=".51" fill="#000080"/>
<circle cx="208.3" cy="66.9" r=".51" fill="none" stroke="#000080" stroke-width=".21"/>
<path d="M208.3 66.9v2.5M208.3 74.5v2.6" fill="none" stroke="#000" stroke-width=".25"/>
<circle cx="208.3" cy="66.9" r=".51" fill="#000080"/>
<circle cx="208.3" cy="66.9" r=".51" fill="none" stroke="#000080" stroke-width=".21"/>
<path d="M206.3 72.5h4M206.3 71.5h4M208.3 69.4v2.1M208.3 72.5v2" fill="none" stroke="#00f" stroke-width=".25"/>
<circle cx="198.1" cy="66.9" r=".51" fill="#000080"/>
<circle cx="198.1" cy="66.9" r=".51" fill="none" stroke="#000080" stroke-width=".21"/>
<path d="M198.1 66.9v2.5M198.1 74.5v2.6" fill="none" stroke="#000" stroke-width=".25"/>
<circle cx="198.1" cy="66.9" r=".51" fill="#000080"/>
<circle cx="198.1" cy="66.9" r=".51" fill="none" stroke="#000080" stroke-width=".21"/>
<path d="M196.1 72.5h4M196.1 71.5h4M198.1 69.4v2.1M198.1 72.5v2" fill="none" stroke="#00f" stroke-width=".25"/>
<circle cx="218.4" cy="66.9" r=".51" fill="#000080"/>
<circle cx="218.4" cy="66.9" r=".51" fill="none" stroke="#000080" stroke-width=".21"/>
<path d="M218.5 66.9v2.5M218.5 74.5v2.6" fill="none" stroke="#000" stroke-width=".25"/>
<circle cx="218.4" cy="66.9" r=".51" fill="#000080"/>
<circle cx="218.4" cy="66.9" r=".51" fill="none" stroke="#000080" stroke-width=".21"/>
<path d="M216.4 72.5h4.1M216.4 71.5h4.1M218.5 69.4v2.1M218.5 72.5v2" fill="none" stroke="#00f" stroke-width=".25"/>
<circle cx="228.6" cy="66.9" r=".51" fill="#000080"/>
<circle cx="228.6" cy="66.9" r=".51" fill="none" stroke="#000080" stroke-width=".21"/>
<path d="M228.6 66.9v2.5M228.6 74.5v2.6" fill="none" stroke="#000" stroke-width=".25"/>
<circle cx="228.6" cy="66.9" r=".51" fill="#000080"/>
<circle cx="228.6" cy="66.9" r=".51" fill="none" stroke="#000080" stroke-width=".21"/>
<path d="M226.6 72.5h4M226.6 71.5h4M228.6 69.4v2.1M228.6 72.5v2" fill="none" stroke="#00f" stroke-width=".25"/>
<g fill="none" stroke="#800000" stroke-width=".25">
<path d="M195.5 79.6h5.1M198.1 77.1v2.5M205.7 79.6h5.1M208.3 77.1v2.5M215.9 79.6h5.1M218.5 77.1v2.5M226.1 79.6h5.1M228.6 77.1v2.5M196.3 80.4h3.6M197.1 81.1h2M197.8 81.9h.6M206.5 80.4h3.5"/>
<path d="M207.3 81.1h2M208 81.9h.5M216.7 80.4h3.5M217.4 81.1h2.1M218.2 81.9h.5M226.8 80.4h3.6M227.6 81.1h2M228.4 81.9h.5"/>
</g>
<circle cx="208.3" cy="36.4" r=".51" fill="#000080"/>
<circle cx="208.3" cy="36.4" r=".51" fill="none" stroke="#000080" stroke-width=".21"/>
<path d="M208.3 36.4v2.5M208.3 44v2.5" fill="none" stroke="#000" stroke-width=".25"/>
<circle cx="208.3" cy="36.4" r=".51" fill="#000080"/>
<circle cx="208.3" cy="36.4" r=".51" fill="none" stroke="#000080" stroke-width=".21"/>
<path d="M208.3 38.9v2M206.3 42h4M206.3 40.9h4M208.3 42v2" fill="none" stroke="#00f" stroke-width=".25"/>
<circle cx="198.1" cy="36.4" r=".51" fill="#000080"/>
<circle cx="198.1" cy="36.4" r=".51" fill="none" stroke="#000080" stroke-width=".21"/>
<path d="M198.1 36.4v2.5M198.1 44v2.5" fill="none" stroke="#000" stroke-width=".25"/>
<circle cx="198.1" cy="36.4" r=".51" fill="#000080"/>
<circle cx="198.1" cy="36.4" r=".51" fill="none" stroke="#000080" stroke-width=".21"/>
<path d="M198.1 38.9v2M196.1 42h4M196.1 40.9h4M198.1 42v2" fill="none" stroke="#00f" stroke-width=".25"/>
<circle cx="218.4" cy="36.4" r=".51" fill="#000080"/>
<circle cx="218.4" cy="36.4" r=".51" fill="none" stroke="#000080" stroke-width=".21"/>
<path d="M218.5 36.4v2.5M218.5 44v2.5" fill="none" stroke="#000" stroke-width=".25"/>
<circle cx="218.4" cy="36.4" r=".51" fill="#000080"/>
<circle cx="218.4" cy="36.4" r=".51" fill="none" stroke="#000080" stroke-width=".21"/>
<path d="M218.5 38.9v2M216.4 42h4.1M216.4 40.9h4.1M218.5 42v2" fill="none" stroke="#00f" stroke-width=".25"/>
<circle cx="228.6" cy="36.4" r=".51" fill="#000080"/>
<circle cx="228.6" cy="36.4" r=".51" fill="none" stroke="#000080" stroke-width=".21"/>
<path d="M228.6 36.4v2.5M228.6 44v2.5" fill="none" stroke="#000" stroke-width=".25"/>
<circle cx="228.6" cy="36.4" r=".51" fill="#000080"/>
<circle cx="228.6" cy="36.4" r=".51" fill="none" stroke="#000080" stroke-width=".21"/>
<path d="M228.6 38.9v2M226.6 42h4M226.6 40.9h4M228.6 42v2M107.1 171.7h4M107.1 170.7h4M109.1 168.6v2.1M109.1 171.7v2" fill="none" stroke="#00f" stroke-width=".25"/>
<g fill="none" stroke="#800000" stroke-width=".25">
<path d="M195.5 49.1h5.1M196.3 49.8h3.6M197.1 50.6h2M197.8 51.4h.6M198.1 46.5v2.6M205.7 49.1h5.1M206.5 49.8h3.5M207.3 50.6h2M208 51.4h.5M208.3 46.5v2.6M215.9 49.1h5.1M216.7 49.8h3.5"/>
<path d="M217.4 50.6h2.1M218.2 51.4h.5M218.5 46.5v2.6M226.1 49.1h5.1M226.8 49.8h3.6M227.6 50.6h2M228.4 51.4h.5M228.6 46.5v2.6M109.1 178.8v2.6M106.5 181.4h5.1M107.3 182.1h3.5M108 182.9h2.1"/>
<path d="M108.8 183.7h.5"/>
</g>
<path d="M109.1 166.1v2.5M109.1 173.7v2.6" fill="none" stroke="#000" stroke-width=".25"/>
<circle cx="238.8" cy="143.2" r=".51" fill="#000080"/>
<circle cx="238.8" cy="143.2" r=".51" fill="none" stroke="#000080" stroke-width=".21"/>
<path d="M238.8 143.2v2.6M238.8 150.8v2.6" fill="none" stroke="#000" stroke-width=".25"/>
<circle cx="238.8" cy="143.2" r=".51" fill="#000080"/>
<circle cx="238.8" cy="143.2" r=".51" fill="none" stroke="#000080" stroke-width=".21"/>
<path d="M236.8 148.8h4M236.8 147.8h4M238.8 145.8v2M238.8 148.8v2" fill="none" stroke="#00f" stroke-width=".25"/>
<path d="M236.3 155.9h5M237 156.7h3.6M237.8 157.5h2M238.5 158.2h.6M238.8 153.4v2.5" fill="none" stroke="#800000" stroke-width=".25"/>
<circle cx="238.8" cy="112.7" r=".51" fill="#000080"/>
<circle cx="238.8" cy="112.7" r=".51" fill="none" stroke="#000080" stroke-width=".21"/>
<path d="M238.8 112.7v2.5M238.8 120.3v2.6" fill="none" stroke="#000" stroke-width=".25"/>
<circle cx="238.8" cy="112.7" r=".51" fill="#000080"/>
<circle cx="238.8" cy="112.7" r=".51" fill="none" stroke="#000080" stroke-width=".21"/>
<path d="M236.8 118.3h4M236.8 117.3h4M238.8 115.2v2.1M238.8 118.3v2" fill="none" stroke="#00f" stroke-width=".25"/>
<path d="M236.3 125.4h5M237 126.2h3.6M237.8 126.9h2M238.5 127.7h.6M238.8 122.9v2.5" fill="none" stroke="#800000" stroke-width=".25"/>
<circle cx="238.8" cy="66.9" r=".51" fill="#000080"/>
<circle cx="238.8" cy="66.9" r=".51" fill="none" stroke="#000080" stroke-width=".21"/>
<path d="M238.8 66.9v2.5M238.8 74.5v2.6" fill="none" stroke="#000" stroke-width=".25"/>
<circle cx="238.8" cy="66.9" r=".51" fill="#000080"/>
<circle cx="238.8" cy="66.9" r=".51" fill="none" stroke="#000080" stroke-width=".21"/>
<path d="M236.8 72.5h4M236.8 71.5h4M238.8 69.4v2.1M238.8 72.5v2" fill="none" stroke="#00f" stroke-width=".25"/>
<path d="M236.3 79.6h5M238.8 77.1v2.5M237 80.4h3.6M237.8 81.1h2M238.5 81.9h.6" fill="none" stroke="#800000" stroke-width=".25"/>
<circle cx="238.8" cy="36.4" r=".51" fill="#000080"/>
<circle cx="238.8" cy="36.4" r=".51" fill="none" stroke="#000080" stroke-width=".21"/>
<path d="M238.8 36.4v2.5M238.8 44v2.5" fill="none" stroke="#000" stroke-width=".25"/>
<circle cx="238.8" cy="36.4" r=".51" fill="#000080"/>
<circle cx="238.8" cy="36.4" r=".51" fill="none" stroke="#000080" stroke-width=".21"/>
<path d="M238.8 38.9v2M236.8 42h4M236.8 40.9h4M238.8 42v2" fill="none" stroke="#00f" stroke-width=".25"/>
<path d="M236.3 49.1h5M237 49.8h3.6M237.8 50.6h2M238.5 51.4h.6M238.8 46.5v2.6" fill="none" stroke="#800000" stroke-width=".25"/>
<g fill="none" stroke="#f00" stroke-width=".25">
<path d="M84.9 67.5h1l.5-.5h1l.5 .5h1.1M84.9 68.2h1l.5 .5h1l.5-.5h1.1M84.9 70.1h1l.5-.5h1l.5 .5h1.1M84.9 70.7h1l.5 .5h1l.5-.5h1.1M84.9 75.2h1l.5-.6h1l.5 .6h1.1M84.9 75.8h1l.5 .5h1l.5-.5h1.1M84.9 77.7h1l.5-.5h1l.5 .5h1.1M84.9 78.3h1l.5 .5h1l.5-.5h1.1M92.5 77.7h1l.5-.5h1.1l.5 .5h1M92.5 78.3h1l.5 .5h1.1l.5-.5h1M168.8 67.5h1.1l.5-.5h1l.5 .5h1M168.8 68.2h1.1l.5 .5h1l.5-.5h1"/>
<path d="M168.8 70.1h1.1l.5-.5h1l.5 .5h1M168.8 70.7h1.1l.5 .5h1l.5-.5h1M168.8 75.2h1.1l.5-.6h1l.5 .6h1M168.8 75.8h1.1l.5 .5h1l.5-.5h1M168.8 77.7h1.1l.5-.5h1l.5 .5h1M168.8 78.3h1.1l.5 .5h1l.5-.5h1M81.1 84.7h1.5M81.1 87.2v1.6M92.5 80.2h1l.5-.5h1.1l.5 .5h1M92.5 80.9h1l.5 .5h1.1l.5-.5h1M165 84.7h1.5M165 87.2v1.6"/>
<circle cx="81.1" cy="90.3" r="1.53"/>
<circle cx="84.1" cy="84.7" r="1.53"/>
<circle cx="165" cy="90.3" r="1.53"/>
<circle cx="168.1" cy="84.7" r="1.53"/>
</g>
<g fill="none" stroke="#d0a19e" stroke-width=".25">
<path d="M85.1 67.8h1.1l.5-.5h1l.5 .5h1M85.1 68.4h1.1l.5 .5h1l.5-.5h1M85.1 70.3h1.1l.5-.5h1l.5 .5h1M85.1 71h1.1l.5 .5h1l.5-.5h1M85.1 75.4h1.1l.5-.5h1l.5 .5h1M85.1 76h1.1l.5 .6h1l.5-.6h1M85.1 78h1.1l.5-.6h1l.5 .6h1M85.1 78.6h1.1l.5 .5h1l.5-.5h1M92.8 78h1l.5-.6h1l.5 .6h1M92.8 78.6h1l.5 .5h1l.5-.5h1M169.1 67.8h1l.5-.5h1l.5 .5h1.1M169.1 68.4h1l.5 .5h1l.5-.5h1.1"/>
<path d="M169.1 70.3h1l.5-.5h1l.5 .5h1.1M169.1 71h1l.5 .5h1l.5-.5h1.1M169.1 75.4h1l.5-.5h1l.5 .5h1.1M169.1 76h1l.5 .6h1l.5-.6h1.1M169.1 78h1l.5-.6h1l.5 .6h1.1M169.1 78.6h1l.5 .5h1l.5-.5h1.1M92.8 80.5h1l.5-.5h1l.5 .5h1M92.8 81.1h1l.5 .5h1l.5-.5h1"/>
</g>
<path d="M85.1 68.4l-1.5 1M85.1 71l-1.5 1M85.1 76l-1.5 1.1M85.1 78.6l-1.5 1M92.8 78.6l-1.6 1M169.1 68.4l-1.5 1M169.1 71l-1.5 1M169.1 76l-1.5 1.1M169.1 78.6l-1.5 1M92.8 81.1l-1.6 1" fill="none" stroke="#d0a19e" stroke-width=".21"/>
<path d="M84.9 68.2l-1.3 1.2M84.9 70.7l-1.3 1.3M84.9 75.8l-1.3 1.3M84.9 78.3l-1.3 1.3M92.5 78.3l-1.3 1.3M168.8 68.2l-1.2 1.2M168.8 70.7l-1.2 1.3M168.8 75.8l-1.2 1.3M168.8 78.3l-1.2 1.3M92.5 80.9l-1.3 1.2" fill="none" stroke="#f00" stroke-width=".21"/>
<path d="M282 36.4v53.4" fill="none" stroke="#000080" stroke-width=".25"/>
<circle cx="282" cy="38.9" r=".51" fill="#000080"/>
<circle cx="282" cy="38.9" r=".51" fill="none" stroke="#000080" stroke-width=".21"/>
<circle cx="282" cy="41.4" r=".51" fill="#000080"/>
<circle cx="282" cy="41.4" r=".51" fill="none" stroke="#000080" stroke-width=".21"/>
<circle cx="282" cy="44" r=".51" fill="#000080"/>
<circle cx="282" cy="44" r=".51" fill="none" stroke="#000080" stroke-width=".21"/>
<circle cx="282" cy="46.5" r=".51" fill="#000080"/>
<circle cx="282" cy="46.5" r=".51" fill="none" stroke="#000080" stroke-width=".21"/>
<circle cx="282" cy="49.1" r=".51" fill="#000080"/>
<circle cx="282" cy="49.1" r=".51" fill="none" stroke="#000080" stroke-width=".21"/>
<circle cx="282" cy="51.6" r=".51" fill="#000080"/>
<circle cx="282" cy="51.6" r=".51" fill="none" stroke="#000080" stroke-width=".21"/>
<circle cx="282" cy="54.2" r=".51" fill="#000080"/>
<circle cx="282" cy="54.2" r=".51" fill="none" stroke="#000080" stroke-width=".21"/>
<circle cx="282" cy="56.7" r=".51" fill="#000080"/>
<circle cx="282" cy="56.7" r=".51" fill="none" stroke="#000080" stroke-width=".21"/>
<circle cx="282" cy="59.3" r=".51" fill="#000080"/>
<circle cx="282" cy="59.3" r=".51" fill="none" stroke="#000080" stroke-width=".21"/>
<circle cx="282" cy="61.8" r=".51" fill="#000080"/>
<circle cx="282" cy="61.8" r=".51" fill="none" stroke="#000080" stroke-width=".21"/>
<circle cx="282" cy="64.3" r=".51" fill="#000080"/>
<circle cx="282" cy="64.3" r=".51" fill="none" stroke="#000080" stroke-width=".21"/>
<circle cx="282" cy="66.9" r=".51" fill="#000080"/>
<circle cx="282" cy="66.9" r=".51" fill="none" stroke="#000080" stroke-width=".21"/>
<circle cx="282" cy="69.4" r=".51" fill="#000080"/>
<circle cx="282" cy="69.4" r=".51" fill="none" stroke="#000080" stroke-width=".21"/>
<circle cx="282" cy="72" r=".51" fill="#000080"/>
<circle cx="282" cy="72" r=".51" fill="none" stroke="#000080" stroke-width=".21"/>
<circle cx="282" cy="74.5" r=".51" fill="#000080"/>
<circle cx="282" cy="74.5" r=".51" fill="none" stroke="#000080" stroke-width=".21"/>
<circle cx="282" cy="77.1" r=".51" fill="#000080"/>
<circle cx="282" cy="77.1" r=".51" fill="none" stroke="#000080" stroke-width=".21"/>
<circle cx="282" cy="79.6" r=".51" fill="#000080"/>
<circle cx="282" cy="79.6" r=".51" fill="none" stroke="#000080" stroke-width=".21"/>
<circle cx="282" cy="82.1" r=".51" fill="#000080"/>
<circle cx="282" cy="82.1" r=".51" fill="none" stroke="#000080" stroke-width=".21"/>
<circle cx="282" cy="84.7" r=".51" fill="#000080"/>
<circle cx="282" cy="84.7" r=".51" fill="none" stroke="#000080" stroke-width=".21"/>
<circle cx="282" cy="87.2" r=".51" fill="#000080"/>
<circle cx="282" cy="87.2" r=".51" fill="none" stroke="#000080" stroke-width=".21"/>
<path d="M282 112.7v53.4" fill="none" stroke="#000080" stroke-width=".25"/>
<circle cx="282" cy="115.2" r=".51" fill="#000080"/>
<circle cx="282" cy="115.2" r=".51" fill="none" stroke="#000080" stroke-width=".21"/>
<circle cx="282" cy="117.8" r=".51" fill="#000080"/>
<circle cx="282" cy="117.8" r=".51" fill="none" stroke="#000080" stroke-width=".21"/>
<circle cx="282" cy="120.3" r=".51" fill="#000080"/>
<circle cx="282" cy="120.3" r=".51" fill="none" stroke="#000080" stroke-width=".21"/>
<circle cx="282" cy="122.8" r=".51" fill="#000080"/>
<circle cx="282" cy="122.8" r=".51" fill="none" stroke="#000080" stroke-width=".21"/>
<circle cx="282" cy="125.4" r=".51" fill="#000080"/>
<circle cx="282" cy="125.4" r=".51" fill="none" stroke="#000080" stroke-width=".21"/>
<circle cx="282" cy="127.9" r=".51" fill="#000080"/>
<circle cx="282" cy="127.9" r=".51" fill="none" stroke="#000080" stroke-width=".21"/>
<circle cx="282" cy="130.5" r=".51" fill="#000080"/>
<circle cx="282" cy="130.5" r=".51" fill="none" stroke="#000080" stroke-width=".21"/>
<circle cx="282" cy="133" r=".51" fill="#000080"/>
<circle cx="282" cy="133" r=".51" fill="none" stroke="#000080" stroke-width=".21"/>
<circle cx="282" cy="135.6" r=".51" fill="#000080"/>
<circle cx="282" cy="135.6" r=".51" fill="none" stroke="#000080" stroke-width=".21"/>
<circle cx="282" cy="138.1" r=".51" fill="#000080"/>
<circle cx="282" cy="138.1" r=".51" fill="none" stroke="#000080" stroke-width=".21"/>
<circle cx="282" cy="140.7" r=".51" fill="#000080"/>
<circle cx="282" cy="140.7" r=".51" fill="none" stroke="#000080" stroke-width=".21"/>
<circle cx="282" cy="143.2" r=".51" fill="#000080"/>
<circle cx="282" cy="143.2" r=".51" fill="none" stroke="#000080" stroke-width=".21"/>
<circle cx="282" cy="145.8" r=".51" fill="#000080"/>
<circle cx="282" cy="145.8" r=".51" fill="none" stroke="#000080" stroke-width=".21"/>
<circle cx="282" cy="148.3" r=".51" fill="#000080"/>
<circle cx="282" cy="148.3" r=".51" fill="none" stroke="#000080" stroke-width=".21"/>
<circle cx="282" cy="150.8" r=".51" fill="#000080"/>
<circle cx="282" cy="150.8" r=".51" fill="none" stroke="#000080" stroke-width=".21"/>
<circle cx="282" cy="153.4" r=".51" fill="#000080"/>
<circle cx="282" cy="153.4" r=".51" fill="none" stroke="#000080" stroke-width=".21"/>
<circle cx="282" cy="155.9" r=".51" fill="#000080"/>
<circle cx="282" cy="155.9" r=".51" fill="none" stroke="#000080" stroke-width=".21"/>
<circle cx="282" cy="158.5" r=".51" fill="#000080"/>
<circle cx="282" cy="158.5" r=".51" fill="none" stroke="#000080" stroke-width=".21"/>
<circle cx="282" cy="161" r=".51" fill="#000080"/>
<circle cx="282" cy="161" r=".51" fill="none" stroke="#000080" stroke-width=".21"/>
<circle cx="282" cy="163.6" r=".51" fill="#000080"/>
<circle cx="282" cy="163.6" r=".51" fill="none" stroke="#000080" stroke-width=".21"/>
<g fill="none" stroke="#000080" stroke-width=".25">
<path d="M14.9 26.2h17.8M14.9 28.7h17.8M14.9 31.3h17.8M14.9 33.8h17.8M14.9 36.4h17.8M14.9 38.9h17.8M63.3 26.2h17.8M63.3 28.7h17.8M63.3 31.3h17.8M63.3 33.8h17.8M63.3 36.4h17.8M63.3 38.9h17.8"/>
<path d="M98.9 26.2h17.8M98.9 28.7h17.8M98.9 31.3h17.8M98.9 38.9h17.8M98.9 33.8h17.8M98.9 36.4h17.8M147.2 26.2h17.8M147.2 28.7h17.8M147.2 31.3h17.8M147.2 38.9h17.8M147.2 33.8h17.8M147.2 36.4h17.8"/>
<path d="M14.9 41.4h17.8M14.9 44h17.8M14.9 46.5h17.8M14.9 49.1h17.8M14.9 51.6h17.8M14.9 54.2h17.8M14.9 56.7h17.8M63.3 41.4h17.8M63.3 44h17.8M63.3 46.5h17.8M63.3 49.1h17.8M63.3 51.6h17.8"/>
<path d="M63.3 54.2h17.8M63.3 56.7h17.8M63.3 59.3h17.8M98.9 41.4h17.8M98.9 44h17.8M98.9 46.5h17.8M98.9 49.1h17.8M98.9 51.6h17.8M98.9 54.2h17.8M98.9 56.7h17.8M147.2 41.4h17.8M147.2 44h17.8"/>
<path d="M147.2 46.5h17.8M147.2 49.1h17.8M147.2 51.6h17.8M147.2 54.2h17.8M147.2 56.7h17.8M147.2 59.3h17.8M14.9 69.4h17.8M14.9 72h17.8M14.9 79.6h17.8M14.9 74.5h17.8M63.3 61.8h17.8M63.3 64.3h17.8"/>
<path d="M63.3 69.4h25.4M63.3 72h25.4M63.3 77.1h25.4M63.3 79.6h25.4M91.2 79.6h25.5M98.9 69.4h17.8M98.9 72h17.8M98.9 74.5h17.8M147.2 61.8h17.8M147.2 64.3h17.8M147.2 69.4h25.5M147.2 72h25.5"/>
<path d="M147.2 77.1h25.5M147.2 79.6h25.5M14.9 84.7h17.8M14.9 82.1h17.8M63.3 84.7h17.8M63.3 87.2h17.8M91.2 82.1h25.5M98.9 84.7h17.8M147.2 84.7h17.8M147.2 87.2h17.8M193 110.1v2.6h58.5v20.3"/>
</g>
<circle cx="198.1" cy="112.7" r=".51" fill="#000080"/>
<circle cx="198.1" cy="112.7" r=".51" fill="none" stroke="#000080" stroke-width=".21"/>
<circle cx="208.3" cy="112.7" r=".51" fill="#000080"/>
<circle cx="208.3" cy="112.7" r=".51" fill="none" stroke="#000080" stroke-width=".21"/>
<circle cx="218.4" cy="112.7" r=".51" fill="#000080"/>
<circle cx="218.4" cy="112.7" r=".51" fill="none" stroke="#000080" stroke-width=".21"/>
<circle cx="228.6" cy="112.7" r=".51" fill="#000080"/>
<circle cx="228.6" cy="112.7" r=".51" fill="none" stroke="#000080" stroke-width=".21"/>
<circle cx="238.8" cy="112.7" r=".51" fill="#000080"/>
<circle cx="238.8" cy="112.7" r=".51" fill="none" stroke="#000080" stroke-width=".21"/>
<circle cx="243.9" cy="112.7" r=".51" fill="#000080"/>
<circle cx="243.9" cy="112.7" r=".51" fill="none" stroke="#000080" stroke-width=".21"/>
<circle cx="251.5" cy="112.7" r=".51" fill="#000080"/>
<circle cx="251.5" cy="112.7" r=".51" fill="none" stroke="#000080" stroke-width=".21"/>
<circle cx="251.5" cy="115.2" r=".51" fill="#000080"/>
<circle cx="251.5" cy="115.2" r=".51" fill="none" stroke="#000080" stroke-width=".21"/>
<circle cx="251.5" cy="117.8" r=".51" fill="#000080"/>
<circle cx="251.5" cy="117.8" r=".51" fill="none" stroke="#000080" stroke-width=".21"/>
<circle cx="251.5" cy="120.3" r=".51" fill="#000080"/>
<circle cx="251.5" cy="120.3" r=".51" fill="none" stroke="#000080" stroke-width=".21"/>
<circle cx="251.5" cy="122.8" r=".51" fill="#000080"/>
<circle cx="251.5" cy="122.8" r=".51" fill="none" stroke="#000080" stroke-width=".21"/>
<circle cx="251.5" cy="125.4" r=".51" fill="#000080"/>
<circle cx="251.5" cy="125.4" r=".51" fill="none" stroke="#000080" stroke-width=".21"/>
<circle cx="251.5" cy="127.9" r=".51" fill="#000080"/>
<circle cx="251.5" cy="127.9" r=".51" fill="none" stroke="#000080" stroke-width=".21"/>
<circle cx="251.5" cy="130.5" r=".51" fill="#000080"/>
<circle cx="251.5" cy="130.5" r=".51" fill="none" stroke="#000080" stroke-width=".21"/>
<path d="M193 140.7v2.5h58.5v20.4" fill="none" stroke="#000080" stroke-width=".25"/>
<circle cx="198.1" cy="143.2" r=".51" fill="#000080"/>
<circle cx="198.1" cy="143.2" r=".51" fill="none" stroke="#000080" stroke-width=".21"/>
<circle cx="208.3" cy="143.2" r=".51" fill="#000080"/>
<circle cx="208.3" cy="143.2" r=".51" fill="none" stroke="#000080" stroke-width=".21"/>
<circle cx="218.4" cy="143.2" r=".51" fill="#000080"/>
<circle cx="218.4" cy="143.2" r=".51" fill="none" stroke="#000080" stroke-width=".21"/>
<circle cx="228.6" cy="143.2" r=".51" fill="#000080"/>
<circle cx="228.6" cy="143.2" r=".51" fill="none" stroke="#000080" stroke-width=".21"/>
<circle cx="238.8" cy="143.2" r=".51" fill="#000080"/>
<circle cx="238.8" cy="143.2" r=".51" fill="none" stroke="#000080" stroke-width=".21"/>
<circle cx="251.5" cy="143.2" r=".51" fill="#000080"/>
<circle cx="251.5" cy="143.2" r=".51" fill="none" stroke="#000080" stroke-width=".21"/>
<circle cx="251.5" cy="145.8" r=".51" fill="#000080"/>
<circle cx="251.5" cy="145.8" r=".51" fill="none" stroke="#000080" stroke-width=".21"/>
<circle cx="251.5" cy="148.3" r=".51" fill="#000080"/>
<circle cx="251.5" cy="148.3" r=".51" fill="none" stroke="#000080" stroke-width=".21"/>
<circle cx="251.5" cy="150.8" r=".51" fill="#000080"/>
<circle cx="251.5" cy="150.8" r=".51" fill="none" stroke="#000080" stroke-width=".21"/>
<circle cx="251.5" cy="153.4" r=".51" fill="#000080"/>
<circle cx="251.5" cy="153.4" r=".51" fill="none" stroke="#000080" stroke-width=".21"/>
<circle cx="251.5" cy="155.9" r=".51" fill="#000080"/>
<circle cx="251.5" cy="155.9" r=".51" fill="none" stroke="#000080" stroke-width=".21"/>
<circle cx="251.5" cy="158.5" r=".51" fill="#000080"/>
<circle cx="251.5" cy="158.5" r=".51" fill="none" stroke="#000080" stroke-width=".21"/>
<circle cx="251.5" cy="161" r=".51" fill="#000080"/>
<circle cx="251.5" cy="161" r=".51" fill="none" stroke="#000080" stroke-width=".21"/>
<path d="M193 33.8v2.6h58.5v20.3" fill="none" stroke="#000080" stroke-width=".25"/>
<circle cx="198.1" cy="36.4" r=".51" fill="#000080"/>
<circle cx="198.1" cy="36.4" r=".51" fill="none" stroke="#000080" stroke-width=".21"/>
<circle cx="208.3" cy="36.4" r=".51" fill="#000080"/>
<circle cx="208.3" cy="36.4" r=".51" fill="none" stroke="#000080" stroke-width=".21"/>
<circle cx="218.4" cy="36.4" r=".51" fill="#000080"/>
<circle cx="218.4" cy="36.4" r=".51" fill="none" stroke="#000080" stroke-width=".21"/>
<circle cx="228.6" cy="36.4" r=".51" fill="#000080"/>
<circle cx="228.6" cy="36.4" r=".51" fill="none" stroke="#000080" stroke-width=".21"/>
<circle cx="238.8" cy="36.4" r=".51" fill="#000080"/>
<circle cx="238.8" cy="36.4" r=".51" fill="none" stroke="#000080" stroke-width=".21"/>
<circle cx="243.9" cy="36.4" r=".51" fill="#000080"/>
<circle cx="243.9" cy="36.4" r=".51" fill="none" stroke="#000080" stroke-width=".21"/>
<circle cx="251.5" cy="36.4" r=".51" fill="#000080"/>
<circle cx="251.5" cy="36.4" r=".51" fill="none" stroke="#000080" stroke-width=".21"/>
<circle cx="251.5" cy="38.9" r=".51" fill="#000080"/>
<circle cx="251.5" cy="38.9" r=".51" fill="none" stroke="#000080" stroke-width=".21"/>
<circle cx="251.5" cy="41.4" r=".51" fill="#000080"/>
<circle cx="251.5" cy="41.4" r=".51" fill="none" stroke="#000080" stroke-width=".21"/>
<circle cx="251.5" cy="44" r=".51" fill="#000080"/>
<circle cx="251.5" cy="44" r=".51" fill="none" stroke="#000080" stroke-width=".21"/>
<circle cx="251.5" cy="46.5" r=".51" fill="#000080"/>
<circle cx="251.5" cy="46.5" r=".51" fill="none" stroke="#000080" stroke-width=".21"/>
<circle cx="251.5" cy="49.1" r=".51" fill="#000080"/>
<circle cx="251.5" cy="49.1" r=".51" fill="none" stroke="#000080" stroke-width=".21"/>
<circle cx="251.5" cy="51.6" r=".51" fill="#000080"/>
<circle cx="251.5" cy="51.6" r=".51" fill="none" stroke="#000080" stroke-width=".21"/>
<circle cx="251.5" cy="54.2" r=".51" fill="#000080"/>
<circle cx="251.5" cy="54.2" r=".51" fill="none" stroke="#000080" stroke-width=".21"/>
<path d="M193 64.3v2.6h58.5v20.3" fill="none" stroke="#000080" stroke-width=".25"/>
<circle cx="198.1" cy="66.9" r=".51" fill="#000080"/>
<circle cx="198.1" cy="66.9" r=".51" fill="none" stroke="#000080" stroke-width=".21"/>
<circle cx="208.3" cy="66.9" r=".51" fill="#000080"/>
<circle cx="208.3" cy="66.9" r=".51" fill="none" stroke="#000080" stroke-width=".21"/>
<circle cx="218.4" cy="66.9" r=".51" fill="#000080"/>
<circle cx="218.4" cy="66.9" r=".51" fill="none" stroke="#000080" stroke-width=".21"/>
<circle cx="228.6" cy="66.9" r=".51" fill="#000080"/>
<circle cx="228.6" cy="66.9" r=".51" fill="none" stroke="#000080" stroke-width=".21"/>
<circle cx="238.8" cy="66.9" r=".51" fill="#000080"/>
<circle cx="238.8" cy="66.9" r=".51" fill="none" stroke="#000080" stroke-width=".21"/>
<circle cx="251.5" cy="66.9" r=".51" fill="#000080"/>
<circle cx="251.5" cy="66.9" r=".51" fill="none" stroke="#000080" stroke-width=".21"/>
<circle cx="251.5" cy="69.4" r=".51" fill="#000080"/>
<circle cx="251.5" cy="69.4" r=".51" fill="none" stroke="#000080" stroke-width=".21"/>
<circle cx="251.5" cy="72" r=".51" fill="#000080"/>
<circle cx="251.5" cy="72" r=".51" fill="none" stroke="#000080" stroke-width=".21"/>
<circle cx="251.5" cy="74.5" r=".51" fill="#000080"/>
<circle cx="251.5" cy="74.5" r=".51" fill="none" stroke="#000080" stroke-width=".21"/>
<circle cx="251.5" cy="77.1" r=".51" fill="#000080"/>
<circle cx="251.5" cy="77.1" r=".51" fill="none" stroke="#000080" stroke-width=".21"/>
<circle cx="251.5" cy="79.6" r=".51" fill="#000080"/>
<circle cx="251.5" cy="79.6" r=".51" fill="none" stroke="#000080" stroke-width=".21"/>
<circle cx="251.5" cy="82.1" r=".51" fill="#000080"/>
<circle cx="251.5" cy="82.1" r=".51" fill="none" stroke="#000080" stroke-width=".21"/>
<circle cx="251.5" cy="84.7" r=".51" fill="#000080"/>
<circle cx="251.5" cy="84.7" r=".51" fill="none" stroke="#000080" stroke-width=".21"/>
<g fill="none" stroke="#000080" stroke-width=".25">
<path d="M14.9 100h17.8M14.9 97.4h17.8M14.9 94.9h17.8M14.9 92.3h17.8M98.9 100h17.8M98.9 97.4h17.8M98.9 94.9h17.8M98.9 92.3h17.8M251.5 97.4v10.2M14.9 107.6h17.8M63.3 107.6h5M63.3 102.5h17.8"/>
<path d="M78.5 107.6h5.1v2.5M98.9 107.6h17.8M147.2 107.6h5.1M147.2 102.5h20.4M162.5 107.6h5.1v2.5M177.7 102.5h2.6v7.6M25.1 138.1h17.8M53.1 138.1h17.8M25.1 158.5h17.8M25.1 155.9h17.8M25.1 153.4h17.8M25.1 150.8h17.8"/>
<path d="M25.1 148.3h17.8M25.1 145.7h17.8M25.1 143.2h17.8M25.1 140.7h17.8M53.1 158.5h17.8M53.1 155.9h17.8M53.1 153.4h17.8M53.1 150.8h17.8M53.1 148.3h17.8M53.1 145.7h17.8M53.1 143.2h17.8M53.1 140.7h17.8"/>
<path d="M157.4 158.5h17.8M25.1 168.6h17.8M25.1 166.1h17.8M25.1 163.6h17.8M25.1 161h17.8M25.1 171.2h17.8M25.1 176.3h17.8M25.1 173.7h17.8M25.1 178.8h17.8M53.1 168.6h17.8M53.1 166.1h17.8M53.1 163.6h17.8"/>
<path d="M53.1 161h17.8M53.1 176.3h17.8M53.1 173.7h17.8M53.1 171.2h17.8M53.1 178.8h17.8M157.4 168.6h17.8M25.1 189h17.8M25.1 186.5h17.8M25.1 183.9h17.8M25.1 181.4h17.8M25.1 191.5h17.8M53.1 189h17.8"/>
<path d="M53.1 186.5h17.8M53.1 183.9h17.8M53.1 181.4h17.8M53.1 191.5h17.8"/>
</g>
<circle cx="251.5" cy="105" r=".51" fill="#000080"/>
<circle cx="251.5" cy="105" r=".51" fill="none" stroke="#000080" stroke-width=".21"/>
<circle cx="251.5" cy="100" r=".51" fill="#000080"/>
<circle cx="251.5" cy="100" r=".51" fill="none" stroke="#000080" stroke-width=".21"/>
<path d="M241.3 100h10.2" fill="none" stroke="#000080" stroke-width=".25"/>
<circle cx="243.9" cy="100" r=".51" fill="#000080"/>
<circle cx="243.9" cy="100" r=".51" fill="none" stroke="#000080" stroke-width=".21"/>
<circle cx="251.5" cy="100" r=".51" fill="#000080"/>
<circle cx="251.5" cy="100" r=".51" fill="none" stroke="#000080" stroke-width=".21"/>
<path d="M243.9 100v2.5" fill="none" stroke="#000080" stroke-width=".25"/>
<circle cx="243.9" cy="100" r=".51" fill="#000080"/>
<circle cx="243.9" cy="100" r=".51" fill="none" stroke="#000080" stroke-width=".21"/>
<path d="M251.5 21.1v10.2" fill="none" stroke="#000080" stroke-width=".25"/>
<circle cx="251.5" cy="28.7" r=".51" fill="#000080"/>
<circle cx="251.5" cy="28.7" r=".51" fill="none" stroke="#000080" stroke-width=".21"/>
<circle cx="251.5" cy="23.6" r=".51" fill="#000080"/>
<circle cx="251.5" cy="23.6" r=".51" fill="none" stroke="#000080" stroke-width=".21"/>
<path d="M241.3 23.6h10.2" fill="none" stroke="#000080" stroke-width=".25"/>
<circle cx="243.9" cy="23.6" r=".51" fill="#000080"/>
<circle cx="243.9" cy="23.6" r=".51" fill="none" stroke="#000080" stroke-width=".21"/>
<circle cx="251.5" cy="23.6" r=".51" fill="#000080"/>
<circle cx="251.5" cy="23.6" r=".51" fill="none" stroke="#000080" stroke-width=".21"/>
<path d="M243.9 23.6v2.6" fill="none" stroke="#000080" stroke-width=".25"/>
<circle cx="243.9" cy="23.6" r=".51" fill="#000080"/>
<circle cx="243.9" cy="23.6" r=".51" fill="none" stroke="#000080" stroke-width=".21"/>
<path d="M231.2 23.6h-2.6v2.6M231.2 100h-2.6v2.5M98.9 148.3v2.5M98.9 161v5.1M98.9 176.3v2.5" fill="none" stroke="#000080" stroke-width=".25"/>
<circle cx="98.9" cy="163.6" r=".51" fill="#000080"/>
<circle cx="98.9" cy="163.6" r=".51" fill="none" stroke="#000080" stroke-width=".21"/>
<path d="M98.9 163.6h17.8" fill="none" stroke="#000080" stroke-width=".25"/>
<circle cx="98.9" cy="163.6" r=".51" fill="#000080"/>
<circle cx="98.9" cy="163.6" r=".51" fill="none" stroke="#000080" stroke-width=".21"/>
<circle cx="109.1" cy="163.6" r=".51" fill="#000080"/>
<circle cx="109.1" cy="163.6" r=".51" fill="none" stroke="#000080" stroke-width=".21"/>
<path d="M109.1 163.6v2.5M109.1 176.3v2.5" fill="none" stroke="#000080" stroke-width=".25"/>
<circle cx="109.1" cy="163.6" r=".51" fill="#000080"/>
<circle cx="109.1" cy="163.6" r=".51" fill="none" stroke="#000080" stroke-width=".21"/>
<g fill="none" stroke="#f00" stroke-width=".21">
<path d="M55.6 134.3v.8M55.6 135.6v.8M55.6 136.8v.8M55.6 138.1v.8M55.6 139.4v.8M56.4 133h-.8v.8M56.9 133h.8M58.2 133h.8M59.4 133h.8M60.7 133h.8M62 133h.8M63.3 133h.8"/>
<path d="M64.5 133h.8M65.8 133h.8M67.1 133h.8M68.3 133h.8M69.6 133h.8M70.9 133h.8M72.2 133h.8M73.4 133v.8M73.4 134.3v.8M73.4 135.6v.8M73.4 136.8v.8M73.4 138.1v.8"/>
<path d="M73.4 139.4v.8M55.6 140.7v.8M55.6 141.9v.8M55.6 143.2v.8M55.6 144.5v.8M55.6 145.7v.8M55.6 147v.8M55.6 148.3v.8M55.6 149.6v.8M55.6 150.8v.8M55.6 152.1v.8M55.6 153.4v.8"/>
<path d="M55.6 154.7v.7M55.6 155.9v.8M55.6 157.2v.8M55.6 158.5v.8M55.6 159.7v.8M73.4 140.7v.8M73.4 141.9v.8M73.4 143.2v.8M73.4 144.5v.8M73.4 145.7v.8M73.4 147v.8M73.4 148.3v.8"/>
<path d="M73.4 149.6v.8M73.4 150.8v.8M73.4 152.1v.8M73.4 153.4v.8M73.4 154.7v.7M73.4 155.9v.8M73.4 157.2v.8M73.4 158.5v.8M73.4 159.7v.8M55.6 161v.8M55.6 162.3v.8M55.6 163.6v.8"/>
<path d="M55.6 164.8v.8M55.6 166.1v.8M55.6 167.4v.8M55.6 168.6v.8M55.6 169.9v.8M55.6 171.2v.8M55.6 172.5v.8M55.6 173.7v.8M55.6 175v.8M55.6 176.3v.8M55.6 177.5v.9M55.6 178.8v.8"/>
<path d="M73.4 161v.8M73.4 162.3v.8M73.4 163.6v.8M73.4 164.8v.8M73.4 166.1v.8M73.4 167.4v.8M73.4 168.6v.8M73.4 169.9v.8M73.4 171.2v.8M73.4 172.5v.8M73.4 173.7v.8M73.4 175v.8"/>
<path d="M73.4 176.3v.8M73.4 177.5v.9M73.4 178.8v.8M55.6 180.1v.8M55.6 181.4v.8M55.6 182.6v.8M55.6 183.9v.8M55.6 185.2v.8M55.6 186.5v.8M55.6 187.7v.8M55.6 189v.8M55.6 190.3v.8"/>
<path d="M55.6 191.5v.8M55.6 192.8v.8M56.1 194.1h.8M57.4 194.1h.8M58.7 194.1h.7M59.9 194.1h.8M61.2 194.1h.8M62.5 194.1h.8M63.7 194.1h.8M65 194.1h.8M66.3 194.1h.8M67.6 194.1h.7"/>
<path d="M68.8 194.1h.8M70.1 194.1h.8M71.4 194.1h.8M72.6 194.1h.8M73.4 180.1v.8M73.4 181.4v.8M73.4 182.6v.8M73.4 183.9v.8M73.4 185.2v.8M73.4 186.5v.8M73.4 187.7v.8M73.4 189v.8"/>
<path d="M73.4 190.3v.8M73.4 191.5v.8M73.4 192.8v.8"/>
</g>
<path d="M56.9 133.5l1 1.8h-2z" fill="none" stroke="#f33" stroke-width=".21"/>
<g fill="none" stroke="#f00" stroke-width=".25">
<path d="M73.4 131.5v1.5"/>
<circle cx="73.4" cy="130" r="1.53"/>
</g>
<use href="#words"/>
</svg>
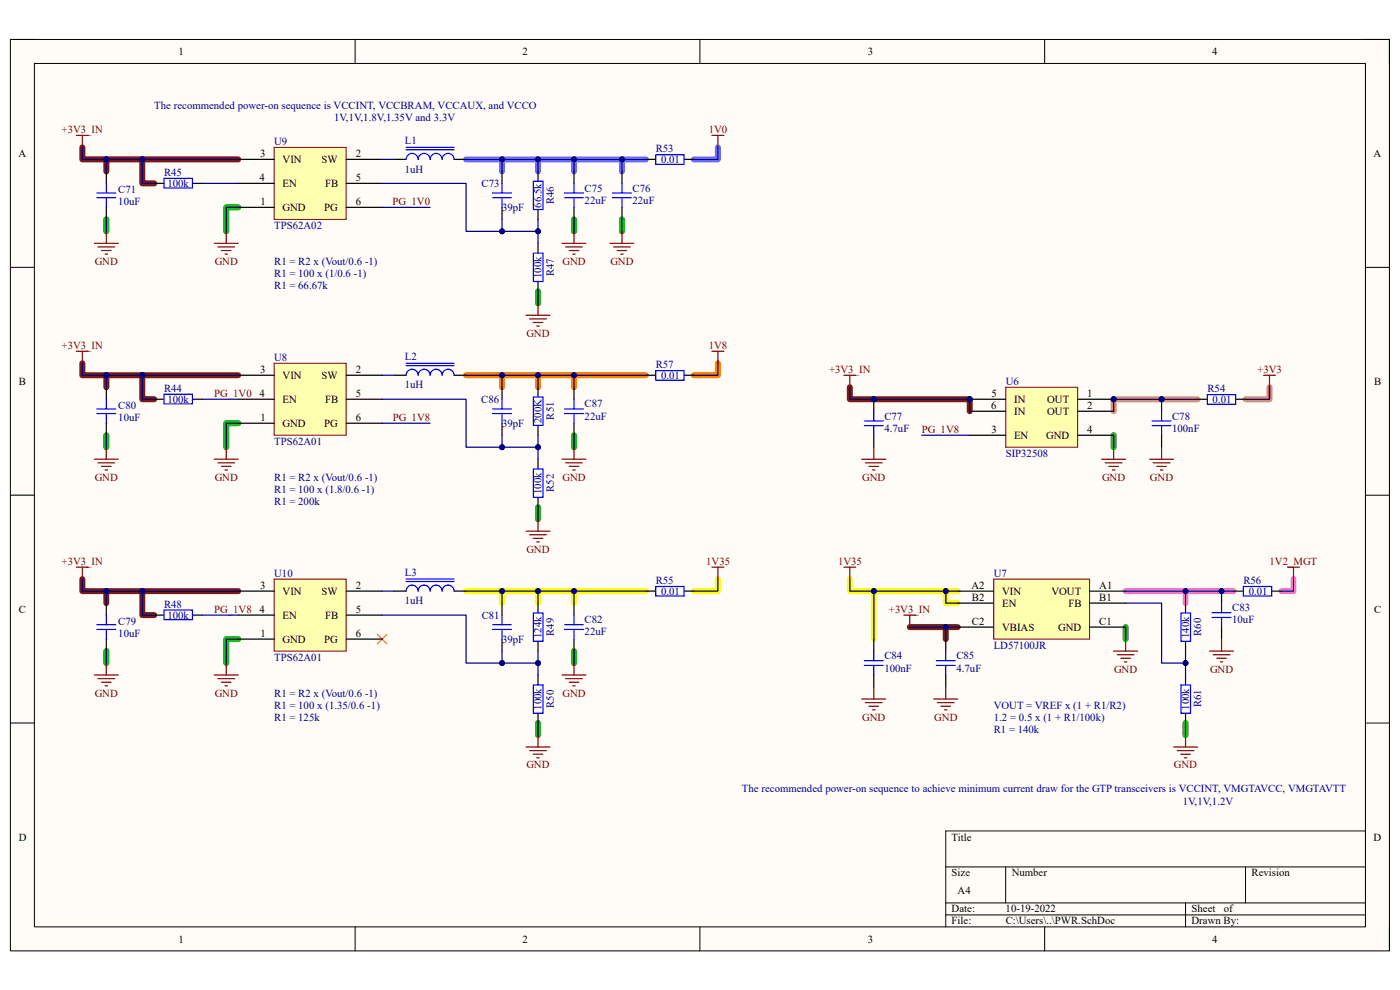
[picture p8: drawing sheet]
<svg xmlns="http://www.w3.org/2000/svg" width="297mm" height="210mm" viewBox="0 0 297 210" stroke-linecap="round" stroke-linejoin="round" font-family="sans-serif">
<defs><g id="words">
<g font-size="2.3">
<text x="37.9" y="11.7">1</text>
<text x="110.9" y="11.7">2</text>
<text x="184.1" y="11.7">3</text>
<text x="257.1" y="11.7">4</text>
<text x="3.9" y="33.3">A</text>
<text x="55.2" y="33.3">3</text>
<text x="59.9" y="34.6">VIN</text>
<text x="68.2" y="34.6">SW</text>
<text x="75.5" y="33.3">2</text>
<text x="291.4" y="33.3">A</text>
<text x="55.1" y="38.4">4</text>
<text x="59.9" y="39.7">EN</text>
<text x="69" y="39.7">FB</text>
<text x="75.5" y="38.4">5</text>
<text x="55.2" y="43.5">1</text>
<text x="59.9" y="44.7">GND</text>
<text x="68.7" y="44.7">PG</text>
<text x="75.5" y="43.5">6</text>
<text x="4" y="81.6">B</text>
<text x="55.2" y="79.1">3</text>
<text x="59.9" y="80.3">VIN</text>
<text x="68.2" y="80.3">SW</text>
<text x="75.5" y="79.1">2</text>
<text x="291.5" y="81.6">B</text>
<text x="55.1" y="84.2">4</text>
<text x="55.2" y="89.3">1</text>
<text x="59.9" y="85.4">EN</text>
<text x="69" y="85.4">FB</text>
<text x="75.5" y="84.2">5</text>
<text x="75.5" y="89.3">6</text>
<text x="210.3" y="86.7">6</text>
<text x="210.3" y="84.2">5</text>
<text x="215.1" y="85.4">IN</text>
<text x="215.1" y="88">IN</text>
<text x="222.2" y="85.4">OUT</text>
<text x="222.2" y="88">OUT</text>
<text x="230.6" y="84.2">1</text>
<text x="230.6" y="86.7">2</text>
<text x="59.9" y="90.6">GND</text>
<text x="68.7" y="90.6">PG</text>
<text x="210.4" y="91.8">3</text>
<text x="215.1" y="93.1">EN</text>
<text x="222" y="93.1">GND</text>
<text x="230.6" y="91.8">4</text>
<text x="55.2" y="124.9">3</text>
<text x="75.5" y="124.9">2</text>
<text x="206.1" y="124.9">A2</text>
<text x="233.2" y="124.9">A1</text>
<text x="4" y="130">C</text>
<text x="55.1" y="130">4</text>
<text x="59.9" y="126.2">VIN</text>
<text x="59.9" y="131.2">EN</text>
<text x="68.2" y="126.2">SW</text>
<text x="69" y="131.2">FB</text>
<text x="75.5" y="130">5</text>
<text x="206.2" y="127.4">B2</text>
<text x="212.6" y="126.2">VIN</text>
<text x="212.6" y="128.7">EN</text>
<text x="223.1" y="126.2">VOUT</text>
<text x="226.7" y="128.7">FB</text>
<text x="233.2" y="127.4">B1</text>
<text x="291.5" y="130">C</text>
<text x="55.2" y="135">1</text>
<text x="59.9" y="136.3">GND</text>
<text x="68.7" y="136.3">PG</text>
<text x="75.5" y="135">6</text>
<text x="206.2" y="132.5">C2</text>
<text x="212.6" y="133.8">VBIAS</text>
<text x="224.5" y="133.8">GND</text>
<text x="233.2" y="132.5">C1</text>
<text x="4" y="178.3">D</text>
<text x="201.9" y="178.3">Title</text>
<text x="291.4" y="178.3">D</text>
<text x="201.9" y="185.9">Size</text>
<text x="214.6" y="185.9">Number</text>
<text x="265.5" y="185.9">Revision</text>
<text x="203.2" y="189.7">A4</text>
<text x="201.9" y="193.5">Date:</text>
<text x="201.9" y="196.1">File:</text>
<text x="213.3" y="193.5">10-19-2022</text>
<text x="213.4" y="196.1">C:\Users\..\PWR.SchDoc</text>
<text x="252.8" y="193.5">Sheet</text>
<text x="252.8" y="196.1">Drawn By:</text>
<text x="259.6" y="193.5">of</text>
<text x="37.9" y="199.9">1</text>
<text x="110.9" y="199.9">2</text>
<text x="184.1" y="199.9">3</text>
<text x="257.1" y="199.9">4</text>
</g>
<g font-size="2.3" fill="#000080">
<text x="32.7" y="23.1">The recommended power-on sequence is VCCINT, VCCBRAM, VCCAUX, and VCCO</text>
<text x="70.9" y="25.7">1V,1V,1.8V,1.35V and 3.3V</text>
<text x="58.2" y="30.7">U9</text>
<text x="85.9" y="30.5">L1</text>
<text x="139.1" y="32.3">R53</text>
<text x="140.3" y="34.6">0.01</text>
<text x="25.1" y="40.9">C71</text>
<text x="34.8" y="37.3">R45</text>
<text x="35.5" y="39.7">100k</text>
<text x="85.9" y="36.6">1uH</text>
<text x="102.2" y="39.7">C73</text>
<text x="124" y="40.7">C75</text>
<text x="134.2" y="40.7">C76</text>
<text x="25.1" y="43.5">10uF</text>
<text x="106.5" y="44.7">39pF</text>
<text x="114.9" y="44" transform="rotate(-90 114.9 44)">66.5k</text>
<text x="117.5" y="43.3" transform="rotate(-90 117.5 43.3)">R46</text>
<text x="124" y="43.2">22uF</text>
<text x="134.2" y="43.2">22uF</text>
<text x="58.2" y="48.6">TPS62A02</text>
<text x="58.2" y="56.2">R1 = R2 x (Vout/0.6 -1)</text>
<text x="58.2" y="58.7">R1 = 100 x (1/0.6 -1)</text>
<text x="114.9" y="59" transform="rotate(-90 114.9 59)">100k</text>
<text x="117.5" y="58.6" transform="rotate(-90 117.5 58.6)">R47</text>
<text x="58.2" y="61.3">R1 = 66.67k</text>
<text x="58.2" y="76.5">U8</text>
<text x="85.9" y="76.3">L2</text>
<text x="34.8" y="83.1">R44</text>
<text x="85.9" y="82.4">1uH</text>
<text x="139.1" y="78.1">R57</text>
<text x="140.3" y="80.3">0.01</text>
<text x="213.4" y="81.6">U6</text>
<text x="256.2" y="83.2">R54</text>
<text x="25.1" y="86.7">C80</text>
<text x="25.1" y="89.3">10uF</text>
<text x="35.5" y="85.4">100k</text>
<text x="102.1" y="85.4">C86</text>
<text x="114.9" y="89.8" transform="rotate(-90 114.9 89.8)">200K</text>
<text x="117.5" y="89" transform="rotate(-90 117.5 89)">R51</text>
<text x="124" y="86.4">C87</text>
<text x="124" y="89">22uF</text>
<text x="187.6" y="89">C77</text>
<text x="248.7" y="89">C78</text>
<text x="257.3" y="85.4">0.01</text>
<text x="58.2" y="94.4">TPS62A01</text>
<text x="106.5" y="90.6">39pF</text>
<text x="187.6" y="91.6">4.7uF</text>
<text x="248.7" y="91.6">100nF</text>
<text x="58.2" y="102">R1 = R2 x (Vout/0.6 -1)</text>
<text x="213.4" y="96.9">SIP32508</text>
<text x="58.2" y="104.5">R1 = 100 x (1.8/0.6 -1)</text>
<text x="58.2" y="107.1">R1 = 200k</text>
<text x="114.9" y="104.8" transform="rotate(-90 114.9 104.8)">100k</text>
<text x="117.5" y="104.4" transform="rotate(-90 117.5 104.4)">R52</text>
<text x="58.2" y="122.3">U10</text>
<text x="85.9" y="122.1">L3</text>
<text x="139.1" y="123.9">R55</text>
<text x="210.8" y="122.3">U7</text>
<text x="263.8" y="123.9">R56</text>
<text x="34.8" y="128.9">R48</text>
<text x="35.5" y="131.2">100k</text>
<text x="85.9" y="128.2">1uH</text>
<text x="102.2" y="131.2">C81</text>
<text x="140.3" y="126.2">0.01</text>
<text x="261.4" y="129.7">C83</text>
<text x="264.9" y="126.2">0.01</text>
<text x="25.1" y="132.5">C79</text>
<text x="25.1" y="135">10uF</text>
<text x="106.5" y="136.3">39pF</text>
<text x="114.9" y="135.3" transform="rotate(-90 114.9 135.3)">124k</text>
<text x="117.5" y="134.9" transform="rotate(-90 117.5 134.9)">R49</text>
<text x="124" y="132.2">C82</text>
<text x="124" y="134.8">22uF</text>
<text x="210.8" y="137.6">LD57100JR</text>
<text x="252.3" y="135.3" transform="rotate(-90 252.3 135.3)">140k</text>
<text x="254.8" y="134.9" transform="rotate(-90 254.8 134.9)">R60</text>
<text x="261.4" y="132.2">10uF</text>
<text x="58.2" y="140.1">TPS62A01</text>
<text x="187.6" y="139.9">C84</text>
<text x="187.6" y="142.5">100nF</text>
<text x="202.9" y="139.9">C85</text>
<text x="202.9" y="142.5">4.7uF</text>
<text x="58.2" y="147.8">R1 = R2 x (Vout/0.6 -1)</text>
<text x="58.2" y="150.3">R1 = 100 x (1.35/0.6 -1)</text>
<text x="58.2" y="152.9">R1 = 125k</text>
<text x="114.9" y="150.6" transform="rotate(-90 114.9 150.6)">100k</text>
<text x="117.5" y="150.2" transform="rotate(-90 117.5 150.2)">R50</text>
<text x="210.8" y="150.3">VOUT = VREF x (1 + R1/R2)</text>
<text x="210.8" y="152.9">1.2 = 0.5 x (1 + R1/100k)</text>
<text x="210.8" y="155.4">R1 = 140k</text>
<text x="252.3" y="150.6" transform="rotate(-90 252.3 150.6)">100k</text>
<text x="254.8" y="150.1" transform="rotate(-90 254.8 150.1)">R61</text>
<text x="157.4" y="168.1">The recommended power-on sequence to achieve minimum current draw for the GTP transceivers is VCCINT, VMGTAVCC, VMGTAVTT</text>
<text x="251" y="170.7">1V,1V,1.2V</text>
</g>
<g font-size="2.3" fill="#800000">
<text x="13.1" y="28.2">+3V3_IN</text>
<text x="150.4" y="28.2">1V0</text>
<text x="83.3" y="43.5">PG_1V0</text>
<text x="20.1" y="56.2">GND</text>
<text x="45.6" y="56.2">GND</text>
<text x="119.3" y="56.2">GND</text>
<text x="129.5" y="56.2">GND</text>
<text x="111.7" y="71.5">GND</text>
<text x="13.1" y="74">+3V3_IN</text>
<text x="150.4" y="74">1V8</text>
<text x="175.9" y="79.1">+3V3_IN</text>
<text x="266.8" y="79.1">+3V3</text>
<text x="45.5" y="84.2">PG_1V0</text>
<text x="83.3" y="89.3">PG_1V8</text>
<text x="195.5" y="91.8">PG_1V8</text>
<text x="20.1" y="102">GND</text>
<text x="45.6" y="102">GND</text>
<text x="119.3" y="102">GND</text>
<text x="182.9" y="102">GND</text>
<text x="233.8" y="102">GND</text>
<text x="244" y="102">GND</text>
<text x="13.1" y="119.8">+3V3_IN</text>
<text x="111.7" y="117.3">GND</text>
<text x="149.8" y="119.8">1V35</text>
<text x="177.8" y="119.8">1V35</text>
<text x="269.3" y="119.8">1V2_MGT</text>
<text x="45.5" y="130">PG_1V8</text>
<text x="188.6" y="130">+3V3_IN</text>
<text x="236.3" y="142.7">GND</text>
<text x="256.7" y="142.7">GND</text>
<text x="20.1" y="147.8">GND</text>
<text x="45.6" y="147.8">GND</text>
<text x="119.3" y="147.8">GND</text>
<text x="182.9" y="152.9">GND</text>
<text x="198.2" y="152.9">GND</text>
<text x="111.7" y="163">GND</text>
<text x="249" y="163">GND</text>
</g>
</g></defs>
<path d="M2.2 8.4h292.6v193.3h-292.6z" fill-rule="evenodd" fill="#fffcf8"/>
<path d="M2.2 8.4h292.6v193.3h-292.6z" fill="none" stroke="#000" stroke-width=".21"/>
<path d="M7.3 13.5h282.4v183.1h-282.4z" fill-rule="evenodd" fill="#fffcf8"/>
<g fill="none" stroke="#000" stroke-width=".21">
<path d="M2.2 8.4h5.1M7.3 13.5h282.4v183.1h-282.4zM75.3 8.4v5.1M148.5 8.4v5.1M221.6 8.4v5.1M289.7 8.4h5.1v5.1M2.2 56.7h5.1M289.7 56.7h5.1M2.2 105h5.1M289.7 105.1h5.1M2.2 153.4h5.1M289.7 153.4h5.1"/>
<path d="M289.7 176.3h-89.1v20.3M75.3 196.6v5.1M148.5 196.6v5.1M200.6 183.9h89.1M200.6 191.5h89.1M200.6 194.1h89.1M213.4 183.9v7.6M221.6 196.6v5.1M251.5 191.5v5.1M264.2 183.9v7.6M294.8 196.6v5.1"/>
</g>
<path d="M17.5 31.3v2.5h5.1M30.2 33.8v5.1h2.5M50.5 33.8h-27.9v2.6M17.5 77.1v2.5h5.1M30.2 79.6v5.1h2.5M50.5 79.6h-27.9v2.5M180.3 82.1v2.6h25.4v2.5M17.5 122.9v2.5h5.1M30.2 125.4v5.1h2.5M50.5 125.4h-27.9v2.5M193 133h7.6M203.2 133h-2.6v2.6" fill="none" stroke="#781915" stroke-width="1.3"/>
<g fill="none" stroke="#00be00" stroke-width="1.3">
<path d="M22.6 46.5v2.6M50.5 44h-2.5v5.1M121.8 46.5v2.6M131.9 46.5v2.6M114.1 61.8v2.5M22.6 92.3v2.6M50.5 89.8h-2.5v5.1M121.8 92.3v2.6M236.3 92.3v2.6M114.1 107.6v2.5M22.6 138.1v2.6M50.5 135.6h-2.5v5.1"/>
<path d="M121.8 138.1v2.6M238.8 133v2.6M114.1 153.4v2.5M251.5 153.4v2.5"/>
</g>
<path d="M238.8 125.4h22.9M251.5 125.4v2.5M274.4 122.9v2.5h-2.5" fill="none" stroke="#ff6eff" stroke-width="1.3"/>
<path d="M254.1 84.7h-17.8v2.5M269.3 82.1v2.6h-5.1" fill="none" stroke="#ff6e6e" stroke-width="1.3"/>
<path d="M98.9 33.8h22.9v2.6M106.5 33.8v2.6M114.1 33.8v2.6M121.8 33.8h15.2M131.9 33.8v2.6M152.3 31.3v2.5h-5.1" fill="none" stroke="#6e6eff" stroke-width="1.3"/>
<path d="M98.9 125.4h22.9v2.5M106.5 125.4v2.5M114.1 125.4v2.5M121.8 125.4h15.2M152.3 122.9v2.5h-5.1M180.3 122.9v2.5h22.9M185.4 125.4v10.2M200.6 125.4v2.5h2.6" fill="none" stroke="#ff0" stroke-width="1.3"/>
<path d="M98.9 79.6h22.9v2.5M106.5 79.6v2.5M114.1 79.6v2.5M121.8 79.6h15.2M152.3 77.1v2.5h-5.1" fill="none" stroke="#fd8300" stroke-width="1.3"/>
<circle cx="236.3" cy="84.7" r=".51" fill="#000080"/>
<circle cx="236.3" cy="84.7" r=".51" fill="none" stroke="#000080" stroke-width=".21"/>
<circle cx="205.7" cy="84.7" r=".51" fill="#000080"/>
<circle cx="205.7" cy="84.7" r=".51" fill="none" stroke="#000080" stroke-width=".21"/>
<path d="M213.4 82.1h15.2v12.8h-15.2z" fill-rule="evenodd" fill="#ffffb0"/>
<path d="M213.4 82.1h15.2v12.8h-15.2z" fill="none" stroke="#800000" stroke-width=".21"/>
<path d="M228.6 84.7h7.7" fill="none" stroke="#000" stroke-width=".25"/>
<circle cx="236.3" cy="84.7" r=".51" fill="#000080"/>
<circle cx="236.3" cy="84.7" r=".51" fill="none" stroke="#000080" stroke-width=".21"/>
<path d="M205.7 92.3h7.7M205.7 84.7h7.7M228.6 87.2h7.7M228.6 92.3h7.7" fill="none" stroke="#000" stroke-width=".25"/>
<circle cx="205.7" cy="84.7" r=".51" fill="#000080"/>
<circle cx="205.7" cy="84.7" r=".51" fill="none" stroke="#000080" stroke-width=".21"/>
<path d="M205.7 87.2h7.7" fill="none" stroke="#000" stroke-width=".25"/>
<path d="M268.1 79.6h2.5M269.3 79.6v2.5M273.1 120.3h2.6M274.4 120.3v2.6" fill="none" stroke="#800000" stroke-width=".25"/>
<path d="M210.8 122.9h20.4v12.7h-20.4z" fill-rule="evenodd" fill="#ffffb0"/>
<path d="M210.8 122.9h20.4v12.7h-20.4z" fill="none" stroke="#800000" stroke-width=".21"/>
<path d="M203.2 125.4h7.6M203.2 127.9h7.6M203.2 133h7.6M231.2 125.4h7.6M231.2 127.9h7.6M231.2 133h7.6" fill="none" stroke="#000" stroke-width=".25"/>
<g fill="none" stroke="#800000" stroke-width=".25">
<path d="M179 79.6h2.6M180.3 79.6v2.5M233.7 97.4h5.1M234.5 98.2h3.5M235.2 98.9h2.1M236 99.7h.5M236.3 94.9v2.5M179 120.3h2.6M180.3 120.3v2.6M236.3 138.1h5M237 138.9h3.6M237.8 139.6h2"/>
<path d="M238.8 135.6v2.5M238.5 140.4h.6"/>
</g>
<circle cx="185.4" cy="84.7" r=".51" fill="#000080"/>
<circle cx="185.4" cy="84.7" r=".51" fill="none" stroke="#000080" stroke-width=".21"/>
<path d="M185.4 84.7v2.5M185.4 92.3v2.6" fill="none" stroke="#000" stroke-width=".25"/>
<circle cx="185.4" cy="84.7" r=".51" fill="#000080"/>
<circle cx="185.4" cy="84.7" r=".51" fill="none" stroke="#000080" stroke-width=".21"/>
<path d="M183.4 90.3h4M183.4 89.3h4M185.4 87.2v2.1M185.4 90.3v2" fill="none" stroke="#00f" stroke-width=".25"/>
<path d="M182.8 97.4h5.1M183.6 98.2h3.6M184.4 98.9h2M185.1 99.7h.5M185.4 94.9v2.5" fill="none" stroke="#800000" stroke-width=".25"/>
<circle cx="246.4" cy="84.7" r=".51" fill="#000080"/>
<circle cx="246.4" cy="84.7" r=".51" fill="none" stroke="#000080" stroke-width=".21"/>
<path d="M246.4 84.7v2.5M246.4 92.3v2.6" fill="none" stroke="#000" stroke-width=".25"/>
<circle cx="246.4" cy="84.7" r=".51" fill="#000080"/>
<circle cx="246.4" cy="84.7" r=".51" fill="none" stroke="#000080" stroke-width=".21"/>
<path d="M244.4 90.3h4M244.4 89.3h4M246.4 87.2v2.1M246.4 90.3v2M200.6 138.1v2.1M198.6 141.2h4M198.6 140.2h4M200.6 141.2v2" fill="none" stroke="#00f" stroke-width=".25"/>
<path d="M243.9 97.4h5.1M244.6 98.2h3.6M245.4 98.9h2M246.2 99.7h.5M246.4 94.9v2.5M198.1 148.3h5.1M198.9 149.1h3.5M199.6 149.8h2.1M200.4 150.6h.5M200.6 145.8v2.5" fill="none" stroke="#800000" stroke-width=".25"/>
<path d="M200.6 135.6v2.5M200.6 143.2v2.6" fill="none" stroke="#000" stroke-width=".25"/>
<circle cx="259.1" cy="125.4" r=".51" fill="#000080"/>
<circle cx="259.1" cy="125.4" r=".51" fill="none" stroke="#000080" stroke-width=".21"/>
<path d="M259.2 125.4v2.5M259.2 133v2.6" fill="none" stroke="#000" stroke-width=".25"/>
<circle cx="259.1" cy="125.4" r=".51" fill="#000080"/>
<circle cx="259.1" cy="125.4" r=".51" fill="none" stroke="#000080" stroke-width=".21"/>
<path d="M256.1 83.7h6v2.1h-6zM185.4 138.1v2.1M250.5 130h2.1v6h-2.1zM257.1 131h4.1M257.1 130h4.1M259.2 127.9v2.1M259.2 131v2M263.8 124.4h6v2.1h-6zM183.4 141.2h4M183.4 140.2h4M185.4 141.2v2M250.5 145.3h2.1v6h-2.1z" fill="none" stroke="#00f" stroke-width=".25"/>
<g fill="none" stroke="#800000" stroke-width=".25">
<path d="M256.6 138.1h5.1M257.4 138.9h3.5M258.1 139.6h2.1M259.2 135.6v2.5M182.8 148.3h5.1M183.6 149.1h3.6M184.4 149.8h2M185.1 150.6h.5M185.4 145.8v2.5M249 158.5h5.1M249.7 159.2h3.6M250.5 160h2"/>
<path d="M251.5 155.9v2.6M258.9 140.4h.5M251.3 160.8h.5"/>
</g>
<path d="M254.1 84.7h2M262.2 84.7h2M185.4 135.6v2.5M251.5 127.9v2M251.5 136.1v2M261.7 125.4h2M269.9 125.4h2M185.4 143.2v2.6M251.5 143.2v2M251.5 151.4v2" fill="none" stroke="#000" stroke-width=".25"/>
<path d="M58.2 31.3h15.2v15.2h-15.2z" fill-rule="evenodd" fill="#ffffb0"/>
<path d="M58.2 31.3h15.2v15.2h-15.2z" fill="none" stroke="#800000" stroke-width=".21"/>
<g fill="none" stroke="#000" stroke-width=".25">
<path d="M22.6 36.4v2.5M32.7 38.9h2M40.9 38.9h2M50.5 33.8h7.7M50.5 38.9h7.7M73.4 33.8h7.7M73.4 38.9h7.7M83.6 33.8h2.6M96.3 33.8h2.6M106.5 36.4v2.5M114.1 36.4v2M121.8 36.4v2.5"/>
<path d="M131.9 36.4v2.5M137 33.8h2M145.2 33.8h2M22.6 44v2.5M50.5 44h7.7M73.4 44h7.7M106.5 44v2.5M114.1 44.5v2M114.1 51.6v2M114.1 59.8v2M121.8 44v2.5M131.9 44v2.5"/>
</g>
<g fill="none" stroke="#800000" stroke-width=".25">
<path d="M16.2 28.7h2.5M17.5 28.7v2.6M151 28.7h2.6M152.3 28.7v2.6M20 51.6h5.1M20.8 52.4h3.5M21.5 53.1h2.1M22.3 53.9h.5M22.6 49.1v2.5M45.5 51.6h5M46.2 52.4h3.6M47 53.1h2"/>
<path d="M47.7 53.9h.5M48 49.1v2.5M119.2 51.6h5.1M120 52.4h3.5M120.8 53.1h2M121.5 53.9h.5M121.8 49.1v2.5M129.4 51.6h5.1M130.2 52.4h3.5M130.9 53.1h2.1M131.7 53.9h.5M131.9 49.1v2.5"/>
<path d="M111.6 66.9h5.1M112.4 67.6h3.5M113.1 68.4h2.1M113.9 69.2h.5M114.1 64.3v2.6"/>
</g>
<g fill="none" stroke="#00f" stroke-width=".25">
<path d="M22.6 38.9v2M34.8 37.8h6v2.1h-6zM86.2 33.8a1.27 1.27 0 0 1 1.2-1.3 1.27 1.27 0 0 1 1.3 1.3 1.27 1.27 0 0 1 1.3-1.3 1.27 1.27 0 0 1 1.2 1.3 1.27 1.27 0 0 1 1.3-1.3 1.27 1.27 0 0 1 1.3 1.3 1.27 1.27 0 0 1 1.3-1.3 1.27 1.27 0 0 1 1.2 1.3M86.2 31.8h10.1M86.2 31.3h10.1M106.5 38.9v2M113.2 38.4h2v6h-2zM121.8 38.9v2M131.9 38.9v2M139.1 32.8h6v2.1h-6zM20.6 41.9h4M20.6 40.9h4"/>
<path d="M22.6 41.9v2.1M104.5 41.9h4M104.5 40.9h4M106.5 41.9v2.1M113.2 53.7h2v6h-2zM119.8 41.9h4M119.8 40.9h4M121.8 41.9v2.1M129.9 41.9h4M129.9 40.9h4M131.9 41.9v2.1"/>
</g>
<path d="M58.2 122.9h15.2v15.2h-15.2z" fill-rule="evenodd" fill="#ffffb0"/>
<path d="M58.2 122.9h15.2v15.2h-15.2z" fill="none" stroke="#800000" stroke-width=".21"/>
<g fill="none" stroke="#000" stroke-width=".25">
<path d="M22.6 127.9v2.6M22.6 135.6v2.5M32.7 130.5h2M40.9 130.5h2M50.5 125.4h7.7M50.5 135.6h7.7M50.5 130.5h7.7M73.4 125.4h7.7M73.4 135.6h7.7M73.4 130.5h7.7M83.6 125.4h2.6M96.3 125.4h2.6"/>
<path d="M106.5 127.9v2.6M106.5 135.6v2.5M114.1 127.9v2M114.1 136.1v2M121.8 127.9v2.6M121.8 135.6v2.5M137 125.4h2M145.2 125.4h2M114.1 143.2v2M114.1 151.4v2"/>
</g>
<g fill="none" stroke="#800000" stroke-width=".25">
<path d="M16.2 120.3h2.5M17.5 120.3v2.6M151 120.3h2.6M152.3 120.3v2.6M20 143.2h5.1M20.8 144h3.5M21.5 144.7h2.1M22.3 145.5h.5M22.6 140.7v2.5M45.5 143.2h5M46.2 144h3.6M47 144.7h2"/>
<path d="M47.7 145.5h.5M48 140.7v2.5M111.6 158.5h5.1M112.4 159.2h3.5M113.1 160h2.1M114.1 155.9v2.6M119.2 143.2h5.1M120 144h3.5M120.8 144.7h2M121.5 145.5h.5M121.8 140.7v2.5M113.9 160.8h.5"/>
</g>
<g fill="none" stroke="#00f" stroke-width=".25">
<path d="M20.6 133.5h4M20.6 132.5h4M22.6 130.5v2M22.6 133.5v2.1M34.8 129.4h6v2.1h-6zM86.2 125.4a1.27 1.27 0 0 1 1.2-1.3 1.27 1.27 0 0 1 1.3 1.3 1.27 1.27 0 0 1 1.3-1.3 1.27 1.27 0 0 1 1.2 1.3 1.27 1.27 0 0 1 1.3-1.3 1.27 1.27 0 0 1 1.3 1.3 1.27 1.27 0 0 1 1.3-1.3 1.27 1.27 0 0 1 1.2 1.3M86.2 123.4h10.1M86.2 122.9h10.1M104.5 133.5h4M104.5 132.5h4M106.5 130.5v2M106.5 133.5v2.1"/>
<path d="M113.2 130h2v6h-2zM119.8 133.5h4M119.8 132.5h4M121.8 130.5v2M121.8 133.5v2.1M139.1 124.4h6v2.1h-6zM113.2 145.3h2v6h-2z"/>
</g>
<path d="M58.2 77.1h15.2v15.2h-15.2z" fill-rule="evenodd" fill="#ffffb0"/>
<path d="M58.2 77.1h15.2v15.2h-15.2z" fill="none" stroke="#800000" stroke-width=".21"/>
<g fill="none" stroke="#000" stroke-width=".25">
<path d="M50.5 79.6h7.7M73.4 79.6h7.7M83.6 79.6h2.6M96.3 79.6h2.6M137 79.6h2M145.2 79.6h2M22.6 89.8v2.5M22.6 82.1v2.6M32.7 84.7h2M40.9 84.7h2M50.5 84.7h7.7M50.5 89.8h7.7"/>
<path d="M73.4 84.7h7.7M73.4 89.8h7.7M106.5 82.1v2.6M106.5 89.8v2.5M114.1 82.1v2.1M114.1 90.3v2M114.1 97.4v2M121.8 82.1v2.6M121.8 89.8v2.5M114.1 105.6v2"/>
</g>
<g fill="none" stroke="#800000" stroke-width=".25">
<path d="M16.2 74.5h2.5M17.5 74.5v2.6M151 74.5h2.6M152.3 74.5v2.6M20 97.4h5.1M20.8 98.2h3.5M21.5 98.9h2.1M22.3 99.7h.5M22.6 94.9v2.5M45.5 97.4h5M46.2 98.2h3.6M47 98.9h2"/>
<path d="M47.7 99.7h.5M48 94.9v2.5M119.2 97.4h5.1M120 98.2h3.5M120.8 98.9h2M121.5 99.7h.5M121.8 94.9v2.5M111.6 112.7h5.1M112.4 113.4h3.5M113.1 114.2h2.1M113.9 115h.5M114.1 110.1v2.6"/>
<path d="M191.7 130.5h2.6M193 130.5v2.5"/>
</g>
<g fill="none" stroke="#00f" stroke-width=".25">
<path d="M86.2 79.6a1.27 1.27 0 0 1 1.2-1.3 1.27 1.27 0 0 1 1.3 1.3 1.27 1.27 0 0 1 1.3-1.3 1.27 1.27 0 0 1 1.2 1.3 1.27 1.27 0 0 1 1.3-1.3 1.27 1.27 0 0 1 1.3 1.3 1.27 1.27 0 0 1 1.3-1.3 1.27 1.27 0 0 1 1.2 1.3M86.2 77.6h10.1M86.2 77.1h10.1M139.1 78.6h6v2.1h-6zM20.6 87.7h4M20.6 86.7h4M22.6 84.7v2M22.6 87.7v2.1M34.8 83.6h6v2.1h-6zM104.5 87.7h4M104.5 86.7h4M106.5 84.7v2"/>
<path d="M106.5 87.7v2.1M113.2 99.5h2v6h-2zM113.2 84.2h2v6h-2zM119.8 87.7h4M119.8 86.7h4M121.8 84.7v2M121.8 87.7v2.1"/>
</g>
<path d="M80.1 134.6l2 2M82.1 134.6l-2 2" fill="none" stroke="#f00" stroke-width=".21"/>
<path d="M180.3 82.1v2.6h25.4v2.5" fill="none" stroke="#000080" stroke-width=".25"/>
<circle cx="205.7" cy="84.7" r=".51" fill="#000080"/>
<circle cx="205.7" cy="84.7" r=".51" fill="none" stroke="#000080" stroke-width=".21"/>
<circle cx="185.4" cy="84.7" r=".51" fill="#000080"/>
<circle cx="185.4" cy="84.7" r=".51" fill="none" stroke="#000080" stroke-width=".21"/>
<path d="M195.5 92.3h10.2M236.3 92.3v2.6M238.8 125.4h22.9M238.8 133v2.6" fill="none" stroke="#000080" stroke-width=".25"/>
<circle cx="251.5" cy="125.4" r=".51" fill="#000080"/>
<circle cx="251.5" cy="125.4" r=".51" fill="none" stroke="#000080" stroke-width=".21"/>
<circle cx="259.1" cy="125.4" r=".51" fill="#000080"/>
<circle cx="259.1" cy="125.4" r=".51" fill="none" stroke="#000080" stroke-width=".21"/>
<path d="M254.1 84.7h-17.8v2.5M274.4 122.9v2.5h-2.5" fill="none" stroke="#000080" stroke-width=".25"/>
<circle cx="236.3" cy="84.7" r=".51" fill="#000080"/>
<circle cx="236.3" cy="84.7" r=".51" fill="none" stroke="#000080" stroke-width=".21"/>
<circle cx="246.4" cy="84.7" r=".51" fill="#000080"/>
<circle cx="246.4" cy="84.7" r=".51" fill="none" stroke="#000080" stroke-width=".21"/>
<path d="M269.3 82.1v2.6h-5.1M203.2 133h-2.6v2.6" fill="none" stroke="#000080" stroke-width=".25"/>
<circle cx="200.6" cy="133" r=".51" fill="#000080"/>
<circle cx="200.6" cy="133" r=".51" fill="none" stroke="#000080" stroke-width=".21"/>
<path d="M251.5 138.1v2.6M251.5 153.4v2.5" fill="none" stroke="#000080" stroke-width=".25"/>
<circle cx="251.5" cy="140.7" r=".51" fill="#000080"/>
<circle cx="251.5" cy="140.7" r=".51" fill="none" stroke="#000080" stroke-width=".21"/>
<path d="M251.5 125.4v2.5" fill="none" stroke="#000080" stroke-width=".25"/>
<circle cx="251.5" cy="125.4" r=".51" fill="#000080"/>
<circle cx="251.5" cy="125.4" r=".51" fill="none" stroke="#000080" stroke-width=".21"/>
<path d="M238.8 127.9h7.6v12.8h5.1v2.5" fill="none" stroke="#000080" stroke-width=".25"/>
<circle cx="251.5" cy="140.7" r=".51" fill="#000080"/>
<circle cx="251.5" cy="140.7" r=".51" fill="none" stroke="#000080" stroke-width=".21"/>
<path d="M81.1 33.8h2.5M114.1 33.8v2.6M22.6 46.5v2.6M50.5 44h-2.5v5.1M121.8 46.5v2.6" fill="none" stroke="#000080" stroke-width=".25"/>
<circle cx="114.1" cy="33.8" r=".51" fill="#000080"/>
<circle cx="114.1" cy="33.8" r=".51" fill="none" stroke="#000080" stroke-width=".21"/>
<path d="M106.5 33.8v2.6" fill="none" stroke="#000080" stroke-width=".25"/>
<circle cx="106.5" cy="33.8" r=".51" fill="#000080"/>
<circle cx="106.5" cy="33.8" r=".51" fill="none" stroke="#000080" stroke-width=".21"/>
<path d="M106.5 46.5v2.6M114.1 61.8v2.5" fill="none" stroke="#000080" stroke-width=".25"/>
<circle cx="106.5" cy="49.1" r=".51" fill="#000080"/>
<circle cx="106.5" cy="49.1" r=".51" fill="none" stroke="#000080" stroke-width=".21"/>
<path d="M131.9 33.8v2.6M131.9 46.5v2.6" fill="none" stroke="#000080" stroke-width=".25"/>
<circle cx="132" cy="33.8" r=".51" fill="#000080"/>
<circle cx="132" cy="33.8" r=".51" fill="none" stroke="#000080" stroke-width=".21"/>
<path d="M17.5 31.3v2.5h5.1M152.3 31.3v2.5h-5.1M81.1 44h10.1" fill="none" stroke="#000080" stroke-width=".25"/>
<circle cx="22.6" cy="33.8" r=".51" fill="#000080"/>
<circle cx="22.6" cy="33.8" r=".51" fill="none" stroke="#000080" stroke-width=".21"/>
<path d="M42.9 38.9h7.6M22.6 138.1v2.6M50.5 135.6h-2.5v5.1M81.1 125.4h2.5M114.1 125.4v2.5M121.8 138.1v2.6" fill="none" stroke="#000080" stroke-width=".25"/>
<circle cx="114.1" cy="125.4" r=".51" fill="#000080"/>
<circle cx="114.1" cy="125.4" r=".51" fill="none" stroke="#000080" stroke-width=".21"/>
<path d="M106.5 125.4v2.5" fill="none" stroke="#000080" stroke-width=".25"/>
<circle cx="106.5" cy="125.4" r=".51" fill="#000080"/>
<circle cx="106.5" cy="125.4" r=".51" fill="none" stroke="#000080" stroke-width=".21"/>
<path d="M106.5 138.1v2.6M114.1 153.4v2.5" fill="none" stroke="#000080" stroke-width=".25"/>
<circle cx="106.5" cy="140.7" r=".51" fill="#000080"/>
<circle cx="106.5" cy="140.7" r=".51" fill="none" stroke="#000080" stroke-width=".21"/>
<path d="M17.5 122.9v2.5h5.1M152.3 122.9v2.5h-5.1" fill="none" stroke="#000080" stroke-width=".25"/>
<circle cx="22.6" cy="125.4" r=".51" fill="#000080"/>
<circle cx="22.6" cy="125.4" r=".51" fill="none" stroke="#000080" stroke-width=".21"/>
<path d="M30.2 33.8v5.1h2.5" fill="none" stroke="#000080" stroke-width=".25"/>
<circle cx="30.2" cy="33.8" r=".51" fill="#000080"/>
<circle cx="30.2" cy="33.8" r=".51" fill="none" stroke="#000080" stroke-width=".21"/>
<path d="M30.2 125.4v5.1h2.5M42.9 130.5h7.6" fill="none" stroke="#000080" stroke-width=".25"/>
<circle cx="30.2" cy="125.4" r=".51" fill="#000080"/>
<circle cx="30.2" cy="125.4" r=".51" fill="none" stroke="#000080" stroke-width=".21"/>
<path d="M50.5 33.8h-27.9v2.6" fill="none" stroke="#000080" stroke-width=".25"/>
<circle cx="30.2" cy="33.8" r=".51" fill="#000080"/>
<circle cx="30.2" cy="33.8" r=".51" fill="none" stroke="#000080" stroke-width=".21"/>
<circle cx="22.6" cy="33.8" r=".51" fill="#000080"/>
<circle cx="22.6" cy="33.8" r=".51" fill="none" stroke="#000080" stroke-width=".21"/>
<path d="M81.1 38.9h17.8v10.2h15.2" fill="none" stroke="#000080" stroke-width=".25"/>
<circle cx="114.1" cy="49.1" r=".51" fill="#000080"/>
<circle cx="114.1" cy="49.1" r=".51" fill="none" stroke="#000080" stroke-width=".21"/>
<circle cx="106.5" cy="49.1" r=".51" fill="#000080"/>
<circle cx="106.5" cy="49.1" r=".51" fill="none" stroke="#000080" stroke-width=".21"/>
<path d="M98.9 33.8h22.9v2.6" fill="none" stroke="#000080" stroke-width=".25"/>
<circle cx="121.8" cy="33.8" r=".51" fill="#000080"/>
<circle cx="121.8" cy="33.8" r=".51" fill="none" stroke="#000080" stroke-width=".21"/>
<circle cx="114.1" cy="33.8" r=".51" fill="#000080"/>
<circle cx="114.1" cy="33.8" r=".51" fill="none" stroke="#000080" stroke-width=".21"/>
<circle cx="106.5" cy="33.8" r=".51" fill="#000080"/>
<circle cx="106.5" cy="33.8" r=".51" fill="none" stroke="#000080" stroke-width=".21"/>
<path d="M121.8 125.4h15.2" fill="none" stroke="#000080" stroke-width=".25"/>
<circle cx="121.8" cy="125.4" r=".51" fill="#000080"/>
<circle cx="121.8" cy="125.4" r=".51" fill="none" stroke="#000080" stroke-width=".21"/>
<path d="M121.8 33.8h15.2" fill="none" stroke="#000080" stroke-width=".25"/>
<circle cx="121.8" cy="33.8" r=".51" fill="#000080"/>
<circle cx="121.8" cy="33.8" r=".51" fill="none" stroke="#000080" stroke-width=".21"/>
<circle cx="132" cy="33.8" r=".51" fill="#000080"/>
<circle cx="132" cy="33.8" r=".51" fill="none" stroke="#000080" stroke-width=".21"/>
<path d="M114.1 46.5v5.1" fill="none" stroke="#000080" stroke-width=".25"/>
<circle cx="114.1" cy="49.1" r=".51" fill="#000080"/>
<circle cx="114.1" cy="49.1" r=".51" fill="none" stroke="#000080" stroke-width=".21"/>
<path d="M50.5 125.4h-27.9v2.5" fill="none" stroke="#000080" stroke-width=".25"/>
<circle cx="30.2" cy="125.4" r=".51" fill="#000080"/>
<circle cx="30.2" cy="125.4" r=".51" fill="none" stroke="#000080" stroke-width=".21"/>
<circle cx="22.6" cy="125.4" r=".51" fill="#000080"/>
<circle cx="22.6" cy="125.4" r=".51" fill="none" stroke="#000080" stroke-width=".21"/>
<path d="M81.1 130.5h17.8v10.2h15.2" fill="none" stroke="#000080" stroke-width=".25"/>
<circle cx="114.1" cy="140.7" r=".51" fill="#000080"/>
<circle cx="114.1" cy="140.7" r=".51" fill="none" stroke="#000080" stroke-width=".21"/>
<circle cx="106.5" cy="140.7" r=".51" fill="#000080"/>
<circle cx="106.5" cy="140.7" r=".51" fill="none" stroke="#000080" stroke-width=".21"/>
<path d="M98.9 125.4h22.9v2.5" fill="none" stroke="#000080" stroke-width=".25"/>
<circle cx="121.8" cy="125.4" r=".51" fill="#000080"/>
<circle cx="121.8" cy="125.4" r=".51" fill="none" stroke="#000080" stroke-width=".21"/>
<circle cx="114.1" cy="125.4" r=".51" fill="#000080"/>
<circle cx="114.1" cy="125.4" r=".51" fill="none" stroke="#000080" stroke-width=".21"/>
<circle cx="106.5" cy="125.4" r=".51" fill="#000080"/>
<circle cx="106.5" cy="125.4" r=".51" fill="none" stroke="#000080" stroke-width=".21"/>
<path d="M114.1 138.1v5.1" fill="none" stroke="#000080" stroke-width=".25"/>
<circle cx="114.1" cy="140.7" r=".51" fill="#000080"/>
<circle cx="114.1" cy="140.7" r=".51" fill="none" stroke="#000080" stroke-width=".21"/>
<path d="M81.1 79.6h2.5M114.1 79.6v2.5M22.6 92.3v2.6M50.5 89.8h-2.5v5.1M121.8 92.3v2.6" fill="none" stroke="#000080" stroke-width=".25"/>
<circle cx="114.1" cy="79.6" r=".51" fill="#000080"/>
<circle cx="114.1" cy="79.6" r=".51" fill="none" stroke="#000080" stroke-width=".21"/>
<path d="M106.5 79.6v2.5" fill="none" stroke="#000080" stroke-width=".25"/>
<circle cx="106.5" cy="79.6" r=".51" fill="#000080"/>
<circle cx="106.5" cy="79.6" r=".51" fill="none" stroke="#000080" stroke-width=".21"/>
<path d="M106.5 92.3v2.6M114.1 107.6v2.5" fill="none" stroke="#000080" stroke-width=".25"/>
<circle cx="106.5" cy="94.9" r=".51" fill="#000080"/>
<circle cx="106.5" cy="94.9" r=".51" fill="none" stroke="#000080" stroke-width=".21"/>
<path d="M17.5 77.1v2.5h5.1M152.3 77.1v2.5h-5.1M81.1 89.8h10.1" fill="none" stroke="#000080" stroke-width=".25"/>
<circle cx="22.6" cy="79.6" r=".51" fill="#000080"/>
<circle cx="22.6" cy="79.6" r=".51" fill="none" stroke="#000080" stroke-width=".21"/>
<path d="M30.2 79.6v5.1h2.5M42.9 84.7h7.6" fill="none" stroke="#000080" stroke-width=".25"/>
<circle cx="30.2" cy="79.6" r=".51" fill="#000080"/>
<circle cx="30.2" cy="79.6" r=".51" fill="none" stroke="#000080" stroke-width=".21"/>
<path d="M121.8 79.6h15.2" fill="none" stroke="#000080" stroke-width=".25"/>
<circle cx="121.8" cy="79.6" r=".51" fill="#000080"/>
<circle cx="121.8" cy="79.6" r=".51" fill="none" stroke="#000080" stroke-width=".21"/>
<path d="M50.5 79.6h-27.9v2.5" fill="none" stroke="#000080" stroke-width=".25"/>
<circle cx="30.2" cy="79.6" r=".51" fill="#000080"/>
<circle cx="30.2" cy="79.6" r=".51" fill="none" stroke="#000080" stroke-width=".21"/>
<circle cx="22.6" cy="79.6" r=".51" fill="#000080"/>
<circle cx="22.6" cy="79.6" r=".51" fill="none" stroke="#000080" stroke-width=".21"/>
<path d="M81.1 84.7h17.8v10.2h15.2" fill="none" stroke="#000080" stroke-width=".25"/>
<circle cx="114.1" cy="94.9" r=".51" fill="#000080"/>
<circle cx="114.1" cy="94.9" r=".51" fill="none" stroke="#000080" stroke-width=".21"/>
<circle cx="106.5" cy="94.9" r=".51" fill="#000080"/>
<circle cx="106.5" cy="94.9" r=".51" fill="none" stroke="#000080" stroke-width=".21"/>
<path d="M98.9 79.6h22.9v2.5" fill="none" stroke="#000080" stroke-width=".25"/>
<circle cx="121.8" cy="79.6" r=".51" fill="#000080"/>
<circle cx="121.8" cy="79.6" r=".51" fill="none" stroke="#000080" stroke-width=".21"/>
<circle cx="114.1" cy="79.6" r=".51" fill="#000080"/>
<circle cx="114.1" cy="79.6" r=".51" fill="none" stroke="#000080" stroke-width=".21"/>
<circle cx="106.5" cy="79.6" r=".51" fill="#000080"/>
<circle cx="106.5" cy="79.6" r=".51" fill="none" stroke="#000080" stroke-width=".21"/>
<path d="M114.1 92.3v5.1" fill="none" stroke="#000080" stroke-width=".25"/>
<circle cx="114.1" cy="94.9" r=".51" fill="#000080"/>
<circle cx="114.1" cy="94.9" r=".51" fill="none" stroke="#000080" stroke-width=".21"/>
<path d="M200.6 125.4v2.5h2.6" fill="none" stroke="#000080" stroke-width=".25"/>
<circle cx="200.6" cy="125.4" r=".51" fill="#000080"/>
<circle cx="200.6" cy="125.4" r=".51" fill="none" stroke="#000080" stroke-width=".21"/>
<path d="M193 133h7.6" fill="none" stroke="#000080" stroke-width=".25"/>
<circle cx="200.6" cy="133" r=".51" fill="#000080"/>
<circle cx="200.6" cy="133" r=".51" fill="none" stroke="#000080" stroke-width=".21"/>
<path d="M180.3 122.9v2.5h22.9" fill="none" stroke="#000080" stroke-width=".25"/>
<circle cx="185.4" cy="125.4" r=".51" fill="#000080"/>
<circle cx="185.4" cy="125.4" r=".51" fill="none" stroke="#000080" stroke-width=".21"/>
<circle cx="200.6" cy="125.4" r=".51" fill="#000080"/>
<circle cx="200.6" cy="125.4" r=".51" fill="none" stroke="#000080" stroke-width=".21"/>
<path d="M185.4 125.4v10.2" fill="none" stroke="#000080" stroke-width=".25"/>
<circle cx="185.4" cy="125.4" r=".51" fill="#000080"/>
<circle cx="185.4" cy="125.4" r=".51" fill="none" stroke="#000080" stroke-width=".21"/>
<use href="#words"/>
</svg>
